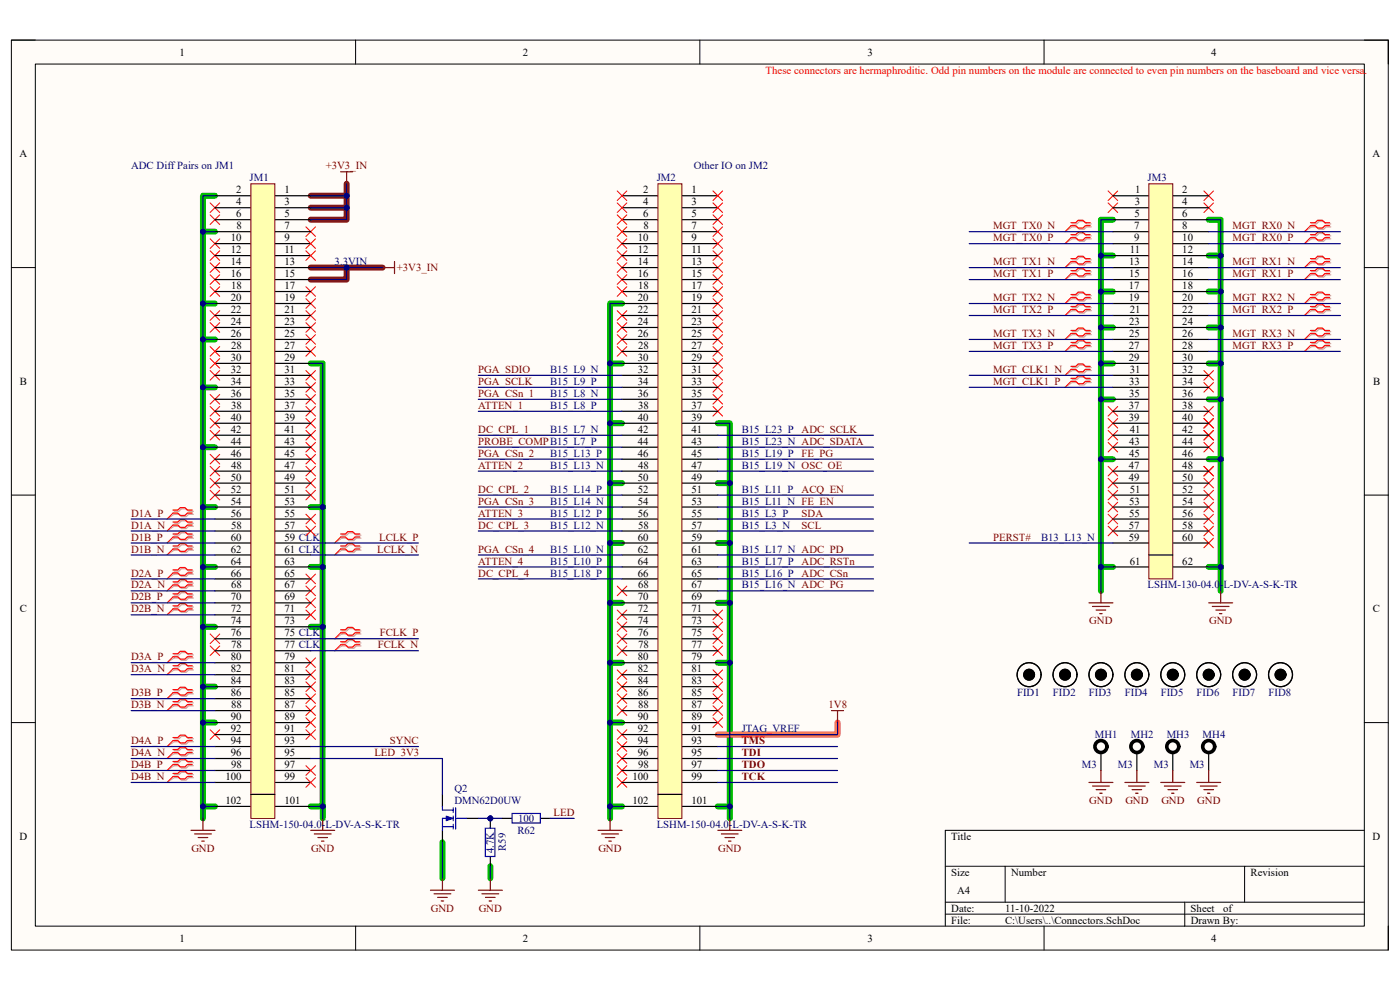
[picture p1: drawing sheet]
<svg xmlns="http://www.w3.org/2000/svg" width="297mm" height="210mm" viewBox="0 0 297 210" stroke-linecap="round" stroke-linejoin="round" font-family="sans-serif">
<defs><g id="words">
<g font-size="2.3">
<text x="38.1" y="11.8">1</text>
<text x="110.9" y="11.8">2</text>
<text x="184" y="11.8">3</text>
<text x="256.9" y="11.8">4</text>
<text x="4.1" y="33.4">A</text>
<text x="291.2" y="33.4">A</text>
<text x="50.1" y="41">2</text>
<text x="60.3" y="41">1</text>
<text x="136.5" y="41">2</text>
<text x="146.7" y="41">1</text>
<text x="240.8" y="41">1</text>
<text x="250.8" y="41">2</text>
<text x="50.1" y="43.6">4</text>
<text x="50.1" y="46.1">6</text>
<text x="60.3" y="43.6">3</text>
<text x="60.3" y="46.1">5</text>
<text x="136.5" y="43.6">4</text>
<text x="136.5" y="46.1">6</text>
<text x="146.7" y="43.6">3</text>
<text x="146.7" y="46.1">5</text>
<text x="240.7" y="46.1">5</text>
<text x="240.7" y="43.6">3</text>
<text x="250.8" y="43.6">4</text>
<text x="250.8" y="46.1">6</text>
<text x="49" y="51.2">10</text>
<text x="49" y="53.7">12</text>
<text x="50.2" y="48.6">8</text>
<text x="60.3" y="48.6">7</text>
<text x="60.3" y="51.2">9</text>
<text x="60.3" y="53.7">11</text>
<text x="135.3" y="51.2">10</text>
<text x="135.3" y="53.7">12</text>
<text x="136.5" y="48.6">8</text>
<text x="146.7" y="48.6">7</text>
<text x="146.7" y="51.2">9</text>
<text x="146.7" y="53.7">11</text>
<text x="239.7" y="53.7">11</text>
<text x="240.6" y="48.6">7</text>
<text x="240.6" y="51.2">9</text>
<text x="250.8" y="48.6">8</text>
<text x="250.8" y="51.2">10</text>
<text x="250.8" y="53.7">12</text>
<text x="49" y="56.3">14</text>
<text x="49" y="58.8">16</text>
<text x="60.3" y="56.3">13</text>
<text x="60.3" y="58.8">15</text>
<text x="135.3" y="56.3">14</text>
<text x="135.3" y="58.8">16</text>
<text x="146.7" y="56.3">13</text>
<text x="146.7" y="58.8">15</text>
<text x="239.6" y="56.3">13</text>
<text x="239.6" y="58.8">15</text>
<text x="250.8" y="56.3">14</text>
<text x="250.8" y="58.8">16</text>
<text x="49" y="63.9">20</text>
<text x="49" y="61.3">18</text>
<text x="60.3" y="61.3">17</text>
<text x="60.3" y="63.9">19</text>
<text x="135.3" y="63.9">20</text>
<text x="135.4" y="61.3">18</text>
<text x="146.7" y="61.3">17</text>
<text x="146.7" y="63.9">19</text>
<text x="239.5" y="61.3">17</text>
<text x="239.5" y="63.9">19</text>
<text x="250.8" y="61.3">18</text>
<text x="250.8" y="63.9">20</text>
<text x="49" y="66.4">22</text>
<text x="49" y="69">24</text>
<text x="49" y="71.5">26</text>
<text x="60.3" y="66.4">21</text>
<text x="60.3" y="69">23</text>
<text x="60.3" y="71.5">25</text>
<text x="135.3" y="66.4">22</text>
<text x="135.3" y="69">24</text>
<text x="135.3" y="71.5">26</text>
<text x="146.7" y="66.4">21</text>
<text x="146.7" y="69">23</text>
<text x="146.7" y="71.5">25</text>
<text x="239.6" y="69">23</text>
<text x="239.6" y="71.5">25</text>
<text x="239.7" y="66.4">21</text>
<text x="250.8" y="66.4">22</text>
<text x="250.8" y="69">24</text>
<text x="250.8" y="71.5">26</text>
<text x="49" y="76.6">30</text>
<text x="49" y="74">28</text>
<text x="60.3" y="74">27</text>
<text x="60.3" y="76.6">29</text>
<text x="135.3" y="76.6">30</text>
<text x="135.4" y="74">28</text>
<text x="146.7" y="74">27</text>
<text x="146.7" y="76.6">29</text>
<text x="239.5" y="74">27</text>
<text x="239.5" y="76.6">29</text>
<text x="250.8" y="74">28</text>
<text x="250.8" y="76.6">30</text>
<text x="4.2" y="81.7">B</text>
<text x="49" y="79.1">32</text>
<text x="49" y="81.7">34</text>
<text x="60.3" y="79.1">31</text>
<text x="60.3" y="81.7">33</text>
<text x="135.3" y="79.1">32</text>
<text x="135.3" y="81.7">34</text>
<text x="146.7" y="79.1">31</text>
<text x="146.7" y="81.7">33</text>
<text x="239.6" y="81.7">33</text>
<text x="239.7" y="79.1">31</text>
<text x="250.8" y="79.1">32</text>
<text x="250.8" y="81.7">34</text>
<text x="291.3" y="81.7">B</text>
<text x="49" y="84.2">36</text>
<text x="49" y="89.3">40</text>
<text x="49" y="86.7">38</text>
<text x="60.3" y="84.2">35</text>
<text x="60.3" y="86.7">37</text>
<text x="60.3" y="89.3">39</text>
<text x="135.3" y="84.2">36</text>
<text x="135.3" y="89.3">40</text>
<text x="135.4" y="86.7">38</text>
<text x="146.7" y="84.2">35</text>
<text x="146.7" y="86.7">37</text>
<text x="146.7" y="89.3">39</text>
<text x="239.5" y="86.7">37</text>
<text x="239.5" y="89.3">39</text>
<text x="239.6" y="84.2">35</text>
<text x="250.8" y="84.2">36</text>
<text x="250.8" y="86.7">38</text>
<text x="250.8" y="89.3">40</text>
<text x="49" y="91.8">42</text>
<text x="49" y="94.4">44</text>
<text x="60.3" y="91.8">41</text>
<text x="60.3" y="94.4">43</text>
<text x="135.3" y="91.8">42</text>
<text x="135.3" y="94.4">44</text>
<text x="146.7" y="91.8">41</text>
<text x="146.7" y="94.4">43</text>
<text x="239.6" y="94.4">43</text>
<text x="239.7" y="91.8">41</text>
<text x="250.8" y="91.8">42</text>
<text x="250.8" y="94.4">44</text>
<text x="49" y="96.9">46</text>
<text x="49" y="102">50</text>
<text x="49" y="99.4">48</text>
<text x="60.3" y="96.9">45</text>
<text x="60.3" y="99.4">47</text>
<text x="60.3" y="102">49</text>
<text x="135.3" y="96.9">46</text>
<text x="135.3" y="102">50</text>
<text x="135.4" y="99.4">48</text>
<text x="146.7" y="96.9">45</text>
<text x="146.7" y="99.4">47</text>
<text x="146.7" y="102">49</text>
<text x="239.5" y="99.4">47</text>
<text x="239.5" y="102">49</text>
<text x="239.6" y="96.9">45</text>
<text x="250.8" y="96.9">46</text>
<text x="250.8" y="99.4">48</text>
<text x="250.8" y="102">50</text>
<text x="49" y="104.5">52</text>
<text x="49" y="107.1">54</text>
<text x="60.3" y="104.5">51</text>
<text x="60.3" y="107.1">53</text>
<text x="135.3" y="104.5">52</text>
<text x="135.3" y="107.1">54</text>
<text x="146.7" y="104.5">51</text>
<text x="146.7" y="107.1">53</text>
<text x="239.6" y="107.1">53</text>
<text x="239.7" y="104.5">51</text>
<text x="250.8" y="104.5">52</text>
<text x="250.8" y="107.1">54</text>
<text x="49" y="109.6">56</text>
<text x="49" y="112.1">58</text>
<text x="60.3" y="109.6">55</text>
<text x="60.3" y="112.1">57</text>
<text x="135.3" y="109.6">56</text>
<text x="135.4" y="112.1">58</text>
<text x="146.7" y="109.6">55</text>
<text x="146.7" y="112.1">57</text>
<text x="239.5" y="112.1">57</text>
<text x="239.6" y="109.6">55</text>
<text x="250.8" y="109.6">56</text>
<text x="250.8" y="112.1">58</text>
<text x="49" y="114.7">60</text>
<text x="49" y="117.2">62</text>
<text x="49" y="119.8">64</text>
<text x="60.3" y="114.7">59 CLK</text>
<text x="60.3" y="117.2">61 CLK</text>
<text x="60.3" y="119.8">63</text>
<text x="135.3" y="114.7">60</text>
<text x="135.3" y="117.2">62</text>
<text x="135.3" y="119.8">64</text>
<text x="146.7" y="114.7">59</text>
<text x="146.7" y="117.2">61</text>
<text x="146.7" y="119.8">63</text>
<text x="239.5" y="114.7">59</text>
<text x="239.7" y="119.8">61</text>
<text x="250.8" y="114.7">60</text>
<text x="250.8" y="119.8">62</text>
<text x="49" y="122.3">66</text>
<text x="49" y="124.8">68</text>
<text x="60.3" y="122.3">65</text>
<text x="60.3" y="124.8">67</text>
<text x="135.3" y="122.3">66</text>
<text x="135.4" y="124.8">68</text>
<text x="146.7" y="122.3">65</text>
<text x="146.7" y="124.8">67</text>
<text x="4.2" y="129.9">C</text>
<text x="49" y="127.4">70</text>
<text x="49" y="129.9">72</text>
<text x="60.3" y="127.4">69</text>
<text x="60.3" y="129.9">71</text>
<text x="135.3" y="127.4">70</text>
<text x="135.3" y="129.9">72</text>
<text x="146.7" y="127.4">69</text>
<text x="146.7" y="129.9">71</text>
<text x="291.3" y="129.9">C</text>
<text x="49" y="132.5">74</text>
<text x="49" y="135">76</text>
<text x="49" y="137.5">78</text>
<text x="60.3" y="132.5">73</text>
<text x="60.3" y="135">75 CLK</text>
<text x="60.3" y="137.5">77 CLK</text>
<text x="135.3" y="132.5">74</text>
<text x="135.3" y="135">76</text>
<text x="135.4" y="137.5">78</text>
<text x="146.7" y="132.5">73</text>
<text x="146.7" y="135">75</text>
<text x="146.7" y="137.5">77</text>
<text x="49" y="140.1">80</text>
<text x="49" y="142.6">82</text>
<text x="60.3" y="140.1">79</text>
<text x="60.3" y="142.6">81</text>
<text x="135.3" y="140.1">80</text>
<text x="135.3" y="142.6">82</text>
<text x="146.7" y="140.1">79</text>
<text x="146.7" y="142.6">81</text>
<text x="49" y="145.2">84</text>
<text x="49" y="147.7">86</text>
<text x="60.3" y="145.2">83</text>
<text x="60.3" y="147.7">85</text>
<text x="135.3" y="145.2">84</text>
<text x="135.3" y="147.7">86</text>
<text x="146.7" y="145.2">83</text>
<text x="146.7" y="147.7">85</text>
<text x="49" y="152.8">90</text>
<text x="49" y="155.3">92</text>
<text x="49" y="150.2">88</text>
<text x="60.3" y="150.2">87</text>
<text x="60.3" y="152.8">89</text>
<text x="60.3" y="155.3">91</text>
<text x="135.3" y="152.8">90</text>
<text x="135.3" y="155.3">92</text>
<text x="135.4" y="150.2">88</text>
<text x="146.7" y="150.2">87</text>
<text x="146.7" y="152.8">89</text>
<text x="146.7" y="155.3">91</text>
<text x="49" y="157.9">94</text>
<text x="49" y="160.4">96</text>
<text x="60.3" y="157.9">93</text>
<text x="60.3" y="160.4">95</text>
<text x="135.3" y="157.9">94</text>
<text x="135.3" y="160.4">96</text>
<text x="146.7" y="157.9">93</text>
<text x="146.7" y="160.4">95</text>
<text x="47.8" y="165.5">100</text>
<text x="49" y="162.9">98</text>
<text x="60.3" y="162.9">97</text>
<text x="60.3" y="165.5">99</text>
<text x="134.2" y="165.5">100</text>
<text x="135.4" y="162.9">98</text>
<text x="146.7" y="162.9">97</text>
<text x="146.7" y="165.5">99</text>
<text x="47.8" y="170.6">102</text>
<text x="60.3" y="170.6">101</text>
<text x="134.2" y="170.6">102</text>
<text x="146.7" y="170.6">101</text>
<text x="4.1" y="178.2">D</text>
<text x="201.8" y="178.2">Title</text>
<text x="291.2" y="178.2">D</text>
<text x="201.8" y="185.8">Size</text>
<text x="214.5" y="185.8">Number</text>
<text x="265.3" y="185.8">Revision</text>
<text x="203.1" y="189.6">A4</text>
<text x="201.8" y="193.4">Date:</text>
<text x="201.8" y="196">File:</text>
<text x="213.2" y="196">C:\Users\..\Connectors.SchDoc</text>
<text x="213.2" y="193.4">11-10-2022</text>
<text x="252.6" y="193.4">Sheet</text>
<text x="252.6" y="196">Drawn By:</text>
<text x="259.5" y="193.4">of</text>
<text x="38.1" y="199.8">1</text>
<text x="110.9" y="199.8">2</text>
<text x="184" y="199.8">3</text>
<text x="256.9" y="199.8">4</text>
</g>
<text font-size="2.3" fill="#f00" x="162.4" y="15.6">These connectors are hermaphroditic. Odd pin numbers on the module are connected to even pin numbers on the baseboard and vice versa.</text>
<g font-size="2.3" fill="#000080">
<text x="27.8" y="35.9">ADC Diff Pairs on JM1</text>
<text x="147.2" y="35.9">Other IO on JM2</text>
<text x="53" y="38.5">JM1</text>
<text x="139.3" y="38.5">JM2</text>
<text x="243.5" y="38.5">JM3</text>
<text x="71" y="56.3">3.3VIN</text>
<text x="116.7" y="79.1">B15_L9_N</text>
<text x="116.7" y="81.7">B15_L9_P</text>
<text x="116.7" y="84.2">B15_L8_N</text>
<text x="116.7" y="86.7">B15_L8_P</text>
<text x="116.7" y="91.8">B15_L7_N</text>
<text x="157.4" y="91.8">B15_L23_P</text>
<text x="157.4" y="94.4">B15_L23_N ADC_SDATA</text>
<text x="116.7" y="96.9">B15_L13_P</text>
<text x="116.7" y="99.4">B15_L13_N</text>
<text x="157.4" y="96.9">B15_L19_P</text>
<text x="157.4" y="99.4">B15_L19_N OSC_OE</text>
<text x="116.7" y="104.5">B15_L14_P</text>
<text x="116.7" y="107.1">B15_L14_N</text>
<text x="157.4" y="104.5">B15_L11_P</text>
<text x="157.4" y="107.1">B15_L11_N FE_EN</text>
<text x="116.7" y="109.6">B15_L12_P</text>
<text x="116.7" y="112.1">B15_L12_N</text>
<text x="157.4" y="109.6">B15_L3_P</text>
<text x="157.4" y="112.1">B15_L3_N</text>
<text x="116.7" y="117.2">B15_L10_N</text>
<text x="116.7" y="119.8">B15_L10_P</text>
<text x="157.4" y="117.2">B15_L17_N ADC_PD</text>
<text x="157.4" y="119.8">B15_L17_P</text>
<text x="220.9" y="114.7">B13_L13_N</text>
<text x="116.7" y="122.3">B15_L18_P</text>
<text x="157.4" y="122.3">B15_L16_P</text>
<text x="157.4" y="124.8">B15_L16_N ADC_PG</text>
<text x="243.5" y="124.8">LSHM-130-04.0-L-DV-A-S-K-TR</text>
<text x="215.8" y="147.7">FID1</text>
<text x="223.4" y="147.7">FID2</text>
<text x="231" y="147.7">FID3</text>
<text x="238.6" y="147.7">FID4</text>
<text x="246.3" y="147.7">FID5</text>
<text x="253.9" y="147.7">FID6</text>
<text x="261.5" y="147.7">FID7</text>
<text x="269.1" y="147.7">FID8</text>
<text x="157.4" y="155.3">JTAG_VREF</text>
<text x="232.3" y="156.6">MH1</text>
<text x="239.9" y="156.6">MH2</text>
<text x="247.5" y="156.6">MH3</text>
<text x="255.1" y="156.6">MH4</text>
<text x="229.5" y="162.9">M3</text>
<text x="237.2" y="162.9">M3</text>
<text x="244.8" y="162.9">M3</text>
<text x="252.4" y="162.9">M3</text>
<text x="96.4" y="168">Q2</text>
<text x="96.4" y="170.6">DMN62D0UW</text>
<text x="53" y="175.6">LSHM-150-04.0-L-DV-A-S-K-TR</text>
<text x="109.8" y="176.9">R62</text>
<text x="109.9" y="174.4">100</text>
<text x="139.3" y="175.6">LSHM-150-04.0-L-DV-A-S-K-TR</text>
<text x="104.8" y="181" transform="rotate(-90 104.8 181)">4.7K</text>
<text x="107.3" y="180.6" transform="rotate(-90 107.3 180.6)">R59</text>
</g>
<g font-size="2.3" fill="#800000">
<text x="69.1" y="35.9">+3V3_IN</text>
<text x="210.7" y="48.6">MGT_TX0_N</text>
<text x="210.7" y="51.2">MGT_TX0_P</text>
<text x="261.5" y="48.6">MGT_RX0_N</text>
<text x="261.5" y="51.2">MGT_RX0_P</text>
<text x="84.2" y="57.5">+3V3_IN</text>
<text x="210.7" y="56.3">MGT_TX1_N</text>
<text x="210.7" y="58.8">MGT_TX1_P</text>
<text x="261.5" y="56.3">MGT_RX1_N</text>
<text x="261.5" y="58.8">MGT_RX1_P</text>
<text x="210.7" y="63.9">MGT_TX2_N</text>
<text x="261.5" y="63.9">MGT_RX2_N</text>
<text x="210.7" y="71.5">MGT_TX3_N</text>
<text x="210.7" y="66.4">MGT_TX2_P</text>
<text x="261.5" y="66.4">MGT_RX2_P</text>
<text x="261.5" y="71.5">MGT_RX3_N</text>
<text x="210.7" y="74">MGT_TX3_P</text>
<text x="261.5" y="74">MGT_RX3_P</text>
<text x="101.5" y="79.1">PGA_SDIO</text>
<text x="101.5" y="81.7">PGA_SCLK</text>
<text x="210.7" y="79.1">MGT_CLK1_N</text>
<text x="210.7" y="81.7">MGT_CLK1_P</text>
<text x="101.5" y="84.2">PGA_CSn_1</text>
<text x="101.5" y="86.7">ATTEN_1</text>
<text x="101.5" y="91.8">DC_CPL_1</text>
<text x="101.5" y="94.4">PROBE_COMPB15_L7_P</text>
<text x="170.1" y="91.8">ADC_SCLK</text>
<text x="101.5" y="96.9">PGA_CSn_2</text>
<text x="101.5" y="99.4">ATTEN_2</text>
<text x="170.1" y="96.9">FE_PG</text>
<text x="101.5" y="104.5">DC_CPL_2</text>
<text x="101.5" y="107.1">PGA_CSn_3</text>
<text x="170.1" y="104.5">ACQ_EN</text>
<text x="27.8" y="109.6">D1A_P</text>
<text x="27.8" y="112.1">D1A_N</text>
<text x="101.5" y="109.6">ATTEN_3</text>
<text x="101.5" y="112.1">DC_CPL_3</text>
<text x="170.1" y="109.6">SDA</text>
<text x="170.1" y="112.1">SCL</text>
<text x="27.8" y="114.7">D1B_P</text>
<text x="27.8" y="117.2">D1B_N</text>
<text x="80" y="117.2">LCLK_N</text>
<text x="80.4" y="114.7">LCLK_P</text>
<text x="101.5" y="117.2">PGA_CSn_4</text>
<text x="101.5" y="119.8">ATTEN_4</text>
<text x="170.1" y="119.8">ADC_RSTn</text>
<text x="210.7" y="114.7">PERST#</text>
<text x="27.8" y="122.3">D2A_P</text>
<text x="27.8" y="124.8">D2A_N</text>
<text x="101.5" y="122.3">DC_CPL_4</text>
<text x="170.1" y="122.3">ADC_CSn</text>
<text x="27.8" y="127.4">D2B_P</text>
<text x="27.8" y="129.9">D2B_N</text>
<text x="80.1" y="137.5">FCLK_N</text>
<text x="80.6" y="135">FCLK_P</text>
<text x="231.1" y="132.5">GND</text>
<text x="256.5" y="132.5">GND</text>
<text x="27.8" y="140.1">D3A_P</text>
<text x="27.8" y="142.6">D3A_N</text>
<text x="27.8" y="147.7">D3B_P</text>
<text x="27.8" y="150.2">D3B_N</text>
<text x="175.8" y="150.2">1V8</text>
<text x="27.8" y="157.9">D4A_P</text>
<text x="27.8" y="160.4">D4A_N</text>
<text x="79.4" y="160.4">LED_3V3</text>
<text x="82.7" y="157.9">SYNC</text>
<text x="157.4" y="160.4">TDI</text>
<text x="157.4" y="157.9">TMS</text>
<text x="27.8" y="162.9">D4B_P</text>
<text x="27.8" y="165.5">D4B_N</text>
<text x="157.4" y="165.5">TCK</text>
<text x="157.4" y="162.9">TDO</text>
<text x="117.4" y="173.1">LED</text>
<text x="231.1" y="170.6">GND</text>
<text x="238.8" y="170.6">GND</text>
<text x="246.4" y="170.6">GND</text>
<text x="254" y="170.6">GND</text>
<text x="40.6" y="180.7">GND</text>
<text x="66" y="180.7">GND</text>
<text x="127" y="180.7">GND</text>
<text x="152.4" y="180.7">GND</text>
<text x="91.4" y="193.4">GND</text>
<text x="101.6" y="193.4">GND</text>
</g>
</g></defs>
<path d="M2.4 8.5h292.1v193h-292.1z" fill-rule="evenodd" fill="#fffcf8"/>
<path d="M2.4 8.5h292.1v193h-292.1z" fill="none" stroke="#000" stroke-width=".21"/>
<path d="M7.5 13.6h281.9v182.9h-281.9z" fill-rule="evenodd" fill="#fffcf8"/>
<g fill="none" stroke="#000" stroke-width=".21">
<path d="M2.4 8.5h5.1M7.5 13.6h281.9v182.9h-281.9zM75.4 8.5v5.1M148.5 8.5v5.1M221.5 8.5v5.1M289.4 8.5h5.1v5.1M2.4 56.8h5.1M289.4 56.8h5.1M2.4 105h5.1M289.4 105h5.1M2.4 153.3h5.1M289.4 153.3h5.1"/>
<path d="M289.4 176.1h-88.9v20.4M75.4 196.5v5M148.5 196.5v5M200.5 183.8h88.9M200.5 191.4h88.9M200.5 193.9h88.9M213.2 183.8v7.6M221.5 196.5v5M251.3 191.4v5.1M264 183.8v7.6M294.5 196.5v5"/>
</g>
<g fill="none" stroke="#00be00" stroke-width="1.3">
<path d="M43.1 49.1h2.5M45.6 41.5h-2.5v129.6M233.6 54.2h2.5M236.1 46.6h-2.5v73.7M256.4 54.2h2.6M256.4 46.6h2.6v73.7M43.1 64.4h2.5M43.1 72h2.5M65.9 77.1h2.6v30.5h-2.6M129.4 77.1h2.6M132 64.4h-2.6v106.7M233.6 77.1h2.5"/>
<path d="M233.6 61.8h2.5M233.6 69.5h2.5M256.4 77.1h2.6M256.4 61.8h2.6M256.4 69.5h2.6M43.1 82.2h2.5M43.1 94.9h2.5M129.4 89.8h2.6M152.3 89.8h2.5v81.3M233.6 84.7h2.5M233.6 97.4h2.5M256.4 84.7h2.6"/>
<path d="M256.4 97.4h2.6M43.1 107.6h2.5M68.5 107.6v12.7h-2.6M129.4 102.5h2.6M129.4 115.2h2.6M152.3 102.5h2.5M152.3 115.2h2.5M43.1 120.3h2.5M43.1 133h2.5M68.5 120.3v12.7h-2.6M68.5 133v38.1M129.4 127.9h2.6"/>
<path d="M152.3 127.9h2.5M236.1 120.3h-2.5v5M256.4 120.3h2.6v5M43.1 145.7h2.5M43.1 153.3h2.5M129.4 153.3h2.6M129.4 140.6h2.6M152.3 140.6h2.5M45.6 171.1h-2.5v2.5M65.9 171.1h2.6v2.5M93.9 178.7v7.6M132 171.1h-2.6v2.5"/>
<path d="M152.3 171.1h2.5v2.5M104 183.8v2.5"/>
</g>
<path d="M73.5 39v7.6h-7.6M65.9 56.8h15.3M65.9 44.1h7.6M65.9 41.5h7.6M73.5 56.8v2.5h-7.6" fill="none" stroke="#781915" stroke-width="1.3"/>
<path d="M177.7 153.3v2.5h-25.4" fill="none" stroke="#fd8300" stroke-width="1.3"/>
<g fill="none" stroke="#800000" stroke-width=".25">
<path d="M72.3 36.4h2.5M73.5 36.4v2.6M231 127.9h5.1M231.8 128.7h3.5M232.5 129.4h2.1M233.3 130.2h.5M233.6 125.3v2.6M256.4 127.9h5.1M257.2 128.7h3.5M257.9 129.4h2.1M258.7 130.2h.5M259 125.3v2.6"/>
<path d="M40.5 176.1h5.1M41.3 176.9h3.5M42 177.7h2.1M42.8 178.4h.5M43.1 173.6v2.5M65.9 176.1h5.1M66.7 176.9h3.5M67.4 177.7h2.1M68.2 178.4h.5M68.5 173.6v2.5M126.9 176.1h5.1M127.6 176.9h3.6"/>
<path d="M128.4 177.7h2M129.2 178.4h.5M129.4 173.6v2.5M152.3 176.1h5.1M153 176.9h3.6M153.8 177.7h2M154.6 178.4h.5M154.8 173.6v2.5"/>
</g>
<g fill="none" stroke="#f00" stroke-width=".21">
<path d="M44.6 43l2 2.1M44.6 45.6l2 2M44.6 50.7l2 2M44.6 53.2l2 2M44.6 58.3l2 2M44.6 55.7l2 2.1M46.6 43l-2 2.1M46.6 45.6l-2 2M46.6 50.7l-2 2M46.6 53.2l-2 2M46.6 58.3l-2 2M46.6 55.7l-2 2.1"/>
<path d="M64.9 48.1l2 2.1M66.9 48.1l-2 2.1M130.9 50.7l2.1 2M130.9 55.7l2.1 2.1M130.9 58.3l2.1 2M130.9 53.2l2.1 2M133 50.7l-2.1 2M133 55.7l-2.1 2.1M133 58.3l-2.1 2M133 53.2l-2.1 2M151.3 45.6l2 2M151.3 53.2l2 2"/>
<path d="M151.3 55.7l2 2.1M151.3 58.3l2 2M153.3 53.2l-2 2M153.3 45.6l-2 2M153.3 55.7l-2 2.1M153.3 58.3l-2 2M227.2 47.9l-1.3 1.2M235.1 40.5l2 2M235.1 43.1l2 2M237.1 40.5l-2 2M237.1 43.1l-2 2M255.4 40.5l2 2"/>
<path d="M255.4 43.1l2 2M257.4 40.5l-2 2M257.4 43.1l-2 2M44.6 60.8l2 2.1M44.6 65.9l2 2M44.6 68.5l2 2M44.6 78.6l2 2M46.6 60.8l-2 2.1M46.6 65.9l-2 2M46.6 68.5l-2 2M46.6 78.6l-2 2M64.9 60.8l2 2.1"/>
<path d="M64.9 63.4l2 2M64.9 65.9l2 2M64.9 68.5l2 2M64.9 71l2 2M64.9 73.5l2 2.1M64.9 78.6l2 2M66.9 60.8l-2 2.1M66.9 63.4l-2 2M66.9 65.9l-2 2M66.9 68.5l-2 2M66.9 71l-2 2M66.9 73.5l-2 2.1"/>
<path d="M66.9 78.6l-2 2M130.9 65.9l2.1 2M130.9 68.5l2.1 2M130.9 71l2.1 2M130.9 73.5l2.1 2.1M133 73.5l-2.1 2.1M133 65.9l-2.1 2M133 68.5l-2.1 2M133 71l-2.1 2M151.3 63.4l2 2M151.3 76.1l2 2M151.3 60.8l2 2.1"/>
<path d="M151.3 65.9l2 2M151.3 68.5l2 2M151.3 71l2 2M151.3 73.5l2 2.1M151.3 78.6l2 2M153.3 63.4l-2 2M153.3 76.1l-2 2M153.3 60.8l-2 2.1M153.3 65.9l-2 2M153.3 68.5l-2 2M153.3 71l-2 2M153.3 73.5l-2 2.1"/>
<path d="M153.3 78.6l-2 2M255.4 78.6l2 2M257.4 78.6l-2 2M44.6 83.7l2 2M44.6 86.2l2 2.1M44.6 88.8l2 2M44.6 91.3l2 2M44.6 96.4l2 2M44.6 98.9l2 2.1M46.6 83.7l-2 2M46.6 86.2l-2 2.1M46.6 88.8l-2 2"/>
<path d="M46.6 91.3l-2 2M46.6 96.4l-2 2M46.6 98.9l-2 2.1M64.9 81.2l2 2M64.9 83.7l2 2M64.9 88.8l2 2M64.9 86.2l2 2.1M64.9 91.3l2 2M64.9 93.9l2 2M64.9 96.4l2 2M64.9 98.9l2 2.1M66.9 81.2l-2 2"/>
<path d="M66.9 83.7l-2 2M66.9 88.8l-2 2M66.9 86.2l-2 2.1M66.9 91.3l-2 2M66.9 93.9l-2 2M66.9 96.4l-2 2M66.9 98.9l-2 2.1M151.3 86.2l2 2.1M151.3 81.2l2 2M151.3 83.7l2 2M153.3 81.2l-2 2M153.3 83.7l-2 2"/>
<path d="M153.3 86.2l-2 2.1M235.1 86.2l2 2.1M235.1 88.8l2 2M235.1 91.3l2 2M235.1 93.9l2 2M235.1 98.9l2 2.1M237.1 86.2l-2 2.1M237.1 88.8l-2 2M237.1 91.3l-2 2M237.1 93.9l-2 2M237.1 98.9l-2 2.1M255.4 86.2l2 2.1"/>
<path d="M255.4 88.8l2 2M255.4 91.3l2 2M255.4 93.9l2 2M255.4 98.9l2 2.1M255.4 81.2l2 2M257.4 88.8l-2 2M257.4 81.2l-2 2M257.4 86.2l-2 2.1M257.4 91.3l-2 2M257.4 93.9l-2 2M257.4 98.9l-2 2.1M44.6 101.5l2 2"/>
<path d="M44.6 104l2 2M46.6 101.5l-2 2M46.6 104l-2 2M64.9 109.1l2 2M64.9 111.6l2 2.1M64.9 101.5l2 2M64.9 104l2 2M66.9 101.5l-2 2M66.9 104l-2 2M66.9 109.1l-2 2M66.9 111.6l-2 2.1M235.1 109.1l2 2"/>
<path d="M235.1 101.5l2 2M235.1 104l2 2M235.1 106.6l2 2M237.1 109.1l-2 2M237.1 101.5l-2 2M237.1 104l-2 2M237.1 106.6l-2 2M255.4 109.1l2 2M255.4 111.6l2 2.1M255.4 114.2l2 2M255.4 101.5l2 2M255.4 106.6l2 2"/>
<path d="M255.4 104l2 2M257.4 109.1l-2 2M257.4 111.6l-2 2.1M257.4 114.2l-2 2M257.4 101.5l-2 2M257.4 106.6l-2 2M257.4 104l-2 2M44.6 134.5l2 2M44.6 137l2 2.1M46.6 134.5l-2 2M46.6 137l-2 2.1M64.9 139.6l2 2"/>
<path d="M64.9 121.8l2 2M64.9 124.3l2 2.1M64.9 126.9l2 2M66.9 139.6l-2 2M66.9 121.8l-2 2M66.9 124.3l-2 2.1M66.9 126.9l-2 2M130.9 124.3l2.1 2.1M130.9 129.4l2.1 2M130.9 132l2.1 2M130.9 134.5l2.1 2M130.9 137l2.1 2.1"/>
<path d="M133 124.3l-2.1 2.1M133 129.4l-2.1 2M133 132l-2.1 2M133 134.5l-2.1 2M133 137l-2.1 2.1M151.3 129.4l2 2M151.3 132l2 2M151.3 134.5l2 2M151.3 137l2 2.1M153.3 129.4l-2 2M153.3 134.5l-2 2M153.3 137l-2 2.1"/>
<path d="M153.3 132l-2 2M44.6 154.8l2 2M46.6 154.8l-2 2M64.9 142.1l2 2M64.9 144.7l2 2M64.9 147.2l2 2M64.9 149.7l2 2.1M66.9 142.1l-2 2M66.9 144.7l-2 2M66.9 147.2l-2 2M66.9 149.7l-2 2.1M130.9 142.1l2.1 2"/>
<path d="M130.9 144.7l2.1 2M130.9 147.2l2.1 2M130.9 149.7l2.1 2.1M130.9 154.8l2.1 2M130.9 157.4l2.1 2M130.9 159.9l2.1 2M133 142.1l-2.1 2M133 144.7l-2.1 2M133 147.2l-2.1 2M133 149.7l-2.1 2.1M133 154.8l-2.1 2M133 157.4l-2.1 2"/>
<path d="M133 159.9l-2.1 2M151.3 144.7l2 2M151.3 149.7l2 2.1M151.3 142.1l2 2M151.3 147.2l2 2M153.3 142.1l-2 2M153.3 144.7l-2 2M153.3 147.2l-2 2M153.3 149.7l-2 2.1M130.9 162.4l2.1 2.1M130.9 165l2.1 2M133 162.4l-2.1 2.1"/>
<path d="M133 165l-2.1 2"/>
</g>
<path d="M227.5 47.5h1l.5-.5h1l.5 .5h1M227.5 48.1h1l.5 .5h1l.5-.5h1" fill="none" stroke="#d0a19e" stroke-width=".25"/>
<path d="M227.5 48.1l-1.6 1" fill="none" stroke="#d0a19e" stroke-width=".21"/>
<path d="M227.2 47.2h1l.5-.5h1.1l.5 .5h1M227.2 47.9h1l.5 .5h1.1l.5-.5h1" fill="none" stroke="#f00" stroke-width=".25"/>
<g fill="none" stroke="#000" stroke-width=".25">
<path d="M45.6 41.5h7.6M45.6 44.1h7.6M45.6 46.6h7.6M45.6 49.1h7.6M45.6 51.7h7.6M45.6 54.2h7.6M45.6 56.8h7.6M45.6 59.3h7.6M58.3 41.5h7.6M58.3 44.1h7.6M58.3 46.6h7.6M58.3 49.1h7.6"/>
<path d="M58.3 51.7h7.6M58.3 54.2h7.6M58.3 56.8h7.6M58.3 59.3h7.6M45.6 61.8h7.6M45.6 64.4h7.6M45.6 66.9h7.6M45.6 69.5h7.6M45.6 72h7.6M45.6 74.5h7.6M45.6 77.1h7.6M45.6 79.6h7.6"/>
<path d="M58.3 61.8h7.6M58.3 64.4h7.6M58.3 66.9h7.6M58.3 69.5h7.6M58.3 72h7.6M58.3 74.5h7.6M58.3 77.1h7.6M58.3 79.6h7.6M45.6 82.2h7.6M45.6 84.7h7.6M45.6 87.2h7.6M45.6 89.8h7.6"/>
<path d="M45.6 92.3h7.6M45.6 94.9h7.6M45.6 97.4h7.6M45.6 99.9h7.6M58.3 82.2h7.6M58.3 84.7h7.6M58.3 87.2h7.6M58.3 89.8h7.6M58.3 92.3h7.6M58.3 94.9h7.6M58.3 97.4h7.6M58.3 99.9h7.6"/>
<path d="M45.6 102.5h7.6M45.6 105h7.6M45.6 107.6h7.6M45.6 110.1h7.6M45.6 112.6h7.6M45.6 115.2h7.6M45.6 117.7h7.6M58.3 102.5h7.6M58.3 105h7.6M58.3 107.6h7.6M58.3 110.1h7.6M58.3 112.6h7.6"/>
<path d="M58.3 115.2h7.6M58.3 117.7h7.6M45.6 120.3h7.6M45.6 122.8h7.6M45.6 125.3h7.6M45.6 127.9h7.6M45.6 130.4h7.6M45.6 133h7.6M45.6 135.5h7.6M45.6 138h7.6M58.3 120.3h7.6M58.3 122.8h7.6"/>
<path d="M58.3 125.3h7.6M58.3 127.9h7.6M58.3 130.4h7.6M58.3 133h7.6M58.3 135.5h7.6M58.3 138h7.6M45.6 140.6h7.6M45.6 143.1h7.6M45.6 145.7h7.6M45.6 148.2h7.6M45.6 150.7h7.6M45.6 153.3h7.6"/>
<path d="M45.6 155.8h7.6M45.6 158.4h7.6M58.3 140.6h7.6M58.3 143.1h7.6M58.3 145.7h7.6M58.3 148.2h7.6M58.3 150.7h7.6M58.3 153.3h7.6M58.3 155.8h7.6M58.3 158.4h7.6M45.6 160.9h7.6M45.6 163.4h7.6"/>
<path d="M45.6 166h7.6M45.6 171.1h7.6M58.3 160.9h7.6M58.3 163.4h7.6M58.3 166h7.6M58.3 171.1h7.6"/>
</g>
<path d="M53.2 39h5.1v134.6h-5.1z" fill-rule="evenodd" fill="#ffffb0"/>
<path d="M53.2 39h5.1v134.6h-5.1z" fill="none" stroke="#800000" stroke-width=".21"/>
<g fill="none" stroke="#000" stroke-width=".25">
<path d="M132 41.5h7.6M132 44.1h7.6M132 46.6h7.6M132 49.1h7.6M132 51.7h7.6M132 54.2h7.6M132 56.8h7.6M132 59.3h7.6M144.7 41.5h7.6M144.7 44.1h7.6M144.7 46.6h7.6M144.7 49.1h7.6"/>
<path d="M144.7 51.7h7.6M144.7 54.2h7.6M144.7 56.8h7.6M144.7 59.3h7.6M132 61.8h7.6M132 64.4h7.6M132 66.9h7.6M132 69.5h7.6M132 72h7.6M132 74.5h7.6M132 77.1h7.6M132 79.6h7.6"/>
<path d="M144.7 61.8h7.6M144.7 64.4h7.6M144.7 66.9h7.6M144.7 69.5h7.6M144.7 72h7.6M144.7 74.5h7.6M144.7 77.1h7.6M144.7 79.6h7.6M132 82.2h7.6M132 84.7h7.6M132 87.2h7.6M132 89.8h7.6"/>
<path d="M132 92.3h7.6M132 94.9h7.6M132 97.4h7.6M132 99.9h7.6M144.7 82.2h7.6M144.7 84.7h7.6M144.7 87.2h7.6M144.7 89.8h7.6M144.7 92.3h7.6M144.7 94.9h7.6M144.7 97.4h7.6M144.7 99.9h7.6"/>
<path d="M132 102.5h7.6M132 105h7.6M132 107.6h7.6M132 110.1h7.6M132 112.6h7.6M132 115.2h7.6M132 117.7h7.6M144.7 102.5h7.6M144.7 105h7.6M144.7 107.6h7.6M144.7 110.1h7.6M144.7 112.6h7.6"/>
<path d="M144.7 115.2h7.6M144.7 117.7h7.6M132 120.3h7.6M132 122.8h7.6M132 125.3h7.6M132 127.9h7.6M132 130.4h7.6M132 133h7.6M132 135.5h7.6M132 138h7.6M144.7 120.3h7.6M144.7 122.8h7.6"/>
<path d="M144.7 125.3h7.6M144.7 127.9h7.6M144.7 130.4h7.6M144.7 133h7.6M144.7 135.5h7.6M144.7 138h7.6M132 140.6h7.6M132 143.1h7.6M132 145.7h7.6M132 148.2h7.6M132 150.7h7.6M132 153.3h7.6"/>
<path d="M132 155.8h7.6M132 158.4h7.6M144.7 140.6h7.6M144.7 143.1h7.6M144.7 145.7h7.6M144.7 148.2h7.6M144.7 150.7h7.6M144.7 153.3h7.6M144.7 155.8h7.6M144.7 158.4h7.6M53.2 168.5h5.1M132 160.9h7.6"/>
<path d="M132 163.4h7.6M132 166h7.6M132 171.1h7.6M144.7 160.9h7.6M144.7 163.4h7.6M144.7 166h7.6M144.7 171.1h7.6"/>
</g>
<path d="M139.6 39h5.1v134.6h-5.1z" fill-rule="evenodd" fill="#ffffb0"/>
<path d="M139.6 39h5.1v134.6h-5.1z" fill="none" stroke="#800000" stroke-width=".21"/>
<g fill="none" stroke="#000" stroke-width=".25">
<path d="M236.1 41.5h7.6M236.1 44.1h7.6M236.1 46.6h7.6M236.1 49.1h7.6M236.1 51.7h7.6M236.1 54.2h7.6M236.1 56.8h7.6M236.1 59.3h7.6M248.8 41.5h7.6M248.8 44.1h7.6M248.8 46.6h7.6M248.8 49.1h7.6"/>
<path d="M248.8 51.7h7.6M248.8 54.2h7.6M248.8 56.8h7.6M248.8 59.3h7.6M236.1 61.8h7.6M236.1 64.4h7.6M236.1 66.9h7.6M236.1 69.5h7.6M236.1 72h7.6M236.1 74.5h7.6M236.1 77.1h7.6M236.1 79.6h7.6"/>
<path d="M248.8 61.8h7.6M248.8 64.4h7.6M248.8 66.9h7.6M248.8 69.5h7.6M248.8 72h7.6M248.8 74.5h7.6M248.8 77.1h7.6M248.8 79.6h7.6M236.1 82.2h7.6M236.1 84.7h7.6M236.1 87.2h7.6M236.1 89.8h7.6"/>
<path d="M236.1 92.3h7.6M236.1 94.9h7.6M236.1 97.4h7.6M236.1 99.9h7.6M248.8 82.2h7.6M248.8 84.7h7.6M248.8 87.2h7.6M248.8 89.8h7.6M248.8 92.3h7.6M248.8 94.9h7.6M248.8 97.4h7.6M248.8 99.9h7.6"/>
<path d="M236.1 102.5h7.6M236.1 105h7.6M236.1 107.6h7.6M236.1 110.1h7.6M236.1 112.6h7.6M236.1 115.2h7.6M248.8 102.5h7.6M248.8 105h7.6M248.8 107.6h7.6M248.8 110.1h7.6M248.8 112.6h7.6M248.8 115.2h7.6"/>
<path d="M236.1 120.3h7.6M248.8 120.3h7.6M233.6 159.6v3.8M241.2 159.6v3.8M248.8 159.6v3.8M256.4 159.6v3.8M139.6 168.5h5.1"/>
</g>
<g fill="none" stroke="#f00" stroke-width=".21">
<path d="M64.9 50.7l2 2M64.9 53.2l2 2M66.9 50.7l-2 2M66.9 53.2l-2 2M255.4 88.8l2 2M255.4 91.3l2 2M255.4 98.9l2 2.1M257.4 91.3l-2 2M257.4 88.8l-2 2M257.4 98.9l-2 2.1M235.1 111.6l2 2.1M237.1 111.6l-2 2.1"/>
<path d="M64.9 129.4l2 2M66.9 129.4l-2 2M64.9 154.8l2 2M66.9 154.8l-2 2M151.3 152.3l2 2M153.3 152.3l-2 2"/>
</g>
<g fill="none" stroke="#000" stroke-width=".76">
<circle cx="233.6" cy="158.4" r="1.27"/>
<circle cx="241.2" cy="158.4" r="1.27"/>
<circle cx="248.8" cy="158.4" r="1.27"/>
<circle cx="256.4" cy="158.4" r="1.27"/>
</g>
<g fill="none" stroke="#800000" stroke-width=".25">
<path d="M231 166h5.1M231.8 166.8h3.5M232.5 167.5h2.1M233.3 168.3h.5M233.6 163.4v2.6M238.6 166h5.1M239.4 166.8h3.6M240.2 167.5h2M240.9 168.3h.5M241.2 163.4v2.6M246.3 166h5M247 166.8h3.6"/>
<path d="M247.8 167.5h2M248.5 168.3h.6M248.8 163.4v2.6M253.9 166h5.1M254.6 166.8h3.6M255.4 167.5h2M256.2 168.3h.5M256.4 163.4v2.6"/>
</g>
<path d="M243.7 39h5.1v83.8h-5.1z" fill-rule="evenodd" fill="#ffffb0"/>
<path d="M243.7 39h5.1v83.8h-5.1z" fill="none" stroke="#800000" stroke-width=".21"/>
<g fill="none" stroke="#000" stroke-width=".25">
<path d="M243.7 117.7h5.1M93.9 168.5v2.6M93.9 176.1v2.6M98.9 173.6h2.6"/>
<circle cx="218.3" cy="143.1" r="2.54"/>
<circle cx="225.9" cy="143.1" r="2.54"/>
<circle cx="233.6" cy="143.1" r="2.54"/>
<circle cx="241.2" cy="143.1" r="2.54"/>
<circle cx="248.8" cy="143.1" r="2.54"/>
<circle cx="256.4" cy="143.1" r="2.54"/>
<circle cx="264" cy="143.1" r="2.54"/>
<circle cx="271.7" cy="143.1" r="2.54"/>
</g>
<g fill="none" stroke="#f00" stroke-width=".21">
<path d="M130.9 48.1l2.1 2.1M130.9 45.6l2.1 2M130.9 43l2.1 2.1M130.9 40.5l2.1 2M133 43l-2.1 2.1M133 48.1l-2.1 2.1M133 45.6l-2.1 2M133 40.5l-2.1 2M151.3 48.1l2 2.1M151.3 50.7l2 2M151.3 40.5l2 2M151.3 43l2 2.1"/>
<path d="M153.3 40.5l-2 2M153.3 48.1l-2 2.1M153.3 50.7l-2 2M153.3 43l-2 2.1M227.2 50.4l-1.3 1.3M227.2 55.5l-1.3 1.3M227.2 58l-1.3 1.3M278 47.9l-1.3 1.2M278 50.4l-1.3 1.3M278 55.5l-1.3 1.3M278 58l-1.3 1.3M44.6 73.5l2 2.1"/>
<path d="M44.6 76.1l2 2M46.6 73.5l-2 2.1M46.6 76.1l-2 2M130.9 60.8l2.1 2.1M133 60.8l-2.1 2.1M227.2 63.1l-1.3 1.3M227.2 65.7l-1.3 1.2M227.2 70.7l-1.3 1.3M227.2 73.3l-1.3 1.2M227.2 78.4l-1.3 1.2M278 63.1l-1.3 1.3M278 65.7l-1.3 1.2"/>
<path d="M278 70.7l-1.3 1.3M278 73.3l-1.3 1.2M227.2 80.9l-1.3 1.3M36.7 108.8l-1.3 1.3M36.7 111.4l-1.3 1.2M36.7 113.9l-1.3 1.3M36.7 116.5l-1.3 1.2M72.3 113.9l-1.3 1.3M72.3 116.5l-1.3 1.2M36.7 121.5l-1.3 1.3M36.7 124.1l-1.3 1.2M36.7 126.6l-1.3 1.3"/>
<path d="M36.7 129.2l-1.3 1.2M36.7 139.3l-1.3 1.3M72.3 134.2l-1.3 1.3M72.3 136.8l-1.3 1.2M36.7 157.1l-1.3 1.3M36.7 141.9l-1.3 1.2M36.7 146.9l-1.3 1.3M36.7 149.5l-1.3 1.2M36.7 159.6l-1.3 1.3M64.9 152.3l2 2M66.9 152.3l-2 2M36.7 162.2l-1.3 1.2"/>
<path d="M36.7 164.7l-1.3 1.3"/>
</g>
<path d="M81.2 56.8h2.5M83.7 55.5v2.5M176.4 150.7h2.6M177.7 150.7v2.6" fill="none" stroke="#800000" stroke-width=".25"/>
<g fill="none" stroke="#d0a19e" stroke-width=".25">
<path d="M227.5 50h1l.5-.5h1l.5 .5h1M227.5 50.7h1l.5 .5h1l.5-.5h1M227.5 55.1h1l.5-.5h1l.5 .5h1M227.5 55.8h1l.5 .5h1l.5-.5h1M227.5 57.7h1l.5-.6h1l.5 .6h1M227.5 58.3h1l.5 .5h1l.5-.5h1M278.3 47.5h1l.5-.5h1l.5 .5h1M278.3 48.1h1l.5 .5h1l.5-.5h1M278.3 50h1l.5-.5h1l.5 .5h1M278.3 50.7h1l.5 .5h1l.5-.5h1M278.3 55.1h1l.5-.5h1l.5 .5h1M278.3 55.8h1l.5 .5h1l.5-.5h1"/>
<path d="M278.3 57.7h1l.5-.6h1l.5 .6h1M278.3 58.3h1l.5 .5h1l.5-.5h1M227.5 62.7h1l.5-.5h1l.5 .5h1M227.5 63.4h1l.5 .5h1l.5-.5h1M227.5 65.3h1l.5-.5h1l.5 .5h1M227.5 65.9h1l.5 .5h1l.5-.5h1M227.5 70.4h1l.5-.6h1l.5 .6h1M227.5 71h1l.5 .5h1l.5-.5h1M227.5 72.9h1l.5-.5h1l.5 .5h1M227.5 73.5h1l.5 .5h1l.5-.5h1M227.5 78h1l.5-.5h1l.5 .5h1M227.5 78.6h1l.5 .5h1l.5-.5h1"/>
<path d="M278.3 62.7h1l.5-.5h1l.5 .5h1M278.3 63.4h1l.5 .5h1l.5-.5h1M278.3 65.3h1l.5-.5h1l.5 .5h1M278.3 65.9h1l.5 .5h1l.5-.5h1M278.3 70.4h1l.5-.6h1l.5 .6h1M278.3 71h1l.5 .5h1l.5-.5h1M278.3 72.9h1l.5-.5h1l.5 .5h1M278.3 73.5h1l.5 .5h1l.5-.5h1M227.5 80.5h1l.5-.5h1l.5 .5h1M227.5 81.2h1l.5 .5h1l.5-.5h1M37 108.5h1l.5-.6h1l.5 .6h1M37 109.1h1l.5 .5h1l.5-.5h1"/>
<path d="M37 111h1l.5-.5h1l.5 .5h1M37 111.6h1l.5 .5h1l.5-.5h1M37 113.5h1l.5-.5h1l.5 .5h1M37 114.2h1l.5 .5h1l.5-.5h1M37 116.1h1l.5-.5h1l.5 .5h1M37 116.7h1l.5 .5h1l.5-.5h1M72.5 113.5h1l.5-.5h1.1l.5 .5h1M72.5 114.2h1l.5 .5h1.1l.5-.5h1M72.5 116.1h1l.5-.5h1.1l.5 .5h1M72.5 116.7h1l.5 .5h1.1l.5-.5h1M37 121.2h1l.5-.6h1l.5 .6h1M37 121.8h1l.5 .5h1l.5-.5h1"/>
<path d="M37 123.7h1l.5-.5h1l.5 .5h1M37 124.3h1l.5 .5h1l.5-.5h1M37 126.2h1l.5-.5h1l.5 .5h1M37 126.9h1l.5 .5h1l.5-.5h1M37 128.8h1l.5-.5h1l.5 .5h1M37 129.4h1l.5 .5h1l.5-.5h1M37 138.9h1l.5-.5h1l.5 .5h1M37 139.6h1l.5 .5h1l.5-.5h1M72.5 133.9h1l.5-.6h1.1l.5 .6h1M72.5 134.5h1l.5 .5h1.1l.5-.5h1M72.5 136.4h1l.5-.5h1.1l.5 .5h1M72.5 137h1l.5 .5h1.1l.5-.5h1"/>
<path d="M37 141.5h1l.5-.5h1l.5 .5h1M37 142.1h1l.5 .5h1l.5-.5h1M37 146.6h1l.5-.6h1l.5 .6h1M37 147.2h1l.5 .5h1l.5-.5h1M37 149.1h1l.5-.5h1l.5 .5h1M37 149.7h1l.5 .5h1l.5-.5h1M37 156.7h1l.5-.5h1l.5 .5h1M37 157.4h1l.5 .5h1l.5-.5h1M37 159.3h1l.5-.6h1l.5 .6h1M37 159.9h1l.5 .5h1l.5-.5h1M37 161.8h1l.5-.5h1l.5 .5h1M37 162.4h1l.5 .5h1l.5-.5h1"/>
<path d="M37 164.3h1l.5-.5h1l.5 .5h1M37 165h1l.5 .5h1l.5-.5h1"/>
</g>
<g fill="none" stroke="#d0a19e" stroke-width=".21">
<path d="M227.5 50.7l-1.6 1M227.5 55.8l-1.6 1M227.5 58.3l-1.6 1M278.3 48.1l-1.6 1M278.3 50.7l-1.6 1M278.3 55.8l-1.6 1M278.3 58.3l-1.6 1M227.5 63.4l-1.6 1M227.5 65.9l-1.6 1M227.5 71l-1.6 1M227.5 73.5l-1.6 1M227.5 78.6l-1.6 1"/>
<path d="M278.3 63.4l-1.6 1M278.3 65.9l-1.6 1M278.3 71l-1.6 1M278.3 73.5l-1.6 1M227.5 81.2l-1.6 1M37 109.1l-1.6 1M37 111.6l-1.6 1M37 114.2l-1.6 1M37 116.7l-1.6 1M72.5 114.2l-1.5 1M72.5 116.7l-1.5 1M37 121.8l-1.6 1"/>
<path d="M37 124.3l-1.6 1M37 126.9l-1.6 1M37 129.4l-1.6 1M37 139.6l-1.6 1M72.5 134.5l-1.5 1M72.5 137l-1.5 1M37 142.1l-1.6 1M37 147.2l-1.6 1M37 149.7l-1.6 1M37 157.4l-1.6 1M37 159.9l-1.6 1M37 162.4l-1.6 1"/>
<path d="M37 165l-1.6 1"/>
</g>
<g fill="none" stroke="#f00" stroke-width=".25">
<path d="M227.2 49.8h1l.5-.5h1.1l.5 .5h1M227.2 50.4h1l.5 .5h1.1l.5-.5h1M227.2 54.9h1l.5-.5h1.1l.5 .5h1M227.2 55.5h1l.5 .5h1.1l.5-.5h1M227.2 57.4h1l.5-.5h1.1l.5 .5h1M227.2 58h1l.5 .5h1.1l.5-.5h1M278 47.2h1l.5-.5h1.1l.5 .5h1M278 47.9h1l.5 .5h1.1l.5-.5h1M278 49.8h1l.5-.5h1.1l.5 .5h1M278 50.4h1l.5 .5h1.1l.5-.5h1M278 54.9h1l.5-.5h1.1l.5 .5h1M278 55.5h1l.5 .5h1.1l.5-.5h1"/>
<path d="M278 57.4h1l.5-.5h1.1l.5 .5h1M278 58h1l.5 .5h1.1l.5-.5h1M227.2 62.5h1l.5-.5h1.1l.5 .5h1M227.2 63.1h1l.5 .5h1.1l.5-.5h1M227.2 65h1l.5-.5h1.1l.5 .5h1M227.2 65.7h1l.5 .5h1.1l.5-.5h1M227.2 70.1h1l.5-.5h1.1l.5 .5h1M227.2 70.7h1l.5 .5h1.1l.5-.5h1M227.2 72.6h1l.5-.5h1.1l.5 .5h1M227.2 73.3h1l.5 .5h1.1l.5-.5h1M227.2 77.7h1l.5-.5h1.1l.5 .5h1M227.2 78.4h1l.5 .5h1.1l.5-.5h1"/>
<path d="M278 62.5h1l.5-.5h1.1l.5 .5h1M278 63.1h1l.5 .5h1.1l.5-.5h1M278 65h1l.5-.5h1.1l.5 .5h1M278 65.7h1l.5 .5h1.1l.5-.5h1M278 70.1h1l.5-.5h1.1l.5 .5h1M278 70.7h1l.5 .5h1.1l.5-.5h1M278 72.6h1l.5-.5h1.1l.5 .5h1M278 73.3h1l.5 .5h1.1l.5-.5h1M227.2 80.3h1l.5-.5h1.1l.5 .5h1M227.2 80.9h1l.5 .5h1.1l.5-.5h1M36.7 108.2h1l.5-.5h1l.6 .5h1M36.7 108.8h1l.5 .5h1l.6-.5h1"/>
<path d="M36.7 110.7h1l.5-.5h1l.6 .5h1M36.7 111.4h1l.5 .5h1l.6-.5h1M36.7 113.3h1l.5-.5h1l.6 .5h1M36.7 113.9h1l.5 .5h1l.6-.5h1M36.7 115.8h1l.5-.5h1l.6 .5h1M36.7 116.5h1l.5 .5h1l.6-.5h1M72.3 113.3h1l.5-.5h1l.5 .5h1M72.3 113.9h1l.5 .5h1l.5-.5h1M72.3 115.8h1l.5-.5h1l.5 .5h1M72.3 116.5h1l.5 .5h1l.5-.5h1M36.7 120.9h1l.5-.5h1l.6 .5h1M36.7 121.5h1l.5 .5h1l.6-.5h1"/>
<path d="M36.7 123.4h1l.5-.5h1l.6 .5h1M36.7 124.1h1l.5 .5h1l.6-.5h1M36.7 126h1l.5-.5h1l.6 .5h1M36.7 126.6h1l.5 .5h1l.6-.5h1M36.7 128.5h1l.5-.5h1l.6 .5h1M36.7 129.2h1l.5 .5h1l.6-.5h1M36.7 138.7h1l.5-.5h1l.6 .5h1M36.7 139.3h1l.5 .5h1l.6-.5h1M72.3 133.6h1l.5-.5h1l.5 .5h1M72.3 134.2h1l.5 .5h1l.5-.5h1M72.3 136.1h1l.5-.5h1l.5 .5h1M72.3 136.8h1l.5 .5h1l.5-.5h1"/>
<path d="M36.7 141.2h1l.5-.5h1l.6 .5h1M36.7 141.9h1l.5 .5h1l.6-.5h1M36.7 146.3h1l.5-.5h1l.6 .5h1M36.7 146.9h1l.5 .5h1l.6-.5h1M36.7 148.8h1l.5-.5h1l.6 .5h1M36.7 149.5h1l.5 .5h1l.6-.5h1M36.7 156.5h1l.5-.5h1l.6 .5h1M36.7 157.1h1l.5 .5h1l.6-.5h1M36.7 159h1l.5-.5h1l.6 .5h1M36.7 159.6h1l.5 .5h1l.6-.5h1M36.7 161.5h1l.5-.5h1l.6 .5h1M36.7 162.2h1l.5 .5h1l.6-.5h1"/>
<path d="M36.7 164.1h1l.5-.5h1l.6 .5h1M36.7 164.7h1l.5 .5h1l.6-.5h1"/>
</g>
<g fill="none" stroke="#000" stroke-width="1.3">
<circle cx="218.3" cy="143.1" r=".63"/>
<circle cx="225.9" cy="143.1" r=".63"/>
<circle cx="233.6" cy="143.1" r=".63"/>
<circle cx="241.2" cy="143.1" r=".63"/>
<circle cx="248.8" cy="143.1" r=".63"/>
<circle cx="256.4" cy="143.1" r=".63"/>
<circle cx="264" cy="143.1" r=".63"/>
<circle cx="271.7" cy="143.1" r=".63"/>
</g>
<path d="M93.9 171.9h2.2M93.9 175.4h2.2M96.1 173.6h-2.2v2.5M96.1 171.4v1M96.1 173.1v1M96.1 174.9v1M96.7 173.6h2.2M96.7 171.4v4.5" fill="none" stroke="#00f" stroke-width=".25"/>
<path d="M94.7 173.1l1.4 .5-1.4 .5z" fill="#00f"/>
<path d="M94.7 173.1l1.4 .5-1.4 .5z" fill="none" stroke="#00f" stroke-width=".21"/>
<path d="M93.9 171.1v.7" fill="none" stroke="#00f" stroke-width=".25"/>
<path d="M91.3 188.8h5.1M92.1 189.6h3.5M92.8 190.4h2.1M93.6 191.1h.5M93.9 186.3v2.5" fill="none" stroke="#800000" stroke-width=".25"/>
<circle cx="104" cy="173.6" r=".51" fill="#000080"/>
<circle cx="104" cy="173.6" r=".51" fill="none" stroke="#000080" stroke-width=".21"/>
<path d="M104 173.6v2M104 181.8v2" fill="none" stroke="#000" stroke-width=".25"/>
<circle cx="104" cy="173.6" r=".51" fill="#000080"/>
<circle cx="104" cy="173.6" r=".51" fill="none" stroke="#000080" stroke-width=".21"/>
<path d="M103 175.7h2v6h-2z" fill="none" stroke="#00f" stroke-width=".25"/>
<path d="M101.5 188.8h5.1M102.2 189.6h3.6M103 190.4h2M103.8 191.1h.5M104 186.3v2.5" fill="none" stroke="#800000" stroke-width=".25"/>
<path d="M45.6 171.1h-2.5v2.5" fill="none" stroke="#000080" stroke-width=".25"/>
<circle cx="43.1" cy="171.1" r=".51" fill="#000080"/>
<circle cx="43.1" cy="171.1" r=".51" fill="none" stroke="#000080" stroke-width=".21"/>
<path d="M65.9 171.1h2.6v2.5" fill="none" stroke="#000080" stroke-width=".25"/>
<circle cx="68.5" cy="171.1" r=".51" fill="#000080"/>
<circle cx="68.5" cy="171.1" r=".51" fill="none" stroke="#000080" stroke-width=".21"/>
<path d="M132 171.1h-2.6v2.5" fill="none" stroke="#000080" stroke-width=".25"/>
<circle cx="129.4" cy="171.1" r=".51" fill="#000080"/>
<circle cx="129.4" cy="171.1" r=".51" fill="none" stroke="#000080" stroke-width=".21"/>
<path d="M152.3 171.1h2.5v2.5" fill="none" stroke="#000080" stroke-width=".25"/>
<circle cx="154.8" cy="171.1" r=".51" fill="#000080"/>
<circle cx="154.8" cy="171.1" r=".51" fill="none" stroke="#000080" stroke-width=".21"/>
<path d="M256.4 120.3h2.6v5" fill="none" stroke="#000080" stroke-width=".25"/>
<circle cx="259" cy="120.3" r=".51" fill="#000080"/>
<circle cx="259" cy="120.3" r=".51" fill="none" stroke="#000080" stroke-width=".21"/>
<path d="M236.1 120.3h-2.5v5" fill="none" stroke="#000080" stroke-width=".25"/>
<circle cx="233.6" cy="120.3" r=".51" fill="#000080"/>
<circle cx="233.6" cy="120.3" r=".51" fill="none" stroke="#000080" stroke-width=".21"/>
<path d="M43.1 49.1h2.5" fill="none" stroke="#000080" stroke-width=".25"/>
<circle cx="43.1" cy="49.1" r=".51" fill="#000080"/>
<circle cx="43.1" cy="49.1" r=".51" fill="none" stroke="#000080" stroke-width=".21"/>
<path d="M43.1 64.4h2.5" fill="none" stroke="#000080" stroke-width=".25"/>
<circle cx="43.1" cy="64.4" r=".51" fill="#000080"/>
<circle cx="43.1" cy="64.4" r=".51" fill="none" stroke="#000080" stroke-width=".21"/>
<path d="M43.1 72h2.5" fill="none" stroke="#000080" stroke-width=".25"/>
<circle cx="43.1" cy="72" r=".51" fill="#000080"/>
<circle cx="43.1" cy="72" r=".51" fill="none" stroke="#000080" stroke-width=".21"/>
<path d="M43.1 82.2h2.5" fill="none" stroke="#000080" stroke-width=".25"/>
<circle cx="43.1" cy="82.2" r=".51" fill="#000080"/>
<circle cx="43.1" cy="82.2" r=".51" fill="none" stroke="#000080" stroke-width=".21"/>
<path d="M43.1 94.9h2.5" fill="none" stroke="#000080" stroke-width=".25"/>
<circle cx="43.1" cy="94.9" r=".51" fill="#000080"/>
<circle cx="43.1" cy="94.9" r=".51" fill="none" stroke="#000080" stroke-width=".21"/>
<path d="M43.1 107.6h2.5" fill="none" stroke="#000080" stroke-width=".25"/>
<circle cx="43.1" cy="107.6" r=".51" fill="#000080"/>
<circle cx="43.1" cy="107.6" r=".51" fill="none" stroke="#000080" stroke-width=".21"/>
<path d="M43.1 120.3h2.5" fill="none" stroke="#000080" stroke-width=".25"/>
<circle cx="43.1" cy="120.3" r=".51" fill="#000080"/>
<circle cx="43.1" cy="120.3" r=".51" fill="none" stroke="#000080" stroke-width=".21"/>
<path d="M43.1 133h2.5" fill="none" stroke="#000080" stroke-width=".25"/>
<circle cx="43.1" cy="133" r=".51" fill="#000080"/>
<circle cx="43.1" cy="133" r=".51" fill="none" stroke="#000080" stroke-width=".21"/>
<path d="M43.1 145.7h2.5" fill="none" stroke="#000080" stroke-width=".25"/>
<circle cx="43.1" cy="145.7" r=".51" fill="#000080"/>
<circle cx="43.1" cy="145.7" r=".51" fill="none" stroke="#000080" stroke-width=".21"/>
<path d="M43.1 153.3h2.5" fill="none" stroke="#000080" stroke-width=".25"/>
<circle cx="43.1" cy="153.3" r=".51" fill="#000080"/>
<circle cx="43.1" cy="153.3" r=".51" fill="none" stroke="#000080" stroke-width=".21"/>
<path d="M65.9 77.1h2.6v30.5h-2.6" fill="none" stroke="#000080" stroke-width=".25"/>
<circle cx="68.5" cy="107.6" r=".51" fill="#000080"/>
<circle cx="68.5" cy="107.6" r=".51" fill="none" stroke="#000080" stroke-width=".21"/>
<path d="M68.5 107.6v12.7h-2.6" fill="none" stroke="#000080" stroke-width=".25"/>
<circle cx="68.5" cy="107.6" r=".51" fill="#000080"/>
<circle cx="68.5" cy="107.6" r=".51" fill="none" stroke="#000080" stroke-width=".21"/>
<circle cx="68.5" cy="120.3" r=".51" fill="#000080"/>
<circle cx="68.5" cy="120.3" r=".51" fill="none" stroke="#000080" stroke-width=".21"/>
<path d="M68.5 120.3v12.7h-2.6" fill="none" stroke="#000080" stroke-width=".25"/>
<circle cx="68.5" cy="120.3" r=".51" fill="#000080"/>
<circle cx="68.5" cy="120.3" r=".51" fill="none" stroke="#000080" stroke-width=".21"/>
<circle cx="68.5" cy="133" r=".51" fill="#000080"/>
<circle cx="68.5" cy="133" r=".51" fill="none" stroke="#000080" stroke-width=".21"/>
<path d="M68.5 133v38.1" fill="none" stroke="#000080" stroke-width=".25"/>
<circle cx="68.5" cy="133" r=".51" fill="#000080"/>
<circle cx="68.5" cy="133" r=".51" fill="none" stroke="#000080" stroke-width=".21"/>
<circle cx="68.5" cy="171.1" r=".51" fill="#000080"/>
<circle cx="68.5" cy="171.1" r=".51" fill="none" stroke="#000080" stroke-width=".21"/>
<path d="M65.9 44.1h7.6" fill="none" stroke="#000080" stroke-width=".25"/>
<circle cx="73.5" cy="44.1" r=".51" fill="#000080"/>
<circle cx="73.5" cy="44.1" r=".51" fill="none" stroke="#000080" stroke-width=".21"/>
<path d="M65.9 41.5h7.6" fill="none" stroke="#000080" stroke-width=".25"/>
<circle cx="73.5" cy="41.5" r=".51" fill="#000080"/>
<circle cx="73.5" cy="41.5" r=".51" fill="none" stroke="#000080" stroke-width=".21"/>
<path d="M73.5 56.8v2.5h-7.6" fill="none" stroke="#000080" stroke-width=".25"/>
<circle cx="73.5" cy="56.8" r=".51" fill="#000080"/>
<circle cx="73.5" cy="56.8" r=".51" fill="none" stroke="#000080" stroke-width=".21"/>
<g fill="none" stroke="#000080" stroke-width=".25">
<path d="M129.4 77.1h2.6M27.8 117.7h17.8M27.8 115.2h17.8M27.8 112.6h17.8M27.8 110.1h17.8M65.9 117.7h22.9M65.9 115.2h22.9M27.8 125.3h17.8M27.8 122.8h17.8M27.8 130.4h17.8M27.8 127.9h17.8M65.9 138h22.9"/>
<path d="M65.9 135.5h22.9M27.8 143.1h17.8M27.8 140.6h17.8M27.8 150.7h17.8M27.8 148.2h17.8M27.8 158.4h17.8M65.9 158.4h22.9M152.3 158.4h25.4M27.8 160.9h17.8M27.8 166h17.8M27.8 163.4h17.8M152.3 160.9h25.4"/>
<path d="M152.3 166h25.4M152.3 163.4h25.4"/>
</g>
<circle cx="129.4" cy="77.1" r=".51" fill="#000080"/>
<circle cx="129.4" cy="77.1" r=".51" fill="none" stroke="#000080" stroke-width=".21"/>
<path d="M129.4 89.8h2.6" fill="none" stroke="#000080" stroke-width=".25"/>
<circle cx="129.4" cy="89.8" r=".51" fill="#000080"/>
<circle cx="129.4" cy="89.8" r=".51" fill="none" stroke="#000080" stroke-width=".21"/>
<path d="M129.4 102.5h2.6" fill="none" stroke="#000080" stroke-width=".25"/>
<circle cx="129.4" cy="102.5" r=".51" fill="#000080"/>
<circle cx="129.4" cy="102.5" r=".51" fill="none" stroke="#000080" stroke-width=".21"/>
<path d="M129.4 115.2h2.6" fill="none" stroke="#000080" stroke-width=".25"/>
<circle cx="129.4" cy="115.2" r=".51" fill="#000080"/>
<circle cx="129.4" cy="115.2" r=".51" fill="none" stroke="#000080" stroke-width=".21"/>
<path d="M129.4 127.9h2.6" fill="none" stroke="#000080" stroke-width=".25"/>
<circle cx="129.4" cy="127.9" r=".51" fill="#000080"/>
<circle cx="129.4" cy="127.9" r=".51" fill="none" stroke="#000080" stroke-width=".21"/>
<path d="M129.4 140.6h2.6" fill="none" stroke="#000080" stroke-width=".25"/>
<circle cx="129.4" cy="140.6" r=".51" fill="#000080"/>
<circle cx="129.4" cy="140.6" r=".51" fill="none" stroke="#000080" stroke-width=".21"/>
<path d="M129.4 153.3h2.6" fill="none" stroke="#000080" stroke-width=".25"/>
<circle cx="129.4" cy="153.3" r=".51" fill="#000080"/>
<circle cx="129.4" cy="153.3" r=".51" fill="none" stroke="#000080" stroke-width=".21"/>
<path d="M152.3 102.5h2.5" fill="none" stroke="#000080" stroke-width=".25"/>
<circle cx="154.8" cy="102.5" r=".51" fill="#000080"/>
<circle cx="154.8" cy="102.5" r=".51" fill="none" stroke="#000080" stroke-width=".21"/>
<path d="M152.3 115.2h2.5" fill="none" stroke="#000080" stroke-width=".25"/>
<circle cx="154.8" cy="115.2" r=".51" fill="#000080"/>
<circle cx="154.8" cy="115.2" r=".51" fill="none" stroke="#000080" stroke-width=".21"/>
<path d="M152.3 127.9h2.5" fill="none" stroke="#000080" stroke-width=".25"/>
<circle cx="154.8" cy="127.9" r=".51" fill="#000080"/>
<circle cx="154.8" cy="127.9" r=".51" fill="none" stroke="#000080" stroke-width=".21"/>
<path d="M152.3 140.6h2.5" fill="none" stroke="#000080" stroke-width=".25"/>
<circle cx="154.8" cy="140.6" r=".51" fill="#000080"/>
<circle cx="154.8" cy="140.6" r=".51" fill="none" stroke="#000080" stroke-width=".21"/>
<path d="M233.6 54.2h2.5" fill="none" stroke="#000080" stroke-width=".25"/>
<circle cx="233.6" cy="54.2" r=".51" fill="#000080"/>
<circle cx="233.6" cy="54.2" r=".51" fill="none" stroke="#000080" stroke-width=".21"/>
<path d="M233.6 61.8h2.5" fill="none" stroke="#000080" stroke-width=".25"/>
<circle cx="233.6" cy="61.9" r=".51" fill="#000080"/>
<circle cx="233.6" cy="61.9" r=".51" fill="none" stroke="#000080" stroke-width=".21"/>
<path d="M233.6 69.5h2.5" fill="none" stroke="#000080" stroke-width=".25"/>
<circle cx="233.6" cy="69.5" r=".51" fill="#000080"/>
<circle cx="233.6" cy="69.5" r=".51" fill="none" stroke="#000080" stroke-width=".21"/>
<path d="M233.6 77.1h2.5" fill="none" stroke="#000080" stroke-width=".25"/>
<circle cx="233.6" cy="77.1" r=".51" fill="#000080"/>
<circle cx="233.6" cy="77.1" r=".51" fill="none" stroke="#000080" stroke-width=".21"/>
<path d="M233.6 84.7h2.5" fill="none" stroke="#000080" stroke-width=".25"/>
<circle cx="233.6" cy="84.7" r=".51" fill="#000080"/>
<circle cx="233.6" cy="84.7" r=".51" fill="none" stroke="#000080" stroke-width=".21"/>
<path d="M233.6 97.4h2.5" fill="none" stroke="#000080" stroke-width=".25"/>
<circle cx="233.6" cy="97.4" r=".51" fill="#000080"/>
<circle cx="233.6" cy="97.4" r=".51" fill="none" stroke="#000080" stroke-width=".21"/>
<path d="M256.4 54.2h2.6" fill="none" stroke="#000080" stroke-width=".25"/>
<circle cx="259" cy="54.2" r=".51" fill="#000080"/>
<circle cx="259" cy="54.2" r=".51" fill="none" stroke="#000080" stroke-width=".21"/>
<path d="M256.4 61.8h2.6" fill="none" stroke="#000080" stroke-width=".25"/>
<circle cx="259" cy="61.9" r=".51" fill="#000080"/>
<circle cx="259" cy="61.9" r=".51" fill="none" stroke="#000080" stroke-width=".21"/>
<path d="M256.4 69.5h2.6" fill="none" stroke="#000080" stroke-width=".25"/>
<circle cx="259" cy="69.5" r=".51" fill="#000080"/>
<circle cx="259" cy="69.5" r=".51" fill="none" stroke="#000080" stroke-width=".21"/>
<path d="M256.4 77.1h2.6" fill="none" stroke="#000080" stroke-width=".25"/>
<circle cx="259" cy="77.1" r=".51" fill="#000080"/>
<circle cx="259" cy="77.1" r=".51" fill="none" stroke="#000080" stroke-width=".21"/>
<path d="M256.4 84.7h2.6" fill="none" stroke="#000080" stroke-width=".25"/>
<circle cx="259" cy="84.7" r=".51" fill="#000080"/>
<circle cx="259" cy="84.7" r=".51" fill="none" stroke="#000080" stroke-width=".21"/>
<path d="M256.4 97.4h2.6" fill="none" stroke="#000080" stroke-width=".25"/>
<circle cx="259" cy="97.4" r=".51" fill="#000080"/>
<circle cx="259" cy="97.4" r=".51" fill="none" stroke="#000080" stroke-width=".21"/>
<g fill="none" stroke="#000080" stroke-width=".25">
<path d="M45.6 41.5h-2.5v129.6M101.5 79.6h30.5M101.5 82.2h30.5M152.3 92.3h33M152.3 94.9h33M152.3 97.4h33M152.3 99.9h33M152.3 105h33M152.3 107.6h33M152.3 110.1h33M152.3 112.6h33M152.3 117.7h33"/>
<path d="M152.3 120.3h33M152.3 125.3h33M152.3 122.8h33"/>
</g>
<circle cx="43.1" cy="49.1" r=".51" fill="#000080"/>
<circle cx="43.1" cy="49.1" r=".51" fill="none" stroke="#000080" stroke-width=".21"/>
<circle cx="43.1" cy="64.4" r=".51" fill="#000080"/>
<circle cx="43.1" cy="64.4" r=".51" fill="none" stroke="#000080" stroke-width=".21"/>
<circle cx="43.1" cy="72" r=".51" fill="#000080"/>
<circle cx="43.1" cy="72" r=".51" fill="none" stroke="#000080" stroke-width=".21"/>
<circle cx="43.1" cy="82.2" r=".51" fill="#000080"/>
<circle cx="43.1" cy="82.2" r=".51" fill="none" stroke="#000080" stroke-width=".21"/>
<circle cx="43.1" cy="94.9" r=".51" fill="#000080"/>
<circle cx="43.1" cy="94.9" r=".51" fill="none" stroke="#000080" stroke-width=".21"/>
<circle cx="43.1" cy="107.6" r=".51" fill="#000080"/>
<circle cx="43.1" cy="107.6" r=".51" fill="none" stroke="#000080" stroke-width=".21"/>
<circle cx="43.1" cy="120.3" r=".51" fill="#000080"/>
<circle cx="43.1" cy="120.3" r=".51" fill="none" stroke="#000080" stroke-width=".21"/>
<circle cx="43.1" cy="133" r=".51" fill="#000080"/>
<circle cx="43.1" cy="133" r=".51" fill="none" stroke="#000080" stroke-width=".21"/>
<circle cx="43.1" cy="145.7" r=".51" fill="#000080"/>
<circle cx="43.1" cy="145.7" r=".51" fill="none" stroke="#000080" stroke-width=".21"/>
<circle cx="43.1" cy="153.3" r=".51" fill="#000080"/>
<circle cx="43.1" cy="153.3" r=".51" fill="none" stroke="#000080" stroke-width=".21"/>
<circle cx="43.1" cy="171.1" r=".51" fill="#000080"/>
<circle cx="43.1" cy="171.1" r=".51" fill="none" stroke="#000080" stroke-width=".21"/>
<path d="M65.9 56.8h15.3" fill="none" stroke="#000080" stroke-width=".25"/>
<circle cx="73.5" cy="56.8" r=".51" fill="#000080"/>
<circle cx="73.5" cy="56.8" r=".51" fill="none" stroke="#000080" stroke-width=".21"/>
<path d="M132 64.4h-2.6v106.7" fill="none" stroke="#000080" stroke-width=".25"/>
<circle cx="129.4" cy="77.1" r=".51" fill="#000080"/>
<circle cx="129.4" cy="77.1" r=".51" fill="none" stroke="#000080" stroke-width=".21"/>
<circle cx="129.4" cy="89.8" r=".51" fill="#000080"/>
<circle cx="129.4" cy="89.8" r=".51" fill="none" stroke="#000080" stroke-width=".21"/>
<circle cx="129.4" cy="102.5" r=".51" fill="#000080"/>
<circle cx="129.4" cy="102.5" r=".51" fill="none" stroke="#000080" stroke-width=".21"/>
<circle cx="129.4" cy="115.2" r=".51" fill="#000080"/>
<circle cx="129.4" cy="115.2" r=".51" fill="none" stroke="#000080" stroke-width=".21"/>
<circle cx="129.4" cy="127.9" r=".51" fill="#000080"/>
<circle cx="129.4" cy="127.9" r=".51" fill="none" stroke="#000080" stroke-width=".21"/>
<circle cx="129.4" cy="140.6" r=".51" fill="#000080"/>
<circle cx="129.4" cy="140.6" r=".51" fill="none" stroke="#000080" stroke-width=".21"/>
<circle cx="129.4" cy="153.3" r=".51" fill="#000080"/>
<circle cx="129.4" cy="153.3" r=".51" fill="none" stroke="#000080" stroke-width=".21"/>
<circle cx="129.4" cy="171.1" r=".51" fill="#000080"/>
<circle cx="129.4" cy="171.1" r=".51" fill="none" stroke="#000080" stroke-width=".21"/>
<path d="M152.3 89.8h2.5v81.3" fill="none" stroke="#000080" stroke-width=".25"/>
<circle cx="154.8" cy="102.5" r=".51" fill="#000080"/>
<circle cx="154.8" cy="102.5" r=".51" fill="none" stroke="#000080" stroke-width=".21"/>
<circle cx="154.8" cy="115.2" r=".51" fill="#000080"/>
<circle cx="154.8" cy="115.2" r=".51" fill="none" stroke="#000080" stroke-width=".21"/>
<circle cx="154.8" cy="127.9" r=".51" fill="#000080"/>
<circle cx="154.8" cy="127.9" r=".51" fill="none" stroke="#000080" stroke-width=".21"/>
<circle cx="154.8" cy="140.6" r=".51" fill="#000080"/>
<circle cx="154.8" cy="140.6" r=".51" fill="none" stroke="#000080" stroke-width=".21"/>
<circle cx="154.8" cy="171.1" r=".51" fill="#000080"/>
<circle cx="154.8" cy="171.1" r=".51" fill="none" stroke="#000080" stroke-width=".21"/>
<path d="M73.5 39v7.6h-7.6" fill="none" stroke="#000080" stroke-width=".25"/>
<circle cx="73.5" cy="44.1" r=".51" fill="#000080"/>
<circle cx="73.5" cy="44.1" r=".51" fill="none" stroke="#000080" stroke-width=".21"/>
<circle cx="73.5" cy="41.5" r=".51" fill="#000080"/>
<circle cx="73.5" cy="41.5" r=".51" fill="none" stroke="#000080" stroke-width=".21"/>
<path d="M236.1 46.6h-2.5v73.7" fill="none" stroke="#000080" stroke-width=".25"/>
<circle cx="233.6" cy="54.2" r=".51" fill="#000080"/>
<circle cx="233.6" cy="54.2" r=".51" fill="none" stroke="#000080" stroke-width=".21"/>
<circle cx="233.6" cy="61.9" r=".51" fill="#000080"/>
<circle cx="233.6" cy="61.9" r=".51" fill="none" stroke="#000080" stroke-width=".21"/>
<circle cx="233.6" cy="69.5" r=".51" fill="#000080"/>
<circle cx="233.6" cy="69.5" r=".51" fill="none" stroke="#000080" stroke-width=".21"/>
<circle cx="233.6" cy="77.1" r=".51" fill="#000080"/>
<circle cx="233.6" cy="77.1" r=".51" fill="none" stroke="#000080" stroke-width=".21"/>
<circle cx="233.6" cy="84.7" r=".51" fill="#000080"/>
<circle cx="233.6" cy="84.7" r=".51" fill="none" stroke="#000080" stroke-width=".21"/>
<circle cx="233.6" cy="97.4" r=".51" fill="#000080"/>
<circle cx="233.6" cy="97.4" r=".51" fill="none" stroke="#000080" stroke-width=".21"/>
<circle cx="233.6" cy="120.3" r=".51" fill="#000080"/>
<circle cx="233.6" cy="120.3" r=".51" fill="none" stroke="#000080" stroke-width=".21"/>
<path d="M256.4 46.6h2.6v73.7" fill="none" stroke="#000080" stroke-width=".25"/>
<circle cx="259" cy="54.2" r=".51" fill="#000080"/>
<circle cx="259" cy="54.2" r=".51" fill="none" stroke="#000080" stroke-width=".21"/>
<circle cx="259" cy="61.9" r=".51" fill="#000080"/>
<circle cx="259" cy="61.9" r=".51" fill="none" stroke="#000080" stroke-width=".21"/>
<circle cx="259" cy="69.5" r=".51" fill="#000080"/>
<circle cx="259" cy="69.5" r=".51" fill="none" stroke="#000080" stroke-width=".21"/>
<circle cx="259" cy="77.1" r=".51" fill="#000080"/>
<circle cx="259" cy="77.1" r=".51" fill="none" stroke="#000080" stroke-width=".21"/>
<circle cx="259" cy="84.7" r=".51" fill="#000080"/>
<circle cx="259" cy="84.7" r=".51" fill="none" stroke="#000080" stroke-width=".21"/>
<circle cx="259" cy="97.4" r=".51" fill="#000080"/>
<circle cx="259" cy="97.4" r=".51" fill="none" stroke="#000080" stroke-width=".21"/>
<circle cx="259" cy="120.3" r=".51" fill="#000080"/>
<circle cx="259" cy="120.3" r=".51" fill="none" stroke="#000080" stroke-width=".21"/>
<g fill="none" stroke="#000080" stroke-width=".25">
<path d="M205.6 49.1h30.5M205.6 51.7h30.5M205.6 56.8h30.5M205.6 59.3h30.5M256.4 49.1h28M256.4 51.7h28M256.4 56.8h28M256.4 59.3h28M205.6 64.4h30.5M205.6 66.9h30.5M205.6 72h30.5M205.6 74.5h30.5"/>
<path d="M205.6 79.6h30.5M256.4 64.4h28M256.4 66.9h28M256.4 72h28M256.4 74.5h28M101.5 84.7h30.5M101.5 87.2h30.5M101.5 92.3h30.5M101.5 94.9h30.5M101.5 97.4h30.5M101.5 99.9h30.5M205.6 82.2h30.5"/>
<path d="M101.5 105h30.5M101.5 107.6h30.5M101.5 110.1h30.5M101.5 112.6h30.5M101.5 117.7h30.5M205.6 115.2h30.5M101.5 120.3h30.5M101.5 122.8h30.5M177.7 153.3v2.5h-25.4M65.9 160.9h28v7.6M101.5 173.6h5.1"/>
</g>
<circle cx="104" cy="173.6" r=".51" fill="#000080"/>
<circle cx="104" cy="173.6" r=".51" fill="none" stroke="#000080" stroke-width=".21"/>
<path d="M93.9 178.7v7.6M116.7 173.6h5.1M104 183.8v2.5" fill="none" stroke="#000080" stroke-width=".25"/>
<path d="M64.9 162.4l2 2.1M64.9 165l2 2M66.9 162.4l-2 2.1M66.9 165l-2 2" fill="none" stroke="#f00" stroke-width=".21"/>
<path d="M106.6 173.6h2M114.7 173.6h2" fill="none" stroke="#000" stroke-width=".25"/>
<path d="M108.6 172.6h6v2h-6z" fill="none" stroke="#00f" stroke-width=".25"/>
<use href="#words"/>
</svg>
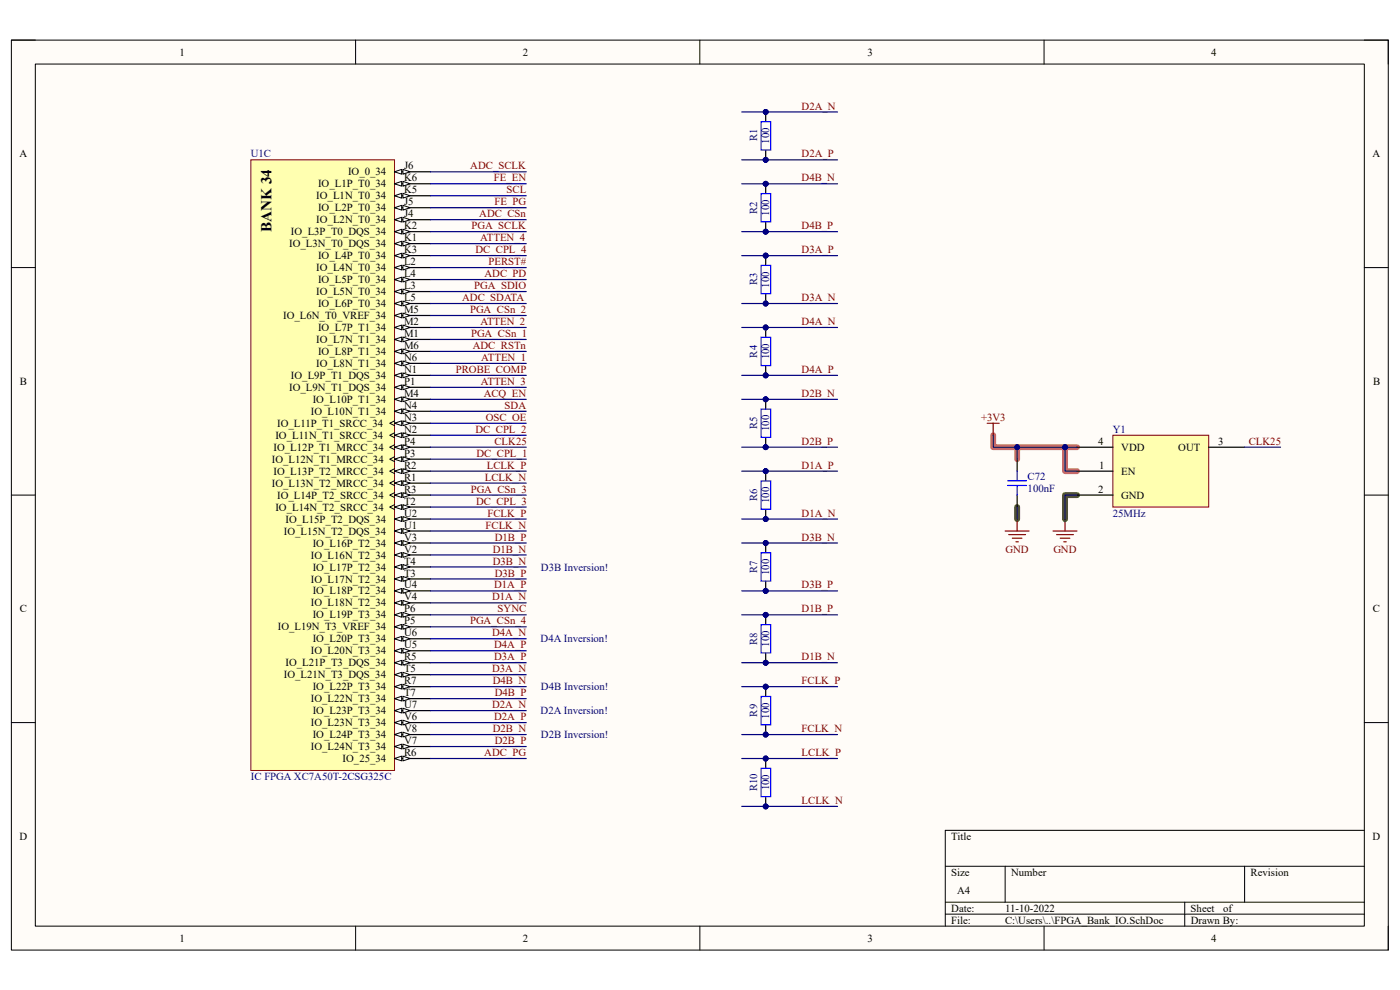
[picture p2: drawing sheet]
<svg xmlns="http://www.w3.org/2000/svg" width="297mm" height="210mm" viewBox="0 0 297 210" stroke-linecap="round" stroke-linejoin="round" font-family="sans-serif">
<defs><g id="words">
<text font-size="3.2" x="57.6" y="49.1" transform="rotate(-90 57.6 49.1)">BANK 34</text>
<g font-size="2.3">
<text x="38.1" y="11.8">1</text>
<text x="110.9" y="11.8">2</text>
<text x="184" y="11.8">3</text>
<text x="256.9" y="11.8">4</text>
<text x="4.1" y="33.4">A</text>
<text x="85.7" y="35.9">J6</text>
<text x="291.2" y="33.4">A</text>
<text x="67.5" y="39.8">IO_L1P_T0_34</text>
<text x="73.8" y="37.2">IO_0_34</text>
<text x="85.7" y="38.5">K6</text>
<text x="85.7" y="41">K5</text>
<text x="67.1" y="42.3">IO_L1N_T0_34</text>
<text x="67.1" y="47.4">IO_L2N_T0_34</text>
<text x="67.5" y="44.8">IO_L2P_T0_34</text>
<text x="85.7" y="43.6">J5</text>
<text x="85.7" y="46.1">J4</text>
<text x="61.3" y="52.5">IO_L3N_T0_DQS_34</text>
<text x="61.7" y="49.9">IO_L3P_T0_DQS_34</text>
<text x="85.7" y="48.6">K2</text>
<text x="85.7" y="51.2">K1</text>
<text x="85.7" y="53.7">K3</text>
<text x="67.1" y="57.5">IO_L4N_T0_34</text>
<text x="67.5" y="55">IO_L4P_T0_34</text>
<text x="85.7" y="56.3">L2</text>
<text x="85.7" y="58.8">L4</text>
<text x="67.1" y="62.6">IO_L5N_T0_34</text>
<text x="67.5" y="60.1">IO_L5P_T0_34</text>
<text x="67.5" y="65.2">IO_L6P_T0_34</text>
<text x="85.7" y="61.3">L3</text>
<text x="85.7" y="63.9">L5</text>
<text x="60.1" y="67.7">IO_L6N_T0_VREF_34</text>
<text x="67.5" y="70.2">IO_L7P_T1_34</text>
<text x="85.7" y="66.4">M5</text>
<text x="85.7" y="69">M2</text>
<text x="85.7" y="71.5">M1</text>
<text x="67.1" y="72.8">IO_L7N_T1_34</text>
<text x="67.1" y="77.9">IO_L8N_T1_34</text>
<text x="67.5" y="75.3">IO_L8P_T1_34</text>
<text x="85.7" y="74">M6</text>
<text x="85.7" y="76.6">N6</text>
<text x="4.2" y="81.7">B</text>
<text x="61.3" y="82.9">IO_L9N_T1_DQS_34</text>
<text x="61.7" y="80.4">IO_L9P_T1_DQS_34</text>
<text x="85.7" y="79.1">N1</text>
<text x="85.7" y="81.7">P1</text>
<text x="291.3" y="81.7">B</text>
<text x="66" y="88">IO_L10N_T1_34</text>
<text x="66.3" y="85.5">IO_L10P_T1_34</text>
<text x="85.7" y="84.2">M4</text>
<text x="85.7" y="86.7">N4</text>
<text x="85.7" y="89.3">N3</text>
<text x="58" y="95.6">IO_L12P_T1_MRCC_34</text>
<text x="58.4" y="93.1">IO_L11N_T1_SRCC_34</text>
<text x="58.8" y="90.6">IO_L11P_T1_SRCC_34</text>
<text x="85.7" y="91.8">N2</text>
<text x="85.7" y="94.4">P4</text>
<text x="233" y="94.4">4</text>
<text x="237.9" y="95.6">VDD</text>
<text x="250" y="95.6">OUT</text>
<text x="258.4" y="94.4">3</text>
<text x="57.7" y="98.2">IO_L12N_T1_MRCC_34</text>
<text x="58" y="100.7">IO_L13P_T2_MRCC_34</text>
<text x="85.7" y="96.9">P3</text>
<text x="85.7" y="99.4">R2</text>
<text x="85.7" y="102">R1</text>
<text x="233.2" y="99.4">1</text>
<text x="237.9" y="100.7">EN</text>
<text x="57.7" y="103.3">IO_L13N_T2_MRCC_34</text>
<text x="58.8" y="105.8">IO_L14P_T2_SRCC_34</text>
<text x="85.7" y="104.5">R3</text>
<text x="85.7" y="107.1">T2</text>
<text x="233" y="104.5">2</text>
<text x="237.9" y="105.8">GND</text>
<text x="58.4" y="108.3">IO_L14N_T2_SRCC_34</text>
<text x="60.2" y="113.4">IO_L15N_T2_DQS_34</text>
<text x="60.6" y="110.9">IO_L15P_T2_DQS_34</text>
<text x="85.7" y="109.6">U2</text>
<text x="85.7" y="112.1">U1</text>
<text x="66" y="118.5">IO_L16N_T2_34</text>
<text x="66.3" y="116">IO_L16P_T2_34</text>
<text x="85.7" y="114.7">V3</text>
<text x="85.7" y="117.2">V2</text>
<text x="85.7" y="119.8">T4</text>
<text x="66" y="123.6">IO_L17N_T2_34</text>
<text x="66.3" y="121">IO_L17P_T2_34</text>
<text x="85.7" y="122.3">T3</text>
<text x="85.7" y="124.8">U4</text>
<text x="4.2" y="129.9">C</text>
<text x="66" y="128.7">IO_L18N_T2_34</text>
<text x="66.3" y="126.1">IO_L18P_T2_34</text>
<text x="66.3" y="131.2">IO_L19P_T3_34</text>
<text x="85.7" y="127.4">V4</text>
<text x="85.7" y="129.9">P6</text>
<text x="291.3" y="129.9">C</text>
<text x="58.9" y="133.7">IO_L19N_T3_VREF_34</text>
<text x="66.3" y="136.3">IO_L20P_T3_34</text>
<text x="85.7" y="132.5">P5</text>
<text x="85.7" y="135">U6</text>
<text x="85.7" y="137.5">U5</text>
<text x="60.2" y="143.9">IO_L21N_T3_DQS_34</text>
<text x="60.6" y="141.4">IO_L21P_T3_DQS_34</text>
<text x="66" y="138.8">IO_L20N_T3_34</text>
<text x="85.7" y="140.1">R5</text>
<text x="85.7" y="142.6">T5</text>
<text x="66" y="149">IO_L22N_T3_34</text>
<text x="66.3" y="146.4">IO_L22P_T3_34</text>
<text x="85.7" y="145.2">R7</text>
<text x="85.7" y="147.7">T7</text>
<text x="66" y="154.1">IO_L23N_T3_34</text>
<text x="66.3" y="151.5">IO_L23P_T3_34</text>
<text x="85.7" y="150.2">U7</text>
<text x="85.7" y="152.8">V6</text>
<text x="85.7" y="155.3">V8</text>
<text x="66" y="159.1">IO_L24N_T3_34</text>
<text x="66.3" y="156.6">IO_L24P_T3_34</text>
<text x="72.7" y="161.7">IO_25_34</text>
<text x="85.7" y="157.9">V7</text>
<text x="85.7" y="160.4">R6</text>
<text x="4.1" y="178.2">D</text>
<text x="201.8" y="178.2">Title</text>
<text x="291.2" y="178.2">D</text>
<text x="201.8" y="185.8">Size</text>
<text x="214.5" y="185.8">Number</text>
<text x="265.3" y="185.8">Revision</text>
<text x="203.1" y="189.6">A4</text>
<text x="201.8" y="193.4">Date:</text>
<text x="201.8" y="196">File:</text>
<text x="213.2" y="196">C:\Users\..\FPGA_Bank_IO.SchDoc</text>
<text x="213.2" y="193.4">11-10-2022</text>
<text x="252.6" y="193.4">Sheet</text>
<text x="252.6" y="196">Drawn By:</text>
<text x="259.5" y="193.4">of</text>
<text x="38.1" y="199.8">1</text>
<text x="110.9" y="199.8">2</text>
<text x="184" y="199.8">3</text>
<text x="256.9" y="199.8">4</text>
</g>
<g font-size="2.3" fill="#800000">
<text x="170.1" y="23.2">D2A_N</text>
<text x="99.8" y="35.9">ADC_SCLK</text>
<text x="170.1" y="33.4">D2A_P</text>
<text x="104.8" y="38.5">FE_EN</text>
<text x="107.5" y="41">SCL</text>
<text x="170.1" y="38.5">D4B_N</text>
<text x="101.7" y="46.1">ADC_CSn</text>
<text x="104.9" y="43.6">FE_PG</text>
<text x="100" y="48.6">PGA_SCLK</text>
<text x="100.9" y="53.7">DC_CPL_4</text>
<text x="101.9" y="51.2">ATTEN_4</text>
<text x="170.1" y="48.6">D4B_P</text>
<text x="170.1" y="53.7">D3A_P</text>
<text x="102.8" y="58.8">ADC_PD</text>
<text x="103.6" y="56.3">PERST#</text>
<text x="98" y="63.9">ADC_SDATA</text>
<text x="100.6" y="61.3">PGA_SDIO</text>
<text x="170.1" y="63.9">D3A_N</text>
<text x="99.7" y="66.4">PGA_CSn_2</text>
<text x="99.9" y="71.5">PGA_CSn_1</text>
<text x="101.9" y="69">ATTEN_2</text>
<text x="170.1" y="69">D4A_N</text>
<text x="100.3" y="74">ADC_RSTn</text>
<text x="102.1" y="76.6">ATTEN_1</text>
<text x="96.7" y="79.1">PROBE_COMP</text>
<text x="102" y="81.7">ATTEN_3</text>
<text x="170.1" y="79.1">D4A_P</text>
<text x="102.6" y="84.2">ACQ_EN</text>
<text x="103" y="89.3">OSC_OE</text>
<text x="107.1" y="86.7">SDA</text>
<text x="170.1" y="84.2">D2B_N</text>
<text x="208.2" y="89.3">+3V3</text>
<text x="100.9" y="91.8">DC_CPL_2</text>
<text x="104.9" y="94.4">CLK25</text>
<text x="170.1" y="94.4">D2B_P</text>
<text x="264.9" y="94.4">CLK25</text>
<text x="101.1" y="96.9">DC_CPL_1</text>
<text x="102.9" y="102">LCLK_N</text>
<text x="103.3" y="99.4">LCLK_P</text>
<text x="170.1" y="99.4">D1A_P</text>
<text x="99.9" y="104.5">PGA_CSn_3</text>
<text x="101" y="107.1">DC_CPL_3</text>
<text x="103" y="112.1">FCLK_N</text>
<text x="103.4" y="109.6">FCLK_P</text>
<text x="170.1" y="109.6">D1A_N</text>
<text x="104.5" y="119.8">D3B_N</text>
<text x="104.5" y="117.2">D1B_N</text>
<text x="104.9" y="114.7">D1B_P</text>
<text x="170.1" y="114.7">D3B_N</text>
<text x="213.3" y="117.2">GND</text>
<text x="223.5" y="117.2">GND</text>
<text x="104.8" y="124.8">D1A_P</text>
<text x="104.9" y="122.3">D3B_P</text>
<text x="170.1" y="124.8">D3B_P</text>
<text x="104.4" y="127.4">D1A_N</text>
<text x="105.6" y="129.9">SYNC</text>
<text x="170.1" y="129.9">D1B_P</text>
<text x="99.7" y="132.5">PGA_CSn_4</text>
<text x="104.4" y="135">D4A_N</text>
<text x="104.8" y="137.5">D4A_P</text>
<text x="104.4" y="142.6">D3A_N</text>
<text x="104.8" y="140.1">D3A_P</text>
<text x="170.1" y="140.1">D1B_N</text>
<text x="104.5" y="145.2">D4B_N</text>
<text x="104.9" y="147.7">D4B_P</text>
<text x="170.1" y="145.2">FCLK_P</text>
<text x="104.4" y="150.2">D2A_N</text>
<text x="104.5" y="155.3">D2B_N</text>
<text x="104.8" y="152.8">D2A_P</text>
<text x="170.1" y="155.3">FCLK_N</text>
<text x="102.7" y="160.4">ADC_PG</text>
<text x="104.9" y="157.9">D2B_P</text>
<text x="170.1" y="160.4">LCLK_P</text>
<text x="170.1" y="170.6">LCLK_N</text>
</g>
<g font-size="2.3" fill="#000080">
<text x="53.2" y="33.4">U1C</text>
<text x="160.7" y="30" transform="rotate(-90 160.7 30)">R1</text>
<text x="163.2" y="30.5" transform="rotate(-90 163.2 30.5)">100</text>
<text x="160.7" y="45.3" transform="rotate(-90 160.7 45.3)">R2</text>
<text x="163.2" y="45.8" transform="rotate(-90 163.2 45.8)">100</text>
<text x="160.7" y="60.5" transform="rotate(-90 160.7 60.5)">R3</text>
<text x="163.2" y="61" transform="rotate(-90 163.2 61)">100</text>
<text x="160.7" y="75.9" transform="rotate(-90 160.7 75.9)">R4</text>
<text x="163.2" y="76.2" transform="rotate(-90 163.2 76.2)">100</text>
<text x="160.7" y="91.1" transform="rotate(-90 160.7 91.1)">R5</text>
<text x="163.2" y="91.5" transform="rotate(-90 163.2 91.5)">100</text>
<text x="236.1" y="91.8">Y1</text>
<text x="218" y="101.7">C72</text>
<text x="160.7" y="106.3" transform="rotate(-90 160.7 106.3)">R6</text>
<text x="163.2" y="106.7" transform="rotate(-90 163.2 106.7)">100</text>
<text x="218" y="104.3">100nF</text>
<text x="236.1" y="109.6">25MHz</text>
<text x="114.8" y="121">D3B Inversion!</text>
<text x="160.7" y="121.5" transform="rotate(-90 160.7 121.5)">R7</text>
<text x="163.2" y="122" transform="rotate(-90 163.2 122)">100</text>
<text x="114.7" y="136.3">D4A Inversion!</text>
<text x="160.7" y="136.8" transform="rotate(-90 160.7 136.8)">R8</text>
<text x="163.2" y="137.2" transform="rotate(-90 163.2 137.2)">100</text>
<text x="114.8" y="146.4">D4B Inversion!</text>
<text x="114.7" y="151.5">D2A Inversion!</text>
<text x="160.7" y="152" transform="rotate(-90 160.7 152)">R9</text>
<text x="163.2" y="152.4" transform="rotate(-90 163.2 152.4)">100</text>
<text x="114.8" y="156.6">D2B Inversion!</text>
<text x="53.2" y="165.5">IC FPGA XC7A50T-2CSG325C</text>
<text x="160.7" y="167.9" transform="rotate(-90 160.7 167.9)">R10</text>
<text x="163.2" y="167.7" transform="rotate(-90 163.2 167.7)">100</text>
</g>
</g></defs>
<path d="M2.4 8.5h292.1v193h-292.1z" fill-rule="evenodd" fill="#fffcf8"/>
<path d="M2.4 8.5h292.1v193h-292.1z" fill="none" stroke="#000" stroke-width=".21"/>
<path d="M7.5 13.6h281.9v182.9h-281.9z" fill-rule="evenodd" fill="#fffcf8"/>
<g fill="none" stroke="#000" stroke-width=".21">
<path d="M2.4 8.5h5.1M7.5 13.6h281.9v182.9h-281.9zM75.4 8.5v5.1M148.5 8.5v5.1M221.5 8.5v5.1M289.4 8.5h5.1v5.1M2.4 56.8h5.1M289.4 56.8h5.1M2.4 105h5.1M289.4 105h5.1M2.4 153.3h5.1M289.4 153.3h5.1"/>
<path d="M289.4 176.1h-88.9v20.4M75.4 196.5v5M148.5 196.5v5M200.5 183.8h88.9M200.5 191.4h88.9M200.5 193.9h88.9M213.2 183.8v7.6M221.5 196.5v5M251.3 191.4v5.1M264 183.8v7.6M294.5 196.5v5"/>
</g>
<path d="M210.7 92.3v2.6h5.1M225.9 94.9v5h2.6M225.9 94.9h-10.1v2.5M225.9 94.9h2.6" fill="none" stroke="#ff6e6e" stroke-width="1.3"/>
<path d="M215.8 107.6v2.5M228.5 105h-2.6v5.1" fill="none" stroke="#00be00" stroke-width="1.3"/>
<path d="M53.2 33.9h30.5v129.5h-30.5z" fill-rule="evenodd" fill="#ffffb0"/>
<path d="M53.2 33.9h30.5v129.5h-30.5z" fill="none" stroke="#800000" stroke-width=".21"/>
<path d="M83.7 36.4h7.6" fill="none" stroke="#000" stroke-width=".25"/>
<path d="M83.7 36.4l1.5-.5v1.1z" fill="#f8fcff"/>
<path d="M83.7 36.4l1.5-.5v1.1z" fill="none" stroke="#000" stroke-width=".21"/>
<path d="M85.5 35.9l1.5 .5-1.5 .6z" fill="#f8fcff"/>
<path d="M85.5 35.9l1.5 .5-1.5 .6z" fill="none" stroke="#000" stroke-width=".21"/>
<path d="M83.7 39h7.6" fill="none" stroke="#000" stroke-width=".25"/>
<path d="M83.7 39l1.5-.5v1z" fill="#f8fcff"/>
<path d="M83.7 39l1.5-.5v1z" fill="none" stroke="#000" stroke-width=".21"/>
<path d="M85.5 38.5l1.5 .5-1.5 .5z" fill="#f8fcff"/>
<path d="M85.5 38.5l1.5 .5-1.5 .5z" fill="none" stroke="#000" stroke-width=".21"/>
<path d="M83.7 41.5h7.6" fill="none" stroke="#000" stroke-width=".25"/>
<path d="M83.7 41.5l1.5-.5v1z" fill="#f8fcff"/>
<path d="M83.7 41.5l1.5-.5v1z" fill="none" stroke="#000" stroke-width=".21"/>
<path d="M85.5 41l1.5 .5-1.5 .5z" fill="#f8fcff"/>
<path d="M85.5 41l1.5 .5-1.5 .5z" fill="none" stroke="#000" stroke-width=".21"/>
<path d="M83.7 44.1h7.6" fill="none" stroke="#000" stroke-width=".25"/>
<path d="M83.7 44.1l1.5-.5v1z" fill="#f8fcff"/>
<path d="M83.7 44.1l1.5-.5v1z" fill="none" stroke="#000" stroke-width=".21"/>
<path d="M85.5 43.6l1.5 .5-1.5 .5z" fill="#f8fcff"/>
<path d="M85.5 43.6l1.5 .5-1.5 .5z" fill="none" stroke="#000" stroke-width=".21"/>
<path d="M83.7 46.6h7.6" fill="none" stroke="#000" stroke-width=".25"/>
<path d="M83.7 46.6l1.5-.5v1z" fill="#f8fcff"/>
<path d="M83.7 46.6l1.5-.5v1z" fill="none" stroke="#000" stroke-width=".21"/>
<path d="M85.5 46.1l1.5 .5-1.5 .5z" fill="#f8fcff"/>
<path d="M85.5 46.1l1.5 .5-1.5 .5z" fill="none" stroke="#000" stroke-width=".21"/>
<path d="M83.7 49.1h7.6" fill="none" stroke="#000" stroke-width=".25"/>
<path d="M83.7 49.1l1.5-.5v1.1z" fill="#f8fcff"/>
<path d="M83.7 49.1l1.5-.5v1.1z" fill="none" stroke="#000" stroke-width=".21"/>
<path d="M85.5 48.6l1.5 .5-1.5 .6z" fill="#f8fcff"/>
<path d="M85.5 48.6l1.5 .5-1.5 .6z" fill="none" stroke="#000" stroke-width=".21"/>
<path d="M83.7 51.7h7.6" fill="none" stroke="#000" stroke-width=".25"/>
<path d="M83.7 51.7l1.5-.5v1z" fill="#f8fcff"/>
<path d="M83.7 51.7l1.5-.5v1z" fill="none" stroke="#000" stroke-width=".21"/>
<path d="M85.5 51.2l1.5 .5-1.5 .5z" fill="#f8fcff"/>
<path d="M85.5 51.2l1.5 .5-1.5 .5z" fill="none" stroke="#000" stroke-width=".21"/>
<path d="M83.7 54.2h7.6" fill="none" stroke="#000" stroke-width=".25"/>
<path d="M83.7 54.2l1.5-.5v1z" fill="#f8fcff"/>
<path d="M83.7 54.2l1.5-.5v1z" fill="none" stroke="#000" stroke-width=".21"/>
<path d="M85.5 53.7l1.5 .5-1.5 .5z" fill="#f8fcff"/>
<path d="M85.5 53.7l1.5 .5-1.5 .5z" fill="none" stroke="#000" stroke-width=".21"/>
<path d="M83.7 56.8h7.6" fill="none" stroke="#000" stroke-width=".25"/>
<path d="M83.7 56.8l1.5-.5v1z" fill="#f8fcff"/>
<path d="M83.7 56.8l1.5-.5v1z" fill="none" stroke="#000" stroke-width=".21"/>
<path d="M85.5 56.3l1.5 .5-1.5 .5z" fill="#f8fcff"/>
<path d="M85.5 56.3l1.5 .5-1.5 .5z" fill="none" stroke="#000" stroke-width=".21"/>
<path d="M83.7 59.3h7.6" fill="none" stroke="#000" stroke-width=".25"/>
<path d="M83.7 59.3l1.5-.5v1z" fill="#f8fcff"/>
<path d="M83.7 59.3l1.5-.5v1z" fill="none" stroke="#000" stroke-width=".21"/>
<path d="M85.5 58.8l1.5 .5-1.5 .5z" fill="#f8fcff"/>
<path d="M85.5 58.8l1.5 .5-1.5 .5z" fill="none" stroke="#000" stroke-width=".21"/>
<path d="M83.7 61.8h7.6" fill="none" stroke="#000" stroke-width=".25"/>
<path d="M83.7 61.8l1.5-.5v1.1z" fill="#f8fcff"/>
<path d="M83.7 61.8l1.5-.5v1.1z" fill="none" stroke="#000" stroke-width=".21"/>
<path d="M85.5 61.3l1.5 .5-1.5 .6z" fill="#f8fcff"/>
<path d="M85.5 61.3l1.5 .5-1.5 .6z" fill="none" stroke="#000" stroke-width=".21"/>
<path d="M83.7 64.4h7.6" fill="none" stroke="#000" stroke-width=".25"/>
<path d="M83.7 64.4l1.5-.5v1z" fill="#f8fcff"/>
<path d="M83.7 64.4l1.5-.5v1z" fill="none" stroke="#000" stroke-width=".21"/>
<path d="M85.5 63.9l1.5 .5-1.5 .5z" fill="#f8fcff"/>
<path d="M85.5 63.9l1.5 .5-1.5 .5z" fill="none" stroke="#000" stroke-width=".21"/>
<path d="M83.7 66.9h7.6" fill="none" stroke="#000" stroke-width=".25"/>
<path d="M83.7 66.9l1.5-.5v1z" fill="#f8fcff"/>
<path d="M83.7 66.9l1.5-.5v1z" fill="none" stroke="#000" stroke-width=".21"/>
<path d="M85.5 66.4l1.5 .5-1.5 .5z" fill="#f8fcff"/>
<path d="M85.5 66.4l1.5 .5-1.5 .5z" fill="none" stroke="#000" stroke-width=".21"/>
<path d="M83.7 69.5h7.6" fill="none" stroke="#000" stroke-width=".25"/>
<path d="M83.7 69.5l1.5-.5v1z" fill="#f8fcff"/>
<path d="M83.7 69.5l1.5-.5v1z" fill="none" stroke="#000" stroke-width=".21"/>
<path d="M85.5 69l1.5 .5-1.5 .5z" fill="#f8fcff"/>
<path d="M85.5 69l1.5 .5-1.5 .5z" fill="none" stroke="#000" stroke-width=".21"/>
<path d="M83.7 72h7.6" fill="none" stroke="#000" stroke-width=".25"/>
<path d="M83.7 72l1.5-.5v1z" fill="#f8fcff"/>
<path d="M83.7 72l1.5-.5v1z" fill="none" stroke="#000" stroke-width=".21"/>
<path d="M85.5 71.5l1.5 .5-1.5 .5z" fill="#f8fcff"/>
<path d="M85.5 71.5l1.5 .5-1.5 .5z" fill="none" stroke="#000" stroke-width=".21"/>
<path d="M83.7 74.5h7.6" fill="none" stroke="#000" stroke-width=".25"/>
<path d="M83.7 74.5l1.5-.5v1.1z" fill="#f8fcff"/>
<path d="M83.7 74.5l1.5-.5v1.1z" fill="none" stroke="#000" stroke-width=".21"/>
<path d="M85.5 74l1.5 .5-1.5 .6z" fill="#f8fcff"/>
<path d="M85.5 74l1.5 .5-1.5 .6z" fill="none" stroke="#000" stroke-width=".21"/>
<path d="M83.7 77.1h7.6" fill="none" stroke="#000" stroke-width=".25"/>
<path d="M83.7 77.1l1.5-.5v1z" fill="#f8fcff"/>
<path d="M83.7 77.1l1.5-.5v1z" fill="none" stroke="#000" stroke-width=".21"/>
<path d="M85.5 76.6l1.5 .5-1.5 .5z" fill="#f8fcff"/>
<path d="M85.5 76.6l1.5 .5-1.5 .5z" fill="none" stroke="#000" stroke-width=".21"/>
<path d="M83.7 79.6h7.6" fill="none" stroke="#000" stroke-width=".25"/>
<path d="M83.7 79.6l1.5-.5v1z" fill="#f8fcff"/>
<path d="M83.7 79.6l1.5-.5v1z" fill="none" stroke="#000" stroke-width=".21"/>
<path d="M85.5 79.1l1.5 .5-1.5 .5z" fill="#f8fcff"/>
<path d="M85.5 79.1l1.5 .5-1.5 .5z" fill="none" stroke="#000" stroke-width=".21"/>
<path d="M83.7 82.2h7.6" fill="none" stroke="#000" stroke-width=".25"/>
<path d="M83.7 82.2l1.5-.5v1z" fill="#f8fcff"/>
<path d="M83.7 82.2l1.5-.5v1z" fill="none" stroke="#000" stroke-width=".21"/>
<path d="M85.5 81.7l1.5 .5-1.5 .5z" fill="#f8fcff"/>
<path d="M85.5 81.7l1.5 .5-1.5 .5z" fill="none" stroke="#000" stroke-width=".21"/>
<path d="M83.7 84.7h7.6" fill="none" stroke="#000" stroke-width=".25"/>
<path d="M83.7 84.7l1.5-.5v1z" fill="#f8fcff"/>
<path d="M83.7 84.7l1.5-.5v1z" fill="none" stroke="#000" stroke-width=".21"/>
<path d="M85.5 84.2l1.5 .5-1.5 .5z" fill="#f8fcff"/>
<path d="M85.5 84.2l1.5 .5-1.5 .5z" fill="none" stroke="#000" stroke-width=".21"/>
<path d="M83.7 87.2h7.6" fill="none" stroke="#000" stroke-width=".25"/>
<path d="M83.7 87.2l1.5-.5v1.1z" fill="#f8fcff"/>
<path d="M83.7 87.2l1.5-.5v1.1z" fill="none" stroke="#000" stroke-width=".21"/>
<path d="M85.5 86.7l1.5 .5-1.5 .6z" fill="#f8fcff"/>
<path d="M85.5 86.7l1.5 .5-1.5 .6z" fill="none" stroke="#000" stroke-width=".21"/>
<path d="M83.7 89.8h7.6" fill="none" stroke="#000" stroke-width=".25"/>
<path d="M83.7 89.8l1.5-.5v1z" fill="#f8fcff"/>
<path d="M83.7 89.8l1.5-.5v1z" fill="none" stroke="#000" stroke-width=".21"/>
<path d="M85.5 89.3l1.5 .5-1.5 .5z" fill="#f8fcff"/>
<path d="M83.7 89.3l-1 .5 1 .5M85.5 89.3l1.5 .5-1.5 .5z" fill="none" stroke="#000" stroke-width=".21"/>
<path d="M83.7 92.3h7.6" fill="none" stroke="#000" stroke-width=".25"/>
<path d="M83.7 92.3l1.5-.5v1z" fill="#f8fcff"/>
<path d="M83.7 92.3l1.5-.5v1z" fill="none" stroke="#000" stroke-width=".21"/>
<path d="M85.5 91.8l1.5 .5-1.5 .5z" fill="#f8fcff"/>
<path d="M83.7 91.8l-1 .5 1 .5M85.5 91.8l1.5 .5-1.5 .5z" fill="none" stroke="#000" stroke-width=".21"/>
<path d="M83.7 94.9h7.6" fill="none" stroke="#000" stroke-width=".25"/>
<path d="M83.7 94.9l1.5-.5v1z" fill="#f8fcff"/>
<path d="M83.7 94.9l1.5-.5v1z" fill="none" stroke="#000" stroke-width=".21"/>
<path d="M85.5 94.4l1.5 .5-1.5 .5z" fill="#f8fcff"/>
<path d="M83.7 94.4l-1 .5 1 .5M85.5 94.4l1.5 .5-1.5 .5z" fill="none" stroke="#000" stroke-width=".21"/>
<path d="M83.7 97.4h7.6" fill="none" stroke="#000" stroke-width=".25"/>
<path d="M83.7 97.4l1.5-.5v1z" fill="#f8fcff"/>
<path d="M83.7 97.4l1.5-.5v1z" fill="none" stroke="#000" stroke-width=".21"/>
<path d="M85.5 96.9l1.5 .5-1.5 .5z" fill="#f8fcff"/>
<path d="M83.7 96.9l-1 .5 1 .5M85.5 96.9l1.5 .5-1.5 .5z" fill="none" stroke="#000" stroke-width=".21"/>
<path d="M83.7 99.9h7.6" fill="none" stroke="#000" stroke-width=".25"/>
<path d="M83.7 99.9l1.5-.5v1.1z" fill="#f8fcff"/>
<path d="M83.7 99.9l1.5-.5v1.1z" fill="none" stroke="#000" stroke-width=".21"/>
<path d="M85.5 99.4l1.5 .5-1.5 .6z" fill="#f8fcff"/>
<path d="M83.7 99.4l-1 .5 1 .6M85.5 99.4l1.5 .5-1.5 .6z" fill="none" stroke="#000" stroke-width=".21"/>
<path d="M83.7 102.5h7.6" fill="none" stroke="#000" stroke-width=".25"/>
<path d="M83.7 102.5l1.5-.5v1z" fill="#f8fcff"/>
<path d="M83.7 102.5l1.5-.5v1z" fill="none" stroke="#000" stroke-width=".21"/>
<path d="M85.5 102l1.5 .5-1.5 .5z" fill="#f8fcff"/>
<path d="M83.7 102l-1 .5 1 .5M85.5 102l1.5 .5-1.5 .5z" fill="none" stroke="#000" stroke-width=".21"/>
<path d="M83.7 105h7.6" fill="none" stroke="#000" stroke-width=".25"/>
<path d="M83.7 105l1.5-.5v1z" fill="#f8fcff"/>
<path d="M83.7 105l1.5-.5v1z" fill="none" stroke="#000" stroke-width=".21"/>
<path d="M85.5 104.5l1.5 .5-1.5 .5z" fill="#f8fcff"/>
<path d="M83.7 104.5l-1 .5 1 .5M85.5 104.5l1.5 .5-1.5 .5z" fill="none" stroke="#000" stroke-width=".21"/>
<path d="M83.7 107.6h7.6" fill="none" stroke="#000" stroke-width=".25"/>
<path d="M83.7 107.6l1.5-.5v1z" fill="#f8fcff"/>
<path d="M83.7 107.6l1.5-.5v1z" fill="none" stroke="#000" stroke-width=".21"/>
<path d="M85.5 107.1l1.5 .5-1.5 .5z" fill="#f8fcff"/>
<path d="M83.7 107.1l-1 .5 1 .5M85.5 107.1l1.5 .5-1.5 .5z" fill="none" stroke="#000" stroke-width=".21"/>
<path d="M83.7 110.1h7.6" fill="none" stroke="#000" stroke-width=".25"/>
<path d="M83.7 110.1l1.5-.5v1z" fill="#f8fcff"/>
<path d="M83.7 110.1l1.5-.5v1z" fill="none" stroke="#000" stroke-width=".21"/>
<path d="M85.5 109.6l1.5 .5-1.5 .5z" fill="#f8fcff"/>
<path d="M85.5 109.6l1.5 .5-1.5 .5z" fill="none" stroke="#000" stroke-width=".21"/>
<path d="M83.7 112.6h7.6" fill="none" stroke="#000" stroke-width=".25"/>
<path d="M83.7 112.6l1.5-.5v1.1z" fill="#f8fcff"/>
<path d="M83.7 112.6l1.5-.5v1.1z" fill="none" stroke="#000" stroke-width=".21"/>
<path d="M85.5 112.1l1.5 .5-1.5 .6z" fill="#f8fcff"/>
<path d="M85.5 112.1l1.5 .5-1.5 .6z" fill="none" stroke="#000" stroke-width=".21"/>
<path d="M83.7 115.2h7.6" fill="none" stroke="#000" stroke-width=".25"/>
<path d="M83.7 115.2l1.5-.5v1z" fill="#f8fcff"/>
<path d="M83.7 115.2l1.5-.5v1z" fill="none" stroke="#000" stroke-width=".21"/>
<path d="M85.5 114.7l1.5 .5-1.5 .5z" fill="#f8fcff"/>
<path d="M85.5 114.7l1.5 .5-1.5 .5z" fill="none" stroke="#000" stroke-width=".21"/>
<path d="M83.7 117.7h7.6" fill="none" stroke="#000" stroke-width=".25"/>
<path d="M83.7 117.7l1.5-.5v1z" fill="#f8fcff"/>
<path d="M83.7 117.7l1.5-.5v1z" fill="none" stroke="#000" stroke-width=".21"/>
<path d="M85.5 117.2l1.5 .5-1.5 .5z" fill="#f8fcff"/>
<path d="M85.5 117.2l1.5 .5-1.5 .5z" fill="none" stroke="#000" stroke-width=".21"/>
<path d="M83.7 120.3h7.6" fill="none" stroke="#000" stroke-width=".25"/>
<path d="M83.7 120.3l1.5-.5v1z" fill="#f8fcff"/>
<path d="M83.7 120.3l1.5-.5v1z" fill="none" stroke="#000" stroke-width=".21"/>
<path d="M85.5 119.8l1.5 .5-1.5 .5z" fill="#f8fcff"/>
<path d="M85.5 119.8l1.5 .5-1.5 .5z" fill="none" stroke="#000" stroke-width=".21"/>
<path d="M83.7 122.8h7.6" fill="none" stroke="#000" stroke-width=".25"/>
<path d="M83.7 122.8l1.5-.5v1z" fill="#f8fcff"/>
<path d="M83.7 122.8l1.5-.5v1z" fill="none" stroke="#000" stroke-width=".21"/>
<path d="M85.5 122.3l1.5 .5-1.5 .5z" fill="#f8fcff"/>
<path d="M85.5 122.3l1.5 .5-1.5 .5z" fill="none" stroke="#000" stroke-width=".21"/>
<path d="M83.7 125.3h7.6" fill="none" stroke="#000" stroke-width=".25"/>
<path d="M83.7 125.3l1.5-.5v1.1z" fill="#f8fcff"/>
<path d="M83.7 125.3l1.5-.5v1.1z" fill="none" stroke="#000" stroke-width=".21"/>
<path d="M85.5 124.8l1.5 .5-1.5 .6z" fill="#f8fcff"/>
<path d="M85.5 124.8l1.5 .5-1.5 .6z" fill="none" stroke="#000" stroke-width=".21"/>
<path d="M83.7 127.9h7.6" fill="none" stroke="#000" stroke-width=".25"/>
<path d="M83.7 127.9l1.5-.5v1z" fill="#f8fcff"/>
<path d="M83.7 127.9l1.5-.5v1z" fill="none" stroke="#000" stroke-width=".21"/>
<path d="M85.5 127.4l1.5 .5-1.5 .5z" fill="#f8fcff"/>
<path d="M85.5 127.4l1.5 .5-1.5 .5z" fill="none" stroke="#000" stroke-width=".21"/>
<path d="M83.7 130.4h7.6" fill="none" stroke="#000" stroke-width=".25"/>
<path d="M83.7 130.4l1.5-.5v1z" fill="#f8fcff"/>
<path d="M83.7 130.4l1.5-.5v1z" fill="none" stroke="#000" stroke-width=".21"/>
<path d="M85.5 129.9l1.5 .5-1.5 .5z" fill="#f8fcff"/>
<path d="M85.5 129.9l1.5 .5-1.5 .5z" fill="none" stroke="#000" stroke-width=".21"/>
<path d="M83.7 133h7.6" fill="none" stroke="#000" stroke-width=".25"/>
<path d="M83.7 133l1.5-.5v1z" fill="#f8fcff"/>
<path d="M83.7 133l1.5-.5v1z" fill="none" stroke="#000" stroke-width=".21"/>
<path d="M85.5 132.5l1.5 .5-1.5 .5z" fill="#f8fcff"/>
<path d="M85.5 132.5l1.5 .5-1.5 .5z" fill="none" stroke="#000" stroke-width=".21"/>
<path d="M83.7 135.5h7.6" fill="none" stroke="#000" stroke-width=".25"/>
<path d="M83.7 135.5l1.5-.5v1z" fill="#f8fcff"/>
<path d="M83.7 135.5l1.5-.5v1z" fill="none" stroke="#000" stroke-width=".21"/>
<path d="M85.5 135l1.5 .5-1.5 .5z" fill="#f8fcff"/>
<path d="M85.5 135l1.5 .5-1.5 .5z" fill="none" stroke="#000" stroke-width=".21"/>
<path d="M83.7 138h7.6" fill="none" stroke="#000" stroke-width=".25"/>
<path d="M83.7 138l1.5-.5v1.1z" fill="#f8fcff"/>
<path d="M83.7 138l1.5-.5v1.1z" fill="none" stroke="#000" stroke-width=".21"/>
<path d="M85.5 137.5l1.5 .5-1.5 .6z" fill="#f8fcff"/>
<path d="M85.5 137.5l1.5 .5-1.5 .6z" fill="none" stroke="#000" stroke-width=".21"/>
<path d="M83.7 140.6h7.6" fill="none" stroke="#000" stroke-width=".25"/>
<path d="M83.7 140.6l1.5-.5v1z" fill="#f8fcff"/>
<path d="M83.7 140.6l1.5-.5v1z" fill="none" stroke="#000" stroke-width=".21"/>
<path d="M85.5 140.1l1.5 .5-1.5 .5z" fill="#f8fcff"/>
<path d="M85.5 140.1l1.5 .5-1.5 .5z" fill="none" stroke="#000" stroke-width=".21"/>
<path d="M83.7 143.1h7.6" fill="none" stroke="#000" stroke-width=".25"/>
<path d="M83.7 143.1l1.5-.5v1z" fill="#f8fcff"/>
<path d="M83.7 143.1l1.5-.5v1z" fill="none" stroke="#000" stroke-width=".21"/>
<path d="M85.5 142.6l1.5 .5-1.5 .5z" fill="#f8fcff"/>
<path d="M85.5 142.6l1.5 .5-1.5 .5z" fill="none" stroke="#000" stroke-width=".21"/>
<path d="M83.7 145.7h7.6" fill="none" stroke="#000" stroke-width=".25"/>
<path d="M83.7 145.7l1.5-.5v1z" fill="#f8fcff"/>
<path d="M83.7 145.7l1.5-.5v1z" fill="none" stroke="#000" stroke-width=".21"/>
<path d="M85.5 145.2l1.5 .5-1.5 .5z" fill="#f8fcff"/>
<path d="M85.5 145.2l1.5 .5-1.5 .5z" fill="none" stroke="#000" stroke-width=".21"/>
<path d="M83.7 148.2h7.6" fill="none" stroke="#000" stroke-width=".25"/>
<path d="M83.7 148.2l1.5-.5v1z" fill="#f8fcff"/>
<path d="M83.7 148.2l1.5-.5v1z" fill="none" stroke="#000" stroke-width=".21"/>
<path d="M85.5 147.7l1.5 .5-1.5 .5z" fill="#f8fcff"/>
<path d="M85.5 147.7l1.5 .5-1.5 .5z" fill="none" stroke="#000" stroke-width=".21"/>
<path d="M83.7 150.7h7.6" fill="none" stroke="#000" stroke-width=".25"/>
<path d="M83.7 150.7l1.5-.5v1.1z" fill="#f8fcff"/>
<path d="M83.7 150.7l1.5-.5v1.1z" fill="none" stroke="#000" stroke-width=".21"/>
<path d="M85.5 150.2l1.5 .5-1.5 .6z" fill="#f8fcff"/>
<path d="M85.5 150.2l1.5 .5-1.5 .6z" fill="none" stroke="#000" stroke-width=".21"/>
<path d="M83.7 153.3h7.6" fill="none" stroke="#000" stroke-width=".25"/>
<path d="M83.7 153.3l1.5-.5v1z" fill="#f8fcff"/>
<path d="M83.7 153.3l1.5-.5v1z" fill="none" stroke="#000" stroke-width=".21"/>
<path d="M85.5 152.8l1.5 .5-1.5 .5z" fill="#f8fcff"/>
<path d="M85.5 152.8l1.5 .5-1.5 .5z" fill="none" stroke="#000" stroke-width=".21"/>
<path d="M83.7 155.8h7.6" fill="none" stroke="#000" stroke-width=".25"/>
<path d="M83.7 155.8l1.5-.5v1z" fill="#f8fcff"/>
<path d="M83.7 155.8l1.5-.5v1z" fill="none" stroke="#000" stroke-width=".21"/>
<path d="M85.5 155.3l1.5 .5-1.5 .5z" fill="#f8fcff"/>
<path d="M85.5 155.3l1.5 .5-1.5 .5z" fill="none" stroke="#000" stroke-width=".21"/>
<path d="M83.7 158.4h7.6" fill="none" stroke="#000" stroke-width=".25"/>
<path d="M83.7 158.4l1.5-.5v1z" fill="#f8fcff"/>
<path d="M83.7 158.4l1.5-.5v1z" fill="none" stroke="#000" stroke-width=".21"/>
<path d="M85.5 157.9l1.5 .5-1.5 .5z" fill="#f8fcff"/>
<path d="M85.5 157.9l1.5 .5-1.5 .5z" fill="none" stroke="#000" stroke-width=".21"/>
<path d="M83.7 160.9h7.6" fill="none" stroke="#000" stroke-width=".25"/>
<path d="M83.7 160.9l1.5-.5v1z" fill="#f8fcff"/>
<path d="M83.7 160.9l1.5-.5v1z" fill="none" stroke="#000" stroke-width=".21"/>
<path d="M85.5 160.4l1.5 .5-1.5 .5z" fill="#f8fcff"/>
<path d="M85.5 160.4l1.5 .5-1.5 .5z" fill="none" stroke="#000" stroke-width=".21"/>
<circle cx="162.4" cy="23.7" r=".51" fill="#000080"/>
<circle cx="162.4" cy="23.7" r=".51" fill="none" stroke="#000080" stroke-width=".21"/>
<circle cx="162.4" cy="33.9" r=".51" fill="#000080"/>
<circle cx="162.4" cy="33.9" r=".51" fill="none" stroke="#000080" stroke-width=".21"/>
<path d="M162.4 23.7v2" fill="none" stroke="#000" stroke-width=".25"/>
<circle cx="162.4" cy="23.7" r=".51" fill="#000080"/>
<circle cx="162.4" cy="23.7" r=".51" fill="none" stroke="#000080" stroke-width=".21"/>
<path d="M162.4 31.9v2" fill="none" stroke="#000" stroke-width=".25"/>
<circle cx="162.4" cy="33.9" r=".51" fill="#000080"/>
<circle cx="162.4" cy="33.9" r=".51" fill="none" stroke="#000080" stroke-width=".21"/>
<path d="M161.5 25.8h2v6h-2z" fill="none" stroke="#00f" stroke-width=".25"/>
<circle cx="162.4" cy="39" r=".51" fill="#000080"/>
<circle cx="162.4" cy="39" r=".51" fill="none" stroke="#000080" stroke-width=".21"/>
<circle cx="162.4" cy="49.1" r=".51" fill="#000080"/>
<circle cx="162.4" cy="49.1" r=".51" fill="none" stroke="#000080" stroke-width=".21"/>
<path d="M162.4 39v2" fill="none" stroke="#000" stroke-width=".25"/>
<circle cx="162.4" cy="39" r=".51" fill="#000080"/>
<circle cx="162.4" cy="39" r=".51" fill="none" stroke="#000080" stroke-width=".21"/>
<path d="M162.4 47.1v2" fill="none" stroke="#000" stroke-width=".25"/>
<circle cx="162.4" cy="49.1" r=".51" fill="#000080"/>
<circle cx="162.4" cy="49.1" r=".51" fill="none" stroke="#000080" stroke-width=".21"/>
<path d="M161.5 41.1h2v6h-2z" fill="none" stroke="#00f" stroke-width=".25"/>
<circle cx="162.4" cy="54.2" r=".51" fill="#000080"/>
<circle cx="162.4" cy="54.2" r=".51" fill="none" stroke="#000080" stroke-width=".21"/>
<circle cx="162.4" cy="64.4" r=".51" fill="#000080"/>
<circle cx="162.4" cy="64.4" r=".51" fill="none" stroke="#000080" stroke-width=".21"/>
<path d="M162.4 54.2v2" fill="none" stroke="#000" stroke-width=".25"/>
<circle cx="162.4" cy="54.2" r=".51" fill="#000080"/>
<circle cx="162.4" cy="54.2" r=".51" fill="none" stroke="#000080" stroke-width=".21"/>
<path d="M162.4 62.4v2" fill="none" stroke="#000" stroke-width=".25"/>
<circle cx="162.4" cy="64.4" r=".51" fill="#000080"/>
<circle cx="162.4" cy="64.4" r=".51" fill="none" stroke="#000080" stroke-width=".21"/>
<path d="M161.5 56.3h2v6h-2z" fill="none" stroke="#00f" stroke-width=".25"/>
<circle cx="162.4" cy="69.5" r=".51" fill="#000080"/>
<circle cx="162.4" cy="69.5" r=".51" fill="none" stroke="#000080" stroke-width=".21"/>
<circle cx="162.4" cy="79.6" r=".51" fill="#000080"/>
<circle cx="162.4" cy="79.6" r=".51" fill="none" stroke="#000080" stroke-width=".21"/>
<path d="M162.4 69.5v2" fill="none" stroke="#000" stroke-width=".25"/>
<circle cx="162.4" cy="69.5" r=".51" fill="#000080"/>
<circle cx="162.4" cy="69.5" r=".51" fill="none" stroke="#000080" stroke-width=".21"/>
<path d="M162.4 77.6v2" fill="none" stroke="#000" stroke-width=".25"/>
<circle cx="162.4" cy="79.6" r=".51" fill="#000080"/>
<circle cx="162.4" cy="79.6" r=".51" fill="none" stroke="#000080" stroke-width=".21"/>
<path d="M161.5 71.5h2v6h-2z" fill="none" stroke="#00f" stroke-width=".25"/>
<circle cx="162.4" cy="84.7" r=".51" fill="#000080"/>
<circle cx="162.4" cy="84.7" r=".51" fill="none" stroke="#000080" stroke-width=".21"/>
<circle cx="162.4" cy="94.9" r=".51" fill="#000080"/>
<circle cx="162.4" cy="94.9" r=".51" fill="none" stroke="#000080" stroke-width=".21"/>
<path d="M162.4 84.7v2" fill="none" stroke="#000" stroke-width=".25"/>
<circle cx="162.4" cy="84.7" r=".51" fill="#000080"/>
<circle cx="162.4" cy="84.7" r=".51" fill="none" stroke="#000080" stroke-width=".21"/>
<path d="M162.4 92.9v2" fill="none" stroke="#000" stroke-width=".25"/>
<circle cx="162.4" cy="94.9" r=".51" fill="#000080"/>
<circle cx="162.4" cy="94.9" r=".51" fill="none" stroke="#000080" stroke-width=".21"/>
<path d="M161.5 86.8h2v6h-2z" fill="none" stroke="#00f" stroke-width=".25"/>
<circle cx="162.4" cy="100" r=".51" fill="#000080"/>
<circle cx="162.4" cy="100" r=".51" fill="none" stroke="#000080" stroke-width=".21"/>
<circle cx="162.4" cy="110.1" r=".51" fill="#000080"/>
<circle cx="162.4" cy="110.1" r=".51" fill="none" stroke="#000080" stroke-width=".21"/>
<path d="M162.4 99.9v2" fill="none" stroke="#000" stroke-width=".25"/>
<circle cx="162.4" cy="100" r=".51" fill="#000080"/>
<circle cx="162.4" cy="100" r=".51" fill="none" stroke="#000080" stroke-width=".21"/>
<path d="M162.4 108.1v2" fill="none" stroke="#000" stroke-width=".25"/>
<circle cx="162.4" cy="110.1" r=".51" fill="#000080"/>
<circle cx="162.4" cy="110.1" r=".51" fill="none" stroke="#000080" stroke-width=".21"/>
<path d="M161.5 102h2v6h-2z" fill="none" stroke="#00f" stroke-width=".25"/>
<circle cx="162.4" cy="115.2" r=".51" fill="#000080"/>
<circle cx="162.4" cy="115.2" r=".51" fill="none" stroke="#000080" stroke-width=".21"/>
<circle cx="162.4" cy="125.4" r=".51" fill="#000080"/>
<circle cx="162.4" cy="125.4" r=".51" fill="none" stroke="#000080" stroke-width=".21"/>
<path d="M162.4 115.2v2" fill="none" stroke="#000" stroke-width=".25"/>
<circle cx="162.4" cy="115.2" r=".51" fill="#000080"/>
<circle cx="162.4" cy="115.2" r=".51" fill="none" stroke="#000080" stroke-width=".21"/>
<path d="M162.4 123.3v2" fill="none" stroke="#000" stroke-width=".25"/>
<circle cx="162.4" cy="125.4" r=".51" fill="#000080"/>
<circle cx="162.4" cy="125.4" r=".51" fill="none" stroke="#000080" stroke-width=".21"/>
<path d="M161.5 117.3h2v6h-2z" fill="none" stroke="#00f" stroke-width=".25"/>
<circle cx="162.4" cy="130.4" r=".51" fill="#000080"/>
<circle cx="162.4" cy="130.4" r=".51" fill="none" stroke="#000080" stroke-width=".21"/>
<circle cx="162.4" cy="140.6" r=".51" fill="#000080"/>
<circle cx="162.4" cy="140.6" r=".51" fill="none" stroke="#000080" stroke-width=".21"/>
<path d="M162.4 130.4v2" fill="none" stroke="#000" stroke-width=".25"/>
<circle cx="162.4" cy="130.4" r=".51" fill="#000080"/>
<circle cx="162.4" cy="130.4" r=".51" fill="none" stroke="#000080" stroke-width=".21"/>
<path d="M162.4 138.6v2" fill="none" stroke="#000" stroke-width=".25"/>
<circle cx="162.4" cy="140.6" r=".51" fill="#000080"/>
<circle cx="162.4" cy="140.6" r=".51" fill="none" stroke="#000080" stroke-width=".21"/>
<path d="M161.5 132.5h2v6h-2z" fill="none" stroke="#00f" stroke-width=".25"/>
<circle cx="162.4" cy="145.7" r=".51" fill="#000080"/>
<circle cx="162.4" cy="145.7" r=".51" fill="none" stroke="#000080" stroke-width=".21"/>
<circle cx="162.4" cy="155.8" r=".51" fill="#000080"/>
<circle cx="162.4" cy="155.8" r=".51" fill="none" stroke="#000080" stroke-width=".21"/>
<path d="M162.4 145.7v2" fill="none" stroke="#000" stroke-width=".25"/>
<circle cx="162.4" cy="145.7" r=".51" fill="#000080"/>
<circle cx="162.4" cy="145.7" r=".51" fill="none" stroke="#000080" stroke-width=".21"/>
<path d="M162.4 153.8v2" fill="none" stroke="#000" stroke-width=".25"/>
<circle cx="162.4" cy="155.8" r=".51" fill="#000080"/>
<circle cx="162.4" cy="155.8" r=".51" fill="none" stroke="#000080" stroke-width=".21"/>
<path d="M161.5 147.7h2v6h-2z" fill="none" stroke="#00f" stroke-width=".25"/>
<circle cx="162.4" cy="160.9" r=".51" fill="#000080"/>
<circle cx="162.4" cy="160.9" r=".51" fill="none" stroke="#000080" stroke-width=".21"/>
<circle cx="162.4" cy="171.1" r=".51" fill="#000080"/>
<circle cx="162.4" cy="171.1" r=".51" fill="none" stroke="#000080" stroke-width=".21"/>
<path d="M162.4 160.9v2" fill="none" stroke="#000" stroke-width=".25"/>
<circle cx="162.4" cy="160.9" r=".51" fill="#000080"/>
<circle cx="162.4" cy="160.9" r=".51" fill="none" stroke="#000080" stroke-width=".21"/>
<path d="M162.4 169.1v2" fill="none" stroke="#000" stroke-width=".25"/>
<circle cx="162.4" cy="171.1" r=".51" fill="#000080"/>
<circle cx="162.4" cy="171.1" r=".51" fill="none" stroke="#000080" stroke-width=".21"/>
<path d="M161.5 163h2v6h-2z" fill="none" stroke="#00f" stroke-width=".25"/>
<path d="M236.1 92.3h20.3v15.3h-20.3z" fill-rule="evenodd" fill="#ffffb0"/>
<path d="M236.1 92.3h20.3v15.3h-20.3z" fill="none" stroke="#800000" stroke-width=".21"/>
<path d="M215.8 97.4v2.5M228.5 94.9h7.6M228.5 99.9h7.6M256.4 94.9h7.6M215.8 105v2.6M228.5 105h7.6" fill="none" stroke="#000" stroke-width=".25"/>
<path d="M215.8 99.9v2.1M213.8 102h4M213.8 103h4M215.8 103v2" fill="none" stroke="#00f" stroke-width=".25"/>
<path d="M209.4 89.8h2.6M210.7 89.8v2.5M213.2 112.6h5.1M214 113.4h3.6M214.8 114.2h2M215.5 114.9h.5M215.8 110.1v2.5M223.4 112.6h5.1M224.2 113.4h3.5M224.9 114.2h2.1M225.7 114.9h.5M225.9 110.1v2.5" fill="none" stroke="#800000" stroke-width=".25"/>
<path d="M157.4 23.7h20.3" fill="none" stroke="#000080" stroke-width=".25"/>
<circle cx="162.4" cy="23.7" r=".51" fill="#000080"/>
<circle cx="162.4" cy="23.7" r=".51" fill="none" stroke="#000080" stroke-width=".21"/>
<path d="M157.4 33.9h20.3" fill="none" stroke="#000080" stroke-width=".25"/>
<circle cx="162.4" cy="33.9" r=".51" fill="#000080"/>
<circle cx="162.4" cy="33.9" r=".51" fill="none" stroke="#000080" stroke-width=".21"/>
<path d="M157.4 39h20.3" fill="none" stroke="#000080" stroke-width=".25"/>
<circle cx="162.4" cy="39" r=".51" fill="#000080"/>
<circle cx="162.4" cy="39" r=".51" fill="none" stroke="#000080" stroke-width=".21"/>
<path d="M157.4 49.1h20.3" fill="none" stroke="#000080" stroke-width=".25"/>
<circle cx="162.4" cy="49.1" r=".51" fill="#000080"/>
<circle cx="162.4" cy="49.1" r=".51" fill="none" stroke="#000080" stroke-width=".21"/>
<path d="M157.4 54.2h20.3" fill="none" stroke="#000080" stroke-width=".25"/>
<circle cx="162.4" cy="54.2" r=".51" fill="#000080"/>
<circle cx="162.4" cy="54.2" r=".51" fill="none" stroke="#000080" stroke-width=".21"/>
<path d="M157.4 64.4h20.3" fill="none" stroke="#000080" stroke-width=".25"/>
<circle cx="162.4" cy="64.4" r=".51" fill="#000080"/>
<circle cx="162.4" cy="64.4" r=".51" fill="none" stroke="#000080" stroke-width=".21"/>
<path d="M157.4 69.5h20.3" fill="none" stroke="#000080" stroke-width=".25"/>
<circle cx="162.4" cy="69.5" r=".51" fill="#000080"/>
<circle cx="162.4" cy="69.5" r=".51" fill="none" stroke="#000080" stroke-width=".21"/>
<path d="M157.4 79.6h20.3" fill="none" stroke="#000080" stroke-width=".25"/>
<circle cx="162.4" cy="79.6" r=".51" fill="#000080"/>
<circle cx="162.4" cy="79.6" r=".51" fill="none" stroke="#000080" stroke-width=".21"/>
<path d="M157.4 84.7h20.3" fill="none" stroke="#000080" stroke-width=".25"/>
<circle cx="162.4" cy="84.7" r=".51" fill="#000080"/>
<circle cx="162.4" cy="84.7" r=".51" fill="none" stroke="#000080" stroke-width=".21"/>
<path d="M157.4 94.9h20.3" fill="none" stroke="#000080" stroke-width=".25"/>
<circle cx="162.4" cy="94.9" r=".51" fill="#000080"/>
<circle cx="162.4" cy="94.9" r=".51" fill="none" stroke="#000080" stroke-width=".21"/>
<path d="M157.4 99.9h20.3" fill="none" stroke="#000080" stroke-width=".25"/>
<circle cx="162.4" cy="100" r=".51" fill="#000080"/>
<circle cx="162.4" cy="100" r=".51" fill="none" stroke="#000080" stroke-width=".21"/>
<path d="M157.4 110.1h20.3" fill="none" stroke="#000080" stroke-width=".25"/>
<circle cx="162.4" cy="110.1" r=".51" fill="#000080"/>
<circle cx="162.4" cy="110.1" r=".51" fill="none" stroke="#000080" stroke-width=".21"/>
<path d="M157.4 115.2h20.3" fill="none" stroke="#000080" stroke-width=".25"/>
<circle cx="162.4" cy="115.2" r=".51" fill="#000080"/>
<circle cx="162.4" cy="115.2" r=".51" fill="none" stroke="#000080" stroke-width=".21"/>
<path d="M157.4 125.3h20.3" fill="none" stroke="#000080" stroke-width=".25"/>
<circle cx="162.4" cy="125.4" r=".51" fill="#000080"/>
<circle cx="162.4" cy="125.4" r=".51" fill="none" stroke="#000080" stroke-width=".21"/>
<path d="M157.4 130.4h20.3" fill="none" stroke="#000080" stroke-width=".25"/>
<circle cx="162.4" cy="130.4" r=".51" fill="#000080"/>
<circle cx="162.4" cy="130.4" r=".51" fill="none" stroke="#000080" stroke-width=".21"/>
<path d="M157.4 140.6h20.3" fill="none" stroke="#000080" stroke-width=".25"/>
<circle cx="162.4" cy="140.6" r=".51" fill="#000080"/>
<circle cx="162.4" cy="140.6" r=".51" fill="none" stroke="#000080" stroke-width=".21"/>
<path d="M157.4 145.7h20.3" fill="none" stroke="#000080" stroke-width=".25"/>
<circle cx="162.4" cy="145.7" r=".51" fill="#000080"/>
<circle cx="162.4" cy="145.7" r=".51" fill="none" stroke="#000080" stroke-width=".21"/>
<path d="M157.4 155.8h20.3" fill="none" stroke="#000080" stroke-width=".25"/>
<circle cx="162.4" cy="155.8" r=".51" fill="#000080"/>
<circle cx="162.4" cy="155.8" r=".51" fill="none" stroke="#000080" stroke-width=".21"/>
<path d="M157.4 160.9h20.3" fill="none" stroke="#000080" stroke-width=".25"/>
<circle cx="162.4" cy="160.9" r=".51" fill="#000080"/>
<circle cx="162.4" cy="160.9" r=".51" fill="none" stroke="#000080" stroke-width=".21"/>
<path d="M157.4 171.1h20.3" fill="none" stroke="#000080" stroke-width=".25"/>
<circle cx="162.4" cy="171.1" r=".51" fill="#000080"/>
<circle cx="162.4" cy="171.1" r=".51" fill="none" stroke="#000080" stroke-width=".21"/>
<g fill="none" stroke="#000080" stroke-width=".25">
<path d="M91.3 36.4h20.3M91.3 39h20.3M91.3 41.5h20.3M91.3 44.1h20.3M91.3 46.6h20.3M91.3 49.1h20.3M91.3 51.7h20.3M91.3 54.2h20.3M91.3 56.8h20.3M91.3 59.3h20.3M91.3 61.8h20.3M91.3 64.4h20.3"/>
<path d="M91.3 66.9h20.3M91.3 69.5h20.3M91.3 72h20.3M91.3 74.5h20.3M91.3 79.6h20.3M91.3 82.2h20.3M91.3 84.7h20.3M91.3 87.2h20.3M91.3 89.8h20.3M91.3 92.3h20.3M91.3 94.9h20.3M91.3 97.4h20.3"/>
<path d="M91.3 99.9h20.3M225.9 94.9v5h2.6M91.3 110.1h20.3M91.3 112.6h20.3M91.3 105h20.3M91.3 107.6h20.3M91.3 102.5h20.3M91.3 115.2h20.3M91.3 117.7h20.3M91.3 135.5h20.3M91.3 138h20.3M91.3 130.4h20.3"/>
<path d="M91.3 133h20.3M91.3 125.3h20.3M91.3 127.9h20.3M91.3 120.3h20.3M91.3 122.8h20.3M91.3 155.8h20.3M91.3 158.4h20.3M91.3 150.7h20.3M91.3 153.3h20.3M91.3 145.7h20.3M91.3 148.2h20.3M91.3 140.6h20.3"/>
<path d="M91.3 143.1h20.3M91.3 160.9h20.3"/>
</g>
<circle cx="225.9" cy="94.9" r=".51" fill="#000080"/>
<circle cx="225.9" cy="94.9" r=".51" fill="none" stroke="#000080" stroke-width=".21"/>
<path d="M225.9 94.9h2.6M215.8 107.6v2.5" fill="none" stroke="#000080" stroke-width=".25"/>
<circle cx="225.9" cy="94.9" r=".51" fill="#000080"/>
<circle cx="225.9" cy="94.9" r=".51" fill="none" stroke="#000080" stroke-width=".21"/>
<path d="M225.9 94.9h-10.1v2.5" fill="none" stroke="#000080" stroke-width=".25"/>
<circle cx="225.9" cy="94.9" r=".51" fill="#000080"/>
<circle cx="225.9" cy="94.9" r=".51" fill="none" stroke="#000080" stroke-width=".21"/>
<circle cx="215.8" cy="94.9" r=".51" fill="#000080"/>
<circle cx="215.8" cy="94.9" r=".51" fill="none" stroke="#000080" stroke-width=".21"/>
<path d="M210.7 92.3v2.6h5.1M228.5 105h-2.6v5.1" fill="none" stroke="#000080" stroke-width=".25"/>
<circle cx="215.8" cy="94.9" r=".51" fill="#000080"/>
<circle cx="215.8" cy="94.9" r=".51" fill="none" stroke="#000080" stroke-width=".21"/>
<path d="M91.3 77.1h20.3M264 94.9h7.7" fill="none" stroke="#000080" stroke-width=".25"/>
<use href="#words"/>
</svg>
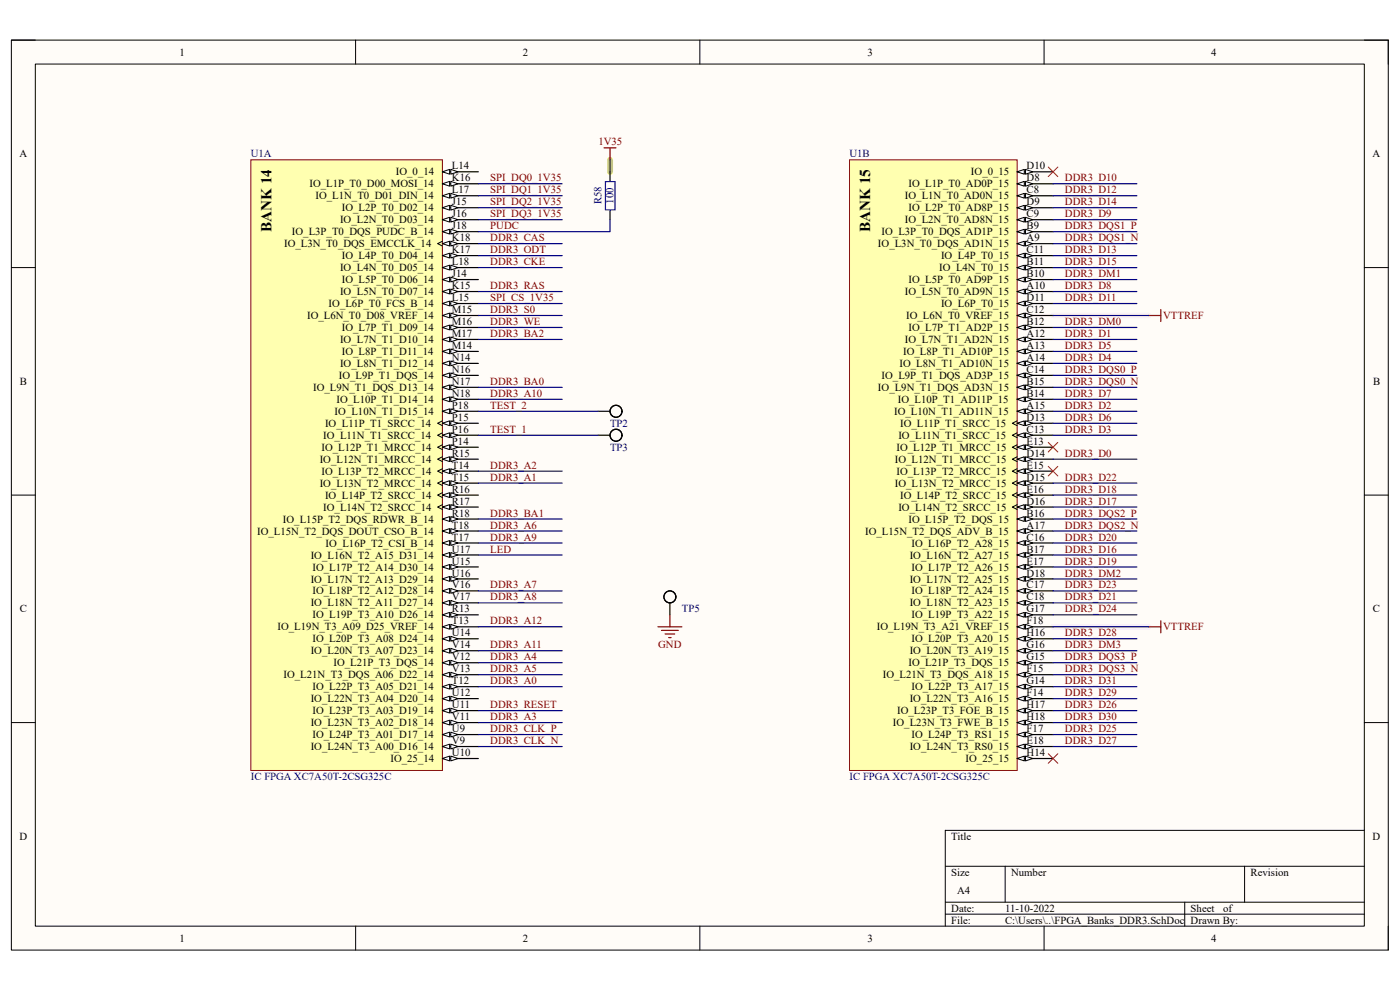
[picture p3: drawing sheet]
<svg xmlns="http://www.w3.org/2000/svg" width="297mm" height="210mm" viewBox="0 0 297 210" stroke-linecap="round" stroke-linejoin="round" font-family="sans-serif">
<defs><g id="words">
<g font-size="3.2">
<text x="57.6" y="49.1" transform="rotate(-90 57.6 49.1)">BANK 14</text>
<text x="184.6" y="49.1" transform="rotate(-90 184.6 49.1)">BANK 15</text>
</g>
<g font-size="2.3">
<text x="38.1" y="11.8">1</text>
<text x="110.9" y="11.8">2</text>
<text x="184" y="11.8">3</text>
<text x="256.9" y="11.8">4</text>
<text x="4.1" y="33.4">A</text>
<text x="95.9" y="35.9">L14</text>
<text x="217.8" y="35.9">D10</text>
<text x="291.2" y="33.4">A</text>
<text x="65.7" y="39.8">IO_L1P_T0_D00_MOSI_14</text>
<text x="84" y="37.2">IO_0_14</text>
<text x="95.9" y="38.5">K16</text>
<text x="95.9" y="41">L17</text>
<text x="192.7" y="39.8">IO_L1P_T0_AD0P_15</text>
<text x="206" y="37.2">IO_0_15</text>
<text x="217.8" y="38.5">D8</text>
<text x="217.8" y="41">C8</text>
<text x="66.9" y="42.3">IO_L1N_T0_D01_DIN_14</text>
<text x="72.1" y="47.4">IO_L2N_T0_D03_14</text>
<text x="72.5" y="44.8">IO_L2P_T0_D02_14</text>
<text x="95.9" y="43.6">J15</text>
<text x="95.9" y="46.1">J16</text>
<text x="192" y="42.3">IO_L1N_T0_AD0N_15</text>
<text x="192" y="47.4">IO_L2N_T0_AD8N_15</text>
<text x="192.7" y="44.8">IO_L2P_T0_AD8P_15</text>
<text x="217.8" y="43.6">D9</text>
<text x="217.8" y="46.1">C9</text>
<text x="60.3" y="52.5">IO_L3N_T0_DQS_EMCCLK_14</text>
<text x="61.9" y="49.9">IO_L3P_T0_DQS_PUDC_B_14</text>
<text x="95.9" y="48.6">J18</text>
<text x="95.9" y="51.2">K18</text>
<text x="95.9" y="53.7">K17</text>
<text x="186.3" y="52.5">IO_L3N_T0_DQS_AD1N_15</text>
<text x="187" y="49.9">IO_L3P_T0_DQS_AD1P_15</text>
<text x="217.8" y="48.6">B9</text>
<text x="217.8" y="51.2">A9</text>
<text x="217.8" y="53.7">C11</text>
<text x="72.1" y="57.5">IO_L4N_T0_D05_14</text>
<text x="72.5" y="55">IO_L4P_T0_D04_14</text>
<text x="95.9" y="56.3">L18</text>
<text x="95.9" y="58.8">J14</text>
<text x="199.3" y="57.5">IO_L4N_T0_15</text>
<text x="199.6" y="55">IO_L4P_T0_15</text>
<text x="217.8" y="56.3">B11</text>
<text x="217.8" y="58.8">B10</text>
<text x="69.7" y="65.2">IO_L6P_T0_FCS_B_14</text>
<text x="72.1" y="62.6">IO_L5N_T0_D07_14</text>
<text x="72.5" y="60.1">IO_L5P_T0_D06_14</text>
<text x="95.9" y="61.3">K15</text>
<text x="95.9" y="63.9">L15</text>
<text x="192" y="62.6">IO_L5N_T0_AD9N_15</text>
<text x="192.7" y="60.1">IO_L5P_T0_AD9P_15</text>
<text x="199.6" y="65.2">IO_L6P_T0_15</text>
<text x="217.8" y="61.3">A10</text>
<text x="217.8" y="63.9">D11</text>
<text x="65.2" y="67.7">IO_L6N_T0_D08_VREF_14</text>
<text x="72.5" y="70.2">IO_L7P_T1_D09_14</text>
<text x="95.9" y="66.4">M15</text>
<text x="95.9" y="69">M16</text>
<text x="95.9" y="71.5">M17</text>
<text x="192.2" y="67.7">IO_L6N_T0_VREF_15</text>
<text x="192.7" y="70.2">IO_L7P_T1_AD2P_15</text>
<text x="217.8" y="66.4">C12</text>
<text x="217.8" y="69">B12</text>
<text x="217.8" y="71.5">A12</text>
<text x="72.1" y="72.8">IO_L7N_T1_D10_14</text>
<text x="72.1" y="77.9">IO_L8N_T1_D12_14</text>
<text x="72.5" y="75.3">IO_L8P_T1_D11_14</text>
<text x="95.9" y="74">M14</text>
<text x="95.9" y="76.6">N14</text>
<text x="190.8" y="77.9">IO_L8N_T1_AD10N_15</text>
<text x="191.6" y="75.3">IO_L8P_T1_AD10P_15</text>
<text x="192" y="72.8">IO_L7N_T1_AD2N_15</text>
<text x="217.8" y="74">A13</text>
<text x="217.8" y="76.6">A14</text>
<text x="4.2" y="81.7">B</text>
<text x="66.4" y="82.9">IO_L9N_T1_DQS_D13_14</text>
<text x="71.9" y="80.4">IO_L9P_T1_DQS_14</text>
<text x="95.9" y="79.1">N16</text>
<text x="95.9" y="81.7">N17</text>
<text x="186.3" y="82.9">IO_L9N_T1_DQS_AD3N_15</text>
<text x="187" y="80.4">IO_L9P_T1_DQS_AD3P_15</text>
<text x="217.8" y="79.1">C14</text>
<text x="217.8" y="81.7">B15</text>
<text x="291.3" y="81.7">B</text>
<text x="71" y="88">IO_L10N_T1_D15_14</text>
<text x="71.4" y="85.5">IO_L10P_T1_D14_14</text>
<text x="95.9" y="84.2">N18</text>
<text x="95.9" y="86.7">P18</text>
<text x="95.9" y="89.3">P15</text>
<text x="189.7" y="88">IO_L10N_T1_AD11N_15</text>
<text x="190.5" y="85.5">IO_L10P_T1_AD11P_15</text>
<text x="217.8" y="84.2">B14</text>
<text x="217.8" y="86.7">A15</text>
<text x="217.8" y="89.3">D13</text>
<text x="68.2" y="95.6">IO_L12P_T1_MRCC_14</text>
<text x="68.6" y="93.1">IO_L11N_T1_SRCC_14</text>
<text x="69" y="90.6">IO_L11P_T1_SRCC_14</text>
<text x="95.9" y="91.8">P16</text>
<text x="95.9" y="94.4">P14</text>
<text x="190.2" y="95.6">IO_L12P_T1_MRCC_15</text>
<text x="190.6" y="93.1">IO_L11N_T1_SRCC_15</text>
<text x="191" y="90.6">IO_L11P_T1_SRCC_15</text>
<text x="217.8" y="91.8">C13</text>
<text x="217.8" y="94.4">E13</text>
<text x="67.8" y="98.2">IO_L12N_T1_MRCC_14</text>
<text x="68.2" y="100.7">IO_L13P_T2_MRCC_14</text>
<text x="95.9" y="96.9">R15</text>
<text x="95.9" y="99.4">T14</text>
<text x="95.9" y="102">T15</text>
<text x="189.8" y="98.2">IO_L12N_T1_MRCC_15</text>
<text x="190.2" y="100.7">IO_L13P_T2_MRCC_15</text>
<text x="217.8" y="96.9">D14</text>
<text x="217.8" y="99.4">E15</text>
<text x="217.8" y="102">D15</text>
<text x="67.8" y="103.3">IO_L13N_T2_MRCC_14</text>
<text x="69" y="105.8">IO_L14P_T2_SRCC_14</text>
<text x="95.9" y="104.5">R16</text>
<text x="95.9" y="107.1">R17</text>
<text x="189.8" y="103.3">IO_L13N_T2_MRCC_15</text>
<text x="191" y="105.8">IO_L14P_T2_SRCC_15</text>
<text x="217.8" y="104.5">E16</text>
<text x="217.8" y="107.1">D16</text>
<text x="54.6" y="113.4">IO_L15N_T2_DQS_DOUT_CSO_B_14</text>
<text x="60" y="110.9">IO_L15P_T2_DQS_RDWR_B_14</text>
<text x="68.6" y="108.3">IO_L14N_T2_SRCC_14</text>
<text x="95.9" y="109.6">R18</text>
<text x="95.9" y="112.1">T18</text>
<text x="183.6" y="113.4">IO_L15N_T2_DQS_ADV_B_15</text>
<text x="190.6" y="108.3">IO_L14N_T2_SRCC_15</text>
<text x="192.7" y="110.9">IO_L15P_T2_DQS_15</text>
<text x="217.8" y="109.6">B16</text>
<text x="217.8" y="112.1">A17</text>
<text x="65.9" y="118.5">IO_L16N_T2_A15_D31_14</text>
<text x="69.1" y="116">IO_L16P_T2_CSI_B_14</text>
<text x="95.9" y="114.7">T17</text>
<text x="95.9" y="117.2">U17</text>
<text x="95.9" y="119.8">U15</text>
<text x="193" y="118.5">IO_L16N_T2_A27_15</text>
<text x="193.4" y="116">IO_L16P_T2_A28_15</text>
<text x="217.8" y="114.7">C16</text>
<text x="217.8" y="117.2">B17</text>
<text x="217.8" y="119.8">E17</text>
<text x="65.9" y="123.6">IO_L17N_T2_A13_D29_14</text>
<text x="66.3" y="121">IO_L17P_T2_A14_D30_14</text>
<text x="95.9" y="122.3">U16</text>
<text x="95.9" y="124.8">V16</text>
<text x="193" y="123.6">IO_L17N_T2_A25_15</text>
<text x="193.4" y="121">IO_L17P_T2_A26_15</text>
<text x="217.8" y="122.3">D18</text>
<text x="217.8" y="124.8">C17</text>
<text x="4.2" y="129.9">C</text>
<text x="65.9" y="128.7">IO_L18N_T2_A11_D27_14</text>
<text x="66.3" y="126.1">IO_L18P_T2_A12_D28_14</text>
<text x="66.3" y="131.2">IO_L19P_T3_A10_D26_14</text>
<text x="95.9" y="127.4">V17</text>
<text x="95.9" y="129.9">R13</text>
<text x="193" y="128.7">IO_L18N_T2_A23_15</text>
<text x="193.4" y="126.1">IO_L18P_T2_A24_15</text>
<text x="193.4" y="131.2">IO_L19P_T3_A22_15</text>
<text x="217.8" y="127.4">C18</text>
<text x="217.8" y="129.9">G17</text>
<text x="291.3" y="129.9">C</text>
<text x="58.9" y="133.7">IO_L19N_T3_A09_D25_VREF_14</text>
<text x="66.3" y="136.3">IO_L20P_T3_A08_D24_14</text>
<text x="95.9" y="132.5">T13</text>
<text x="95.9" y="135">U14</text>
<text x="95.9" y="137.5">V14</text>
<text x="186" y="133.7">IO_L19N_T3_A21_VREF_15</text>
<text x="193.4" y="136.3">IO_L20P_T3_A20_15</text>
<text x="217.8" y="132.5">F18</text>
<text x="217.8" y="135">H16</text>
<text x="217.8" y="137.5">G16</text>
<text x="60.2" y="143.9">IO_L21N_T3_DQS_A06_D22_14</text>
<text x="65.9" y="138.8">IO_L20N_T3_A07_D23_14</text>
<text x="70.7" y="141.4">IO_L21P_T3_DQS_14</text>
<text x="95.9" y="140.1">V12</text>
<text x="95.9" y="142.6">V13</text>
<text x="187.3" y="143.9">IO_L21N_T3_DQS_A18_15</text>
<text x="192.7" y="141.4">IO_L21P_T3_DQS_15</text>
<text x="193" y="138.8">IO_L20N_T3_A19_15</text>
<text x="217.8" y="140.1">G15</text>
<text x="217.8" y="142.6">F15</text>
<text x="65.9" y="149">IO_L22N_T3_A04_D20_14</text>
<text x="66.3" y="146.4">IO_L22P_T3_A05_D21_14</text>
<text x="95.9" y="145.2">T12</text>
<text x="95.9" y="147.7">U12</text>
<text x="193" y="149">IO_L22N_T3_A16_15</text>
<text x="193.4" y="146.4">IO_L22P_T3_A17_15</text>
<text x="217.8" y="145.2">G14</text>
<text x="217.8" y="147.7">F14</text>
<text x="65.9" y="154.1">IO_L23N_T3_A02_D18_14</text>
<text x="66.3" y="151.5">IO_L23P_T3_A03_D19_14</text>
<text x="95.9" y="150.2">U11</text>
<text x="95.9" y="152.8">V11</text>
<text x="95.9" y="155.3">U9</text>
<text x="189.4" y="154.1">IO_L23N_T3_FWE_B_15</text>
<text x="190.3" y="151.5">IO_L23P_T3_FOE_B_15</text>
<text x="217.8" y="150.2">H17</text>
<text x="217.8" y="152.8">H18</text>
<text x="217.8" y="155.3">F17</text>
<text x="65.9" y="159.1">IO_L24N_T3_A00_D16_14</text>
<text x="66.3" y="156.6">IO_L24P_T3_A01_D17_14</text>
<text x="82.8" y="161.7">IO_25_14</text>
<text x="95.9" y="157.9">V9</text>
<text x="95.9" y="160.4">U10</text>
<text x="193" y="159.1">IO_L24N_T3_RS0_15</text>
<text x="193.4" y="156.6">IO_L24P_T3_RS1_15</text>
<text x="204.9" y="161.7">IO_25_15</text>
<text x="217.8" y="157.9">E18</text>
<text x="217.8" y="160.4">H14</text>
<text x="4.1" y="178.2">D</text>
<text x="201.8" y="178.2">Title</text>
<text x="291.2" y="178.2">D</text>
<text x="201.8" y="185.8">Size</text>
<text x="214.5" y="185.8">Number</text>
<text x="265.3" y="185.8">Revision</text>
<text x="203.1" y="189.6">A4</text>
<text x="201.8" y="193.4">Date:</text>
<text x="201.8" y="196">File:</text>
<text x="213.2" y="196">C:\Users\..\FPGA_Banks_DDR3.SchDoc Drawn By:</text>
<text x="213.2" y="193.4">11-10-2022</text>
<text x="252.6" y="193.4">Sheet</text>
<text x="259.5" y="193.4">of</text>
<text x="38.1" y="199.8">1</text>
<text x="110.9" y="199.8">2</text>
<text x="184" y="199.8">3</text>
<text x="256.9" y="199.8">4</text>
</g>
<g font-size="2.3" fill="#000080">
<text x="53.2" y="33.4">U1A</text>
<text x="180.2" y="33.4">U1B</text>
<text x="127.6" y="43.3" transform="rotate(-90 127.6 43.3)">R58</text>
<text x="130.2" y="43.2" transform="rotate(-90 130.2 43.2)">100</text>
<text x="129.4" y="90.6">TP2</text>
<text x="129.4" y="95.6">TP3</text>
<text x="144.7" y="129.9">TP5</text>
<text x="53.2" y="165.5">IC FPGA XC7A50T-2CSG325C</text>
<text x="180.2" y="165.5">IC FPGA XC7A50T-2CSG325C</text>
</g>
<g font-size="2.3" fill="#800000">
<text x="127" y="30.9">1V35</text>
<text x="104" y="38.5">SPI_DQ0_1V35</text>
<text x="104" y="41">SPI_DQ1_1V35</text>
<text x="225.9" y="38.5">DDR3_D10</text>
<text x="225.9" y="41">DDR3_D12</text>
<text x="104" y="43.6">SPI_DQ2_1V35</text>
<text x="104" y="46.1">SPI_DQ3_1V35</text>
<text x="225.9" y="43.6">DDR3_D14</text>
<text x="225.9" y="46.1">DDR3_D9</text>
<text x="104" y="53.7">DDR3_ODT</text>
<text x="104" y="51.2">DDR3_CAS</text>
<text x="104" y="48.6">PUDC</text>
<text x="225.9" y="48.6">DDR3_DQS1_P</text>
<text x="225.9" y="51.2">DDR3_DQS1_N</text>
<text x="225.9" y="53.7">DDR3_D13</text>
<text x="104" y="56.3">DDR3_CKE</text>
<text x="225.9" y="58.8">DDR3_DM1</text>
<text x="225.9" y="56.3">DDR3_D15</text>
<text x="104" y="63.9">SPI_CS_1V35</text>
<text x="104" y="61.3">DDR3_RAS</text>
<text x="225.9" y="61.3">DDR3_D8</text>
<text x="225.9" y="63.9">DDR3_D11</text>
<text x="104" y="66.4">DDR3_S0</text>
<text x="104" y="69">DDR3_WE</text>
<text x="104" y="71.5">DDR3_BA2</text>
<text x="225.9" y="71.5">DDR3_D1</text>
<text x="225.9" y="69">DDR3_DM0</text>
<text x="246.8" y="67.7">VTTREF</text>
<text x="225.9" y="76.6">DDR3_D4</text>
<text x="225.9" y="74">DDR3_D5</text>
<text x="104" y="81.7">DDR3_BA0</text>
<text x="225.9" y="79.1">DDR3_DQS0_P</text>
<text x="225.9" y="81.7">DDR3_DQS0_N</text>
<text x="104" y="84.2">DDR3_A10</text>
<text x="104" y="86.7">TEST_2</text>
<text x="225.9" y="89.3">DDR3_D6</text>
<text x="225.9" y="84.2">DDR3_D7</text>
<text x="225.9" y="86.7">DDR3_D2</text>
<text x="104" y="91.8">TEST_1</text>
<text x="225.9" y="91.8">DDR3_D3</text>
<text x="104" y="99.4">DDR3_A2</text>
<text x="104" y="102">DDR3_A1</text>
<text x="225.9" y="96.9">DDR3_D0</text>
<text x="225.9" y="102">DDR3_D22</text>
<text x="225.9" y="107.1">DDR3_D17</text>
<text x="225.9" y="104.5">DDR3_D18</text>
<text x="104" y="109.6">DDR3_BA1</text>
<text x="104" y="112.1">DDR3_A6</text>
<text x="225.9" y="109.6">DDR3_DQS2_P</text>
<text x="225.9" y="112.1">DDR3_DQS2_N</text>
<text x="104" y="114.7">DDR3_A9</text>
<text x="104" y="117.2">LED</text>
<text x="225.9" y="114.7">DDR3_D20</text>
<text x="225.9" y="119.8">DDR3_D19</text>
<text x="225.9" y="117.2">DDR3_D16</text>
<text x="104" y="124.8">DDR3_A7</text>
<text x="225.9" y="124.8">DDR3_D23</text>
<text x="225.9" y="122.3">DDR3_DM2</text>
<text x="104" y="127.4">DDR3_A8</text>
<text x="225.9" y="129.9">DDR3_D24</text>
<text x="225.9" y="127.4">DDR3_D21</text>
<text x="104" y="132.5">DDR3_A12</text>
<text x="104" y="137.5">DDR3_A11</text>
<text x="139.7" y="137.5">GND</text>
<text x="225.9" y="135">DDR3_D28</text>
<text x="225.9" y="137.5">DDR3_DM3</text>
<text x="246.8" y="133.7">VTTREF</text>
<text x="104" y="140.1">DDR3_A4</text>
<text x="104" y="142.6">DDR3_A5</text>
<text x="225.9" y="140.1">DDR3_DQS3_P</text>
<text x="225.9" y="142.6">DDR3_DQS3_N</text>
<text x="104" y="145.2">DDR3_A0</text>
<text x="225.9" y="145.2">DDR3_D31</text>
<text x="225.9" y="147.7">DDR3_D29</text>
<text x="104" y="150.2">DDR3_RESET</text>
<text x="104" y="155.3">DDR3_CLK_P</text>
<text x="104" y="152.8">DDR3_A3</text>
<text x="225.9" y="152.8">DDR3_D30</text>
<text x="225.9" y="150.2">DDR3_D26</text>
<text x="225.9" y="155.3">DDR3_D25</text>
<text x="104" y="157.9">DDR3_CLK_N</text>
<text x="225.9" y="157.9">DDR3_D27</text>
</g>
</g></defs>
<path d="M2.4 8.5h292.1v193h-292.1z" fill-rule="evenodd" fill="#fffcf8"/>
<path d="M2.4 8.5h292.1v193h-292.1z" fill="none" stroke="#000" stroke-width=".21"/>
<path d="M7.5 13.6h281.9v182.9h-281.9z" fill-rule="evenodd" fill="#fffcf8"/>
<g fill="none" stroke="#000" stroke-width=".21">
<path d="M2.4 8.5h5.1M7.5 13.6h281.9v182.9h-281.9zM75.4 8.5v5.1M148.5 8.5v5.1M221.5 8.5v5.1M289.4 8.5h5.1v5.1M2.4 56.8h5.1M289.4 56.8h5.1M2.4 105h5.1M289.4 105h5.1M2.4 153.3h5.1M289.4 153.3h5.1"/>
<path d="M289.4 176.1h-88.9v20.4M75.4 196.5v5M148.5 196.5v5M200.5 183.8h88.9M200.5 191.4h88.9M200.5 193.9h88.9M213.2 183.8v7.6M221.5 196.5v5M251.3 191.4v5.1M264 183.8v7.6M294.5 196.5v5"/>
</g>
<path d="M223.4 66.9h20.3M223.4 133h20.3" fill="none" stroke="#fff0ff" stroke-width="1.3"/>
<path d="M129.4 33.9v2.5" fill="none" stroke="#ff0" stroke-width="1.3"/>
<path d="M53.2 33.9h40.7v129.5h-40.7z" fill-rule="evenodd" fill="#ffffb0"/>
<path d="M53.2 33.9h40.7v129.5h-40.7z" fill="none" stroke="#800000" stroke-width=".21"/>
<path d="M93.9 36.4h7.6" fill="none" stroke="#000" stroke-width=".25"/>
<path d="M93.9 36.4l1.5-.5v1.1z" fill="#f8fcff"/>
<path d="M93.9 36.4l1.5-.5v1.1z" fill="none" stroke="#000" stroke-width=".21"/>
<path d="M95.6 35.9l1.6 .5-1.6 .6z" fill="#f8fcff"/>
<path d="M95.6 35.9l1.6 .5-1.6 .6z" fill="none" stroke="#000" stroke-width=".21"/>
<path d="M93.9 39h7.6" fill="none" stroke="#000" stroke-width=".25"/>
<path d="M93.9 39l1.5-.5v1z" fill="#f8fcff"/>
<path d="M93.9 39l1.5-.5v1z" fill="none" stroke="#000" stroke-width=".21"/>
<path d="M95.6 38.5l1.6 .5-1.6 .5z" fill="#f8fcff"/>
<path d="M95.6 38.5l1.6 .5-1.6 .5z" fill="none" stroke="#000" stroke-width=".21"/>
<path d="M93.9 41.5h7.6" fill="none" stroke="#000" stroke-width=".25"/>
<path d="M93.9 41.5l1.5-.5v1z" fill="#f8fcff"/>
<path d="M93.9 41.5l1.5-.5v1z" fill="none" stroke="#000" stroke-width=".21"/>
<path d="M95.6 41l1.6 .5-1.6 .5z" fill="#f8fcff"/>
<path d="M95.6 41l1.6 .5-1.6 .5z" fill="none" stroke="#000" stroke-width=".21"/>
<path d="M93.9 44.1h7.6" fill="none" stroke="#000" stroke-width=".25"/>
<path d="M93.9 44.1l1.5-.5v1z" fill="#f8fcff"/>
<path d="M93.9 44.1l1.5-.5v1z" fill="none" stroke="#000" stroke-width=".21"/>
<path d="M95.6 43.6l1.6 .5-1.6 .5z" fill="#f8fcff"/>
<path d="M95.6 43.6l1.6 .5-1.6 .5z" fill="none" stroke="#000" stroke-width=".21"/>
<path d="M93.9 46.6h7.6" fill="none" stroke="#000" stroke-width=".25"/>
<path d="M93.9 46.6l1.5-.5v1z" fill="#f8fcff"/>
<path d="M93.9 46.6l1.5-.5v1z" fill="none" stroke="#000" stroke-width=".21"/>
<path d="M95.6 46.1l1.6 .5-1.6 .5z" fill="#f8fcff"/>
<path d="M95.6 46.1l1.6 .5-1.6 .5z" fill="none" stroke="#000" stroke-width=".21"/>
<path d="M93.9 49.1h7.6" fill="none" stroke="#000" stroke-width=".25"/>
<path d="M93.9 49.1l1.5-.5v1.1z" fill="#f8fcff"/>
<path d="M93.9 49.1l1.5-.5v1.1z" fill="none" stroke="#000" stroke-width=".21"/>
<path d="M95.6 48.6l1.6 .5-1.6 .6z" fill="#f8fcff"/>
<path d="M95.6 48.6l1.6 .5-1.6 .6z" fill="none" stroke="#000" stroke-width=".21"/>
<path d="M93.9 51.7h7.6" fill="none" stroke="#000" stroke-width=".25"/>
<path d="M93.9 51.7l1.5-.5v1z" fill="#f8fcff"/>
<path d="M93.9 51.7l1.5-.5v1z" fill="none" stroke="#000" stroke-width=".21"/>
<path d="M95.6 51.2l1.6 .5-1.6 .5z" fill="#f8fcff"/>
<path d="M93.9 51.2l-1.1 .5 1.1 .5M95.6 51.2l1.6 .5-1.6 .5z" fill="none" stroke="#000" stroke-width=".21"/>
<path d="M93.9 54.2h7.6" fill="none" stroke="#000" stroke-width=".25"/>
<path d="M93.9 54.2l1.5-.5v1z" fill="#f8fcff"/>
<path d="M93.9 54.2l1.5-.5v1z" fill="none" stroke="#000" stroke-width=".21"/>
<path d="M95.6 53.7l1.6 .5-1.6 .5z" fill="#f8fcff"/>
<path d="M95.6 53.7l1.6 .5-1.6 .5z" fill="none" stroke="#000" stroke-width=".21"/>
<path d="M93.9 56.8h7.6" fill="none" stroke="#000" stroke-width=".25"/>
<path d="M93.9 56.8l1.5-.5v1z" fill="#f8fcff"/>
<path d="M93.9 56.8l1.5-.5v1z" fill="none" stroke="#000" stroke-width=".21"/>
<path d="M95.6 56.3l1.6 .5-1.6 .5z" fill="#f8fcff"/>
<path d="M95.6 56.3l1.6 .5-1.6 .5z" fill="none" stroke="#000" stroke-width=".21"/>
<path d="M93.9 59.3h7.6" fill="none" stroke="#000" stroke-width=".25"/>
<path d="M93.9 59.3l1.5-.5v1z" fill="#f8fcff"/>
<path d="M93.9 59.3l1.5-.5v1z" fill="none" stroke="#000" stroke-width=".21"/>
<path d="M95.6 58.8l1.6 .5-1.6 .5z" fill="#f8fcff"/>
<path d="M95.6 58.8l1.6 .5-1.6 .5z" fill="none" stroke="#000" stroke-width=".21"/>
<path d="M93.9 61.8h7.6" fill="none" stroke="#000" stroke-width=".25"/>
<path d="M93.9 61.8l1.5-.5v1.1z" fill="#f8fcff"/>
<path d="M93.9 61.8l1.5-.5v1.1z" fill="none" stroke="#000" stroke-width=".21"/>
<path d="M95.6 61.3l1.6 .5-1.6 .6z" fill="#f8fcff"/>
<path d="M95.6 61.3l1.6 .5-1.6 .6z" fill="none" stroke="#000" stroke-width=".21"/>
<path d="M93.9 64.4h7.6" fill="none" stroke="#000" stroke-width=".25"/>
<path d="M93.9 64.4l1.5-.5v1z" fill="#f8fcff"/>
<path d="M93.9 64.4l1.5-.5v1z" fill="none" stroke="#000" stroke-width=".21"/>
<path d="M95.6 63.9l1.6 .5-1.6 .5z" fill="#f8fcff"/>
<path d="M95.6 63.9l1.6 .5-1.6 .5z" fill="none" stroke="#000" stroke-width=".21"/>
<path d="M93.9 66.9h7.6" fill="none" stroke="#000" stroke-width=".25"/>
<path d="M93.9 66.9l1.5-.5v1z" fill="#f8fcff"/>
<path d="M93.9 66.9l1.5-.5v1z" fill="none" stroke="#000" stroke-width=".21"/>
<path d="M95.6 66.4l1.6 .5-1.6 .5z" fill="#f8fcff"/>
<path d="M95.6 66.4l1.6 .5-1.6 .5z" fill="none" stroke="#000" stroke-width=".21"/>
<path d="M93.9 69.5h7.6" fill="none" stroke="#000" stroke-width=".25"/>
<path d="M93.9 69.5l1.5-.5v1z" fill="#f8fcff"/>
<path d="M93.9 69.5l1.5-.5v1z" fill="none" stroke="#000" stroke-width=".21"/>
<path d="M95.6 69l1.6 .5-1.6 .5z" fill="#f8fcff"/>
<path d="M95.6 69l1.6 .5-1.6 .5z" fill="none" stroke="#000" stroke-width=".21"/>
<path d="M93.9 72h7.6" fill="none" stroke="#000" stroke-width=".25"/>
<path d="M93.9 72l1.5-.5v1z" fill="#f8fcff"/>
<path d="M93.9 72l1.5-.5v1z" fill="none" stroke="#000" stroke-width=".21"/>
<path d="M95.6 71.5l1.6 .5-1.6 .5z" fill="#f8fcff"/>
<path d="M95.6 71.5l1.6 .5-1.6 .5z" fill="none" stroke="#000" stroke-width=".21"/>
<path d="M93.9 74.5h7.6" fill="none" stroke="#000" stroke-width=".25"/>
<path d="M93.9 74.5l1.5-.5v1.1z" fill="#f8fcff"/>
<path d="M93.9 74.5l1.5-.5v1.1z" fill="none" stroke="#000" stroke-width=".21"/>
<path d="M95.6 74l1.6 .5-1.6 .6z" fill="#f8fcff"/>
<path d="M95.6 74l1.6 .5-1.6 .6z" fill="none" stroke="#000" stroke-width=".21"/>
<path d="M93.9 77.1h7.6" fill="none" stroke="#000" stroke-width=".25"/>
<path d="M93.9 77.1l1.5-.5v1z" fill="#f8fcff"/>
<path d="M93.9 77.1l1.5-.5v1z" fill="none" stroke="#000" stroke-width=".21"/>
<path d="M95.6 76.6l1.6 .5-1.6 .5z" fill="#f8fcff"/>
<path d="M95.6 76.6l1.6 .5-1.6 .5z" fill="none" stroke="#000" stroke-width=".21"/>
<path d="M93.9 79.6h7.6" fill="none" stroke="#000" stroke-width=".25"/>
<path d="M93.9 79.6l1.5-.5v1z" fill="#f8fcff"/>
<path d="M93.9 79.6l1.5-.5v1z" fill="none" stroke="#000" stroke-width=".21"/>
<path d="M95.6 79.1l1.6 .5-1.6 .5z" fill="#f8fcff"/>
<path d="M95.6 79.1l1.6 .5-1.6 .5z" fill="none" stroke="#000" stroke-width=".21"/>
<path d="M93.9 82.2h7.6" fill="none" stroke="#000" stroke-width=".25"/>
<path d="M93.9 82.2l1.5-.5v1z" fill="#f8fcff"/>
<path d="M93.9 82.2l1.5-.5v1z" fill="none" stroke="#000" stroke-width=".21"/>
<path d="M95.6 81.7l1.6 .5-1.6 .5z" fill="#f8fcff"/>
<path d="M95.6 81.7l1.6 .5-1.6 .5z" fill="none" stroke="#000" stroke-width=".21"/>
<path d="M93.9 84.7h7.6" fill="none" stroke="#000" stroke-width=".25"/>
<path d="M93.9 84.7l1.5-.5v1z" fill="#f8fcff"/>
<path d="M93.9 84.7l1.5-.5v1z" fill="none" stroke="#000" stroke-width=".21"/>
<path d="M95.6 84.2l1.6 .5-1.6 .5z" fill="#f8fcff"/>
<path d="M95.6 84.2l1.6 .5-1.6 .5z" fill="none" stroke="#000" stroke-width=".21"/>
<path d="M93.9 87.2h7.6" fill="none" stroke="#000" stroke-width=".25"/>
<path d="M93.9 87.2l1.5-.5v1.1z" fill="#f8fcff"/>
<path d="M93.9 87.2l1.5-.5v1.1z" fill="none" stroke="#000" stroke-width=".21"/>
<path d="M95.6 86.7l1.6 .5-1.6 .6z" fill="#f8fcff"/>
<path d="M95.6 86.7l1.6 .5-1.6 .6z" fill="none" stroke="#000" stroke-width=".21"/>
<path d="M93.9 89.8h7.6" fill="none" stroke="#000" stroke-width=".25"/>
<path d="M93.9 89.8l1.5-.5v1z" fill="#f8fcff"/>
<path d="M93.9 89.8l1.5-.5v1z" fill="none" stroke="#000" stroke-width=".21"/>
<path d="M95.6 89.3l1.6 .5-1.6 .5z" fill="#f8fcff"/>
<path d="M93.9 89.3l-1.1 .5 1.1 .5M95.6 89.3l1.6 .5-1.6 .5z" fill="none" stroke="#000" stroke-width=".21"/>
<path d="M93.9 92.3h7.6" fill="none" stroke="#000" stroke-width=".25"/>
<path d="M93.9 92.3l1.5-.5v1z" fill="#f8fcff"/>
<path d="M93.9 92.3l1.5-.5v1z" fill="none" stroke="#000" stroke-width=".21"/>
<path d="M95.6 91.8l1.6 .5-1.6 .5z" fill="#f8fcff"/>
<path d="M93.9 91.8l-1.1 .5 1.1 .5M95.6 91.8l1.6 .5-1.6 .5z" fill="none" stroke="#000" stroke-width=".21"/>
<path d="M93.9 94.9h7.6" fill="none" stroke="#000" stroke-width=".25"/>
<path d="M93.9 94.9l1.5-.5v1z" fill="#f8fcff"/>
<path d="M93.9 94.9l1.5-.5v1z" fill="none" stroke="#000" stroke-width=".21"/>
<path d="M95.6 94.4l1.6 .5-1.6 .5z" fill="#f8fcff"/>
<path d="M93.9 94.4l-1.1 .5 1.1 .5M95.6 94.4l1.6 .5-1.6 .5z" fill="none" stroke="#000" stroke-width=".21"/>
<path d="M93.9 97.4h7.6" fill="none" stroke="#000" stroke-width=".25"/>
<path d="M93.9 97.4l1.5-.5v1z" fill="#f8fcff"/>
<path d="M93.9 97.4l1.5-.5v1z" fill="none" stroke="#000" stroke-width=".21"/>
<path d="M95.6 96.9l1.6 .5-1.6 .5z" fill="#f8fcff"/>
<path d="M93.9 96.9l-1.1 .5 1.1 .5M95.6 96.9l1.6 .5-1.6 .5z" fill="none" stroke="#000" stroke-width=".21"/>
<path d="M93.9 99.9h7.6" fill="none" stroke="#000" stroke-width=".25"/>
<path d="M93.9 99.9l1.5-.5v1.1z" fill="#f8fcff"/>
<path d="M93.9 99.9l1.5-.5v1.1z" fill="none" stroke="#000" stroke-width=".21"/>
<path d="M95.6 99.4l1.6 .5-1.6 .6z" fill="#f8fcff"/>
<path d="M93.9 99.4l-1.1 .5 1.1 .6M95.6 99.4l1.6 .5-1.6 .6z" fill="none" stroke="#000" stroke-width=".21"/>
<path d="M93.9 102.5h7.6" fill="none" stroke="#000" stroke-width=".25"/>
<path d="M93.9 102.5l1.5-.5v1z" fill="#f8fcff"/>
<path d="M93.9 102.5l1.5-.5v1z" fill="none" stroke="#000" stroke-width=".21"/>
<path d="M95.6 102l1.6 .5-1.6 .5z" fill="#f8fcff"/>
<path d="M93.9 102l-1.1 .5 1.1 .5M95.6 102l1.6 .5-1.6 .5z" fill="none" stroke="#000" stroke-width=".21"/>
<path d="M93.9 105h7.6" fill="none" stroke="#000" stroke-width=".25"/>
<path d="M93.9 105l1.5-.5v1z" fill="#f8fcff"/>
<path d="M93.9 105l1.5-.5v1z" fill="none" stroke="#000" stroke-width=".21"/>
<path d="M95.6 104.5l1.6 .5-1.6 .5z" fill="#f8fcff"/>
<path d="M93.9 104.5l-1.1 .5 1.1 .5M95.6 104.5l1.6 .5-1.6 .5z" fill="none" stroke="#000" stroke-width=".21"/>
<path d="M93.9 107.6h7.6" fill="none" stroke="#000" stroke-width=".25"/>
<path d="M93.9 107.6l1.5-.5v1z" fill="#f8fcff"/>
<path d="M93.9 107.6l1.5-.5v1z" fill="none" stroke="#000" stroke-width=".21"/>
<path d="M95.6 107.1l1.6 .5-1.6 .5z" fill="#f8fcff"/>
<path d="M93.9 107.1l-1.1 .5 1.1 .5M95.6 107.1l1.6 .5-1.6 .5z" fill="none" stroke="#000" stroke-width=".21"/>
<path d="M93.9 110.1h7.6" fill="none" stroke="#000" stroke-width=".25"/>
<path d="M93.9 110.1l1.5-.5v1z" fill="#f8fcff"/>
<path d="M93.9 110.1l1.5-.5v1z" fill="none" stroke="#000" stroke-width=".21"/>
<path d="M95.6 109.6l1.6 .5-1.6 .5z" fill="#f8fcff"/>
<path d="M95.6 109.6l1.6 .5-1.6 .5z" fill="none" stroke="#000" stroke-width=".21"/>
<path d="M93.9 112.6h7.6" fill="none" stroke="#000" stroke-width=".25"/>
<path d="M93.9 112.6l1.5-.5v1.1z" fill="#f8fcff"/>
<path d="M93.9 112.6l1.5-.5v1.1z" fill="none" stroke="#000" stroke-width=".21"/>
<path d="M95.6 112.1l1.6 .5-1.6 .6z" fill="#f8fcff"/>
<path d="M95.6 112.1l1.6 .5-1.6 .6z" fill="none" stroke="#000" stroke-width=".21"/>
<path d="M93.9 115.2h7.6" fill="none" stroke="#000" stroke-width=".25"/>
<path d="M93.9 115.2l1.5-.5v1z" fill="#f8fcff"/>
<path d="M93.9 115.2l1.5-.5v1z" fill="none" stroke="#000" stroke-width=".21"/>
<path d="M95.6 114.7l1.6 .5-1.6 .5z" fill="#f8fcff"/>
<path d="M95.6 114.7l1.6 .5-1.6 .5z" fill="none" stroke="#000" stroke-width=".21"/>
<path d="M93.9 117.7h7.6" fill="none" stroke="#000" stroke-width=".25"/>
<path d="M93.9 117.7l1.5-.5v1z" fill="#f8fcff"/>
<path d="M93.9 117.7l1.5-.5v1z" fill="none" stroke="#000" stroke-width=".21"/>
<path d="M95.6 117.2l1.6 .5-1.6 .5z" fill="#f8fcff"/>
<path d="M95.6 117.2l1.6 .5-1.6 .5z" fill="none" stroke="#000" stroke-width=".21"/>
<path d="M93.9 120.3h7.6" fill="none" stroke="#000" stroke-width=".25"/>
<path d="M93.9 120.3l1.5-.5v1z" fill="#f8fcff"/>
<path d="M93.9 120.3l1.5-.5v1z" fill="none" stroke="#000" stroke-width=".21"/>
<path d="M95.6 119.8l1.6 .5-1.6 .5z" fill="#f8fcff"/>
<path d="M95.6 119.8l1.6 .5-1.6 .5z" fill="none" stroke="#000" stroke-width=".21"/>
<path d="M93.9 122.8h7.6" fill="none" stroke="#000" stroke-width=".25"/>
<path d="M93.9 122.8l1.5-.5v1z" fill="#f8fcff"/>
<path d="M93.9 122.8l1.5-.5v1z" fill="none" stroke="#000" stroke-width=".21"/>
<path d="M95.6 122.3l1.6 .5-1.6 .5z" fill="#f8fcff"/>
<path d="M95.6 122.3l1.6 .5-1.6 .5z" fill="none" stroke="#000" stroke-width=".21"/>
<path d="M93.9 125.3h7.6" fill="none" stroke="#000" stroke-width=".25"/>
<path d="M93.9 125.3l1.5-.5v1.1z" fill="#f8fcff"/>
<path d="M93.9 125.3l1.5-.5v1.1z" fill="none" stroke="#000" stroke-width=".21"/>
<path d="M95.6 124.8l1.6 .5-1.6 .6z" fill="#f8fcff"/>
<path d="M95.6 124.8l1.6 .5-1.6 .6z" fill="none" stroke="#000" stroke-width=".21"/>
<path d="M93.9 127.9h7.6" fill="none" stroke="#000" stroke-width=".25"/>
<path d="M93.9 127.9l1.5-.5v1z" fill="#f8fcff"/>
<path d="M93.9 127.9l1.5-.5v1z" fill="none" stroke="#000" stroke-width=".21"/>
<path d="M95.6 127.4l1.6 .5-1.6 .5z" fill="#f8fcff"/>
<path d="M95.6 127.4l1.6 .5-1.6 .5z" fill="none" stroke="#000" stroke-width=".21"/>
<path d="M93.9 130.4h7.6" fill="none" stroke="#000" stroke-width=".25"/>
<path d="M93.9 130.4l1.5-.5v1z" fill="#f8fcff"/>
<path d="M93.9 130.4l1.5-.5v1z" fill="none" stroke="#000" stroke-width=".21"/>
<path d="M95.6 129.9l1.6 .5-1.6 .5z" fill="#f8fcff"/>
<path d="M95.6 129.9l1.6 .5-1.6 .5z" fill="none" stroke="#000" stroke-width=".21"/>
<path d="M93.9 133h7.6" fill="none" stroke="#000" stroke-width=".25"/>
<path d="M93.9 133l1.5-.5v1z" fill="#f8fcff"/>
<path d="M93.9 133l1.5-.5v1z" fill="none" stroke="#000" stroke-width=".21"/>
<path d="M95.6 132.5l1.6 .5-1.6 .5z" fill="#f8fcff"/>
<path d="M95.6 132.5l1.6 .5-1.6 .5z" fill="none" stroke="#000" stroke-width=".21"/>
<path d="M93.9 135.5h7.6" fill="none" stroke="#000" stroke-width=".25"/>
<path d="M93.9 135.5l1.5-.5v1z" fill="#f8fcff"/>
<path d="M93.9 135.5l1.5-.5v1z" fill="none" stroke="#000" stroke-width=".21"/>
<path d="M95.6 135l1.6 .5-1.6 .5z" fill="#f8fcff"/>
<path d="M95.6 135l1.6 .5-1.6 .5z" fill="none" stroke="#000" stroke-width=".21"/>
<path d="M93.9 138h7.6" fill="none" stroke="#000" stroke-width=".25"/>
<path d="M93.9 138l1.5-.5v1.1z" fill="#f8fcff"/>
<path d="M93.9 138l1.5-.5v1.1z" fill="none" stroke="#000" stroke-width=".21"/>
<path d="M95.6 137.5l1.6 .5-1.6 .6z" fill="#f8fcff"/>
<path d="M95.6 137.5l1.6 .5-1.6 .6z" fill="none" stroke="#000" stroke-width=".21"/>
<path d="M93.9 140.6h7.6" fill="none" stroke="#000" stroke-width=".25"/>
<path d="M93.9 140.6l1.5-.5v1z" fill="#f8fcff"/>
<path d="M93.9 140.6l1.5-.5v1z" fill="none" stroke="#000" stroke-width=".21"/>
<path d="M95.6 140.1l1.6 .5-1.6 .5z" fill="#f8fcff"/>
<path d="M95.6 140.1l1.6 .5-1.6 .5z" fill="none" stroke="#000" stroke-width=".21"/>
<path d="M93.9 143.1h7.6" fill="none" stroke="#000" stroke-width=".25"/>
<path d="M93.9 143.1l1.5-.5v1z" fill="#f8fcff"/>
<path d="M93.9 143.1l1.5-.5v1z" fill="none" stroke="#000" stroke-width=".21"/>
<path d="M95.6 142.6l1.6 .5-1.6 .5z" fill="#f8fcff"/>
<path d="M95.6 142.6l1.6 .5-1.6 .5z" fill="none" stroke="#000" stroke-width=".21"/>
<path d="M93.9 145.7h7.6" fill="none" stroke="#000" stroke-width=".25"/>
<path d="M93.9 145.7l1.5-.5v1z" fill="#f8fcff"/>
<path d="M93.9 145.7l1.5-.5v1z" fill="none" stroke="#000" stroke-width=".21"/>
<path d="M95.6 145.2l1.6 .5-1.6 .5z" fill="#f8fcff"/>
<path d="M95.6 145.2l1.6 .5-1.6 .5z" fill="none" stroke="#000" stroke-width=".21"/>
<path d="M93.9 148.2h7.6" fill="none" stroke="#000" stroke-width=".25"/>
<path d="M93.9 148.2l1.5-.5v1z" fill="#f8fcff"/>
<path d="M93.9 148.2l1.5-.5v1z" fill="none" stroke="#000" stroke-width=".21"/>
<path d="M95.6 147.7l1.6 .5-1.6 .5z" fill="#f8fcff"/>
<path d="M95.6 147.7l1.6 .5-1.6 .5z" fill="none" stroke="#000" stroke-width=".21"/>
<path d="M93.9 150.7h7.6" fill="none" stroke="#000" stroke-width=".25"/>
<path d="M93.9 150.7l1.5-.5v1.1z" fill="#f8fcff"/>
<path d="M93.9 150.7l1.5-.5v1.1z" fill="none" stroke="#000" stroke-width=".21"/>
<path d="M95.6 150.2l1.6 .5-1.6 .6z" fill="#f8fcff"/>
<path d="M95.6 150.2l1.6 .5-1.6 .6z" fill="none" stroke="#000" stroke-width=".21"/>
<path d="M93.9 153.3h7.6" fill="none" stroke="#000" stroke-width=".25"/>
<path d="M93.9 153.3l1.5-.5v1z" fill="#f8fcff"/>
<path d="M93.9 153.3l1.5-.5v1z" fill="none" stroke="#000" stroke-width=".21"/>
<path d="M95.6 152.8l1.6 .5-1.6 .5z" fill="#f8fcff"/>
<path d="M95.6 152.8l1.6 .5-1.6 .5z" fill="none" stroke="#000" stroke-width=".21"/>
<path d="M93.9 155.8h7.6" fill="none" stroke="#000" stroke-width=".25"/>
<path d="M93.9 155.8l1.5-.5v1z" fill="#f8fcff"/>
<path d="M93.9 155.8l1.5-.5v1z" fill="none" stroke="#000" stroke-width=".21"/>
<path d="M95.6 155.3l1.6 .5-1.6 .5z" fill="#f8fcff"/>
<path d="M95.6 155.3l1.6 .5-1.6 .5z" fill="none" stroke="#000" stroke-width=".21"/>
<path d="M93.9 158.4h7.6" fill="none" stroke="#000" stroke-width=".25"/>
<path d="M93.9 158.4l1.5-.5v1z" fill="#f8fcff"/>
<path d="M93.9 158.4l1.5-.5v1z" fill="none" stroke="#000" stroke-width=".21"/>
<path d="M95.6 157.9l1.6 .5-1.6 .5z" fill="#f8fcff"/>
<path d="M95.6 157.9l1.6 .5-1.6 .5z" fill="none" stroke="#000" stroke-width=".21"/>
<path d="M93.9 160.9h7.6" fill="none" stroke="#000" stroke-width=".25"/>
<path d="M93.9 160.9l1.5-.5v1z" fill="#f8fcff"/>
<path d="M93.9 160.9l1.5-.5v1z" fill="none" stroke="#000" stroke-width=".21"/>
<path d="M95.6 160.4l1.6 .5-1.6 .5z" fill="#f8fcff"/>
<path d="M95.6 160.4l1.6 .5-1.6 .5z" fill="none" stroke="#000" stroke-width=".21"/>
<path d="M180.2 33.9h35.6v129.5h-35.6z" fill-rule="evenodd" fill="#ffffb0"/>
<path d="M180.2 33.9h35.6v129.5h-35.6z" fill="none" stroke="#800000" stroke-width=".21"/>
<path d="M215.8 36.4h7.6" fill="none" stroke="#000" stroke-width=".25"/>
<path d="M215.8 36.4l1.5-.5v1.1z" fill="#f8fcff"/>
<path d="M215.8 36.4l1.5-.5v1.1z" fill="none" stroke="#000" stroke-width=".21"/>
<path d="M217.6 35.9l1.5 .5-1.5 .6z" fill="#f8fcff"/>
<path d="M217.6 35.9l1.5 .5-1.5 .6z" fill="none" stroke="#000" stroke-width=".21"/>
<path d="M215.8 39h7.6" fill="none" stroke="#000" stroke-width=".25"/>
<path d="M215.8 39l1.5-.5v1z" fill="#f8fcff"/>
<path d="M215.8 39l1.5-.5v1z" fill="none" stroke="#000" stroke-width=".21"/>
<path d="M217.6 38.5l1.5 .5-1.5 .5z" fill="#f8fcff"/>
<path d="M217.6 38.5l1.5 .5-1.5 .5z" fill="none" stroke="#000" stroke-width=".21"/>
<path d="M215.8 41.5h7.6" fill="none" stroke="#000" stroke-width=".25"/>
<path d="M215.8 41.5l1.5-.5v1z" fill="#f8fcff"/>
<path d="M215.8 41.5l1.5-.5v1z" fill="none" stroke="#000" stroke-width=".21"/>
<path d="M217.6 41l1.5 .5-1.5 .5z" fill="#f8fcff"/>
<path d="M217.6 41l1.5 .5-1.5 .5z" fill="none" stroke="#000" stroke-width=".21"/>
<path d="M215.8 44.1h7.6" fill="none" stroke="#000" stroke-width=".25"/>
<path d="M215.8 44.1l1.5-.5v1z" fill="#f8fcff"/>
<path d="M215.8 44.1l1.5-.5v1z" fill="none" stroke="#000" stroke-width=".21"/>
<path d="M217.6 43.6l1.5 .5-1.5 .5z" fill="#f8fcff"/>
<path d="M217.6 43.6l1.5 .5-1.5 .5z" fill="none" stroke="#000" stroke-width=".21"/>
<path d="M215.8 46.6h7.6" fill="none" stroke="#000" stroke-width=".25"/>
<path d="M215.8 46.6l1.5-.5v1z" fill="#f8fcff"/>
<path d="M215.8 46.6l1.5-.5v1z" fill="none" stroke="#000" stroke-width=".21"/>
<path d="M217.6 46.1l1.5 .5-1.5 .5z" fill="#f8fcff"/>
<path d="M217.6 46.1l1.5 .5-1.5 .5z" fill="none" stroke="#000" stroke-width=".21"/>
<path d="M215.8 49.1h7.6" fill="none" stroke="#000" stroke-width=".25"/>
<path d="M215.8 49.1l1.5-.5v1.1z" fill="#f8fcff"/>
<path d="M215.8 49.1l1.5-.5v1.1z" fill="none" stroke="#000" stroke-width=".21"/>
<path d="M217.6 48.6l1.5 .5-1.5 .6z" fill="#f8fcff"/>
<path d="M217.6 48.6l1.5 .5-1.5 .6z" fill="none" stroke="#000" stroke-width=".21"/>
<path d="M215.8 51.7h7.6" fill="none" stroke="#000" stroke-width=".25"/>
<path d="M215.8 51.7l1.5-.5v1z" fill="#f8fcff"/>
<path d="M215.8 51.7l1.5-.5v1z" fill="none" stroke="#000" stroke-width=".21"/>
<path d="M217.6 51.2l1.5 .5-1.5 .5z" fill="#f8fcff"/>
<path d="M217.6 51.2l1.5 .5-1.5 .5z" fill="none" stroke="#000" stroke-width=".21"/>
<path d="M215.8 54.2h7.6" fill="none" stroke="#000" stroke-width=".25"/>
<path d="M215.8 54.2l1.5-.5v1z" fill="#f8fcff"/>
<path d="M215.8 54.2l1.5-.5v1z" fill="none" stroke="#000" stroke-width=".21"/>
<path d="M217.6 53.7l1.5 .5-1.5 .5z" fill="#f8fcff"/>
<path d="M217.6 53.7l1.5 .5-1.5 .5z" fill="none" stroke="#000" stroke-width=".21"/>
<path d="M215.8 56.8h7.6" fill="none" stroke="#000" stroke-width=".25"/>
<path d="M215.8 56.8l1.5-.5v1z" fill="#f8fcff"/>
<path d="M215.8 56.8l1.5-.5v1z" fill="none" stroke="#000" stroke-width=".21"/>
<path d="M217.6 56.3l1.5 .5-1.5 .5z" fill="#f8fcff"/>
<path d="M217.6 56.3l1.5 .5-1.5 .5z" fill="none" stroke="#000" stroke-width=".21"/>
<path d="M215.8 59.3h7.6" fill="none" stroke="#000" stroke-width=".25"/>
<path d="M215.8 59.3l1.5-.5v1z" fill="#f8fcff"/>
<path d="M215.8 59.3l1.5-.5v1z" fill="none" stroke="#000" stroke-width=".21"/>
<path d="M217.6 58.8l1.5 .5-1.5 .5z" fill="#f8fcff"/>
<path d="M217.6 58.8l1.5 .5-1.5 .5z" fill="none" stroke="#000" stroke-width=".21"/>
<path d="M215.8 61.8h7.6" fill="none" stroke="#000" stroke-width=".25"/>
<path d="M215.8 61.8l1.5-.5v1.1z" fill="#f8fcff"/>
<path d="M215.8 61.8l1.5-.5v1.1z" fill="none" stroke="#000" stroke-width=".21"/>
<path d="M217.6 61.3l1.5 .5-1.5 .6z" fill="#f8fcff"/>
<path d="M217.6 61.3l1.5 .5-1.5 .6z" fill="none" stroke="#000" stroke-width=".21"/>
<path d="M215.8 64.4h7.6" fill="none" stroke="#000" stroke-width=".25"/>
<path d="M215.8 64.4l1.5-.5v1z" fill="#f8fcff"/>
<path d="M215.8 64.4l1.5-.5v1z" fill="none" stroke="#000" stroke-width=".21"/>
<path d="M217.6 63.9l1.5 .5-1.5 .5z" fill="#f8fcff"/>
<path d="M217.6 63.9l1.5 .5-1.5 .5z" fill="none" stroke="#000" stroke-width=".21"/>
<path d="M215.8 66.9h7.6" fill="none" stroke="#000" stroke-width=".25"/>
<path d="M215.8 66.9l1.5-.5v1z" fill="#f8fcff"/>
<path d="M215.8 66.9l1.5-.5v1z" fill="none" stroke="#000" stroke-width=".21"/>
<path d="M217.6 66.4l1.5 .5-1.5 .5z" fill="#f8fcff"/>
<path d="M217.6 66.4l1.5 .5-1.5 .5z" fill="none" stroke="#000" stroke-width=".21"/>
<path d="M215.8 69.5h7.6" fill="none" stroke="#000" stroke-width=".25"/>
<path d="M215.8 69.5l1.5-.5v1z" fill="#f8fcff"/>
<path d="M215.8 69.5l1.5-.5v1z" fill="none" stroke="#000" stroke-width=".21"/>
<path d="M217.6 69l1.5 .5-1.5 .5z" fill="#f8fcff"/>
<path d="M217.6 69l1.5 .5-1.5 .5z" fill="none" stroke="#000" stroke-width=".21"/>
<path d="M215.8 72h7.6" fill="none" stroke="#000" stroke-width=".25"/>
<path d="M215.8 72l1.5-.5v1z" fill="#f8fcff"/>
<path d="M215.8 72l1.5-.5v1z" fill="none" stroke="#000" stroke-width=".21"/>
<path d="M217.6 71.5l1.5 .5-1.5 .5z" fill="#f8fcff"/>
<path d="M217.6 71.5l1.5 .5-1.5 .5z" fill="none" stroke="#000" stroke-width=".21"/>
<path d="M215.8 74.5h7.6" fill="none" stroke="#000" stroke-width=".25"/>
<path d="M215.8 74.5l1.5-.5v1.1z" fill="#f8fcff"/>
<path d="M215.8 74.5l1.5-.5v1.1z" fill="none" stroke="#000" stroke-width=".21"/>
<path d="M217.6 74l1.5 .5-1.5 .6z" fill="#f8fcff"/>
<path d="M217.6 74l1.5 .5-1.5 .6z" fill="none" stroke="#000" stroke-width=".21"/>
<path d="M215.8 77.1h7.6" fill="none" stroke="#000" stroke-width=".25"/>
<path d="M215.8 77.1l1.5-.5v1z" fill="#f8fcff"/>
<path d="M215.8 77.1l1.5-.5v1z" fill="none" stroke="#000" stroke-width=".21"/>
<path d="M217.6 76.6l1.5 .5-1.5 .5z" fill="#f8fcff"/>
<path d="M217.6 76.6l1.5 .5-1.5 .5z" fill="none" stroke="#000" stroke-width=".21"/>
<path d="M215.8 79.6h7.6" fill="none" stroke="#000" stroke-width=".25"/>
<path d="M215.8 79.6l1.5-.5v1z" fill="#f8fcff"/>
<path d="M215.8 79.6l1.5-.5v1z" fill="none" stroke="#000" stroke-width=".21"/>
<path d="M217.6 79.1l1.5 .5-1.5 .5z" fill="#f8fcff"/>
<path d="M217.6 79.1l1.5 .5-1.5 .5z" fill="none" stroke="#000" stroke-width=".21"/>
<path d="M215.8 82.2h7.6" fill="none" stroke="#000" stroke-width=".25"/>
<path d="M215.8 82.2l1.5-.5v1z" fill="#f8fcff"/>
<path d="M215.8 82.2l1.5-.5v1z" fill="none" stroke="#000" stroke-width=".21"/>
<path d="M217.6 81.7l1.5 .5-1.5 .5z" fill="#f8fcff"/>
<path d="M217.6 81.7l1.5 .5-1.5 .5z" fill="none" stroke="#000" stroke-width=".21"/>
<path d="M215.8 84.7h7.6" fill="none" stroke="#000" stroke-width=".25"/>
<path d="M215.8 84.7l1.5-.5v1z" fill="#f8fcff"/>
<path d="M215.8 84.7l1.5-.5v1z" fill="none" stroke="#000" stroke-width=".21"/>
<path d="M217.6 84.2l1.5 .5-1.5 .5z" fill="#f8fcff"/>
<path d="M217.6 84.2l1.5 .5-1.5 .5z" fill="none" stroke="#000" stroke-width=".21"/>
<path d="M215.8 87.2h7.6" fill="none" stroke="#000" stroke-width=".25"/>
<path d="M215.8 87.2l1.5-.5v1.1z" fill="#f8fcff"/>
<path d="M215.8 87.2l1.5-.5v1.1z" fill="none" stroke="#000" stroke-width=".21"/>
<path d="M217.6 86.7l1.5 .5-1.5 .6z" fill="#f8fcff"/>
<path d="M217.6 86.7l1.5 .5-1.5 .6z" fill="none" stroke="#000" stroke-width=".21"/>
<path d="M215.8 89.8h7.6" fill="none" stroke="#000" stroke-width=".25"/>
<path d="M215.8 89.8l1.5-.5v1z" fill="#f8fcff"/>
<path d="M215.8 89.8l1.5-.5v1z" fill="none" stroke="#000" stroke-width=".21"/>
<path d="M217.6 89.3l1.5 .5-1.5 .5z" fill="#f8fcff"/>
<path d="M215.8 89.3l-1 .5 1 .5M217.6 89.3l1.5 .5-1.5 .5z" fill="none" stroke="#000" stroke-width=".21"/>
<path d="M215.8 92.3h7.6" fill="none" stroke="#000" stroke-width=".25"/>
<path d="M215.8 92.3l1.5-.5v1z" fill="#f8fcff"/>
<path d="M215.8 92.3l1.5-.5v1z" fill="none" stroke="#000" stroke-width=".21"/>
<path d="M217.6 91.8l1.5 .5-1.5 .5z" fill="#f8fcff"/>
<path d="M215.8 91.8l-1 .5 1 .5M217.6 91.8l1.5 .5-1.5 .5z" fill="none" stroke="#000" stroke-width=".21"/>
<path d="M215.8 94.9h7.6" fill="none" stroke="#000" stroke-width=".25"/>
<path d="M215.8 94.9l1.5-.5v1z" fill="#f8fcff"/>
<path d="M215.8 94.9l1.5-.5v1z" fill="none" stroke="#000" stroke-width=".21"/>
<path d="M217.6 94.4l1.5 .5-1.5 .5z" fill="#f8fcff"/>
<path d="M215.8 94.4l-1 .5 1 .5M217.6 94.4l1.5 .5-1.5 .5z" fill="none" stroke="#000" stroke-width=".21"/>
<path d="M215.8 97.4h7.6" fill="none" stroke="#000" stroke-width=".25"/>
<path d="M215.8 97.4l1.5-.5v1z" fill="#f8fcff"/>
<path d="M215.8 97.4l1.5-.5v1z" fill="none" stroke="#000" stroke-width=".21"/>
<path d="M217.6 96.9l1.5 .5-1.5 .5z" fill="#f8fcff"/>
<path d="M215.8 96.9l-1 .5 1 .5M217.6 96.9l1.5 .5-1.5 .5z" fill="none" stroke="#000" stroke-width=".21"/>
<path d="M215.8 99.9h7.6" fill="none" stroke="#000" stroke-width=".25"/>
<path d="M215.8 99.9l1.5-.5v1.1z" fill="#f8fcff"/>
<path d="M215.8 99.9l1.5-.5v1.1z" fill="none" stroke="#000" stroke-width=".21"/>
<path d="M217.6 99.4l1.5 .5-1.5 .6z" fill="#f8fcff"/>
<path d="M215.8 99.4l-1 .5 1 .6M217.6 99.4l1.5 .5-1.5 .6z" fill="none" stroke="#000" stroke-width=".21"/>
<path d="M215.8 102.5h7.6" fill="none" stroke="#000" stroke-width=".25"/>
<path d="M215.8 102.5l1.5-.5v1z" fill="#f8fcff"/>
<path d="M215.8 102.5l1.5-.5v1z" fill="none" stroke="#000" stroke-width=".21"/>
<path d="M217.6 102l1.5 .5-1.5 .5z" fill="#f8fcff"/>
<path d="M215.8 102l-1 .5 1 .5M217.6 102l1.5 .5-1.5 .5z" fill="none" stroke="#000" stroke-width=".21"/>
<path d="M215.8 105h7.6" fill="none" stroke="#000" stroke-width=".25"/>
<path d="M215.8 105l1.5-.5v1z" fill="#f8fcff"/>
<path d="M215.8 105l1.5-.5v1z" fill="none" stroke="#000" stroke-width=".21"/>
<path d="M217.6 104.5l1.5 .5-1.5 .5z" fill="#f8fcff"/>
<path d="M215.8 104.5l-1 .5 1 .5M217.6 104.5l1.5 .5-1.5 .5z" fill="none" stroke="#000" stroke-width=".21"/>
<path d="M215.8 107.6h7.6" fill="none" stroke="#000" stroke-width=".25"/>
<path d="M215.8 107.6l1.5-.5v1z" fill="#f8fcff"/>
<path d="M215.8 107.6l1.5-.5v1z" fill="none" stroke="#000" stroke-width=".21"/>
<path d="M217.6 107.1l1.5 .5-1.5 .5z" fill="#f8fcff"/>
<path d="M215.8 107.1l-1 .5 1 .5M217.6 107.1l1.5 .5-1.5 .5z" fill="none" stroke="#000" stroke-width=".21"/>
<path d="M215.8 110.1h7.6" fill="none" stroke="#000" stroke-width=".25"/>
<path d="M215.8 110.1l1.5-.5v1z" fill="#f8fcff"/>
<path d="M215.8 110.1l1.5-.5v1z" fill="none" stroke="#000" stroke-width=".21"/>
<path d="M217.6 109.6l1.5 .5-1.5 .5z" fill="#f8fcff"/>
<path d="M217.6 109.6l1.5 .5-1.5 .5z" fill="none" stroke="#000" stroke-width=".21"/>
<path d="M215.8 112.6h7.6" fill="none" stroke="#000" stroke-width=".25"/>
<path d="M215.8 112.6l1.5-.5v1.1z" fill="#f8fcff"/>
<path d="M215.8 112.6l1.5-.5v1.1z" fill="none" stroke="#000" stroke-width=".21"/>
<path d="M217.6 112.1l1.5 .5-1.5 .6z" fill="#f8fcff"/>
<path d="M217.6 112.1l1.5 .5-1.5 .6z" fill="none" stroke="#000" stroke-width=".21"/>
<path d="M215.8 115.2h7.6" fill="none" stroke="#000" stroke-width=".25"/>
<path d="M215.8 115.2l1.5-.5v1z" fill="#f8fcff"/>
<path d="M215.8 115.2l1.5-.5v1z" fill="none" stroke="#000" stroke-width=".21"/>
<path d="M217.6 114.7l1.5 .5-1.5 .5z" fill="#f8fcff"/>
<path d="M217.6 114.7l1.5 .5-1.5 .5z" fill="none" stroke="#000" stroke-width=".21"/>
<path d="M215.8 117.7h7.6" fill="none" stroke="#000" stroke-width=".25"/>
<path d="M215.8 117.7l1.5-.5v1z" fill="#f8fcff"/>
<path d="M215.8 117.7l1.5-.5v1z" fill="none" stroke="#000" stroke-width=".21"/>
<path d="M217.6 117.2l1.5 .5-1.5 .5z" fill="#f8fcff"/>
<path d="M217.6 117.2l1.5 .5-1.5 .5z" fill="none" stroke="#000" stroke-width=".21"/>
<path d="M215.8 120.3h7.6" fill="none" stroke="#000" stroke-width=".25"/>
<path d="M215.8 120.3l1.5-.5v1z" fill="#f8fcff"/>
<path d="M215.8 120.3l1.5-.5v1z" fill="none" stroke="#000" stroke-width=".21"/>
<path d="M217.6 119.8l1.5 .5-1.5 .5z" fill="#f8fcff"/>
<path d="M217.6 119.8l1.5 .5-1.5 .5z" fill="none" stroke="#000" stroke-width=".21"/>
<path d="M215.8 122.8h7.6" fill="none" stroke="#000" stroke-width=".25"/>
<path d="M215.8 122.8l1.5-.5v1z" fill="#f8fcff"/>
<path d="M215.8 122.8l1.5-.5v1z" fill="none" stroke="#000" stroke-width=".21"/>
<path d="M217.6 122.3l1.5 .5-1.5 .5z" fill="#f8fcff"/>
<path d="M217.6 122.3l1.5 .5-1.5 .5z" fill="none" stroke="#000" stroke-width=".21"/>
<path d="M215.8 125.3h7.6" fill="none" stroke="#000" stroke-width=".25"/>
<path d="M215.8 125.3l1.5-.5v1.1z" fill="#f8fcff"/>
<path d="M215.8 125.3l1.5-.5v1.1z" fill="none" stroke="#000" stroke-width=".21"/>
<path d="M217.6 124.8l1.5 .5-1.5 .6z" fill="#f8fcff"/>
<path d="M217.6 124.8l1.5 .5-1.5 .6z" fill="none" stroke="#000" stroke-width=".21"/>
<path d="M215.8 127.9h7.6" fill="none" stroke="#000" stroke-width=".25"/>
<path d="M215.8 127.9l1.5-.5v1z" fill="#f8fcff"/>
<path d="M215.8 127.9l1.5-.5v1z" fill="none" stroke="#000" stroke-width=".21"/>
<path d="M217.6 127.4l1.5 .5-1.5 .5z" fill="#f8fcff"/>
<path d="M217.6 127.4l1.5 .5-1.5 .5z" fill="none" stroke="#000" stroke-width=".21"/>
<path d="M215.8 130.4h7.6" fill="none" stroke="#000" stroke-width=".25"/>
<path d="M215.8 130.4l1.5-.5v1z" fill="#f8fcff"/>
<path d="M215.8 130.4l1.5-.5v1z" fill="none" stroke="#000" stroke-width=".21"/>
<path d="M217.6 129.9l1.5 .5-1.5 .5z" fill="#f8fcff"/>
<path d="M217.6 129.9l1.5 .5-1.5 .5z" fill="none" stroke="#000" stroke-width=".21"/>
<path d="M215.8 133h7.6" fill="none" stroke="#000" stroke-width=".25"/>
<path d="M215.8 133l1.5-.5v1z" fill="#f8fcff"/>
<path d="M215.8 133l1.5-.5v1z" fill="none" stroke="#000" stroke-width=".21"/>
<path d="M217.6 132.5l1.5 .5-1.5 .5z" fill="#f8fcff"/>
<path d="M217.6 132.5l1.5 .5-1.5 .5z" fill="none" stroke="#000" stroke-width=".21"/>
<path d="M215.8 135.5h7.6" fill="none" stroke="#000" stroke-width=".25"/>
<path d="M215.8 135.5l1.5-.5v1z" fill="#f8fcff"/>
<path d="M215.8 135.5l1.5-.5v1z" fill="none" stroke="#000" stroke-width=".21"/>
<path d="M217.6 135l1.5 .5-1.5 .5z" fill="#f8fcff"/>
<path d="M217.6 135l1.5 .5-1.5 .5z" fill="none" stroke="#000" stroke-width=".21"/>
<path d="M215.8 138h7.6" fill="none" stroke="#000" stroke-width=".25"/>
<path d="M215.8 138l1.5-.5v1.1z" fill="#f8fcff"/>
<path d="M215.8 138l1.5-.5v1.1z" fill="none" stroke="#000" stroke-width=".21"/>
<path d="M217.6 137.5l1.5 .5-1.5 .6z" fill="#f8fcff"/>
<path d="M217.6 137.5l1.5 .5-1.5 .6z" fill="none" stroke="#000" stroke-width=".21"/>
<path d="M215.8 140.6h7.6" fill="none" stroke="#000" stroke-width=".25"/>
<path d="M215.8 140.6l1.5-.5v1z" fill="#f8fcff"/>
<path d="M215.8 140.6l1.5-.5v1z" fill="none" stroke="#000" stroke-width=".21"/>
<path d="M217.6 140.1l1.5 .5-1.5 .5z" fill="#f8fcff"/>
<path d="M217.6 140.1l1.5 .5-1.5 .5z" fill="none" stroke="#000" stroke-width=".21"/>
<path d="M215.8 143.1h7.6" fill="none" stroke="#000" stroke-width=".25"/>
<path d="M215.8 143.1l1.5-.5v1z" fill="#f8fcff"/>
<path d="M215.8 143.1l1.5-.5v1z" fill="none" stroke="#000" stroke-width=".21"/>
<path d="M217.6 142.6l1.5 .5-1.5 .5z" fill="#f8fcff"/>
<path d="M217.6 142.6l1.5 .5-1.5 .5z" fill="none" stroke="#000" stroke-width=".21"/>
<path d="M215.8 145.7h7.6" fill="none" stroke="#000" stroke-width=".25"/>
<path d="M215.8 145.7l1.5-.5v1z" fill="#f8fcff"/>
<path d="M215.8 145.7l1.5-.5v1z" fill="none" stroke="#000" stroke-width=".21"/>
<path d="M217.6 145.2l1.5 .5-1.5 .5z" fill="#f8fcff"/>
<path d="M217.6 145.2l1.5 .5-1.5 .5z" fill="none" stroke="#000" stroke-width=".21"/>
<path d="M215.8 148.2h7.6" fill="none" stroke="#000" stroke-width=".25"/>
<path d="M215.8 148.2l1.5-.5v1z" fill="#f8fcff"/>
<path d="M215.8 148.2l1.5-.5v1z" fill="none" stroke="#000" stroke-width=".21"/>
<path d="M217.6 147.7l1.5 .5-1.5 .5z" fill="#f8fcff"/>
<path d="M217.6 147.7l1.5 .5-1.5 .5z" fill="none" stroke="#000" stroke-width=".21"/>
<path d="M215.8 150.7h7.6" fill="none" stroke="#000" stroke-width=".25"/>
<path d="M215.8 150.7l1.5-.5v1.1z" fill="#f8fcff"/>
<path d="M215.8 150.7l1.5-.5v1.1z" fill="none" stroke="#000" stroke-width=".21"/>
<path d="M217.6 150.2l1.5 .5-1.5 .6z" fill="#f8fcff"/>
<path d="M217.6 150.2l1.5 .5-1.5 .6z" fill="none" stroke="#000" stroke-width=".21"/>
<path d="M215.8 153.3h7.6" fill="none" stroke="#000" stroke-width=".25"/>
<path d="M215.8 153.3l1.5-.5v1z" fill="#f8fcff"/>
<path d="M215.8 153.3l1.5-.5v1z" fill="none" stroke="#000" stroke-width=".21"/>
<path d="M217.6 152.8l1.5 .5-1.5 .5z" fill="#f8fcff"/>
<path d="M217.6 152.8l1.5 .5-1.5 .5z" fill="none" stroke="#000" stroke-width=".21"/>
<path d="M215.8 155.8h7.6" fill="none" stroke="#000" stroke-width=".25"/>
<path d="M215.8 155.8l1.5-.5v1z" fill="#f8fcff"/>
<path d="M215.8 155.8l1.5-.5v1z" fill="none" stroke="#000" stroke-width=".21"/>
<path d="M217.6 155.3l1.5 .5-1.5 .5z" fill="#f8fcff"/>
<path d="M217.6 155.3l1.5 .5-1.5 .5z" fill="none" stroke="#000" stroke-width=".21"/>
<path d="M215.8 158.4h7.6" fill="none" stroke="#000" stroke-width=".25"/>
<path d="M215.8 158.4l1.5-.5v1z" fill="#f8fcff"/>
<path d="M215.8 158.4l1.5-.5v1z" fill="none" stroke="#000" stroke-width=".21"/>
<path d="M217.6 157.9l1.5 .5-1.5 .5z" fill="#f8fcff"/>
<path d="M217.6 157.9l1.5 .5-1.5 .5z" fill="none" stroke="#000" stroke-width=".21"/>
<path d="M215.8 160.9h7.6" fill="none" stroke="#000" stroke-width=".25"/>
<path d="M215.8 160.9l1.5-.5v1z" fill="#f8fcff"/>
<path d="M215.8 160.9l1.5-.5v1z" fill="none" stroke="#000" stroke-width=".21"/>
<path d="M217.6 160.4l1.5 .5-1.5 .5z" fill="#f8fcff"/>
<path d="M217.6 160.4l1.5 .5-1.5 .5z" fill="none" stroke="#000" stroke-width=".21"/>
<path d="M222.4 35.4l2 2.1M224.4 35.4l-2 2.1M222.4 93.9l2 2M222.4 98.9l2 2.1M224.4 93.9l-2 2M224.4 98.9l-2 2.1M222.4 159.9l2 2M224.4 159.9l-2 2" fill="none" stroke="#f00" stroke-width=".21"/>
<path d="M128.1 31.4h2.6M129.4 31.4v2.5M243.7 66.9h2.6M246.3 65.7v2.5M139.6 133h5.1M140.3 133.7h3.6M141.1 134.5h2M141.9 135.3h.5M142.1 130.4v2.6M243.7 133h2.6M246.3 131.7v2.5" fill="none" stroke="#800000" stroke-width=".25"/>
<g fill="none" stroke="#000" stroke-width=".25">
<path d="M129.4 36.4v2M129.4 44.6v2M126.9 87.2h2.5M126.9 92.3h2.5M142.1 127.9v2.5M143.4 126.6a1.27 1.27 0 0 0-1.8-1.1 1.27 1.27 0 0 0-.3 2.1 1.27 1.27 0 0 0 2-.6l.1-.4"/>
<circle cx="130.7" cy="87.2" r="1.27"/>
<circle cx="130.7" cy="92.3" r="1.27"/>
<circle cx="142.1" cy="126.6" r="1.27"/>
</g>
<path d="M128.4 38.5h2.1v6h-2.1z" fill="none" stroke="#00f" stroke-width=".25"/>
<g fill="none" stroke="#000080" stroke-width=".25">
<path d="M101.5 39h17.8M129.4 33.9v2.5M223.4 39h17.8M101.5 41.5h17.8M101.5 44.1h17.8M101.5 46.6h17.8M101.5 54.2h17.8M101.5 51.7h17.8M101.5 56.8h17.8M129.4 46.6v2.5h-27.9M223.4 41.5h17.8M223.4 44.1h17.8"/>
<path d="M223.4 46.6h17.8M223.4 54.2h17.8M223.4 56.8h17.8M223.4 59.3h17.8M223.4 49.1h17.8M223.4 51.7h17.8M101.5 64.4h17.8M101.5 66.9h17.8M101.5 61.8h17.8M101.5 69.5h17.8M101.5 72h17.8M223.4 64.4h17.8"/>
<path d="M223.4 66.9h20.3M223.4 61.8h17.8M223.4 69.5h17.8M223.4 72h17.8M223.4 74.5h17.8M223.4 77.1h17.8M223.4 79.6h17.8M101.5 99.9h17.8M101.5 82.2h17.8M101.5 84.7h17.8M101.5 87.2h25.4M101.5 92.3h25.4"/>
<path d="M223.4 82.2h17.8M223.4 84.7h17.8M223.4 87.2h17.8M223.4 89.8h17.8M223.4 92.3h17.8M223.4 97.4h17.8M101.5 102.5h17.8M101.5 115.2h17.8M101.5 117.7h17.8M101.5 110.1h17.8M101.5 112.6h17.8M223.4 102.5h17.8"/>
<path d="M223.4 105h17.8M223.4 107.6h17.8M223.4 115.2h17.8M223.4 117.7h17.8M223.4 110.1h17.8M223.4 112.6h17.8M101.5 138h17.8M101.5 125.3h17.8M101.5 133h17.8M101.5 127.9h17.8M223.4 120.3h17.8M223.4 122.8h17.8"/>
<path d="M223.4 130.4h17.8M223.4 135.5h17.8M223.4 138h17.8M223.4 125.3h17.8M223.4 133h20.3M223.4 127.9h17.8M101.5 145.7h17.8M101.5 150.7h17.8M101.5 153.3h17.8M101.5 155.8h17.8M101.5 140.6h17.8M101.5 143.1h17.8"/>
<path d="M101.5 158.4h17.8M223.4 145.7h17.8M223.4 148.2h17.8M223.4 150.7h17.8M223.4 153.3h17.8M223.4 155.8h17.8M223.4 140.6h17.8M223.4 143.1h17.8M223.4 158.4h17.8"/>
</g>
<use href="#words"/>
</svg>
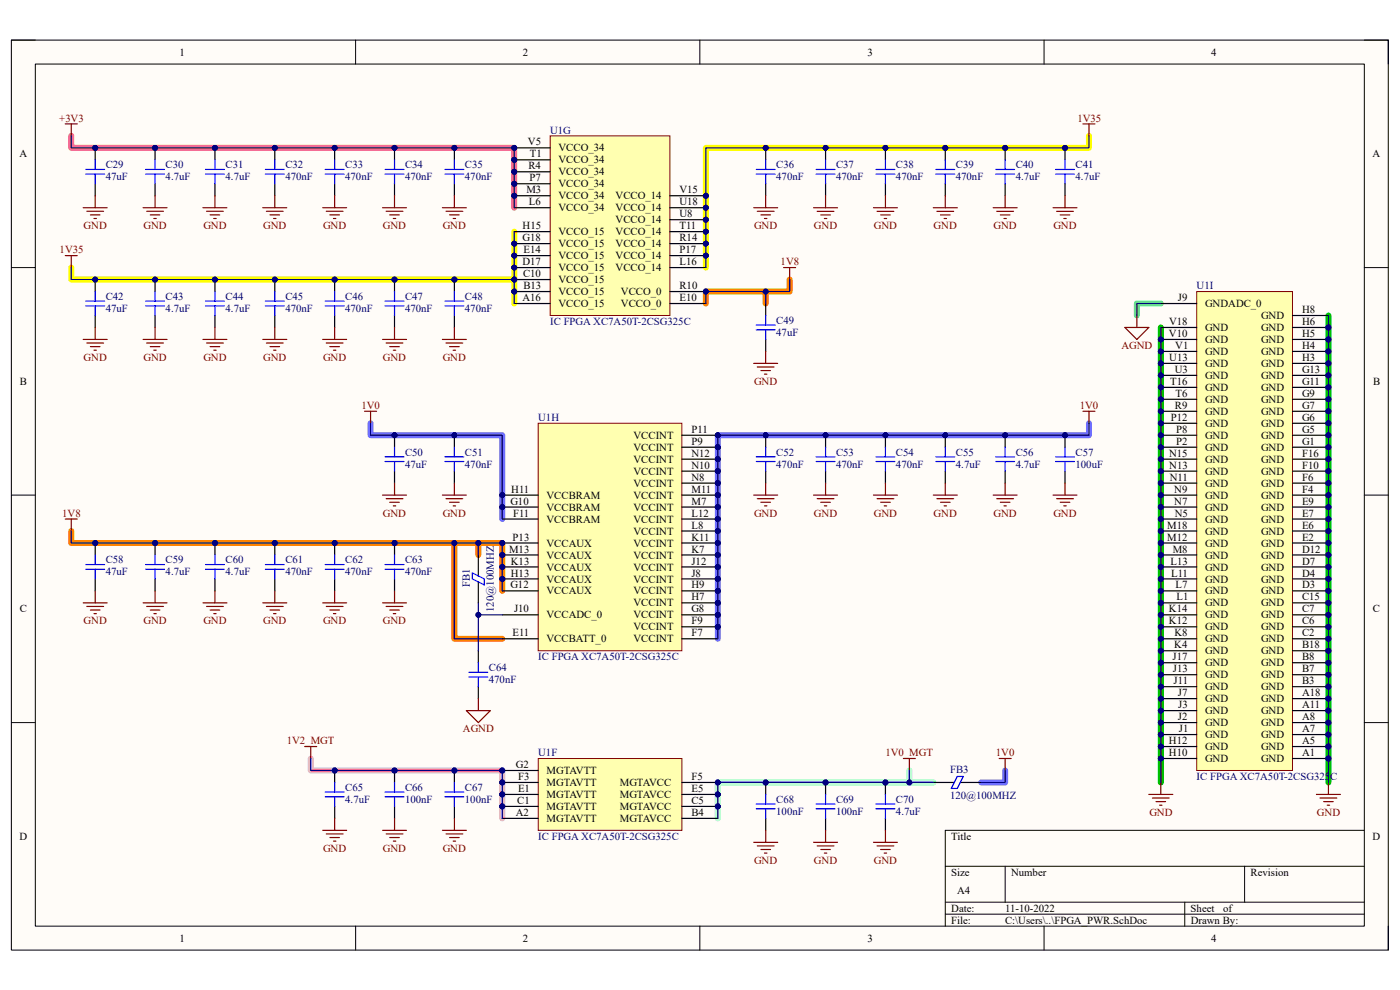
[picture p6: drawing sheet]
<svg xmlns="http://www.w3.org/2000/svg" width="297mm" height="210mm" viewBox="0 0 297 210" stroke-linecap="round" stroke-linejoin="round" font-family="sans-serif">
<defs><g id="words">
<g font-size="2.3">
<text x="38.1" y="11.8">1</text>
<text x="110.9" y="11.8">2</text>
<text x="184" y="11.8">3</text>
<text x="256.9" y="11.8">4</text>
<text x="4.1" y="33.4">A</text>
<text x="112" y="30.9">V5</text>
<text x="112.1" y="35.9">R4</text>
<text x="112.4" y="33.4">T1</text>
<text x="118.5" y="34.7">VCCO_34</text>
<text x="118.5" y="32.1">VCCO_34</text>
<text x="291.2" y="33.4">A</text>
<text x="111.7" y="41">M3</text>
<text x="112.4" y="38.5">P7</text>
<text x="118.5" y="39.8">VCCO_34</text>
<text x="118.5" y="37.2">VCCO_34</text>
<text x="144.1" y="41">V15</text>
<text x="112.2" y="43.6">L6</text>
<text x="118.5" y="44.8">VCCO_34</text>
<text x="118.5" y="42.3">VCCO_34</text>
<text x="130.6" y="47.4">VCCO_14</text>
<text x="130.6" y="44.8">VCCO_14</text>
<text x="130.6" y="42.3">VCCO_14</text>
<text x="144.1" y="46.1">U8</text>
<text x="144.1" y="43.6">U18</text>
<text x="110.9" y="51.2">G18</text>
<text x="110.9" y="48.6">H15</text>
<text x="111.1" y="53.7">E14</text>
<text x="118.5" y="52.5">VCCO_15</text>
<text x="118.5" y="49.9">VCCO_15</text>
<text x="130.6" y="52.5">VCCO_14</text>
<text x="130.6" y="49.9">VCCO_14</text>
<text x="144.1" y="53.7">P17</text>
<text x="144.1" y="51.2">R14</text>
<text x="144.1" y="48.6">T11</text>
<text x="110.8" y="56.3">D17</text>
<text x="111" y="58.8">C10</text>
<text x="118.5" y="57.5">VCCO_15</text>
<text x="118.5" y="55">VCCO_15</text>
<text x="130.6" y="57.5">VCCO_14</text>
<text x="130.6" y="55">VCCO_14</text>
<text x="144.1" y="56.3">L16</text>
<text x="110.8" y="63.9">A16</text>
<text x="111" y="61.3">B13</text>
<text x="118.5" y="65.2">VCCO_15</text>
<text x="118.5" y="62.6">VCCO_15</text>
<text x="118.5" y="60.1">VCCO_15</text>
<text x="131.7" y="65.2">VCCO_0</text>
<text x="131.7" y="62.6">VCCO_0</text>
<text x="144.1" y="63.9">E10</text>
<text x="144.1" y="61.3">R10</text>
<text x="249.9" y="63.9">J9</text>
<text x="255.7" y="65.2">GNDADC_0</text>
<text x="248" y="71.5">V10</text>
<text x="248" y="69">V18</text>
<text x="255.7" y="70.2">GND</text>
<text x="267.5" y="70.2">GND</text>
<text x="267.5" y="67.7">GND</text>
<text x="276.2" y="71.5">H5</text>
<text x="276.2" y="69">H6</text>
<text x="276.2" y="66.4">H8</text>
<text x="248.1" y="76.6">U13</text>
<text x="249.3" y="74">V1</text>
<text x="255.7" y="77.9">GND</text>
<text x="255.7" y="75.3">GND</text>
<text x="255.7" y="72.8">GND</text>
<text x="267.5" y="77.9">GND</text>
<text x="267.5" y="75.3">GND</text>
<text x="267.5" y="72.8">GND</text>
<text x="276.2" y="76.6">H3</text>
<text x="276.2" y="74">H4</text>
<text x="4.2" y="81.7">B</text>
<text x="248.2" y="81.7">T16</text>
<text x="249.2" y="79.1">U3</text>
<text x="255.7" y="82.9">GND</text>
<text x="255.7" y="80.4">GND</text>
<text x="267.5" y="82.9">GND</text>
<text x="267.5" y="80.4">GND</text>
<text x="276.2" y="81.7">G11</text>
<text x="276.2" y="79.1">G13</text>
<text x="291.3" y="81.7">B</text>
<text x="248.4" y="89.3">P12</text>
<text x="249.3" y="86.7">R9</text>
<text x="249.4" y="84.2">T6</text>
<text x="255.7" y="88">GND</text>
<text x="255.7" y="85.5">GND</text>
<text x="267.5" y="88">GND</text>
<text x="267.5" y="85.5">GND</text>
<text x="276.2" y="89.3">G6</text>
<text x="276.2" y="86.7">G7</text>
<text x="276.2" y="84.2">G9</text>
<text x="134.4" y="95.6">VCCINT</text>
<text x="134.4" y="93.1">VCCINT</text>
<text x="146.7" y="94.4">P9</text>
<text x="146.7" y="91.8">P11</text>
<text x="249.5" y="94.4">P2</text>
<text x="249.6" y="91.8">P8</text>
<text x="255.7" y="95.6">GND</text>
<text x="255.7" y="93.1">GND</text>
<text x="255.7" y="90.6">GND</text>
<text x="267.5" y="95.6">GND</text>
<text x="267.5" y="93.1">GND</text>
<text x="267.5" y="90.6">GND</text>
<text x="276.2" y="94.4">G1</text>
<text x="276.2" y="91.8">G5</text>
<text x="134.4" y="100.7">VCCINT</text>
<text x="134.4" y="98.2">VCCINT</text>
<text x="146.7" y="102">N8</text>
<text x="146.7" y="99.4">N10</text>
<text x="146.7" y="96.9">N12</text>
<text x="248" y="96.9">N15</text>
<text x="248.1" y="99.4">N13</text>
<text x="248.2" y="102">N11</text>
<text x="255.7" y="100.7">GND</text>
<text x="255.7" y="98.2">GND</text>
<text x="267.5" y="100.7">GND</text>
<text x="267.5" y="98.2">GND</text>
<text x="276.2" y="102">F6</text>
<text x="276.2" y="99.4">F10</text>
<text x="276.2" y="96.9">F16</text>
<text x="108.3" y="107.1">G10</text>
<text x="108.5" y="104.5">H11</text>
<text x="116" y="105.8">VCCBRAM</text>
<text x="134.4" y="105.8">VCCINT</text>
<text x="134.4" y="103.3">VCCINT</text>
<text x="146.7" y="107.1">M7</text>
<text x="146.7" y="104.5">M11</text>
<text x="249.1" y="107.1">N7</text>
<text x="249.1" y="104.5">N9</text>
<text x="255.7" y="105.8">GND</text>
<text x="255.7" y="103.3">GND</text>
<text x="267.5" y="105.8">GND</text>
<text x="267.5" y="103.3">GND</text>
<text x="276.2" y="107.1">E9</text>
<text x="276.2" y="104.5">F4</text>
<text x="108.8" y="109.6">F11</text>
<text x="116" y="110.9">VCCBRAM</text>
<text x="116" y="108.3">VCCBRAM</text>
<text x="134.4" y="113.4">VCCINT</text>
<text x="134.4" y="110.9">VCCINT</text>
<text x="134.4" y="108.3">VCCINT</text>
<text x="146.7" y="112.1">L8</text>
<text x="146.7" y="109.6">L12</text>
<text x="247.6" y="112.1">M18</text>
<text x="249.2" y="109.6">N5</text>
<text x="255.7" y="113.4">GND</text>
<text x="255.7" y="110.9">GND</text>
<text x="255.7" y="108.3">GND</text>
<text x="267.5" y="113.4">GND</text>
<text x="267.5" y="110.9">GND</text>
<text x="267.5" y="108.3">GND</text>
<text x="276.2" y="112.1">E6</text>
<text x="276.2" y="109.6">E7</text>
<text x="108" y="117.2">M13</text>
<text x="108.4" y="119.8">K13</text>
<text x="108.8" y="114.7">P13</text>
<text x="116" y="118.5">VCCAUX</text>
<text x="116" y="116">VCCAUX</text>
<text x="134.4" y="118.5">VCCINT</text>
<text x="134.4" y="116">VCCINT</text>
<text x="146.7" y="119.8">J12</text>
<text x="146.7" y="117.2">K7</text>
<text x="146.7" y="114.7">K11</text>
<text x="247.6" y="114.7">M12</text>
<text x="248.3" y="119.8">L13</text>
<text x="248.8" y="117.2">M8</text>
<text x="255.7" y="118.5">GND</text>
<text x="255.7" y="116">GND</text>
<text x="267.5" y="118.5">GND</text>
<text x="267.5" y="116">GND</text>
<text x="276.2" y="119.8">D7</text>
<text x="276.2" y="117.2">D12</text>
<text x="276.2" y="114.7">E2</text>
<text x="108.3" y="124.8">G12</text>
<text x="108.4" y="122.3">H13</text>
<text x="116" y="123.6">VCCAUX</text>
<text x="116" y="121">VCCAUX</text>
<text x="134.4" y="123.6">VCCINT</text>
<text x="134.4" y="121">VCCINT</text>
<text x="146.7" y="124.8">H9</text>
<text x="146.7" y="122.3">J8</text>
<text x="248.5" y="122.3">L11</text>
<text x="249.4" y="124.8">L7</text>
<text x="255.7" y="123.6">GND</text>
<text x="255.7" y="121">GND</text>
<text x="267.5" y="123.6">GND</text>
<text x="267.5" y="121">GND</text>
<text x="276.2" y="124.8">D3</text>
<text x="276.2" y="122.3">D4</text>
<text x="4.2" y="129.9">C</text>
<text x="109.1" y="129.9">J10</text>
<text x="116" y="126.1">VCCAUX</text>
<text x="116" y="131.2">VCCADC_0</text>
<text x="134.4" y="131.2">VCCINT</text>
<text x="134.4" y="128.7">VCCINT</text>
<text x="134.4" y="126.1">VCCINT</text>
<text x="146.7" y="129.9">G8</text>
<text x="146.7" y="127.4">H7</text>
<text x="248" y="129.9">K14</text>
<text x="249.6" y="127.4">L1</text>
<text x="255.7" y="131.2">GND</text>
<text x="255.7" y="128.7">GND</text>
<text x="255.7" y="126.1">GND</text>
<text x="267.5" y="131.2">GND</text>
<text x="267.5" y="128.7">GND</text>
<text x="267.5" y="126.1">GND</text>
<text x="276.2" y="129.9">C7</text>
<text x="276.2" y="127.4">C15</text>
<text x="291.3" y="129.9">C</text>
<text x="108.7" y="135">E11</text>
<text x="116" y="136.3">VCCBATT_0</text>
<text x="134.4" y="136.3">VCCINT</text>
<text x="134.4" y="133.7">VCCINT</text>
<text x="146.7" y="135">F7</text>
<text x="146.7" y="132.5">F9</text>
<text x="248" y="132.5">K12</text>
<text x="249.1" y="137.5">K4</text>
<text x="249.2" y="135">K8</text>
<text x="255.7" y="136.3">GND</text>
<text x="255.7" y="133.7">GND</text>
<text x="267.5" y="136.3">GND</text>
<text x="267.5" y="133.7">GND</text>
<text x="276.2" y="137.5">B18</text>
<text x="276.2" y="135">C2</text>
<text x="276.2" y="132.5">C6</text>
<text x="248.8" y="140.1">J17</text>
<text x="248.8" y="142.6">J13</text>
<text x="255.7" y="143.9">GND</text>
<text x="255.7" y="141.4">GND</text>
<text x="255.7" y="138.8">GND</text>
<text x="267.5" y="143.9">GND</text>
<text x="267.5" y="141.4">GND</text>
<text x="267.5" y="138.8">GND</text>
<text x="276.2" y="142.6">B7</text>
<text x="276.2" y="140.1">B8</text>
<text x="249" y="145.2">J11</text>
<text x="249.9" y="147.7">J7</text>
<text x="255.7" y="149">GND</text>
<text x="255.7" y="146.4">GND</text>
<text x="267.5" y="149">GND</text>
<text x="267.5" y="146.4">GND</text>
<text x="276.2" y="147.7">A18</text>
<text x="276.2" y="145.2">B3</text>
<text x="249.9" y="152.8">J2</text>
<text x="250" y="150.2">J3</text>
<text x="250.1" y="155.3">J1</text>
<text x="255.7" y="154.1">GND</text>
<text x="255.7" y="151.5">GND</text>
<text x="267.5" y="154.1">GND</text>
<text x="267.5" y="151.5">GND</text>
<text x="276.2" y="155.3">A7</text>
<text x="276.2" y="152.8">A8</text>
<text x="276.2" y="150.2">A11</text>
<text x="248" y="160.4">H10</text>
<text x="248" y="157.9">H12</text>
<text x="255.7" y="161.7">GND</text>
<text x="255.7" y="159.1">GND</text>
<text x="255.7" y="156.6">GND</text>
<text x="267.5" y="161.7">GND</text>
<text x="267.5" y="159.1">GND</text>
<text x="267.5" y="156.6">GND</text>
<text x="276.2" y="160.4">A1</text>
<text x="276.2" y="157.9">A5</text>
<text x="109.4" y="162.9">G2</text>
<text x="109.9" y="165.5">F3</text>
<text x="116" y="166.8">MGTAVTT</text>
<text x="116" y="164.2">MGTAVTT</text>
<text x="131.5" y="166.8">MGTAVCC</text>
<text x="146.7" y="165.5">F5</text>
<text x="109.4" y="173.1">A2</text>
<text x="109.7" y="170.6">C1</text>
<text x="109.9" y="168">E1</text>
<text x="116" y="171.8">MGTAVTT</text>
<text x="116" y="169.3">MGTAVTT</text>
<text x="131.5" y="171.8">MGTAVCC</text>
<text x="131.5" y="169.3">MGTAVCC</text>
<text x="146.7" y="173.1">B4</text>
<text x="146.7" y="170.6">C5</text>
<text x="146.7" y="168">E5</text>
<text x="4.1" y="178.2">D</text>
<text x="116" y="174.4">MGTAVTT</text>
<text x="131.5" y="174.4">MGTAVCC</text>
<text x="201.8" y="178.2">Title</text>
<text x="291.2" y="178.2">D</text>
<text x="201.8" y="185.8">Size</text>
<text x="214.5" y="185.8">Number</text>
<text x="265.3" y="185.8">Revision</text>
<text x="203.1" y="189.6">A4</text>
<text x="201.8" y="193.4">Date:</text>
<text x="201.8" y="196">File:</text>
<text x="213.2" y="196">C:\Users\..\FPGA_PWR.SchDoc</text>
<text x="213.2" y="193.4">11-10-2022</text>
<text x="252.6" y="193.4">Sheet</text>
<text x="252.6" y="196">Drawn By:</text>
<text x="259.5" y="193.4">of</text>
<text x="38.1" y="199.8">1</text>
<text x="110.9" y="199.8">2</text>
<text x="184" y="199.8">3</text>
<text x="256.9" y="199.8">4</text>
</g>
<g font-size="2.3" fill="#800000">
<text x="12.6" y="25.8">+3V3</text>
<text x="228.6" y="25.8">1V35</text>
<text x="12.7" y="53.7">1V35</text>
<text x="17.7" y="48.6">GND</text>
<text x="30.4" y="48.6">GND</text>
<text x="43.1" y="48.6">GND</text>
<text x="55.8" y="48.6">GND</text>
<text x="68.5" y="48.6">GND</text>
<text x="81.2" y="48.6">GND</text>
<text x="93.9" y="48.6">GND</text>
<text x="160" y="48.6">GND</text>
<text x="172.7" y="48.6">GND</text>
<text x="185.4" y="48.6">GND</text>
<text x="198.1" y="48.6">GND</text>
<text x="210.8" y="48.6">GND</text>
<text x="223.5" y="48.6">GND</text>
<text x="165.6" y="56.3">1V8</text>
<text x="17.7" y="76.6">GND</text>
<text x="30.4" y="76.6">GND</text>
<text x="43.1" y="76.6">GND</text>
<text x="55.8" y="76.6">GND</text>
<text x="68.5" y="76.6">GND</text>
<text x="81.2" y="76.6">GND</text>
<text x="93.9" y="76.6">GND</text>
<text x="237.9" y="74">AGND</text>
<text x="160" y="81.7">GND</text>
<text x="76.7" y="86.7">1V0</text>
<text x="229.1" y="86.7">1V0</text>
<text x="13.2" y="109.6">1V8</text>
<text x="81.2" y="109.6">GND</text>
<text x="93.9" y="109.6">GND</text>
<text x="160" y="109.6">GND</text>
<text x="172.7" y="109.6">GND</text>
<text x="185.4" y="109.6">GND</text>
<text x="198.1" y="109.6">GND</text>
<text x="210.8" y="109.6">GND</text>
<text x="223.5" y="109.6">GND</text>
<text x="17.7" y="132.5">GND</text>
<text x="30.4" y="132.5">GND</text>
<text x="43.1" y="132.5">GND</text>
<text x="55.8" y="132.5">GND</text>
<text x="68.5" y="132.5">GND</text>
<text x="81.2" y="132.5">GND</text>
<text x="98.2" y="155.3">AGND</text>
<text x="60.8" y="157.9">1V2_MGT</text>
<text x="187.8" y="160.4">1V0_MGT</text>
<text x="211.3" y="160.4">1V0</text>
<text x="243.8" y="173.1">GND</text>
<text x="279.4" y="173.1">GND</text>
<text x="68.5" y="180.7">GND</text>
<text x="81.2" y="180.7">GND</text>
<text x="93.9" y="180.7">GND</text>
<text x="160" y="183.3">GND</text>
<text x="172.7" y="183.3">GND</text>
<text x="185.4" y="183.3">GND</text>
</g>
<g font-size="2.3" fill="#000080">
<text x="116.7" y="28.3">U1G</text>
<text x="22.4" y="35.7">C29</text>
<text x="35.1" y="35.7">C30</text>
<text x="47.8" y="35.7">C31</text>
<text x="60.5" y="35.7">C32</text>
<text x="73.2" y="35.7">C33</text>
<text x="85.9" y="35.7">C34</text>
<text x="98.6" y="35.7">C35</text>
<text x="164.7" y="35.7">C36</text>
<text x="177.4" y="35.7">C37</text>
<text x="190.1" y="35.7">C38</text>
<text x="202.8" y="35.7">C39</text>
<text x="215.5" y="35.7">C40</text>
<text x="228.2" y="35.7">C41</text>
<text x="22.4" y="38.2">47uF</text>
<text x="35.1" y="38.2">4.7uF</text>
<text x="47.8" y="38.2">4.7uF</text>
<text x="60.5" y="38.2">470nF</text>
<text x="73.2" y="38.2">470nF</text>
<text x="85.9" y="38.2">470nF</text>
<text x="98.6" y="38.2">470nF</text>
<text x="164.7" y="38.2">470nF</text>
<text x="177.4" y="38.2">470nF</text>
<text x="190.1" y="38.2">470nF</text>
<text x="202.8" y="38.2">470nF</text>
<text x="215.5" y="38.2">4.7uF</text>
<text x="228.2" y="38.2">4.7uF</text>
<text x="22.4" y="63.6">C42</text>
<text x="35.1" y="63.6">C43</text>
<text x="47.8" y="63.6">C44</text>
<text x="60.5" y="63.6">C45</text>
<text x="73.2" y="63.6">C46</text>
<text x="85.9" y="63.6">C47</text>
<text x="98.6" y="63.6">C48</text>
<text x="253.9" y="61.3">U1I</text>
<text x="22.4" y="66.2">47uF</text>
<text x="35.1" y="66.2">4.7uF</text>
<text x="47.8" y="66.2">4.7uF</text>
<text x="60.5" y="66.2">470nF</text>
<text x="73.2" y="66.2">470nF</text>
<text x="85.9" y="66.2">470nF</text>
<text x="98.6" y="66.2">470nF</text>
<text x="116.7" y="69">IC FPGA XC7A50T-2CSG325C</text>
<text x="164.7" y="68.7">C49</text>
<text x="164.7" y="71.2">47uF</text>
<text x="114.2" y="89.3">U1H</text>
<text x="85.9" y="96.6">C50</text>
<text x="85.9" y="99.2">47uF</text>
<text x="98.6" y="96.6">C51</text>
<text x="98.6" y="99.2">470nF</text>
<text x="164.7" y="96.6">C52</text>
<text x="164.7" y="99.2">470nF</text>
<text x="177.4" y="96.6">C53</text>
<text x="177.4" y="99.2">470nF</text>
<text x="190.1" y="96.6">C54</text>
<text x="190.1" y="99.2">470nF</text>
<text x="202.8" y="96.6">C55</text>
<text x="202.8" y="99.2">4.7uF</text>
<text x="215.5" y="96.6">C56</text>
<text x="215.5" y="99.2">4.7uF</text>
<text x="228.2" y="96.6">C57</text>
<text x="228.2" y="99.2">100uF</text>
<text x="22.4" y="119.5">C58</text>
<text x="35.1" y="119.5">C59</text>
<text x="47.8" y="119.5">C60</text>
<text x="60.5" y="119.5">C61</text>
<text x="73.2" y="119.5">C62</text>
<text x="85.9" y="119.5">C63</text>
<text x="22.4" y="122">47uF</text>
<text x="35.1" y="122">4.7uF</text>
<text x="47.8" y="122">4.7uF</text>
<text x="60.5" y="122">470nF</text>
<text x="73.2" y="122">470nF</text>
<text x="85.9" y="122">470nF</text>
<text x="99.7" y="124.6" transform="rotate(-90 99.7 124.6)">FB1</text>
<text x="104.8" y="129.8" transform="rotate(-90 104.8 129.8)">120@100MHZ</text>
<text x="103.7" y="142.4">C64</text>
<text x="114.2" y="140.1">IC FPGA XC7A50T-2CSG325C</text>
<text x="103.7" y="144.9">470nF</text>
<text x="114.2" y="160.4">U1F</text>
<text x="73.2" y="167.8">C65</text>
<text x="85.9" y="167.8">C66</text>
<text x="98.6" y="167.8">C67</text>
<text x="201.5" y="164">FB3</text>
<text x="253.9" y="165.5">IC FPGA XC7A50T-2CSG325C</text>
<text x="73.2" y="170.3">4.7uF</text>
<text x="85.9" y="170.3">100nF</text>
<text x="98.6" y="170.3">100nF</text>
<text x="164.7" y="170.3">C68</text>
<text x="164.7" y="172.8">100nF</text>
<text x="177.4" y="170.3">C69</text>
<text x="177.4" y="172.8">100nF</text>
<text x="190.1" y="170.3">C70</text>
<text x="190.1" y="172.8">4.7uF</text>
<text x="201.5" y="169.5">120@100MHZ</text>
<text x="114.2" y="178.2">IC FPGA XC7A50T-2CSG325C</text>
</g>
</g></defs>
<path d="M2.4 8.5h292.1v193h-292.1z" fill-rule="evenodd" fill="#fffcf8"/>
<path d="M2.4 8.5h292.1v193h-292.1z" fill="none" stroke="#000" stroke-width=".21"/>
<path d="M7.5 13.6h281.9v182.9h-281.9z" fill-rule="evenodd" fill="#fffcf8"/>
<g fill="none" stroke="#000" stroke-width=".21">
<path d="M2.4 8.5h5.1M7.5 13.6h281.9v182.9h-281.9zM75.4 8.5v5.1M148.5 8.5v5.1M221.5 8.5v5.1M289.4 8.5h5.1v5.1M2.4 56.8h5.1M289.4 56.8h5.1M2.4 105h5.1M289.4 105h5.1M2.4 153.3h5.1M289.4 153.3h5.1"/>
<path d="M289.4 176.1h-88.9v20.4M75.4 196.5v5M148.5 196.5v5M200.5 183.8h88.9M200.5 191.4h88.9M200.5 193.9h88.9M213.2 183.8v7.6M221.5 196.5v5M251.3 191.4v5.1M264 183.8v7.6M294.5 196.5v5"/>
</g>
<path d="M15.1 28.8v2.6h94v12.7" fill="none" stroke="#ff6e6e" stroke-width="1.3"/>
<path d="M231 28.8v2.6h-81.3v25.4M15.1 56.8v2.5h94v5.1M109.1 49.1v10.2" fill="none" stroke="#ff0" stroke-width="1.3"/>
<path d="M78.6 89.8v2.5h28v17.8M231 89.8v2.5h-78.7v43.2M213.2 163.4v2.6h-5" fill="none" stroke="#6e6eff" stroke-width="1.3"/>
<path d="M65.9 160.9v2.5h40.7v10.2" fill="none" stroke="#ff6eff" stroke-width="1.3"/>
<path d="M192.9 166h5.1M192.9 163.4v2.6h-40.6v7.6" fill="none" stroke="#6effff" stroke-width="1.3"/>
<path d="M246.3 69.5v96.5M281.8 66.9v99.1" fill="none" stroke="#00be00" stroke-width="1.3"/>
<path d="M246.3 64.4h-5.1v2.5" fill="none" stroke="#6eff6e" stroke-width="1.3"/>
<path d="M167.5 59.3v2.5h-17.8v2.6M162.4 61.8v2.6M15.1 112.6v2.6h91.5v10.1M96.4 115.2v20.3h10.2M101.5 115.2v2.5" fill="none" stroke="#fd8300" stroke-width="1.3"/>
<circle cx="152.3" cy="171.1" r=".51" fill="#000080"/>
<circle cx="152.3" cy="171.1" r=".51" fill="none" stroke="#000080" stroke-width=".21"/>
<circle cx="152.3" cy="168.5" r=".51" fill="#000080"/>
<circle cx="152.3" cy="168.5" r=".51" fill="none" stroke="#000080" stroke-width=".21"/>
<circle cx="152.3" cy="166" r=".51" fill="#000080"/>
<circle cx="152.3" cy="166" r=".51" fill="none" stroke="#000080" stroke-width=".21"/>
<circle cx="106.6" cy="171.1" r=".51" fill="#000080"/>
<circle cx="106.6" cy="171.1" r=".51" fill="none" stroke="#000080" stroke-width=".21"/>
<circle cx="106.6" cy="168.5" r=".51" fill="#000080"/>
<circle cx="106.6" cy="168.5" r=".51" fill="none" stroke="#000080" stroke-width=".21"/>
<circle cx="106.6" cy="166" r=".51" fill="#000080"/>
<circle cx="106.6" cy="166" r=".51" fill="none" stroke="#000080" stroke-width=".21"/>
<circle cx="106.6" cy="163.5" r=".51" fill="#000080"/>
<circle cx="106.6" cy="163.5" r=".51" fill="none" stroke="#000080" stroke-width=".21"/>
<path d="M114.2 160.9h30.5v15.2h-30.5z" fill-rule="evenodd" fill="#ffffb0"/>
<path d="M114.2 160.9h30.5v15.2h-30.5z" fill="none" stroke="#800000" stroke-width=".21"/>
<path d="M144.7 171.1h7.6M144.7 173.6h7.6" fill="none" stroke="#000" stroke-width=".25"/>
<circle cx="152.3" cy="171.1" r=".51" fill="#000080"/>
<circle cx="152.3" cy="171.1" r=".51" fill="none" stroke="#000080" stroke-width=".21"/>
<path d="M144.7 168.5h7.6" fill="none" stroke="#000" stroke-width=".25"/>
<circle cx="152.3" cy="168.5" r=".51" fill="#000080"/>
<circle cx="152.3" cy="168.5" r=".51" fill="none" stroke="#000080" stroke-width=".21"/>
<path d="M144.7 166h7.6" fill="none" stroke="#000" stroke-width=".25"/>
<circle cx="152.3" cy="166" r=".51" fill="#000080"/>
<circle cx="152.3" cy="166" r=".51" fill="none" stroke="#000080" stroke-width=".21"/>
<path d="M106.6 171.1h7.6M106.6 173.6h7.6" fill="none" stroke="#000" stroke-width=".25"/>
<circle cx="106.6" cy="171.1" r=".51" fill="#000080"/>
<circle cx="106.6" cy="171.1" r=".51" fill="none" stroke="#000080" stroke-width=".21"/>
<path d="M106.6 168.5h7.6" fill="none" stroke="#000" stroke-width=".25"/>
<circle cx="106.6" cy="168.5" r=".51" fill="#000080"/>
<circle cx="106.6" cy="168.5" r=".51" fill="none" stroke="#000080" stroke-width=".21"/>
<path d="M106.6 166h7.6" fill="none" stroke="#000" stroke-width=".25"/>
<circle cx="106.6" cy="166" r=".51" fill="#000080"/>
<circle cx="106.6" cy="166" r=".51" fill="none" stroke="#000080" stroke-width=".21"/>
<path d="M106.6 163.4h7.6" fill="none" stroke="#000" stroke-width=".25"/>
<circle cx="106.6" cy="163.5" r=".51" fill="#000080"/>
<circle cx="106.6" cy="163.5" r=".51" fill="none" stroke="#000080" stroke-width=".21"/>
<circle cx="149.7" cy="61.9" r=".51" fill="#000080"/>
<circle cx="149.7" cy="61.9" r=".51" fill="none" stroke="#000080" stroke-width=".21"/>
<circle cx="149.7" cy="54.2" r=".51" fill="#000080"/>
<circle cx="149.7" cy="54.2" r=".51" fill="none" stroke="#000080" stroke-width=".21"/>
<circle cx="149.7" cy="51.7" r=".51" fill="#000080"/>
<circle cx="149.7" cy="51.7" r=".51" fill="none" stroke="#000080" stroke-width=".21"/>
<circle cx="149.7" cy="49.1" r=".51" fill="#000080"/>
<circle cx="149.7" cy="49.1" r=".51" fill="none" stroke="#000080" stroke-width=".21"/>
<circle cx="149.7" cy="46.6" r=".51" fill="#000080"/>
<circle cx="149.7" cy="46.6" r=".51" fill="none" stroke="#000080" stroke-width=".21"/>
<circle cx="149.7" cy="44.1" r=".51" fill="#000080"/>
<circle cx="149.7" cy="44.1" r=".51" fill="none" stroke="#000080" stroke-width=".21"/>
<circle cx="149.7" cy="41.5" r=".51" fill="#000080"/>
<circle cx="149.7" cy="41.5" r=".51" fill="none" stroke="#000080" stroke-width=".21"/>
<circle cx="109.1" cy="61.9" r=".51" fill="#000080"/>
<circle cx="109.1" cy="61.9" r=".51" fill="none" stroke="#000080" stroke-width=".21"/>
<circle cx="109.1" cy="59.3" r=".51" fill="#000080"/>
<circle cx="109.1" cy="59.3" r=".51" fill="none" stroke="#000080" stroke-width=".21"/>
<circle cx="109.1" cy="56.8" r=".51" fill="#000080"/>
<circle cx="109.1" cy="56.8" r=".51" fill="none" stroke="#000080" stroke-width=".21"/>
<circle cx="109.1" cy="54.2" r=".51" fill="#000080"/>
<circle cx="109.1" cy="54.2" r=".51" fill="none" stroke="#000080" stroke-width=".21"/>
<circle cx="109.1" cy="51.7" r=".51" fill="#000080"/>
<circle cx="109.1" cy="51.7" r=".51" fill="none" stroke="#000080" stroke-width=".21"/>
<circle cx="109.1" cy="41.5" r=".51" fill="#000080"/>
<circle cx="109.1" cy="41.5" r=".51" fill="none" stroke="#000080" stroke-width=".21"/>
<circle cx="109.1" cy="39" r=".51" fill="#000080"/>
<circle cx="109.1" cy="39" r=".51" fill="none" stroke="#000080" stroke-width=".21"/>
<circle cx="109.1" cy="36.4" r=".51" fill="#000080"/>
<circle cx="109.1" cy="36.4" r=".51" fill="none" stroke="#000080" stroke-width=".21"/>
<circle cx="109.1" cy="33.9" r=".51" fill="#000080"/>
<circle cx="109.1" cy="33.9" r=".51" fill="none" stroke="#000080" stroke-width=".21"/>
<circle cx="109.1" cy="31.4" r=".51" fill="#000080"/>
<circle cx="109.1" cy="31.4" r=".51" fill="none" stroke="#000080" stroke-width=".21"/>
<path d="M116.7 28.8h25.4v38.1h-25.4z" fill-rule="evenodd" fill="#ffffb0"/>
<path d="M116.7 28.8h25.4v38.1h-25.4z" fill="none" stroke="#800000" stroke-width=".21"/>
<path d="M142.1 64.4h7.6M142.1 61.8h7.6" fill="none" stroke="#000" stroke-width=".25"/>
<circle cx="149.7" cy="61.9" r=".51" fill="#000080"/>
<circle cx="149.7" cy="61.9" r=".51" fill="none" stroke="#000080" stroke-width=".21"/>
<path d="M142.1 56.8h7.6M142.1 54.2h7.6" fill="none" stroke="#000" stroke-width=".25"/>
<circle cx="149.7" cy="54.2" r=".51" fill="#000080"/>
<circle cx="149.7" cy="54.2" r=".51" fill="none" stroke="#000080" stroke-width=".21"/>
<path d="M142.1 51.7h7.6" fill="none" stroke="#000" stroke-width=".25"/>
<circle cx="149.7" cy="51.7" r=".51" fill="#000080"/>
<circle cx="149.7" cy="51.7" r=".51" fill="none" stroke="#000080" stroke-width=".21"/>
<path d="M142.1 49.1h7.6" fill="none" stroke="#000" stroke-width=".25"/>
<circle cx="149.7" cy="49.1" r=".51" fill="#000080"/>
<circle cx="149.7" cy="49.1" r=".51" fill="none" stroke="#000080" stroke-width=".21"/>
<path d="M142.1 46.6h7.6" fill="none" stroke="#000" stroke-width=".25"/>
<circle cx="149.7" cy="46.6" r=".51" fill="#000080"/>
<circle cx="149.7" cy="46.6" r=".51" fill="none" stroke="#000080" stroke-width=".21"/>
<path d="M142.1 44.1h7.6" fill="none" stroke="#000" stroke-width=".25"/>
<circle cx="149.7" cy="44.1" r=".51" fill="#000080"/>
<circle cx="149.7" cy="44.1" r=".51" fill="none" stroke="#000080" stroke-width=".21"/>
<path d="M142.1 41.5h7.6" fill="none" stroke="#000" stroke-width=".25"/>
<circle cx="149.7" cy="41.5" r=".51" fill="#000080"/>
<circle cx="149.7" cy="41.5" r=".51" fill="none" stroke="#000080" stroke-width=".21"/>
<path d="M109.1 64.4h7.6M109.1 61.8h7.6" fill="none" stroke="#000" stroke-width=".25"/>
<circle cx="109.1" cy="61.9" r=".51" fill="#000080"/>
<circle cx="109.1" cy="61.9" r=".51" fill="none" stroke="#000080" stroke-width=".21"/>
<path d="M109.1 59.3h7.6" fill="none" stroke="#000" stroke-width=".25"/>
<circle cx="109.1" cy="59.3" r=".51" fill="#000080"/>
<circle cx="109.1" cy="59.3" r=".51" fill="none" stroke="#000080" stroke-width=".21"/>
<path d="M109.1 56.8h7.6" fill="none" stroke="#000" stroke-width=".25"/>
<circle cx="109.1" cy="56.8" r=".51" fill="#000080"/>
<circle cx="109.1" cy="56.8" r=".51" fill="none" stroke="#000080" stroke-width=".21"/>
<path d="M109.1 54.2h7.6" fill="none" stroke="#000" stroke-width=".25"/>
<circle cx="109.1" cy="54.2" r=".51" fill="#000080"/>
<circle cx="109.1" cy="54.2" r=".51" fill="none" stroke="#000080" stroke-width=".21"/>
<path d="M109.1 51.7h7.6" fill="none" stroke="#000" stroke-width=".25"/>
<circle cx="109.1" cy="51.7" r=".51" fill="#000080"/>
<circle cx="109.1" cy="51.7" r=".51" fill="none" stroke="#000080" stroke-width=".21"/>
<path d="M109.1 49.1h7.6M109.1 44.1h7.6M109.1 41.5h7.6" fill="none" stroke="#000" stroke-width=".25"/>
<circle cx="109.1" cy="41.5" r=".51" fill="#000080"/>
<circle cx="109.1" cy="41.5" r=".51" fill="none" stroke="#000080" stroke-width=".21"/>
<path d="M109.1 39h7.6" fill="none" stroke="#000" stroke-width=".25"/>
<circle cx="109.1" cy="39" r=".51" fill="#000080"/>
<circle cx="109.1" cy="39" r=".51" fill="none" stroke="#000080" stroke-width=".21"/>
<path d="M109.1 36.4h7.6" fill="none" stroke="#000" stroke-width=".25"/>
<circle cx="109.1" cy="36.4" r=".51" fill="#000080"/>
<circle cx="109.1" cy="36.4" r=".51" fill="none" stroke="#000080" stroke-width=".21"/>
<path d="M109.1 33.9h7.6" fill="none" stroke="#000" stroke-width=".25"/>
<circle cx="109.1" cy="33.9" r=".51" fill="#000080"/>
<circle cx="109.1" cy="33.9" r=".51" fill="none" stroke="#000080" stroke-width=".21"/>
<path d="M109.1 31.4h7.6" fill="none" stroke="#000" stroke-width=".25"/>
<circle cx="109.1" cy="31.4" r=".51" fill="#000080"/>
<circle cx="109.1" cy="31.4" r=".51" fill="none" stroke="#000080" stroke-width=".21"/>
<circle cx="106.6" cy="122.8" r=".51" fill="#000080"/>
<circle cx="106.6" cy="122.8" r=".51" fill="none" stroke="#000080" stroke-width=".21"/>
<circle cx="106.6" cy="120.3" r=".51" fill="#000080"/>
<circle cx="106.6" cy="120.3" r=".51" fill="none" stroke="#000080" stroke-width=".21"/>
<circle cx="106.6" cy="117.7" r=".51" fill="#000080"/>
<circle cx="106.6" cy="117.7" r=".51" fill="none" stroke="#000080" stroke-width=".21"/>
<circle cx="106.6" cy="115.2" r=".51" fill="#000080"/>
<circle cx="106.6" cy="115.2" r=".51" fill="none" stroke="#000080" stroke-width=".21"/>
<circle cx="152.3" cy="133" r=".51" fill="#000080"/>
<circle cx="152.3" cy="133" r=".51" fill="none" stroke="#000080" stroke-width=".21"/>
<circle cx="152.3" cy="130.4" r=".51" fill="#000080"/>
<circle cx="152.3" cy="130.4" r=".51" fill="none" stroke="#000080" stroke-width=".21"/>
<circle cx="152.3" cy="127.9" r=".51" fill="#000080"/>
<circle cx="152.3" cy="127.9" r=".51" fill="none" stroke="#000080" stroke-width=".21"/>
<circle cx="152.3" cy="125.4" r=".51" fill="#000080"/>
<circle cx="152.3" cy="125.4" r=".51" fill="none" stroke="#000080" stroke-width=".21"/>
<circle cx="152.3" cy="122.8" r=".51" fill="#000080"/>
<circle cx="152.3" cy="122.8" r=".51" fill="none" stroke="#000080" stroke-width=".21"/>
<circle cx="152.3" cy="120.3" r=".51" fill="#000080"/>
<circle cx="152.3" cy="120.3" r=".51" fill="none" stroke="#000080" stroke-width=".21"/>
<circle cx="152.3" cy="117.7" r=".51" fill="#000080"/>
<circle cx="152.3" cy="117.7" r=".51" fill="none" stroke="#000080" stroke-width=".21"/>
<circle cx="152.3" cy="115.2" r=".51" fill="#000080"/>
<circle cx="152.3" cy="115.2" r=".51" fill="none" stroke="#000080" stroke-width=".21"/>
<circle cx="152.3" cy="112.7" r=".51" fill="#000080"/>
<circle cx="152.3" cy="112.7" r=".51" fill="none" stroke="#000080" stroke-width=".21"/>
<circle cx="152.3" cy="110.1" r=".51" fill="#000080"/>
<circle cx="152.3" cy="110.1" r=".51" fill="none" stroke="#000080" stroke-width=".21"/>
<circle cx="152.3" cy="107.6" r=".51" fill="#000080"/>
<circle cx="152.3" cy="107.6" r=".51" fill="none" stroke="#000080" stroke-width=".21"/>
<circle cx="152.3" cy="105" r=".51" fill="#000080"/>
<circle cx="152.3" cy="105" r=".51" fill="none" stroke="#000080" stroke-width=".21"/>
<circle cx="152.3" cy="102.5" r=".51" fill="#000080"/>
<circle cx="152.3" cy="102.5" r=".51" fill="none" stroke="#000080" stroke-width=".21"/>
<circle cx="152.3" cy="100" r=".51" fill="#000080"/>
<circle cx="152.3" cy="100" r=".51" fill="none" stroke="#000080" stroke-width=".21"/>
<circle cx="152.3" cy="97.4" r=".51" fill="#000080"/>
<circle cx="152.3" cy="97.4" r=".51" fill="none" stroke="#000080" stroke-width=".21"/>
<circle cx="152.3" cy="94.9" r=".51" fill="#000080"/>
<circle cx="152.3" cy="94.9" r=".51" fill="none" stroke="#000080" stroke-width=".21"/>
<circle cx="152.3" cy="92.3" r=".51" fill="#000080"/>
<circle cx="152.3" cy="92.3" r=".51" fill="none" stroke="#000080" stroke-width=".21"/>
<circle cx="106.6" cy="107.6" r=".51" fill="#000080"/>
<circle cx="106.6" cy="107.6" r=".51" fill="none" stroke="#000080" stroke-width=".21"/>
<circle cx="106.6" cy="105" r=".51" fill="#000080"/>
<circle cx="106.6" cy="105" r=".51" fill="none" stroke="#000080" stroke-width=".21"/>
<path d="M114.2 89.8h30.5v48.2h-30.5z" fill-rule="evenodd" fill="#ffffb0"/>
<path d="M114.2 89.8h30.5v48.2h-30.5z" fill="none" stroke="#800000" stroke-width=".21"/>
<path d="M106.6 125.3h7.6M106.6 122.8h7.6" fill="none" stroke="#000" stroke-width=".25"/>
<circle cx="106.6" cy="122.8" r=".51" fill="#000080"/>
<circle cx="106.6" cy="122.8" r=".51" fill="none" stroke="#000080" stroke-width=".21"/>
<path d="M106.6 120.3h7.6" fill="none" stroke="#000" stroke-width=".25"/>
<circle cx="106.6" cy="120.3" r=".51" fill="#000080"/>
<circle cx="106.6" cy="120.3" r=".51" fill="none" stroke="#000080" stroke-width=".21"/>
<path d="M106.6 117.7h7.6" fill="none" stroke="#000" stroke-width=".25"/>
<circle cx="106.6" cy="117.7" r=".51" fill="#000080"/>
<circle cx="106.6" cy="117.7" r=".51" fill="none" stroke="#000080" stroke-width=".21"/>
<path d="M106.6 115.2h7.6" fill="none" stroke="#000" stroke-width=".25"/>
<circle cx="106.6" cy="115.2" r=".51" fill="#000080"/>
<circle cx="106.6" cy="115.2" r=".51" fill="none" stroke="#000080" stroke-width=".21"/>
<path d="M144.7 135.5h7.6M144.7 133h7.6" fill="none" stroke="#000" stroke-width=".25"/>
<circle cx="152.3" cy="133" r=".51" fill="#000080"/>
<circle cx="152.3" cy="133" r=".51" fill="none" stroke="#000080" stroke-width=".21"/>
<path d="M144.7 130.4h7.6" fill="none" stroke="#000" stroke-width=".25"/>
<circle cx="152.3" cy="130.4" r=".51" fill="#000080"/>
<circle cx="152.3" cy="130.4" r=".51" fill="none" stroke="#000080" stroke-width=".21"/>
<path d="M144.7 127.9h7.6" fill="none" stroke="#000" stroke-width=".25"/>
<circle cx="152.3" cy="127.9" r=".51" fill="#000080"/>
<circle cx="152.3" cy="127.9" r=".51" fill="none" stroke="#000080" stroke-width=".21"/>
<path d="M144.7 125.3h7.6" fill="none" stroke="#000" stroke-width=".25"/>
<circle cx="152.3" cy="125.4" r=".51" fill="#000080"/>
<circle cx="152.3" cy="125.4" r=".51" fill="none" stroke="#000080" stroke-width=".21"/>
<path d="M144.7 122.8h7.6" fill="none" stroke="#000" stroke-width=".25"/>
<circle cx="152.3" cy="122.8" r=".51" fill="#000080"/>
<circle cx="152.3" cy="122.8" r=".51" fill="none" stroke="#000080" stroke-width=".21"/>
<path d="M144.7 120.3h7.6" fill="none" stroke="#000" stroke-width=".25"/>
<circle cx="152.3" cy="120.3" r=".51" fill="#000080"/>
<circle cx="152.3" cy="120.3" r=".51" fill="none" stroke="#000080" stroke-width=".21"/>
<path d="M144.7 117.7h7.6" fill="none" stroke="#000" stroke-width=".25"/>
<circle cx="152.3" cy="117.7" r=".51" fill="#000080"/>
<circle cx="152.3" cy="117.7" r=".51" fill="none" stroke="#000080" stroke-width=".21"/>
<path d="M144.7 115.2h7.6" fill="none" stroke="#000" stroke-width=".25"/>
<circle cx="152.3" cy="115.2" r=".51" fill="#000080"/>
<circle cx="152.3" cy="115.2" r=".51" fill="none" stroke="#000080" stroke-width=".21"/>
<path d="M144.7 112.6h7.6" fill="none" stroke="#000" stroke-width=".25"/>
<circle cx="152.3" cy="112.7" r=".51" fill="#000080"/>
<circle cx="152.3" cy="112.7" r=".51" fill="none" stroke="#000080" stroke-width=".21"/>
<path d="M144.7 110.1h7.6" fill="none" stroke="#000" stroke-width=".25"/>
<circle cx="152.3" cy="110.1" r=".51" fill="#000080"/>
<circle cx="152.3" cy="110.1" r=".51" fill="none" stroke="#000080" stroke-width=".21"/>
<path d="M144.7 107.6h7.6" fill="none" stroke="#000" stroke-width=".25"/>
<circle cx="152.3" cy="107.6" r=".51" fill="#000080"/>
<circle cx="152.3" cy="107.6" r=".51" fill="none" stroke="#000080" stroke-width=".21"/>
<path d="M144.7 105h7.6" fill="none" stroke="#000" stroke-width=".25"/>
<circle cx="152.3" cy="105" r=".51" fill="#000080"/>
<circle cx="152.3" cy="105" r=".51" fill="none" stroke="#000080" stroke-width=".21"/>
<path d="M144.7 102.5h7.6" fill="none" stroke="#000" stroke-width=".25"/>
<circle cx="152.3" cy="102.5" r=".51" fill="#000080"/>
<circle cx="152.3" cy="102.5" r=".51" fill="none" stroke="#000080" stroke-width=".21"/>
<path d="M144.7 99.9h7.6" fill="none" stroke="#000" stroke-width=".25"/>
<circle cx="152.3" cy="100" r=".51" fill="#000080"/>
<circle cx="152.3" cy="100" r=".51" fill="none" stroke="#000080" stroke-width=".21"/>
<path d="M144.7 97.4h7.6" fill="none" stroke="#000" stroke-width=".25"/>
<circle cx="152.3" cy="97.4" r=".51" fill="#000080"/>
<circle cx="152.3" cy="97.4" r=".51" fill="none" stroke="#000080" stroke-width=".21"/>
<path d="M144.7 94.9h7.6" fill="none" stroke="#000" stroke-width=".25"/>
<circle cx="152.3" cy="94.9" r=".51" fill="#000080"/>
<circle cx="152.3" cy="94.9" r=".51" fill="none" stroke="#000080" stroke-width=".21"/>
<path d="M144.7 92.3h7.6" fill="none" stroke="#000" stroke-width=".25"/>
<circle cx="152.3" cy="92.3" r=".51" fill="#000080"/>
<circle cx="152.3" cy="92.3" r=".51" fill="none" stroke="#000080" stroke-width=".21"/>
<path d="M106.6 110.1h7.6M106.6 107.6h7.6" fill="none" stroke="#000" stroke-width=".25"/>
<circle cx="106.6" cy="107.6" r=".51" fill="#000080"/>
<circle cx="106.6" cy="107.6" r=".51" fill="none" stroke="#000080" stroke-width=".21"/>
<path d="M106.6 105h7.6" fill="none" stroke="#000" stroke-width=".25"/>
<circle cx="106.6" cy="105" r=".51" fill="#000080"/>
<circle cx="106.6" cy="105" r=".51" fill="none" stroke="#000080" stroke-width=".21"/>
<path d="M101.5 117.7v4.5M101.5 123.4v4.5M106.6 130.4h7.6M106.6 135.5h7.6" fill="none" stroke="#000" stroke-width=".25"/>
<g fill="none" stroke="#800000" stroke-width=".25">
<path d="M13.8 26.3h2.6M15.1 26.3v2.5M229.8 26.3h2.5M231 26.3v2.5M13.8 54.2h2.6M15.1 54.2v2.6M166.2 56.8h2.6M167.5 56.8v2.5M77.3 87.2h2.6M78.6 87.2v2.6M229.8 87.2h2.5M231 87.2v2.6"/>
<path d="M13.8 110.1h2.6M15.1 110.1v2.5M64.6 158.4h2.6M65.9 158.4v2.5M191.7 160.9h2.5M192.9 160.9v2.5"/>
</g>
<path d="M100.2 121.5l2.5 1.3v1.3l-2.5-1.3z" fill="none" stroke="#00f" stroke-width=".25"/>
<circle cx="281.8" cy="160.9" r=".51" fill="#000080"/>
<circle cx="281.8" cy="160.9" r=".51" fill="none" stroke="#000080" stroke-width=".21"/>
<circle cx="281.8" cy="158.4" r=".51" fill="#000080"/>
<circle cx="281.8" cy="158.4" r=".51" fill="none" stroke="#000080" stroke-width=".21"/>
<circle cx="281.8" cy="155.8" r=".51" fill="#000080"/>
<circle cx="281.8" cy="155.8" r=".51" fill="none" stroke="#000080" stroke-width=".21"/>
<circle cx="281.8" cy="153.3" r=".51" fill="#000080"/>
<circle cx="281.8" cy="153.3" r=".51" fill="none" stroke="#000080" stroke-width=".21"/>
<circle cx="281.8" cy="150.8" r=".51" fill="#000080"/>
<circle cx="281.8" cy="150.8" r=".51" fill="none" stroke="#000080" stroke-width=".21"/>
<circle cx="281.8" cy="148.2" r=".51" fill="#000080"/>
<circle cx="281.8" cy="148.2" r=".51" fill="none" stroke="#000080" stroke-width=".21"/>
<circle cx="281.8" cy="145.7" r=".51" fill="#000080"/>
<circle cx="281.8" cy="145.7" r=".51" fill="none" stroke="#000080" stroke-width=".21"/>
<circle cx="281.8" cy="143.1" r=".51" fill="#000080"/>
<circle cx="281.8" cy="143.1" r=".51" fill="none" stroke="#000080" stroke-width=".21"/>
<circle cx="281.8" cy="140.6" r=".51" fill="#000080"/>
<circle cx="281.8" cy="140.6" r=".51" fill="none" stroke="#000080" stroke-width=".21"/>
<circle cx="281.8" cy="138.1" r=".51" fill="#000080"/>
<circle cx="281.8" cy="138.1" r=".51" fill="none" stroke="#000080" stroke-width=".21"/>
<circle cx="281.8" cy="135.5" r=".51" fill="#000080"/>
<circle cx="281.8" cy="135.5" r=".51" fill="none" stroke="#000080" stroke-width=".21"/>
<circle cx="281.8" cy="133" r=".51" fill="#000080"/>
<circle cx="281.8" cy="133" r=".51" fill="none" stroke="#000080" stroke-width=".21"/>
<circle cx="281.8" cy="130.4" r=".51" fill="#000080"/>
<circle cx="281.8" cy="130.4" r=".51" fill="none" stroke="#000080" stroke-width=".21"/>
<circle cx="281.8" cy="127.9" r=".51" fill="#000080"/>
<circle cx="281.8" cy="127.9" r=".51" fill="none" stroke="#000080" stroke-width=".21"/>
<circle cx="281.8" cy="125.4" r=".51" fill="#000080"/>
<circle cx="281.8" cy="125.4" r=".51" fill="none" stroke="#000080" stroke-width=".21"/>
<circle cx="281.8" cy="122.8" r=".51" fill="#000080"/>
<circle cx="281.8" cy="122.8" r=".51" fill="none" stroke="#000080" stroke-width=".21"/>
<circle cx="281.8" cy="120.3" r=".51" fill="#000080"/>
<circle cx="281.8" cy="120.3" r=".51" fill="none" stroke="#000080" stroke-width=".21"/>
<circle cx="281.8" cy="117.7" r=".51" fill="#000080"/>
<circle cx="281.8" cy="117.7" r=".51" fill="none" stroke="#000080" stroke-width=".21"/>
<circle cx="281.8" cy="115.2" r=".51" fill="#000080"/>
<circle cx="281.8" cy="115.2" r=".51" fill="none" stroke="#000080" stroke-width=".21"/>
<circle cx="281.8" cy="112.7" r=".51" fill="#000080"/>
<circle cx="281.8" cy="112.7" r=".51" fill="none" stroke="#000080" stroke-width=".21"/>
<circle cx="281.8" cy="110.1" r=".51" fill="#000080"/>
<circle cx="281.8" cy="110.1" r=".51" fill="none" stroke="#000080" stroke-width=".21"/>
<circle cx="281.8" cy="107.6" r=".51" fill="#000080"/>
<circle cx="281.8" cy="107.6" r=".51" fill="none" stroke="#000080" stroke-width=".21"/>
<circle cx="281.8" cy="105" r=".51" fill="#000080"/>
<circle cx="281.8" cy="105" r=".51" fill="none" stroke="#000080" stroke-width=".21"/>
<circle cx="281.8" cy="102.5" r=".51" fill="#000080"/>
<circle cx="281.8" cy="102.5" r=".51" fill="none" stroke="#000080" stroke-width=".21"/>
<circle cx="281.8" cy="100" r=".51" fill="#000080"/>
<circle cx="281.8" cy="100" r=".51" fill="none" stroke="#000080" stroke-width=".21"/>
<circle cx="281.8" cy="97.4" r=".51" fill="#000080"/>
<circle cx="281.8" cy="97.4" r=".51" fill="none" stroke="#000080" stroke-width=".21"/>
<circle cx="281.8" cy="94.9" r=".51" fill="#000080"/>
<circle cx="281.8" cy="94.9" r=".51" fill="none" stroke="#000080" stroke-width=".21"/>
<circle cx="281.8" cy="92.3" r=".51" fill="#000080"/>
<circle cx="281.8" cy="92.3" r=".51" fill="none" stroke="#000080" stroke-width=".21"/>
<circle cx="281.8" cy="89.8" r=".51" fill="#000080"/>
<circle cx="281.8" cy="89.8" r=".51" fill="none" stroke="#000080" stroke-width=".21"/>
<circle cx="281.8" cy="87.3" r=".51" fill="#000080"/>
<circle cx="281.8" cy="87.3" r=".51" fill="none" stroke="#000080" stroke-width=".21"/>
<circle cx="281.8" cy="84.7" r=".51" fill="#000080"/>
<circle cx="281.8" cy="84.7" r=".51" fill="none" stroke="#000080" stroke-width=".21"/>
<circle cx="281.8" cy="82.2" r=".51" fill="#000080"/>
<circle cx="281.8" cy="82.2" r=".51" fill="none" stroke="#000080" stroke-width=".21"/>
<circle cx="281.8" cy="79.6" r=".51" fill="#000080"/>
<circle cx="281.8" cy="79.6" r=".51" fill="none" stroke="#000080" stroke-width=".21"/>
<circle cx="281.8" cy="77.1" r=".51" fill="#000080"/>
<circle cx="281.8" cy="77.1" r=".51" fill="none" stroke="#000080" stroke-width=".21"/>
<circle cx="281.8" cy="74.6" r=".51" fill="#000080"/>
<circle cx="281.8" cy="74.6" r=".51" fill="none" stroke="#000080" stroke-width=".21"/>
<circle cx="281.8" cy="72" r=".51" fill="#000080"/>
<circle cx="281.8" cy="72" r=".51" fill="none" stroke="#000080" stroke-width=".21"/>
<circle cx="281.8" cy="69.5" r=".51" fill="#000080"/>
<circle cx="281.8" cy="69.5" r=".51" fill="none" stroke="#000080" stroke-width=".21"/>
<circle cx="246.3" cy="160.9" r=".51" fill="#000080"/>
<circle cx="246.3" cy="160.9" r=".51" fill="none" stroke="#000080" stroke-width=".21"/>
<circle cx="246.3" cy="158.4" r=".51" fill="#000080"/>
<circle cx="246.3" cy="158.4" r=".51" fill="none" stroke="#000080" stroke-width=".21"/>
<circle cx="246.3" cy="155.8" r=".51" fill="#000080"/>
<circle cx="246.3" cy="155.8" r=".51" fill="none" stroke="#000080" stroke-width=".21"/>
<circle cx="246.3" cy="153.3" r=".51" fill="#000080"/>
<circle cx="246.3" cy="153.3" r=".51" fill="none" stroke="#000080" stroke-width=".21"/>
<circle cx="246.3" cy="150.8" r=".51" fill="#000080"/>
<circle cx="246.3" cy="150.8" r=".51" fill="none" stroke="#000080" stroke-width=".21"/>
<circle cx="246.3" cy="148.2" r=".51" fill="#000080"/>
<circle cx="246.3" cy="148.2" r=".51" fill="none" stroke="#000080" stroke-width=".21"/>
<circle cx="246.3" cy="145.7" r=".51" fill="#000080"/>
<circle cx="246.3" cy="145.7" r=".51" fill="none" stroke="#000080" stroke-width=".21"/>
<circle cx="246.3" cy="143.1" r=".51" fill="#000080"/>
<circle cx="246.3" cy="143.1" r=".51" fill="none" stroke="#000080" stroke-width=".21"/>
<circle cx="246.3" cy="140.6" r=".51" fill="#000080"/>
<circle cx="246.3" cy="140.6" r=".51" fill="none" stroke="#000080" stroke-width=".21"/>
<circle cx="246.3" cy="138.1" r=".51" fill="#000080"/>
<circle cx="246.3" cy="138.1" r=".51" fill="none" stroke="#000080" stroke-width=".21"/>
<circle cx="246.3" cy="135.5" r=".51" fill="#000080"/>
<circle cx="246.3" cy="135.5" r=".51" fill="none" stroke="#000080" stroke-width=".21"/>
<circle cx="246.3" cy="133" r=".51" fill="#000080"/>
<circle cx="246.3" cy="133" r=".51" fill="none" stroke="#000080" stroke-width=".21"/>
<circle cx="246.3" cy="130.4" r=".51" fill="#000080"/>
<circle cx="246.3" cy="130.4" r=".51" fill="none" stroke="#000080" stroke-width=".21"/>
<circle cx="246.3" cy="127.9" r=".51" fill="#000080"/>
<circle cx="246.3" cy="127.9" r=".51" fill="none" stroke="#000080" stroke-width=".21"/>
<circle cx="246.3" cy="125.4" r=".51" fill="#000080"/>
<circle cx="246.3" cy="125.4" r=".51" fill="none" stroke="#000080" stroke-width=".21"/>
<circle cx="246.3" cy="122.8" r=".51" fill="#000080"/>
<circle cx="246.3" cy="122.8" r=".51" fill="none" stroke="#000080" stroke-width=".21"/>
<circle cx="246.3" cy="120.3" r=".51" fill="#000080"/>
<circle cx="246.3" cy="120.3" r=".51" fill="none" stroke="#000080" stroke-width=".21"/>
<circle cx="246.3" cy="117.7" r=".51" fill="#000080"/>
<circle cx="246.3" cy="117.7" r=".51" fill="none" stroke="#000080" stroke-width=".21"/>
<circle cx="246.3" cy="115.2" r=".51" fill="#000080"/>
<circle cx="246.3" cy="115.2" r=".51" fill="none" stroke="#000080" stroke-width=".21"/>
<circle cx="246.3" cy="112.7" r=".51" fill="#000080"/>
<circle cx="246.3" cy="112.7" r=".51" fill="none" stroke="#000080" stroke-width=".21"/>
<circle cx="246.3" cy="110.1" r=".51" fill="#000080"/>
<circle cx="246.3" cy="110.1" r=".51" fill="none" stroke="#000080" stroke-width=".21"/>
<circle cx="246.3" cy="107.6" r=".51" fill="#000080"/>
<circle cx="246.3" cy="107.6" r=".51" fill="none" stroke="#000080" stroke-width=".21"/>
<circle cx="246.3" cy="105" r=".51" fill="#000080"/>
<circle cx="246.3" cy="105" r=".51" fill="none" stroke="#000080" stroke-width=".21"/>
<circle cx="246.3" cy="102.5" r=".51" fill="#000080"/>
<circle cx="246.3" cy="102.5" r=".51" fill="none" stroke="#000080" stroke-width=".21"/>
<circle cx="246.3" cy="100" r=".51" fill="#000080"/>
<circle cx="246.3" cy="100" r=".51" fill="none" stroke="#000080" stroke-width=".21"/>
<circle cx="246.3" cy="97.4" r=".51" fill="#000080"/>
<circle cx="246.3" cy="97.4" r=".51" fill="none" stroke="#000080" stroke-width=".21"/>
<circle cx="246.3" cy="94.9" r=".51" fill="#000080"/>
<circle cx="246.3" cy="94.9" r=".51" fill="none" stroke="#000080" stroke-width=".21"/>
<circle cx="246.3" cy="92.3" r=".51" fill="#000080"/>
<circle cx="246.3" cy="92.3" r=".51" fill="none" stroke="#000080" stroke-width=".21"/>
<circle cx="246.3" cy="89.8" r=".51" fill="#000080"/>
<circle cx="246.3" cy="89.8" r=".51" fill="none" stroke="#000080" stroke-width=".21"/>
<circle cx="246.3" cy="87.3" r=".51" fill="#000080"/>
<circle cx="246.3" cy="87.3" r=".51" fill="none" stroke="#000080" stroke-width=".21"/>
<circle cx="246.3" cy="84.7" r=".51" fill="#000080"/>
<circle cx="246.3" cy="84.7" r=".51" fill="none" stroke="#000080" stroke-width=".21"/>
<circle cx="246.3" cy="82.2" r=".51" fill="#000080"/>
<circle cx="246.3" cy="82.2" r=".51" fill="none" stroke="#000080" stroke-width=".21"/>
<circle cx="246.3" cy="79.6" r=".51" fill="#000080"/>
<circle cx="246.3" cy="79.6" r=".51" fill="none" stroke="#000080" stroke-width=".21"/>
<circle cx="246.3" cy="77.1" r=".51" fill="#000080"/>
<circle cx="246.3" cy="77.1" r=".51" fill="none" stroke="#000080" stroke-width=".21"/>
<circle cx="246.3" cy="74.6" r=".51" fill="#000080"/>
<circle cx="246.3" cy="74.6" r=".51" fill="none" stroke="#000080" stroke-width=".21"/>
<circle cx="246.3" cy="72" r=".51" fill="#000080"/>
<circle cx="246.3" cy="72" r=".51" fill="none" stroke="#000080" stroke-width=".21"/>
<path d="M253.9 61.8h20.3v101.6h-20.3z" fill-rule="evenodd" fill="#ffffb0"/>
<path d="M253.9 61.8h20.3v101.6h-20.3z" fill="none" stroke="#800000" stroke-width=".21"/>
<path d="M274.2 160.9h7.6" fill="none" stroke="#000" stroke-width=".25"/>
<circle cx="281.8" cy="160.9" r=".51" fill="#000080"/>
<circle cx="281.8" cy="160.9" r=".51" fill="none" stroke="#000080" stroke-width=".21"/>
<path d="M274.2 158.4h7.6" fill="none" stroke="#000" stroke-width=".25"/>
<circle cx="281.8" cy="158.4" r=".51" fill="#000080"/>
<circle cx="281.8" cy="158.4" r=".51" fill="none" stroke="#000080" stroke-width=".21"/>
<path d="M274.2 155.8h7.6" fill="none" stroke="#000" stroke-width=".25"/>
<circle cx="281.8" cy="155.8" r=".51" fill="#000080"/>
<circle cx="281.8" cy="155.8" r=".51" fill="none" stroke="#000080" stroke-width=".21"/>
<path d="M274.2 153.3h7.6" fill="none" stroke="#000" stroke-width=".25"/>
<circle cx="281.8" cy="153.3" r=".51" fill="#000080"/>
<circle cx="281.8" cy="153.3" r=".51" fill="none" stroke="#000080" stroke-width=".21"/>
<path d="M274.2 150.7h7.6" fill="none" stroke="#000" stroke-width=".25"/>
<circle cx="281.8" cy="150.8" r=".51" fill="#000080"/>
<circle cx="281.8" cy="150.8" r=".51" fill="none" stroke="#000080" stroke-width=".21"/>
<path d="M274.2 148.2h7.6" fill="none" stroke="#000" stroke-width=".25"/>
<circle cx="281.8" cy="148.2" r=".51" fill="#000080"/>
<circle cx="281.8" cy="148.2" r=".51" fill="none" stroke="#000080" stroke-width=".21"/>
<path d="M274.2 145.7h7.6" fill="none" stroke="#000" stroke-width=".25"/>
<circle cx="281.8" cy="145.7" r=".51" fill="#000080"/>
<circle cx="281.8" cy="145.7" r=".51" fill="none" stroke="#000080" stroke-width=".21"/>
<path d="M274.2 143.1h7.6" fill="none" stroke="#000" stroke-width=".25"/>
<circle cx="281.8" cy="143.1" r=".51" fill="#000080"/>
<circle cx="281.8" cy="143.1" r=".51" fill="none" stroke="#000080" stroke-width=".21"/>
<path d="M274.2 140.6h7.6" fill="none" stroke="#000" stroke-width=".25"/>
<circle cx="281.8" cy="140.6" r=".51" fill="#000080"/>
<circle cx="281.8" cy="140.6" r=".51" fill="none" stroke="#000080" stroke-width=".21"/>
<path d="M274.2 138h7.6" fill="none" stroke="#000" stroke-width=".25"/>
<circle cx="281.8" cy="138.1" r=".51" fill="#000080"/>
<circle cx="281.8" cy="138.1" r=".51" fill="none" stroke="#000080" stroke-width=".21"/>
<path d="M274.2 135.5h7.6" fill="none" stroke="#000" stroke-width=".25"/>
<circle cx="281.8" cy="135.5" r=".51" fill="#000080"/>
<circle cx="281.8" cy="135.5" r=".51" fill="none" stroke="#000080" stroke-width=".21"/>
<path d="M274.2 133h7.6" fill="none" stroke="#000" stroke-width=".25"/>
<circle cx="281.8" cy="133" r=".51" fill="#000080"/>
<circle cx="281.8" cy="133" r=".51" fill="none" stroke="#000080" stroke-width=".21"/>
<path d="M274.2 130.4h7.6" fill="none" stroke="#000" stroke-width=".25"/>
<circle cx="281.8" cy="130.4" r=".51" fill="#000080"/>
<circle cx="281.8" cy="130.4" r=".51" fill="none" stroke="#000080" stroke-width=".21"/>
<path d="M274.2 127.9h7.6" fill="none" stroke="#000" stroke-width=".25"/>
<circle cx="281.8" cy="127.9" r=".51" fill="#000080"/>
<circle cx="281.8" cy="127.9" r=".51" fill="none" stroke="#000080" stroke-width=".21"/>
<path d="M274.2 125.3h7.6" fill="none" stroke="#000" stroke-width=".25"/>
<circle cx="281.8" cy="125.4" r=".51" fill="#000080"/>
<circle cx="281.8" cy="125.4" r=".51" fill="none" stroke="#000080" stroke-width=".21"/>
<path d="M274.2 122.8h7.6" fill="none" stroke="#000" stroke-width=".25"/>
<circle cx="281.8" cy="122.8" r=".51" fill="#000080"/>
<circle cx="281.8" cy="122.8" r=".51" fill="none" stroke="#000080" stroke-width=".21"/>
<path d="M274.2 120.3h7.6" fill="none" stroke="#000" stroke-width=".25"/>
<circle cx="281.8" cy="120.3" r=".51" fill="#000080"/>
<circle cx="281.8" cy="120.3" r=".51" fill="none" stroke="#000080" stroke-width=".21"/>
<path d="M274.2 117.7h7.6" fill="none" stroke="#000" stroke-width=".25"/>
<circle cx="281.8" cy="117.7" r=".51" fill="#000080"/>
<circle cx="281.8" cy="117.7" r=".51" fill="none" stroke="#000080" stroke-width=".21"/>
<path d="M274.2 115.2h7.6" fill="none" stroke="#000" stroke-width=".25"/>
<circle cx="281.8" cy="115.2" r=".51" fill="#000080"/>
<circle cx="281.8" cy="115.2" r=".51" fill="none" stroke="#000080" stroke-width=".21"/>
<path d="M274.2 112.6h7.6" fill="none" stroke="#000" stroke-width=".25"/>
<circle cx="281.8" cy="112.7" r=".51" fill="#000080"/>
<circle cx="281.8" cy="112.7" r=".51" fill="none" stroke="#000080" stroke-width=".21"/>
<path d="M274.2 110.1h7.6" fill="none" stroke="#000" stroke-width=".25"/>
<circle cx="281.8" cy="110.1" r=".51" fill="#000080"/>
<circle cx="281.8" cy="110.1" r=".51" fill="none" stroke="#000080" stroke-width=".21"/>
<path d="M274.2 107.6h7.6" fill="none" stroke="#000" stroke-width=".25"/>
<circle cx="281.8" cy="107.6" r=".51" fill="#000080"/>
<circle cx="281.8" cy="107.6" r=".51" fill="none" stroke="#000080" stroke-width=".21"/>
<path d="M274.2 105h7.6" fill="none" stroke="#000" stroke-width=".25"/>
<circle cx="281.8" cy="105" r=".51" fill="#000080"/>
<circle cx="281.8" cy="105" r=".51" fill="none" stroke="#000080" stroke-width=".21"/>
<path d="M274.2 102.5h7.6" fill="none" stroke="#000" stroke-width=".25"/>
<circle cx="281.8" cy="102.5" r=".51" fill="#000080"/>
<circle cx="281.8" cy="102.5" r=".51" fill="none" stroke="#000080" stroke-width=".21"/>
<path d="M274.2 99.9h7.6" fill="none" stroke="#000" stroke-width=".25"/>
<circle cx="281.8" cy="100" r=".51" fill="#000080"/>
<circle cx="281.8" cy="100" r=".51" fill="none" stroke="#000080" stroke-width=".21"/>
<path d="M274.2 97.4h7.6" fill="none" stroke="#000" stroke-width=".25"/>
<circle cx="281.8" cy="97.4" r=".51" fill="#000080"/>
<circle cx="281.8" cy="97.4" r=".51" fill="none" stroke="#000080" stroke-width=".21"/>
<path d="M274.2 94.9h7.6" fill="none" stroke="#000" stroke-width=".25"/>
<circle cx="281.8" cy="94.9" r=".51" fill="#000080"/>
<circle cx="281.8" cy="94.9" r=".51" fill="none" stroke="#000080" stroke-width=".21"/>
<path d="M274.2 92.3h7.6" fill="none" stroke="#000" stroke-width=".25"/>
<circle cx="281.8" cy="92.3" r=".51" fill="#000080"/>
<circle cx="281.8" cy="92.3" r=".51" fill="none" stroke="#000080" stroke-width=".21"/>
<path d="M274.2 89.8h7.6" fill="none" stroke="#000" stroke-width=".25"/>
<circle cx="281.8" cy="89.8" r=".51" fill="#000080"/>
<circle cx="281.8" cy="89.8" r=".51" fill="none" stroke="#000080" stroke-width=".21"/>
<path d="M274.2 87.2h7.6" fill="none" stroke="#000" stroke-width=".25"/>
<circle cx="281.8" cy="87.3" r=".51" fill="#000080"/>
<circle cx="281.8" cy="87.3" r=".51" fill="none" stroke="#000080" stroke-width=".21"/>
<path d="M274.2 84.7h7.6" fill="none" stroke="#000" stroke-width=".25"/>
<circle cx="281.8" cy="84.7" r=".51" fill="#000080"/>
<circle cx="281.8" cy="84.7" r=".51" fill="none" stroke="#000080" stroke-width=".21"/>
<path d="M274.2 82.2h7.6" fill="none" stroke="#000" stroke-width=".25"/>
<circle cx="281.8" cy="82.2" r=".51" fill="#000080"/>
<circle cx="281.8" cy="82.2" r=".51" fill="none" stroke="#000080" stroke-width=".21"/>
<path d="M274.2 79.6h7.6" fill="none" stroke="#000" stroke-width=".25"/>
<circle cx="281.8" cy="79.6" r=".51" fill="#000080"/>
<circle cx="281.8" cy="79.6" r=".51" fill="none" stroke="#000080" stroke-width=".21"/>
<path d="M274.2 77.1h7.6" fill="none" stroke="#000" stroke-width=".25"/>
<circle cx="281.8" cy="77.1" r=".51" fill="#000080"/>
<circle cx="281.8" cy="77.1" r=".51" fill="none" stroke="#000080" stroke-width=".21"/>
<path d="M274.2 74.5h7.6" fill="none" stroke="#000" stroke-width=".25"/>
<circle cx="281.8" cy="74.6" r=".51" fill="#000080"/>
<circle cx="281.8" cy="74.6" r=".51" fill="none" stroke="#000080" stroke-width=".21"/>
<path d="M274.2 72h7.6" fill="none" stroke="#000" stroke-width=".25"/>
<circle cx="281.8" cy="72" r=".51" fill="#000080"/>
<circle cx="281.8" cy="72" r=".51" fill="none" stroke="#000080" stroke-width=".21"/>
<path d="M274.2 69.5h7.6" fill="none" stroke="#000" stroke-width=".25"/>
<circle cx="281.8" cy="69.5" r=".51" fill="#000080"/>
<circle cx="281.8" cy="69.5" r=".51" fill="none" stroke="#000080" stroke-width=".21"/>
<path d="M274.2 66.9h7.6M246.3 160.9h7.6" fill="none" stroke="#000" stroke-width=".25"/>
<circle cx="246.3" cy="160.9" r=".51" fill="#000080"/>
<circle cx="246.3" cy="160.9" r=".51" fill="none" stroke="#000080" stroke-width=".21"/>
<path d="M246.3 158.4h7.6" fill="none" stroke="#000" stroke-width=".25"/>
<circle cx="246.3" cy="158.4" r=".51" fill="#000080"/>
<circle cx="246.3" cy="158.4" r=".51" fill="none" stroke="#000080" stroke-width=".21"/>
<path d="M246.3 155.8h7.6" fill="none" stroke="#000" stroke-width=".25"/>
<circle cx="246.3" cy="155.8" r=".51" fill="#000080"/>
<circle cx="246.3" cy="155.8" r=".51" fill="none" stroke="#000080" stroke-width=".21"/>
<path d="M246.3 153.3h7.6" fill="none" stroke="#000" stroke-width=".25"/>
<circle cx="246.3" cy="153.3" r=".51" fill="#000080"/>
<circle cx="246.3" cy="153.3" r=".51" fill="none" stroke="#000080" stroke-width=".21"/>
<path d="M246.3 150.7h7.6" fill="none" stroke="#000" stroke-width=".25"/>
<circle cx="246.3" cy="150.8" r=".51" fill="#000080"/>
<circle cx="246.3" cy="150.8" r=".51" fill="none" stroke="#000080" stroke-width=".21"/>
<path d="M246.3 148.2h7.6" fill="none" stroke="#000" stroke-width=".25"/>
<circle cx="246.3" cy="148.2" r=".51" fill="#000080"/>
<circle cx="246.3" cy="148.2" r=".51" fill="none" stroke="#000080" stroke-width=".21"/>
<path d="M246.3 145.7h7.6" fill="none" stroke="#000" stroke-width=".25"/>
<circle cx="246.3" cy="145.7" r=".51" fill="#000080"/>
<circle cx="246.3" cy="145.7" r=".51" fill="none" stroke="#000080" stroke-width=".21"/>
<path d="M246.3 143.1h7.6" fill="none" stroke="#000" stroke-width=".25"/>
<circle cx="246.3" cy="143.1" r=".51" fill="#000080"/>
<circle cx="246.3" cy="143.1" r=".51" fill="none" stroke="#000080" stroke-width=".21"/>
<path d="M246.3 140.6h7.6" fill="none" stroke="#000" stroke-width=".25"/>
<circle cx="246.3" cy="140.6" r=".51" fill="#000080"/>
<circle cx="246.3" cy="140.6" r=".51" fill="none" stroke="#000080" stroke-width=".21"/>
<path d="M246.3 138h7.6" fill="none" stroke="#000" stroke-width=".25"/>
<circle cx="246.3" cy="138.1" r=".51" fill="#000080"/>
<circle cx="246.3" cy="138.1" r=".51" fill="none" stroke="#000080" stroke-width=".21"/>
<path d="M246.3 135.5h7.6" fill="none" stroke="#000" stroke-width=".25"/>
<circle cx="246.3" cy="135.5" r=".51" fill="#000080"/>
<circle cx="246.3" cy="135.5" r=".51" fill="none" stroke="#000080" stroke-width=".21"/>
<path d="M246.3 133h7.6" fill="none" stroke="#000" stroke-width=".25"/>
<circle cx="246.3" cy="133" r=".51" fill="#000080"/>
<circle cx="246.3" cy="133" r=".51" fill="none" stroke="#000080" stroke-width=".21"/>
<path d="M246.3 130.4h7.6" fill="none" stroke="#000" stroke-width=".25"/>
<circle cx="246.3" cy="130.4" r=".51" fill="#000080"/>
<circle cx="246.3" cy="130.4" r=".51" fill="none" stroke="#000080" stroke-width=".21"/>
<path d="M246.3 127.9h7.6" fill="none" stroke="#000" stroke-width=".25"/>
<circle cx="246.3" cy="127.9" r=".51" fill="#000080"/>
<circle cx="246.3" cy="127.9" r=".51" fill="none" stroke="#000080" stroke-width=".21"/>
<path d="M246.3 125.3h7.6" fill="none" stroke="#000" stroke-width=".25"/>
<circle cx="246.3" cy="125.4" r=".51" fill="#000080"/>
<circle cx="246.3" cy="125.4" r=".51" fill="none" stroke="#000080" stroke-width=".21"/>
<path d="M246.3 122.8h7.6" fill="none" stroke="#000" stroke-width=".25"/>
<circle cx="246.3" cy="122.8" r=".51" fill="#000080"/>
<circle cx="246.3" cy="122.8" r=".51" fill="none" stroke="#000080" stroke-width=".21"/>
<path d="M246.3 120.3h7.6" fill="none" stroke="#000" stroke-width=".25"/>
<circle cx="246.3" cy="120.3" r=".51" fill="#000080"/>
<circle cx="246.3" cy="120.3" r=".51" fill="none" stroke="#000080" stroke-width=".21"/>
<path d="M246.3 117.7h7.6" fill="none" stroke="#000" stroke-width=".25"/>
<circle cx="246.3" cy="117.7" r=".51" fill="#000080"/>
<circle cx="246.3" cy="117.7" r=".51" fill="none" stroke="#000080" stroke-width=".21"/>
<path d="M246.3 115.2h7.6" fill="none" stroke="#000" stroke-width=".25"/>
<circle cx="246.3" cy="115.2" r=".51" fill="#000080"/>
<circle cx="246.3" cy="115.2" r=".51" fill="none" stroke="#000080" stroke-width=".21"/>
<path d="M246.3 112.6h7.6" fill="none" stroke="#000" stroke-width=".25"/>
<circle cx="246.3" cy="112.7" r=".51" fill="#000080"/>
<circle cx="246.3" cy="112.7" r=".51" fill="none" stroke="#000080" stroke-width=".21"/>
<path d="M246.3 110.1h7.6" fill="none" stroke="#000" stroke-width=".25"/>
<circle cx="246.3" cy="110.1" r=".51" fill="#000080"/>
<circle cx="246.3" cy="110.1" r=".51" fill="none" stroke="#000080" stroke-width=".21"/>
<path d="M246.3 107.6h7.6" fill="none" stroke="#000" stroke-width=".25"/>
<circle cx="246.3" cy="107.6" r=".51" fill="#000080"/>
<circle cx="246.3" cy="107.6" r=".51" fill="none" stroke="#000080" stroke-width=".21"/>
<path d="M246.3 105h7.6" fill="none" stroke="#000" stroke-width=".25"/>
<circle cx="246.3" cy="105" r=".51" fill="#000080"/>
<circle cx="246.3" cy="105" r=".51" fill="none" stroke="#000080" stroke-width=".21"/>
<path d="M246.3 102.5h7.6" fill="none" stroke="#000" stroke-width=".25"/>
<circle cx="246.3" cy="102.5" r=".51" fill="#000080"/>
<circle cx="246.3" cy="102.5" r=".51" fill="none" stroke="#000080" stroke-width=".21"/>
<path d="M246.3 99.9h7.6" fill="none" stroke="#000" stroke-width=".25"/>
<circle cx="246.3" cy="100" r=".51" fill="#000080"/>
<circle cx="246.3" cy="100" r=".51" fill="none" stroke="#000080" stroke-width=".21"/>
<path d="M246.3 97.4h7.6" fill="none" stroke="#000" stroke-width=".25"/>
<circle cx="246.3" cy="97.4" r=".51" fill="#000080"/>
<circle cx="246.3" cy="97.4" r=".51" fill="none" stroke="#000080" stroke-width=".21"/>
<path d="M246.3 94.9h7.6" fill="none" stroke="#000" stroke-width=".25"/>
<circle cx="246.3" cy="94.9" r=".51" fill="#000080"/>
<circle cx="246.3" cy="94.9" r=".51" fill="none" stroke="#000080" stroke-width=".21"/>
<path d="M246.3 92.3h7.6" fill="none" stroke="#000" stroke-width=".25"/>
<circle cx="246.3" cy="92.3" r=".51" fill="#000080"/>
<circle cx="246.3" cy="92.3" r=".51" fill="none" stroke="#000080" stroke-width=".21"/>
<path d="M246.3 89.8h7.6" fill="none" stroke="#000" stroke-width=".25"/>
<circle cx="246.3" cy="89.8" r=".51" fill="#000080"/>
<circle cx="246.3" cy="89.8" r=".51" fill="none" stroke="#000080" stroke-width=".21"/>
<path d="M246.3 87.2h7.6" fill="none" stroke="#000" stroke-width=".25"/>
<circle cx="246.3" cy="87.3" r=".51" fill="#000080"/>
<circle cx="246.3" cy="87.3" r=".51" fill="none" stroke="#000080" stroke-width=".21"/>
<path d="M246.3 84.7h7.6" fill="none" stroke="#000" stroke-width=".25"/>
<circle cx="246.3" cy="84.7" r=".51" fill="#000080"/>
<circle cx="246.3" cy="84.7" r=".51" fill="none" stroke="#000080" stroke-width=".21"/>
<path d="M246.3 82.2h7.6" fill="none" stroke="#000" stroke-width=".25"/>
<circle cx="246.3" cy="82.2" r=".51" fill="#000080"/>
<circle cx="246.3" cy="82.2" r=".51" fill="none" stroke="#000080" stroke-width=".21"/>
<path d="M246.3 79.6h7.6" fill="none" stroke="#000" stroke-width=".25"/>
<circle cx="246.3" cy="79.6" r=".51" fill="#000080"/>
<circle cx="246.3" cy="79.6" r=".51" fill="none" stroke="#000080" stroke-width=".21"/>
<path d="M246.3 77.1h7.6" fill="none" stroke="#000" stroke-width=".25"/>
<circle cx="246.3" cy="77.1" r=".51" fill="#000080"/>
<circle cx="246.3" cy="77.1" r=".51" fill="none" stroke="#000080" stroke-width=".21"/>
<path d="M246.3 74.5h7.6" fill="none" stroke="#000" stroke-width=".25"/>
<circle cx="246.3" cy="74.6" r=".51" fill="#000080"/>
<circle cx="246.3" cy="74.6" r=".51" fill="none" stroke="#000080" stroke-width=".21"/>
<path d="M246.3 72h7.6" fill="none" stroke="#000" stroke-width=".25"/>
<circle cx="246.3" cy="72" r=".51" fill="#000080"/>
<circle cx="246.3" cy="72" r=".51" fill="none" stroke="#000080" stroke-width=".21"/>
<path d="M246.3 69.5h7.6M246.3 64.4h7.6M101.5 138v2.6M101.5 145.7v2.5M198 166h4.4M203.7 166h4.5" fill="none" stroke="#000" stroke-width=".25"/>
<g fill="none" stroke="#800000" stroke-width=".25">
<path d="M238.6 69.5h5.1l-2.5 2.5zM241.2 66.9v2.6M98.9 150.7h5.1l-2.5 2.6zM101.5 148.2v2.5M212 160.9h2.5M213.2 160.9v2.5M243.7 168.5h5.1M244.5 169.3h3.5M245.2 170.1h2.1M246 170.8h.5M246.3 166v2.5M279.3 168.5h5.1"/>
<path d="M280 169.3h3.6M280.8 170.1h2M281.6 170.8h.5M281.8 166v2.5"/>
</g>
<path d="M99.5 143.6h4M99.5 142.6h4M101.5 140.6v2M101.5 143.6v2.1M203.1 164.7h1.3l-1.3 2.6h-1.3z" fill="none" stroke="#00f" stroke-width=".25"/>
<circle cx="162.4" cy="166" r=".51" fill="#000080"/>
<circle cx="162.4" cy="166" r=".51" fill="none" stroke="#000080" stroke-width=".21"/>
<path d="M162.4 166v2.5M162.4 173.6v2.5" fill="none" stroke="#000" stroke-width=".25"/>
<circle cx="162.4" cy="166" r=".51" fill="#000080"/>
<circle cx="162.4" cy="166" r=".51" fill="none" stroke="#000080" stroke-width=".21"/>
<path d="M160.4 171.6h4M160.4 170.6h4M162.4 168.5v2.1M162.4 171.6v2" fill="none" stroke="#00f" stroke-width=".25"/>
<path d="M159.9 178.7h5.1M160.7 179.5h3.5M162.4 176.1v2.6M161.4 180.2h2.1M162.2 181h.5" fill="none" stroke="#800000" stroke-width=".25"/>
<circle cx="175.1" cy="166" r=".51" fill="#000080"/>
<circle cx="175.1" cy="166" r=".51" fill="none" stroke="#000080" stroke-width=".21"/>
<path d="M175.1 166v2.5M175.1 173.6v2.5" fill="none" stroke="#000" stroke-width=".25"/>
<circle cx="175.1" cy="166" r=".51" fill="#000080"/>
<circle cx="175.1" cy="166" r=".51" fill="none" stroke="#000080" stroke-width=".21"/>
<path d="M173.1 171.6h4M173.1 170.6h4M175.1 168.5v2.1M175.1 171.6v2" fill="none" stroke="#00f" stroke-width=".25"/>
<path d="M172.6 178.7h5.1M173.4 179.5h3.5M175.1 176.1v2.6M174.1 180.2h2.1M174.9 181h.5" fill="none" stroke="#800000" stroke-width=".25"/>
<circle cx="96.4" cy="163.5" r=".51" fill="#000080"/>
<circle cx="96.4" cy="163.5" r=".51" fill="none" stroke="#000080" stroke-width=".21"/>
<path d="M96.4 163.4v2.6M96.4 171.1v2.5" fill="none" stroke="#000" stroke-width=".25"/>
<circle cx="96.4" cy="163.5" r=".51" fill="#000080"/>
<circle cx="96.4" cy="163.5" r=".51" fill="none" stroke="#000080" stroke-width=".21"/>
<path d="M94.4 169h4M94.4 168h4M96.4 166v2M96.4 169v2.1" fill="none" stroke="#00f" stroke-width=".25"/>
<path d="M93.9 176.1h5M94.6 176.9h3.6M95.4 177.7h2M96.1 178.4h.6M96.4 173.6v2.5" fill="none" stroke="#800000" stroke-width=".25"/>
<circle cx="83.7" cy="163.5" r=".51" fill="#000080"/>
<circle cx="83.7" cy="163.5" r=".51" fill="none" stroke="#000080" stroke-width=".21"/>
<path d="M83.7 163.4v2.6M83.7 171.1v2.5" fill="none" stroke="#000" stroke-width=".25"/>
<circle cx="83.7" cy="163.5" r=".51" fill="#000080"/>
<circle cx="83.7" cy="163.5" r=".51" fill="none" stroke="#000080" stroke-width=".21"/>
<path d="M81.7 169h4M81.7 168h4M83.7 166v2M83.7 169v2.1" fill="none" stroke="#00f" stroke-width=".25"/>
<path d="M81.2 176.1h5M81.9 176.9h3.6M82.7 177.7h2M83.4 178.4h.6M83.7 173.6v2.5" fill="none" stroke="#800000" stroke-width=".25"/>
<circle cx="187.8" cy="166" r=".51" fill="#000080"/>
<circle cx="187.8" cy="166" r=".51" fill="none" stroke="#000080" stroke-width=".21"/>
<path d="M187.8 166v2.5M187.8 173.6v2.5" fill="none" stroke="#000" stroke-width=".25"/>
<circle cx="187.8" cy="166" r=".51" fill="#000080"/>
<circle cx="187.8" cy="166" r=".51" fill="none" stroke="#000080" stroke-width=".21"/>
<path d="M185.8 171.6h4M185.8 170.6h4M187.8 168.5v2.1M187.8 171.6v2" fill="none" stroke="#00f" stroke-width=".25"/>
<path d="M185.3 178.7h5.1M186.1 179.5h3.5M187.8 176.1v2.6M186.8 180.2h2.1M187.6 181h.5" fill="none" stroke="#800000" stroke-width=".25"/>
<circle cx="71" cy="163.5" r=".51" fill="#000080"/>
<circle cx="71" cy="163.5" r=".51" fill="none" stroke="#000080" stroke-width=".21"/>
<path d="M71 163.4v2.6M71 171.1v2.5" fill="none" stroke="#000" stroke-width=".25"/>
<circle cx="71" cy="163.5" r=".51" fill="#000080"/>
<circle cx="71" cy="163.5" r=".51" fill="none" stroke="#000080" stroke-width=".21"/>
<path d="M69 169h4M69 168h4M71 166v2M71 169v2.1" fill="none" stroke="#00f" stroke-width=".25"/>
<path d="M68.5 176.1h5M69.2 176.9h3.6M70 177.7h2M70.7 178.4h.6M71 173.6v2.5" fill="none" stroke="#800000" stroke-width=".25"/>
<circle cx="83.7" cy="92.3" r=".51" fill="#000080"/>
<circle cx="83.7" cy="92.3" r=".51" fill="none" stroke="#000080" stroke-width=".21"/>
<path d="M83.7 92.3v2.6M83.7 99.9v2.6" fill="none" stroke="#000" stroke-width=".25"/>
<circle cx="83.7" cy="92.3" r=".51" fill="#000080"/>
<circle cx="83.7" cy="92.3" r=".51" fill="none" stroke="#000080" stroke-width=".21"/>
<path d="M81.7 97.9h4M81.7 96.9h4M83.7 94.9v2M83.7 97.9v2" fill="none" stroke="#00f" stroke-width=".25"/>
<circle cx="225.9" cy="92.3" r=".51" fill="#000080"/>
<circle cx="225.9" cy="92.3" r=".51" fill="none" stroke="#000080" stroke-width=".21"/>
<path d="M225.9 92.3v2.6M225.9 99.9v2.6" fill="none" stroke="#000" stroke-width=".25"/>
<circle cx="225.9" cy="92.3" r=".51" fill="#000080"/>
<circle cx="225.9" cy="92.3" r=".51" fill="none" stroke="#000080" stroke-width=".21"/>
<path d="M223.9 97.9h4M223.9 96.9h4M225.9 94.9v2M225.9 97.9v2" fill="none" stroke="#00f" stroke-width=".25"/>
<path d="M81.2 105h5M81.9 105.8h3.6M82.7 106.6h2M83.4 107.3h.6M83.7 102.5v2.5M223.4 105h5.1M224.2 105.8h3.5M224.9 106.6h2.1M225.7 107.3h.5M225.9 102.5v2.5" fill="none" stroke="#800000" stroke-width=".25"/>
<circle cx="162.4" cy="92.3" r=".51" fill="#000080"/>
<circle cx="162.4" cy="92.3" r=".51" fill="none" stroke="#000080" stroke-width=".21"/>
<path d="M162.4 92.3v2.6M162.4 99.9v2.6" fill="none" stroke="#000" stroke-width=".25"/>
<circle cx="162.4" cy="92.3" r=".51" fill="#000080"/>
<circle cx="162.4" cy="92.3" r=".51" fill="none" stroke="#000080" stroke-width=".21"/>
<path d="M160.4 97.9h4M160.4 96.9h4M162.4 94.9v2M162.4 97.9v2" fill="none" stroke="#00f" stroke-width=".25"/>
<path d="M159.9 105h5.1M160.7 105.8h3.5M161.4 106.6h2.1M162.2 107.3h.5M162.4 102.5v2.5" fill="none" stroke="#800000" stroke-width=".25"/>
<circle cx="175.1" cy="92.3" r=".51" fill="#000080"/>
<circle cx="175.1" cy="92.3" r=".51" fill="none" stroke="#000080" stroke-width=".21"/>
<path d="M175.1 92.3v2.6M175.1 99.9v2.6" fill="none" stroke="#000" stroke-width=".25"/>
<circle cx="175.1" cy="92.3" r=".51" fill="#000080"/>
<circle cx="175.1" cy="92.3" r=".51" fill="none" stroke="#000080" stroke-width=".21"/>
<path d="M173.1 97.9h4M173.1 96.9h4M175.1 94.9v2M175.1 97.9v2" fill="none" stroke="#00f" stroke-width=".25"/>
<path d="M172.6 105h5.1M173.4 105.8h3.5M174.1 106.6h2.1M174.9 107.3h.5M175.1 102.5v2.5" fill="none" stroke="#800000" stroke-width=".25"/>
<circle cx="187.8" cy="92.3" r=".51" fill="#000080"/>
<circle cx="187.8" cy="92.3" r=".51" fill="none" stroke="#000080" stroke-width=".21"/>
<path d="M187.8 92.3v2.6M187.8 99.9v2.6" fill="none" stroke="#000" stroke-width=".25"/>
<circle cx="187.8" cy="92.3" r=".51" fill="#000080"/>
<circle cx="187.8" cy="92.3" r=".51" fill="none" stroke="#000080" stroke-width=".21"/>
<path d="M185.8 97.9h4M185.8 96.9h4M187.8 94.9v2M187.8 97.9v2" fill="none" stroke="#00f" stroke-width=".25"/>
<path d="M185.3 105h5.1M186.1 105.8h3.5M186.8 106.6h2.1M187.6 107.3h.5M187.8 102.5v2.5" fill="none" stroke="#800000" stroke-width=".25"/>
<circle cx="200.5" cy="92.3" r=".51" fill="#000080"/>
<circle cx="200.5" cy="92.3" r=".51" fill="none" stroke="#000080" stroke-width=".21"/>
<path d="M200.5 92.3v2.6M200.5 99.9v2.6" fill="none" stroke="#000" stroke-width=".25"/>
<circle cx="200.5" cy="92.3" r=".51" fill="#000080"/>
<circle cx="200.5" cy="92.3" r=".51" fill="none" stroke="#000080" stroke-width=".21"/>
<path d="M198.5 97.9h4M198.5 96.9h4M200.5 94.9v2M200.5 97.9v2" fill="none" stroke="#00f" stroke-width=".25"/>
<path d="M198 105h5.1M198.8 105.8h3.5M199.5 106.6h2.1M200.3 107.3h.5M200.5 102.5v2.5" fill="none" stroke="#800000" stroke-width=".25"/>
<circle cx="213.2" cy="92.3" r=".51" fill="#000080"/>
<circle cx="213.2" cy="92.3" r=".51" fill="none" stroke="#000080" stroke-width=".21"/>
<path d="M213.2 92.3v2.6M213.2 99.9v2.6" fill="none" stroke="#000" stroke-width=".25"/>
<circle cx="213.2" cy="92.3" r=".51" fill="#000080"/>
<circle cx="213.2" cy="92.3" r=".51" fill="none" stroke="#000080" stroke-width=".21"/>
<path d="M211.2 97.9h4M211.2 96.9h4M213.2 94.9v2M213.2 97.9v2" fill="none" stroke="#00f" stroke-width=".25"/>
<path d="M210.7 105h5.1M211.5 105.8h3.5M212.2 106.6h2.1M213 107.3h.5M213.2 102.5v2.5" fill="none" stroke="#800000" stroke-width=".25"/>
<circle cx="96.4" cy="92.3" r=".51" fill="#000080"/>
<circle cx="96.4" cy="92.3" r=".51" fill="none" stroke="#000080" stroke-width=".21"/>
<path d="M96.4 92.3v2.6M96.4 99.9v2.6" fill="none" stroke="#000" stroke-width=".25"/>
<circle cx="96.4" cy="92.3" r=".51" fill="#000080"/>
<circle cx="96.4" cy="92.3" r=".51" fill="none" stroke="#000080" stroke-width=".21"/>
<path d="M94.4 97.9h4M94.4 96.9h4M96.4 94.9v2M96.4 97.9v2" fill="none" stroke="#00f" stroke-width=".25"/>
<path d="M93.9 105h5M94.6 105.8h3.6M95.4 106.6h2M96.1 107.3h.6M96.4 102.5v2.5" fill="none" stroke="#800000" stroke-width=".25"/>
<circle cx="20.2" cy="115.2" r=".51" fill="#000080"/>
<circle cx="20.2" cy="115.2" r=".51" fill="none" stroke="#000080" stroke-width=".21"/>
<path d="M20.2 115.2v2.5M20.2 122.8v2.5" fill="none" stroke="#000" stroke-width=".25"/>
<circle cx="20.2" cy="115.2" r=".51" fill="#000080"/>
<circle cx="20.2" cy="115.2" r=".51" fill="none" stroke="#000080" stroke-width=".21"/>
<path d="M18.2 119.8h4M20.2 117.7v2.1M18.2 120.8h4M20.2 120.8v2" fill="none" stroke="#00f" stroke-width=".25"/>
<path d="M17.7 127.9h5M18.4 128.7h3.6M19.2 129.4h2M19.9 130.2h.6M20.2 125.3v2.6" fill="none" stroke="#800000" stroke-width=".25"/>
<circle cx="58.3" cy="115.2" r=".51" fill="#000080"/>
<circle cx="58.3" cy="115.2" r=".51" fill="none" stroke="#000080" stroke-width=".21"/>
<path d="M58.3 115.2v2.5M58.3 122.8v2.5" fill="none" stroke="#000" stroke-width=".25"/>
<circle cx="58.3" cy="115.2" r=".51" fill="#000080"/>
<circle cx="58.3" cy="115.2" r=".51" fill="none" stroke="#000080" stroke-width=".21"/>
<path d="M56.3 119.8h4M58.3 117.7v2.1M56.3 120.8h4M58.3 120.8v2" fill="none" stroke="#00f" stroke-width=".25"/>
<path d="M55.8 127.9h5M56.5 128.7h3.6M57.3 129.4h2M58 130.2h.6M58.3 125.3v2.6" fill="none" stroke="#800000" stroke-width=".25"/>
<circle cx="71" cy="115.2" r=".51" fill="#000080"/>
<circle cx="71" cy="115.2" r=".51" fill="none" stroke="#000080" stroke-width=".21"/>
<path d="M71 115.2v2.5M71 122.8v2.5" fill="none" stroke="#000" stroke-width=".25"/>
<circle cx="71" cy="115.2" r=".51" fill="#000080"/>
<circle cx="71" cy="115.2" r=".51" fill="none" stroke="#000080" stroke-width=".21"/>
<path d="M69 119.8h4M71 117.7v2.1M69 120.8h4M71 120.8v2" fill="none" stroke="#00f" stroke-width=".25"/>
<path d="M68.5 127.9h5M69.2 128.7h3.6M70 129.4h2M70.7 130.2h.6M71 125.3v2.6" fill="none" stroke="#800000" stroke-width=".25"/>
<circle cx="83.7" cy="115.2" r=".51" fill="#000080"/>
<circle cx="83.7" cy="115.2" r=".51" fill="none" stroke="#000080" stroke-width=".21"/>
<path d="M83.7 115.2v2.5M83.7 122.8v2.5" fill="none" stroke="#000" stroke-width=".25"/>
<circle cx="83.7" cy="115.2" r=".51" fill="#000080"/>
<circle cx="83.7" cy="115.2" r=".51" fill="none" stroke="#000080" stroke-width=".21"/>
<path d="M81.7 119.8h4M83.7 117.7v2.1M81.7 120.8h4M83.7 120.8v2" fill="none" stroke="#00f" stroke-width=".25"/>
<path d="M81.2 127.9h5M81.9 128.7h3.6M82.7 129.4h2M83.4 130.2h.6M83.7 125.3v2.6" fill="none" stroke="#800000" stroke-width=".25"/>
<circle cx="32.9" cy="115.2" r=".51" fill="#000080"/>
<circle cx="32.9" cy="115.2" r=".51" fill="none" stroke="#000080" stroke-width=".21"/>
<path d="M32.9 115.2v2.5M32.9 122.8v2.5" fill="none" stroke="#000" stroke-width=".25"/>
<circle cx="32.9" cy="115.2" r=".51" fill="#000080"/>
<circle cx="32.9" cy="115.2" r=".51" fill="none" stroke="#000080" stroke-width=".21"/>
<path d="M30.9 119.8h4M32.9 117.7v2.1M30.9 120.8h4M32.9 120.8v2" fill="none" stroke="#00f" stroke-width=".25"/>
<path d="M30.4 127.9h5M31.1 128.7h3.6M31.9 129.4h2M32.6 130.2h.6M32.9 125.3v2.6" fill="none" stroke="#800000" stroke-width=".25"/>
<circle cx="45.6" cy="115.2" r=".51" fill="#000080"/>
<circle cx="45.6" cy="115.2" r=".51" fill="none" stroke="#000080" stroke-width=".21"/>
<path d="M45.6 115.2v2.5M45.6 122.8v2.5" fill="none" stroke="#000" stroke-width=".25"/>
<circle cx="45.6" cy="115.2" r=".51" fill="#000080"/>
<circle cx="45.6" cy="115.2" r=".51" fill="none" stroke="#000080" stroke-width=".21"/>
<path d="M160.4 70h4M160.4 69h4M162.4 66.9v2.1M162.4 70v2M43.6 119.8h4M45.6 117.7v2.1M43.6 120.8h4M45.6 120.8v2" fill="none" stroke="#00f" stroke-width=".25"/>
<path d="M159.9 77.1h5.1M160.7 77.9h3.5M161.4 78.6h2.1M162.2 79.4h.5M162.4 74.5v2.6M43.1 127.9h5M43.8 128.7h3.6M44.6 129.4h2M45.3 130.2h.6M45.6 125.3v2.6" fill="none" stroke="#800000" stroke-width=".25"/>
<path d="M162.4 64.4v2.5M162.4 72v2.5" fill="none" stroke="#000" stroke-width=".25"/>
<circle cx="20.2" cy="31.4" r=".51" fill="#000080"/>
<circle cx="20.2" cy="31.4" r=".51" fill="none" stroke="#000080" stroke-width=".21"/>
<path d="M20.2 31.4v2.5M20.2 39v2.5" fill="none" stroke="#000" stroke-width=".25"/>
<circle cx="20.2" cy="31.4" r=".51" fill="#000080"/>
<circle cx="20.2" cy="31.4" r=".51" fill="none" stroke="#000080" stroke-width=".21"/>
<path d="M18.2 36.9h4M18.2 35.9h4M20.2 33.9v2M20.2 36.9v2.1" fill="none" stroke="#00f" stroke-width=".25"/>
<path d="M17.7 44.1h5M18.4 44.8h3.6M19.2 45.6h2M19.9 46.3h.5M20.2 41.5v2.6" fill="none" stroke="#800000" stroke-width=".25"/>
<circle cx="71" cy="31.4" r=".51" fill="#000080"/>
<circle cx="71" cy="31.4" r=".51" fill="none" stroke="#000080" stroke-width=".21"/>
<path d="M71 31.4v2.5M71 39v2.5" fill="none" stroke="#000" stroke-width=".25"/>
<circle cx="71" cy="31.4" r=".51" fill="#000080"/>
<circle cx="71" cy="31.4" r=".51" fill="none" stroke="#000080" stroke-width=".21"/>
<path d="M69 36.9h4M69 35.9h4M71 33.9v2M71 36.9v2.1" fill="none" stroke="#00f" stroke-width=".25"/>
<path d="M68.5 44.1h5M69.2 44.8h3.6M70 45.6h2M70.7 46.3h.5M71 41.5v2.6" fill="none" stroke="#800000" stroke-width=".25"/>
<circle cx="83.7" cy="31.4" r=".51" fill="#000080"/>
<circle cx="83.7" cy="31.4" r=".51" fill="none" stroke="#000080" stroke-width=".21"/>
<path d="M83.7 31.4v2.5M83.7 39v2.5" fill="none" stroke="#000" stroke-width=".25"/>
<circle cx="83.7" cy="31.4" r=".51" fill="#000080"/>
<circle cx="83.7" cy="31.4" r=".51" fill="none" stroke="#000080" stroke-width=".21"/>
<path d="M81.7 36.9h4M81.7 35.9h4M83.7 33.9v2M83.7 36.9v2.1" fill="none" stroke="#00f" stroke-width=".25"/>
<path d="M81.2 44.1h5M81.9 44.8h3.6M82.7 45.6h2M83.4 46.3h.5M83.7 41.5v2.6" fill="none" stroke="#800000" stroke-width=".25"/>
<circle cx="96.4" cy="31.4" r=".51" fill="#000080"/>
<circle cx="96.4" cy="31.4" r=".51" fill="none" stroke="#000080" stroke-width=".21"/>
<path d="M96.4 31.4v2.5M96.4 39v2.5" fill="none" stroke="#000" stroke-width=".25"/>
<circle cx="96.4" cy="31.4" r=".51" fill="#000080"/>
<circle cx="96.4" cy="31.4" r=".51" fill="none" stroke="#000080" stroke-width=".21"/>
<path d="M94.4 36.9h4M94.4 35.9h4M96.4 33.9v2M96.4 36.9v2.1" fill="none" stroke="#00f" stroke-width=".25"/>
<path d="M93.9 44.1h5M94.6 44.8h3.6M95.4 45.6h2M96.1 46.3h.6M96.4 41.5v2.6" fill="none" stroke="#800000" stroke-width=".25"/>
<circle cx="58.3" cy="31.4" r=".51" fill="#000080"/>
<circle cx="58.3" cy="31.4" r=".51" fill="none" stroke="#000080" stroke-width=".21"/>
<path d="M58.3 31.4v2.5M58.3 39v2.5" fill="none" stroke="#000" stroke-width=".25"/>
<circle cx="58.3" cy="31.4" r=".51" fill="#000080"/>
<circle cx="58.3" cy="31.4" r=".51" fill="none" stroke="#000080" stroke-width=".21"/>
<path d="M56.3 36.9h4M56.3 35.9h4M58.3 33.9v2M58.3 36.9v2.1" fill="none" stroke="#00f" stroke-width=".25"/>
<path d="M55.8 44.1h5M56.5 44.8h3.6M57.3 45.6h2M58 46.3h.5M58.3 41.5v2.6" fill="none" stroke="#800000" stroke-width=".25"/>
<circle cx="45.6" cy="31.4" r=".51" fill="#000080"/>
<circle cx="45.6" cy="31.4" r=".51" fill="none" stroke="#000080" stroke-width=".21"/>
<path d="M45.6 31.4v2.5M45.6 39v2.5" fill="none" stroke="#000" stroke-width=".25"/>
<circle cx="45.6" cy="31.4" r=".51" fill="#000080"/>
<circle cx="45.6" cy="31.4" r=".51" fill="none" stroke="#000080" stroke-width=".21"/>
<path d="M43.6 36.9h4M43.6 35.9h4M45.6 33.9v2M45.6 36.9v2.1" fill="none" stroke="#00f" stroke-width=".25"/>
<path d="M43.1 44.1h5M43.8 44.8h3.6M44.6 45.6h2M45.3 46.3h.5M45.6 41.5v2.6" fill="none" stroke="#800000" stroke-width=".25"/>
<circle cx="32.9" cy="31.4" r=".51" fill="#000080"/>
<circle cx="32.9" cy="31.4" r=".51" fill="none" stroke="#000080" stroke-width=".21"/>
<path d="M32.9 31.4v2.5M32.9 39v2.5" fill="none" stroke="#000" stroke-width=".25"/>
<circle cx="32.9" cy="31.4" r=".51" fill="#000080"/>
<circle cx="32.9" cy="31.4" r=".51" fill="none" stroke="#000080" stroke-width=".21"/>
<path d="M30.9 36.9h4M30.9 35.9h4M32.9 33.9v2M32.9 36.9v2.1" fill="none" stroke="#00f" stroke-width=".25"/>
<path d="M30.4 44.1h5M31.1 44.8h3.6M31.9 45.6h2M32.6 46.3h.5M32.9 41.5v2.6" fill="none" stroke="#800000" stroke-width=".25"/>
<circle cx="20.2" cy="59.3" r=".51" fill="#000080"/>
<circle cx="20.2" cy="59.3" r=".51" fill="none" stroke="#000080" stroke-width=".21"/>
<path d="M20.2 59.3v2.5M20.2 66.9v2.6" fill="none" stroke="#000" stroke-width=".25"/>
<circle cx="20.2" cy="59.3" r=".51" fill="#000080"/>
<circle cx="20.2" cy="59.3" r=".51" fill="none" stroke="#000080" stroke-width=".21"/>
<path d="M18.2 64.9h4M18.2 63.9h4M20.2 61.8v2.1M20.2 64.9v2" fill="none" stroke="#00f" stroke-width=".25"/>
<path d="M17.7 72h5M18.4 72.8h3.6M19.2 73.5h2M19.9 74.3h.5M20.2 69.5v2.5" fill="none" stroke="#800000" stroke-width=".25"/>
<circle cx="71" cy="59.3" r=".51" fill="#000080"/>
<circle cx="71" cy="59.3" r=".51" fill="none" stroke="#000080" stroke-width=".21"/>
<path d="M71 59.3v2.5M71 66.9v2.6" fill="none" stroke="#000" stroke-width=".25"/>
<circle cx="71" cy="59.3" r=".51" fill="#000080"/>
<circle cx="71" cy="59.3" r=".51" fill="none" stroke="#000080" stroke-width=".21"/>
<path d="M69 64.9h4M69 63.9h4M71 61.8v2.1M71 64.9v2" fill="none" stroke="#00f" stroke-width=".25"/>
<path d="M68.5 72h5M69.2 72.8h3.6M70 73.5h2M70.7 74.3h.5M71 69.5v2.5" fill="none" stroke="#800000" stroke-width=".25"/>
<circle cx="83.7" cy="59.3" r=".51" fill="#000080"/>
<circle cx="83.7" cy="59.3" r=".51" fill="none" stroke="#000080" stroke-width=".21"/>
<path d="M83.7 59.3v2.5M83.7 66.9v2.6" fill="none" stroke="#000" stroke-width=".25"/>
<circle cx="83.7" cy="59.3" r=".51" fill="#000080"/>
<circle cx="83.7" cy="59.3" r=".51" fill="none" stroke="#000080" stroke-width=".21"/>
<path d="M81.7 64.9h4M81.7 63.9h4M83.7 61.8v2.1M83.7 64.9v2" fill="none" stroke="#00f" stroke-width=".25"/>
<path d="M81.2 72h5M81.9 72.8h3.6M82.7 73.5h2M83.4 74.3h.5M83.7 69.5v2.5" fill="none" stroke="#800000" stroke-width=".25"/>
<circle cx="96.4" cy="59.3" r=".51" fill="#000080"/>
<circle cx="96.4" cy="59.3" r=".51" fill="none" stroke="#000080" stroke-width=".21"/>
<path d="M96.4 59.3v2.5M96.4 66.9v2.6" fill="none" stroke="#000" stroke-width=".25"/>
<circle cx="96.4" cy="59.3" r=".51" fill="#000080"/>
<circle cx="96.4" cy="59.3" r=".51" fill="none" stroke="#000080" stroke-width=".21"/>
<path d="M94.4 64.9h4M94.4 63.9h4M96.4 61.8v2.1M96.4 64.9v2" fill="none" stroke="#00f" stroke-width=".25"/>
<path d="M93.9 72h5M94.6 72.8h3.6M95.4 73.5h2M96.1 74.3h.6M96.4 69.5v2.5" fill="none" stroke="#800000" stroke-width=".25"/>
<circle cx="58.3" cy="59.3" r=".51" fill="#000080"/>
<circle cx="58.3" cy="59.3" r=".51" fill="none" stroke="#000080" stroke-width=".21"/>
<path d="M58.3 59.3v2.5M58.3 66.9v2.6" fill="none" stroke="#000" stroke-width=".25"/>
<circle cx="58.3" cy="59.3" r=".51" fill="#000080"/>
<circle cx="58.3" cy="59.3" r=".51" fill="none" stroke="#000080" stroke-width=".21"/>
<path d="M56.3 64.9h4M56.3 63.9h4M58.3 61.8v2.1M58.3 64.9v2" fill="none" stroke="#00f" stroke-width=".25"/>
<path d="M55.8 72h5M56.5 72.8h3.6M57.3 73.5h2M58 74.3h.5M58.3 69.5v2.5" fill="none" stroke="#800000" stroke-width=".25"/>
<circle cx="45.6" cy="59.3" r=".51" fill="#000080"/>
<circle cx="45.6" cy="59.3" r=".51" fill="none" stroke="#000080" stroke-width=".21"/>
<path d="M45.6 59.3v2.5M45.6 66.9v2.6" fill="none" stroke="#000" stroke-width=".25"/>
<circle cx="45.6" cy="59.3" r=".51" fill="#000080"/>
<circle cx="45.6" cy="59.3" r=".51" fill="none" stroke="#000080" stroke-width=".21"/>
<path d="M43.6 64.9h4M43.6 63.9h4M45.6 61.8v2.1M45.6 64.9v2" fill="none" stroke="#00f" stroke-width=".25"/>
<path d="M43.1 72h5M43.8 72.8h3.6M44.6 73.5h2M45.3 74.3h.5M45.6 69.5v2.5" fill="none" stroke="#800000" stroke-width=".25"/>
<circle cx="32.9" cy="59.3" r=".51" fill="#000080"/>
<circle cx="32.9" cy="59.3" r=".51" fill="none" stroke="#000080" stroke-width=".21"/>
<path d="M32.9 59.3v2.5M32.9 66.9v2.6" fill="none" stroke="#000" stroke-width=".25"/>
<circle cx="32.9" cy="59.3" r=".51" fill="#000080"/>
<circle cx="32.9" cy="59.3" r=".51" fill="none" stroke="#000080" stroke-width=".21"/>
<path d="M30.9 64.9h4M30.9 63.9h4M32.9 61.8v2.1M32.9 64.9v2" fill="none" stroke="#00f" stroke-width=".25"/>
<path d="M30.4 72h5M31.1 72.8h3.6M31.9 73.5h2M32.6 74.3h.5M32.9 69.5v2.5" fill="none" stroke="#800000" stroke-width=".25"/>
<circle cx="187.8" cy="31.4" r=".51" fill="#000080"/>
<circle cx="187.8" cy="31.4" r=".51" fill="none" stroke="#000080" stroke-width=".21"/>
<path d="M187.8 31.4v2.5M187.8 39v2.5" fill="none" stroke="#000" stroke-width=".25"/>
<circle cx="187.8" cy="31.4" r=".51" fill="#000080"/>
<circle cx="187.8" cy="31.4" r=".51" fill="none" stroke="#000080" stroke-width=".21"/>
<path d="M185.8 36.9h4M185.8 36h4M187.8 33.9v2.1M187.8 36.9v2.1" fill="none" stroke="#00f" stroke-width=".25"/>
<path d="M185.3 44.1h5.1M186.1 44.8h3.5M186.8 45.6h2.1M187.6 46.4h.5M187.8 41.5v2.6" fill="none" stroke="#800000" stroke-width=".25"/>
<circle cx="175.1" cy="31.4" r=".51" fill="#000080"/>
<circle cx="175.1" cy="31.4" r=".51" fill="none" stroke="#000080" stroke-width=".21"/>
<path d="M175.1 31.4v2.5M175.1 39v2.5" fill="none" stroke="#000" stroke-width=".25"/>
<circle cx="175.1" cy="31.4" r=".51" fill="#000080"/>
<circle cx="175.1" cy="31.4" r=".51" fill="none" stroke="#000080" stroke-width=".21"/>
<path d="M173.1 36.9h4M173.1 36h4M175.1 33.9v2.1M175.1 36.9v2.1" fill="none" stroke="#00f" stroke-width=".25"/>
<path d="M172.6 44.1h5.1M173.4 44.8h3.5M174.1 45.6h2.1M174.9 46.4h.5M175.1 41.5v2.6" fill="none" stroke="#800000" stroke-width=".25"/>
<circle cx="162.4" cy="31.4" r=".51" fill="#000080"/>
<circle cx="162.4" cy="31.4" r=".51" fill="none" stroke="#000080" stroke-width=".21"/>
<path d="M162.4 31.4v2.5M162.4 39v2.5" fill="none" stroke="#000" stroke-width=".25"/>
<circle cx="162.4" cy="31.4" r=".51" fill="#000080"/>
<circle cx="162.4" cy="31.4" r=".51" fill="none" stroke="#000080" stroke-width=".21"/>
<path d="M160.4 36.9h4M160.4 35.9h4M162.4 33.9v2M162.4 36.9v2.1" fill="none" stroke="#00f" stroke-width=".25"/>
<path d="M159.9 44.1h5.1M160.7 44.8h3.5M161.4 45.6h2.1M162.2 46.3h.5M162.4 41.5v2.6" fill="none" stroke="#800000" stroke-width=".25"/>
<circle cx="200.5" cy="31.4" r=".51" fill="#000080"/>
<circle cx="200.5" cy="31.4" r=".51" fill="none" stroke="#000080" stroke-width=".21"/>
<path d="M200.5 31.4v2.5M200.5 39v2.5" fill="none" stroke="#000" stroke-width=".25"/>
<circle cx="200.5" cy="31.4" r=".51" fill="#000080"/>
<circle cx="200.5" cy="31.4" r=".51" fill="none" stroke="#000080" stroke-width=".21"/>
<path d="M198.5 36.9h4M198.5 36h4M200.5 33.9v2.1M200.5 36.9v2.1" fill="none" stroke="#00f" stroke-width=".25"/>
<path d="M198 44.1h5.1M198.8 44.8h3.5M199.5 45.6h2.1M200.3 46.4h.5M200.5 41.5v2.6" fill="none" stroke="#800000" stroke-width=".25"/>
<circle cx="213.2" cy="31.4" r=".51" fill="#000080"/>
<circle cx="213.2" cy="31.4" r=".51" fill="none" stroke="#000080" stroke-width=".21"/>
<path d="M213.2 31.4v2.5M213.2 39v2.5" fill="none" stroke="#000" stroke-width=".25"/>
<circle cx="213.2" cy="31.4" r=".51" fill="#000080"/>
<circle cx="213.2" cy="31.4" r=".51" fill="none" stroke="#000080" stroke-width=".21"/>
<path d="M211.2 36.9h4M211.2 36h4M213.2 33.9v2.1M213.2 36.9v2.1" fill="none" stroke="#00f" stroke-width=".25"/>
<path d="M210.7 44.1h5.1M211.5 44.8h3.5M212.2 45.6h2.1M213 46.4h.5M213.2 41.5v2.6" fill="none" stroke="#800000" stroke-width=".25"/>
<circle cx="225.9" cy="31.4" r=".51" fill="#000080"/>
<circle cx="225.9" cy="31.4" r=".51" fill="none" stroke="#000080" stroke-width=".21"/>
<path d="M225.9 31.4v2.5M225.9 39v2.5" fill="none" stroke="#000" stroke-width=".25"/>
<circle cx="225.9" cy="31.4" r=".51" fill="#000080"/>
<circle cx="225.9" cy="31.4" r=".51" fill="none" stroke="#000080" stroke-width=".21"/>
<path d="M223.9 36.9h4M223.9 36h4M225.9 33.9v2.1M225.9 36.9v2.1" fill="none" stroke="#00f" stroke-width=".25"/>
<path d="M223.4 44.1h5.1M224.2 44.8h3.5M224.9 45.6h2.1M225.7 46.4h.5M225.9 41.5v2.6" fill="none" stroke="#800000" stroke-width=".25"/>
<path d="M15.1 28.8v2.6h94v12.7" fill="none" stroke="#000080" stroke-width=".25"/>
<circle cx="109.1" cy="41.5" r=".51" fill="#000080"/>
<circle cx="109.1" cy="41.5" r=".51" fill="none" stroke="#000080" stroke-width=".21"/>
<circle cx="109.1" cy="39" r=".51" fill="#000080"/>
<circle cx="109.1" cy="39" r=".51" fill="none" stroke="#000080" stroke-width=".21"/>
<circle cx="109.1" cy="36.4" r=".51" fill="#000080"/>
<circle cx="109.1" cy="36.4" r=".51" fill="none" stroke="#000080" stroke-width=".21"/>
<circle cx="109.1" cy="33.9" r=".51" fill="#000080"/>
<circle cx="109.1" cy="33.9" r=".51" fill="none" stroke="#000080" stroke-width=".21"/>
<circle cx="109.1" cy="31.4" r=".51" fill="#000080"/>
<circle cx="109.1" cy="31.4" r=".51" fill="none" stroke="#000080" stroke-width=".21"/>
<circle cx="96.4" cy="31.4" r=".51" fill="#000080"/>
<circle cx="96.4" cy="31.4" r=".51" fill="none" stroke="#000080" stroke-width=".21"/>
<circle cx="83.7" cy="31.4" r=".51" fill="#000080"/>
<circle cx="83.7" cy="31.4" r=".51" fill="none" stroke="#000080" stroke-width=".21"/>
<circle cx="71" cy="31.4" r=".51" fill="#000080"/>
<circle cx="71" cy="31.4" r=".51" fill="none" stroke="#000080" stroke-width=".21"/>
<circle cx="58.3" cy="31.4" r=".51" fill="#000080"/>
<circle cx="58.3" cy="31.4" r=".51" fill="none" stroke="#000080" stroke-width=".21"/>
<circle cx="45.6" cy="31.4" r=".51" fill="#000080"/>
<circle cx="45.6" cy="31.4" r=".51" fill="none" stroke="#000080" stroke-width=".21"/>
<circle cx="32.9" cy="31.4" r=".51" fill="#000080"/>
<circle cx="32.9" cy="31.4" r=".51" fill="none" stroke="#000080" stroke-width=".21"/>
<circle cx="20.2" cy="31.4" r=".51" fill="#000080"/>
<circle cx="20.2" cy="31.4" r=".51" fill="none" stroke="#000080" stroke-width=".21"/>
<path d="M15.1 56.8v2.5h94v5.1" fill="none" stroke="#000080" stroke-width=".25"/>
<circle cx="109.1" cy="61.9" r=".51" fill="#000080"/>
<circle cx="109.1" cy="61.9" r=".51" fill="none" stroke="#000080" stroke-width=".21"/>
<circle cx="109.1" cy="59.3" r=".51" fill="#000080"/>
<circle cx="109.1" cy="59.3" r=".51" fill="none" stroke="#000080" stroke-width=".21"/>
<circle cx="96.4" cy="59.3" r=".51" fill="#000080"/>
<circle cx="96.4" cy="59.3" r=".51" fill="none" stroke="#000080" stroke-width=".21"/>
<circle cx="83.7" cy="59.3" r=".51" fill="#000080"/>
<circle cx="83.7" cy="59.3" r=".51" fill="none" stroke="#000080" stroke-width=".21"/>
<circle cx="71" cy="59.3" r=".51" fill="#000080"/>
<circle cx="71" cy="59.3" r=".51" fill="none" stroke="#000080" stroke-width=".21"/>
<circle cx="58.3" cy="59.3" r=".51" fill="#000080"/>
<circle cx="58.3" cy="59.3" r=".51" fill="none" stroke="#000080" stroke-width=".21"/>
<circle cx="45.6" cy="59.3" r=".51" fill="#000080"/>
<circle cx="45.6" cy="59.3" r=".51" fill="none" stroke="#000080" stroke-width=".21"/>
<circle cx="32.9" cy="59.3" r=".51" fill="#000080"/>
<circle cx="32.9" cy="59.3" r=".51" fill="none" stroke="#000080" stroke-width=".21"/>
<circle cx="20.2" cy="59.3" r=".51" fill="#000080"/>
<circle cx="20.2" cy="59.3" r=".51" fill="none" stroke="#000080" stroke-width=".21"/>
<path d="M231 89.8v2.5h-78.7v43.2" fill="none" stroke="#000080" stroke-width=".25"/>
<circle cx="152.3" cy="133" r=".51" fill="#000080"/>
<circle cx="152.3" cy="133" r=".51" fill="none" stroke="#000080" stroke-width=".21"/>
<circle cx="152.3" cy="130.4" r=".51" fill="#000080"/>
<circle cx="152.3" cy="130.4" r=".51" fill="none" stroke="#000080" stroke-width=".21"/>
<circle cx="152.3" cy="127.9" r=".51" fill="#000080"/>
<circle cx="152.3" cy="127.9" r=".51" fill="none" stroke="#000080" stroke-width=".21"/>
<circle cx="152.3" cy="125.4" r=".51" fill="#000080"/>
<circle cx="152.3" cy="125.4" r=".51" fill="none" stroke="#000080" stroke-width=".21"/>
<circle cx="152.3" cy="122.8" r=".51" fill="#000080"/>
<circle cx="152.3" cy="122.8" r=".51" fill="none" stroke="#000080" stroke-width=".21"/>
<circle cx="152.3" cy="120.3" r=".51" fill="#000080"/>
<circle cx="152.3" cy="120.3" r=".51" fill="none" stroke="#000080" stroke-width=".21"/>
<circle cx="152.3" cy="117.7" r=".51" fill="#000080"/>
<circle cx="152.3" cy="117.7" r=".51" fill="none" stroke="#000080" stroke-width=".21"/>
<circle cx="152.3" cy="115.2" r=".51" fill="#000080"/>
<circle cx="152.3" cy="115.2" r=".51" fill="none" stroke="#000080" stroke-width=".21"/>
<circle cx="152.3" cy="112.7" r=".51" fill="#000080"/>
<circle cx="152.3" cy="112.7" r=".51" fill="none" stroke="#000080" stroke-width=".21"/>
<circle cx="152.3" cy="110.1" r=".51" fill="#000080"/>
<circle cx="152.3" cy="110.1" r=".51" fill="none" stroke="#000080" stroke-width=".21"/>
<circle cx="152.3" cy="107.6" r=".51" fill="#000080"/>
<circle cx="152.3" cy="107.6" r=".51" fill="none" stroke="#000080" stroke-width=".21"/>
<circle cx="152.3" cy="105" r=".51" fill="#000080"/>
<circle cx="152.3" cy="105" r=".51" fill="none" stroke="#000080" stroke-width=".21"/>
<circle cx="152.3" cy="102.5" r=".51" fill="#000080"/>
<circle cx="152.3" cy="102.5" r=".51" fill="none" stroke="#000080" stroke-width=".21"/>
<circle cx="152.3" cy="100" r=".51" fill="#000080"/>
<circle cx="152.3" cy="100" r=".51" fill="none" stroke="#000080" stroke-width=".21"/>
<circle cx="152.3" cy="97.4" r=".51" fill="#000080"/>
<circle cx="152.3" cy="97.4" r=".51" fill="none" stroke="#000080" stroke-width=".21"/>
<circle cx="152.3" cy="94.9" r=".51" fill="#000080"/>
<circle cx="152.3" cy="94.9" r=".51" fill="none" stroke="#000080" stroke-width=".21"/>
<circle cx="152.3" cy="92.3" r=".51" fill="#000080"/>
<circle cx="152.3" cy="92.3" r=".51" fill="none" stroke="#000080" stroke-width=".21"/>
<circle cx="162.4" cy="92.3" r=".51" fill="#000080"/>
<circle cx="162.4" cy="92.3" r=".51" fill="none" stroke="#000080" stroke-width=".21"/>
<circle cx="175.1" cy="92.3" r=".51" fill="#000080"/>
<circle cx="175.1" cy="92.3" r=".51" fill="none" stroke="#000080" stroke-width=".21"/>
<circle cx="187.8" cy="92.3" r=".51" fill="#000080"/>
<circle cx="187.8" cy="92.3" r=".51" fill="none" stroke="#000080" stroke-width=".21"/>
<circle cx="200.5" cy="92.3" r=".51" fill="#000080"/>
<circle cx="200.5" cy="92.3" r=".51" fill="none" stroke="#000080" stroke-width=".21"/>
<circle cx="213.2" cy="92.3" r=".51" fill="#000080"/>
<circle cx="213.2" cy="92.3" r=".51" fill="none" stroke="#000080" stroke-width=".21"/>
<circle cx="225.9" cy="92.3" r=".51" fill="#000080"/>
<circle cx="225.9" cy="92.3" r=".51" fill="none" stroke="#000080" stroke-width=".21"/>
<path d="M65.9 160.9v2.5h40.7v10.2" fill="none" stroke="#000080" stroke-width=".25"/>
<circle cx="71" cy="163.5" r=".51" fill="#000080"/>
<circle cx="71" cy="163.5" r=".51" fill="none" stroke="#000080" stroke-width=".21"/>
<circle cx="83.7" cy="163.5" r=".51" fill="#000080"/>
<circle cx="83.7" cy="163.5" r=".51" fill="none" stroke="#000080" stroke-width=".21"/>
<circle cx="96.4" cy="163.5" r=".51" fill="#000080"/>
<circle cx="96.4" cy="163.5" r=".51" fill="none" stroke="#000080" stroke-width=".21"/>
<circle cx="106.6" cy="163.5" r=".51" fill="#000080"/>
<circle cx="106.6" cy="163.5" r=".51" fill="none" stroke="#000080" stroke-width=".21"/>
<circle cx="106.6" cy="166" r=".51" fill="#000080"/>
<circle cx="106.6" cy="166" r=".51" fill="none" stroke="#000080" stroke-width=".21"/>
<circle cx="106.6" cy="168.5" r=".51" fill="#000080"/>
<circle cx="106.6" cy="168.5" r=".51" fill="none" stroke="#000080" stroke-width=".21"/>
<circle cx="106.6" cy="171.1" r=".51" fill="#000080"/>
<circle cx="106.6" cy="171.1" r=".51" fill="none" stroke="#000080" stroke-width=".21"/>
<path d="M192.9 163.4v2.6h-40.6v7.6" fill="none" stroke="#000080" stroke-width=".25"/>
<circle cx="152.3" cy="171.1" r=".51" fill="#000080"/>
<circle cx="152.3" cy="171.1" r=".51" fill="none" stroke="#000080" stroke-width=".21"/>
<circle cx="152.3" cy="168.5" r=".51" fill="#000080"/>
<circle cx="152.3" cy="168.5" r=".51" fill="none" stroke="#000080" stroke-width=".21"/>
<circle cx="152.3" cy="166" r=".51" fill="#000080"/>
<circle cx="152.3" cy="166" r=".51" fill="none" stroke="#000080" stroke-width=".21"/>
<circle cx="162.4" cy="166" r=".51" fill="#000080"/>
<circle cx="162.4" cy="166" r=".51" fill="none" stroke="#000080" stroke-width=".21"/>
<circle cx="175.1" cy="166" r=".51" fill="#000080"/>
<circle cx="175.1" cy="166" r=".51" fill="none" stroke="#000080" stroke-width=".21"/>
<circle cx="187.8" cy="166" r=".51" fill="#000080"/>
<circle cx="187.8" cy="166" r=".51" fill="none" stroke="#000080" stroke-width=".21"/>
<circle cx="192.9" cy="166" r=".51" fill="#000080"/>
<circle cx="192.9" cy="166" r=".51" fill="none" stroke="#000080" stroke-width=".21"/>
<path d="M246.3 69.5v96.5" fill="none" stroke="#000080" stroke-width=".25"/>
<circle cx="246.3" cy="72" r=".51" fill="#000080"/>
<circle cx="246.3" cy="72" r=".51" fill="none" stroke="#000080" stroke-width=".21"/>
<circle cx="246.3" cy="74.6" r=".51" fill="#000080"/>
<circle cx="246.3" cy="74.6" r=".51" fill="none" stroke="#000080" stroke-width=".21"/>
<circle cx="246.3" cy="77.1" r=".51" fill="#000080"/>
<circle cx="246.3" cy="77.1" r=".51" fill="none" stroke="#000080" stroke-width=".21"/>
<circle cx="246.3" cy="79.6" r=".51" fill="#000080"/>
<circle cx="246.3" cy="79.6" r=".51" fill="none" stroke="#000080" stroke-width=".21"/>
<circle cx="246.3" cy="82.2" r=".51" fill="#000080"/>
<circle cx="246.3" cy="82.2" r=".51" fill="none" stroke="#000080" stroke-width=".21"/>
<circle cx="246.3" cy="84.7" r=".51" fill="#000080"/>
<circle cx="246.3" cy="84.7" r=".51" fill="none" stroke="#000080" stroke-width=".21"/>
<circle cx="246.3" cy="87.3" r=".51" fill="#000080"/>
<circle cx="246.3" cy="87.3" r=".51" fill="none" stroke="#000080" stroke-width=".21"/>
<circle cx="246.3" cy="89.8" r=".51" fill="#000080"/>
<circle cx="246.3" cy="89.8" r=".51" fill="none" stroke="#000080" stroke-width=".21"/>
<circle cx="246.3" cy="92.3" r=".51" fill="#000080"/>
<circle cx="246.3" cy="92.3" r=".51" fill="none" stroke="#000080" stroke-width=".21"/>
<circle cx="246.3" cy="94.9" r=".51" fill="#000080"/>
<circle cx="246.3" cy="94.9" r=".51" fill="none" stroke="#000080" stroke-width=".21"/>
<circle cx="246.3" cy="97.4" r=".51" fill="#000080"/>
<circle cx="246.3" cy="97.4" r=".51" fill="none" stroke="#000080" stroke-width=".21"/>
<circle cx="246.3" cy="100" r=".51" fill="#000080"/>
<circle cx="246.3" cy="100" r=".51" fill="none" stroke="#000080" stroke-width=".21"/>
<circle cx="246.3" cy="102.5" r=".51" fill="#000080"/>
<circle cx="246.3" cy="102.5" r=".51" fill="none" stroke="#000080" stroke-width=".21"/>
<circle cx="246.3" cy="105" r=".51" fill="#000080"/>
<circle cx="246.3" cy="105" r=".51" fill="none" stroke="#000080" stroke-width=".21"/>
<circle cx="246.3" cy="107.6" r=".51" fill="#000080"/>
<circle cx="246.3" cy="107.6" r=".51" fill="none" stroke="#000080" stroke-width=".21"/>
<circle cx="246.3" cy="110.1" r=".51" fill="#000080"/>
<circle cx="246.3" cy="110.1" r=".51" fill="none" stroke="#000080" stroke-width=".21"/>
<circle cx="246.3" cy="112.7" r=".51" fill="#000080"/>
<circle cx="246.3" cy="112.7" r=".51" fill="none" stroke="#000080" stroke-width=".21"/>
<circle cx="246.3" cy="115.2" r=".51" fill="#000080"/>
<circle cx="246.3" cy="115.2" r=".51" fill="none" stroke="#000080" stroke-width=".21"/>
<circle cx="246.3" cy="117.7" r=".51" fill="#000080"/>
<circle cx="246.3" cy="117.7" r=".51" fill="none" stroke="#000080" stroke-width=".21"/>
<circle cx="246.3" cy="120.3" r=".51" fill="#000080"/>
<circle cx="246.3" cy="120.3" r=".51" fill="none" stroke="#000080" stroke-width=".21"/>
<circle cx="246.3" cy="122.8" r=".51" fill="#000080"/>
<circle cx="246.3" cy="122.8" r=".51" fill="none" stroke="#000080" stroke-width=".21"/>
<circle cx="246.3" cy="125.4" r=".51" fill="#000080"/>
<circle cx="246.3" cy="125.4" r=".51" fill="none" stroke="#000080" stroke-width=".21"/>
<circle cx="246.3" cy="127.9" r=".51" fill="#000080"/>
<circle cx="246.3" cy="127.9" r=".51" fill="none" stroke="#000080" stroke-width=".21"/>
<circle cx="246.3" cy="130.4" r=".51" fill="#000080"/>
<circle cx="246.3" cy="130.4" r=".51" fill="none" stroke="#000080" stroke-width=".21"/>
<circle cx="246.3" cy="133" r=".51" fill="#000080"/>
<circle cx="246.3" cy="133" r=".51" fill="none" stroke="#000080" stroke-width=".21"/>
<circle cx="246.3" cy="135.5" r=".51" fill="#000080"/>
<circle cx="246.3" cy="135.5" r=".51" fill="none" stroke="#000080" stroke-width=".21"/>
<circle cx="246.3" cy="138.1" r=".51" fill="#000080"/>
<circle cx="246.3" cy="138.1" r=".51" fill="none" stroke="#000080" stroke-width=".21"/>
<circle cx="246.3" cy="140.6" r=".51" fill="#000080"/>
<circle cx="246.3" cy="140.6" r=".51" fill="none" stroke="#000080" stroke-width=".21"/>
<circle cx="246.3" cy="143.1" r=".51" fill="#000080"/>
<circle cx="246.3" cy="143.1" r=".51" fill="none" stroke="#000080" stroke-width=".21"/>
<circle cx="246.3" cy="145.7" r=".51" fill="#000080"/>
<circle cx="246.3" cy="145.7" r=".51" fill="none" stroke="#000080" stroke-width=".21"/>
<circle cx="246.3" cy="148.2" r=".51" fill="#000080"/>
<circle cx="246.3" cy="148.2" r=".51" fill="none" stroke="#000080" stroke-width=".21"/>
<circle cx="246.3" cy="150.8" r=".51" fill="#000080"/>
<circle cx="246.3" cy="150.8" r=".51" fill="none" stroke="#000080" stroke-width=".21"/>
<circle cx="246.3" cy="153.3" r=".51" fill="#000080"/>
<circle cx="246.3" cy="153.3" r=".51" fill="none" stroke="#000080" stroke-width=".21"/>
<circle cx="246.3" cy="155.8" r=".51" fill="#000080"/>
<circle cx="246.3" cy="155.8" r=".51" fill="none" stroke="#000080" stroke-width=".21"/>
<circle cx="246.3" cy="158.4" r=".51" fill="#000080"/>
<circle cx="246.3" cy="158.4" r=".51" fill="none" stroke="#000080" stroke-width=".21"/>
<circle cx="246.3" cy="160.9" r=".51" fill="#000080"/>
<circle cx="246.3" cy="160.9" r=".51" fill="none" stroke="#000080" stroke-width=".21"/>
<path d="M281.8 66.9v99.1" fill="none" stroke="#000080" stroke-width=".25"/>
<circle cx="281.8" cy="69.5" r=".51" fill="#000080"/>
<circle cx="281.8" cy="69.5" r=".51" fill="none" stroke="#000080" stroke-width=".21"/>
<circle cx="281.8" cy="72" r=".51" fill="#000080"/>
<circle cx="281.8" cy="72" r=".51" fill="none" stroke="#000080" stroke-width=".21"/>
<circle cx="281.8" cy="74.6" r=".51" fill="#000080"/>
<circle cx="281.8" cy="74.6" r=".51" fill="none" stroke="#000080" stroke-width=".21"/>
<circle cx="281.8" cy="77.1" r=".51" fill="#000080"/>
<circle cx="281.8" cy="77.1" r=".51" fill="none" stroke="#000080" stroke-width=".21"/>
<circle cx="281.8" cy="79.6" r=".51" fill="#000080"/>
<circle cx="281.8" cy="79.6" r=".51" fill="none" stroke="#000080" stroke-width=".21"/>
<circle cx="281.8" cy="82.2" r=".51" fill="#000080"/>
<circle cx="281.8" cy="82.2" r=".51" fill="none" stroke="#000080" stroke-width=".21"/>
<circle cx="281.8" cy="84.7" r=".51" fill="#000080"/>
<circle cx="281.8" cy="84.7" r=".51" fill="none" stroke="#000080" stroke-width=".21"/>
<circle cx="281.8" cy="87.3" r=".51" fill="#000080"/>
<circle cx="281.8" cy="87.3" r=".51" fill="none" stroke="#000080" stroke-width=".21"/>
<circle cx="281.8" cy="89.8" r=".51" fill="#000080"/>
<circle cx="281.8" cy="89.8" r=".51" fill="none" stroke="#000080" stroke-width=".21"/>
<circle cx="281.8" cy="92.3" r=".51" fill="#000080"/>
<circle cx="281.8" cy="92.3" r=".51" fill="none" stroke="#000080" stroke-width=".21"/>
<circle cx="281.8" cy="94.9" r=".51" fill="#000080"/>
<circle cx="281.8" cy="94.9" r=".51" fill="none" stroke="#000080" stroke-width=".21"/>
<circle cx="281.8" cy="97.4" r=".51" fill="#000080"/>
<circle cx="281.8" cy="97.4" r=".51" fill="none" stroke="#000080" stroke-width=".21"/>
<circle cx="281.8" cy="100" r=".51" fill="#000080"/>
<circle cx="281.8" cy="100" r=".51" fill="none" stroke="#000080" stroke-width=".21"/>
<circle cx="281.8" cy="102.5" r=".51" fill="#000080"/>
<circle cx="281.8" cy="102.5" r=".51" fill="none" stroke="#000080" stroke-width=".21"/>
<circle cx="281.8" cy="105" r=".51" fill="#000080"/>
<circle cx="281.8" cy="105" r=".51" fill="none" stroke="#000080" stroke-width=".21"/>
<circle cx="281.8" cy="107.6" r=".51" fill="#000080"/>
<circle cx="281.8" cy="107.6" r=".51" fill="none" stroke="#000080" stroke-width=".21"/>
<circle cx="281.8" cy="110.1" r=".51" fill="#000080"/>
<circle cx="281.8" cy="110.1" r=".51" fill="none" stroke="#000080" stroke-width=".21"/>
<circle cx="281.8" cy="112.7" r=".51" fill="#000080"/>
<circle cx="281.8" cy="112.7" r=".51" fill="none" stroke="#000080" stroke-width=".21"/>
<circle cx="281.8" cy="115.2" r=".51" fill="#000080"/>
<circle cx="281.8" cy="115.2" r=".51" fill="none" stroke="#000080" stroke-width=".21"/>
<circle cx="281.8" cy="117.7" r=".51" fill="#000080"/>
<circle cx="281.8" cy="117.7" r=".51" fill="none" stroke="#000080" stroke-width=".21"/>
<circle cx="281.8" cy="120.3" r=".51" fill="#000080"/>
<circle cx="281.8" cy="120.3" r=".51" fill="none" stroke="#000080" stroke-width=".21"/>
<circle cx="281.8" cy="122.8" r=".51" fill="#000080"/>
<circle cx="281.8" cy="122.8" r=".51" fill="none" stroke="#000080" stroke-width=".21"/>
<circle cx="281.8" cy="125.4" r=".51" fill="#000080"/>
<circle cx="281.8" cy="125.4" r=".51" fill="none" stroke="#000080" stroke-width=".21"/>
<circle cx="281.8" cy="127.9" r=".51" fill="#000080"/>
<circle cx="281.8" cy="127.9" r=".51" fill="none" stroke="#000080" stroke-width=".21"/>
<circle cx="281.8" cy="130.4" r=".51" fill="#000080"/>
<circle cx="281.8" cy="130.4" r=".51" fill="none" stroke="#000080" stroke-width=".21"/>
<circle cx="281.8" cy="133" r=".51" fill="#000080"/>
<circle cx="281.8" cy="133" r=".51" fill="none" stroke="#000080" stroke-width=".21"/>
<circle cx="281.8" cy="135.5" r=".51" fill="#000080"/>
<circle cx="281.8" cy="135.5" r=".51" fill="none" stroke="#000080" stroke-width=".21"/>
<circle cx="281.8" cy="138.1" r=".51" fill="#000080"/>
<circle cx="281.8" cy="138.1" r=".51" fill="none" stroke="#000080" stroke-width=".21"/>
<circle cx="281.8" cy="140.6" r=".51" fill="#000080"/>
<circle cx="281.8" cy="140.6" r=".51" fill="none" stroke="#000080" stroke-width=".21"/>
<circle cx="281.8" cy="143.1" r=".51" fill="#000080"/>
<circle cx="281.8" cy="143.1" r=".51" fill="none" stroke="#000080" stroke-width=".21"/>
<circle cx="281.8" cy="145.7" r=".51" fill="#000080"/>
<circle cx="281.8" cy="145.7" r=".51" fill="none" stroke="#000080" stroke-width=".21"/>
<circle cx="281.8" cy="148.2" r=".51" fill="#000080"/>
<circle cx="281.8" cy="148.2" r=".51" fill="none" stroke="#000080" stroke-width=".21"/>
<circle cx="281.8" cy="150.8" r=".51" fill="#000080"/>
<circle cx="281.8" cy="150.8" r=".51" fill="none" stroke="#000080" stroke-width=".21"/>
<circle cx="281.8" cy="153.3" r=".51" fill="#000080"/>
<circle cx="281.8" cy="153.3" r=".51" fill="none" stroke="#000080" stroke-width=".21"/>
<circle cx="281.8" cy="155.8" r=".51" fill="#000080"/>
<circle cx="281.8" cy="155.8" r=".51" fill="none" stroke="#000080" stroke-width=".21"/>
<circle cx="281.8" cy="158.4" r=".51" fill="#000080"/>
<circle cx="281.8" cy="158.4" r=".51" fill="none" stroke="#000080" stroke-width=".21"/>
<circle cx="281.8" cy="160.9" r=".51" fill="#000080"/>
<circle cx="281.8" cy="160.9" r=".51" fill="none" stroke="#000080" stroke-width=".21"/>
<path d="M246.3 64.4h-5.1v2.5M78.6 89.8v2.5h28v17.8" fill="none" stroke="#000080" stroke-width=".25"/>
<circle cx="106.6" cy="107.6" r=".51" fill="#000080"/>
<circle cx="106.6" cy="107.6" r=".51" fill="none" stroke="#000080" stroke-width=".21"/>
<circle cx="106.6" cy="105" r=".51" fill="#000080"/>
<circle cx="106.6" cy="105" r=".51" fill="none" stroke="#000080" stroke-width=".21"/>
<circle cx="96.4" cy="92.3" r=".51" fill="#000080"/>
<circle cx="96.4" cy="92.3" r=".51" fill="none" stroke="#000080" stroke-width=".21"/>
<circle cx="83.7" cy="92.3" r=".51" fill="#000080"/>
<circle cx="83.7" cy="92.3" r=".51" fill="none" stroke="#000080" stroke-width=".21"/>
<path d="M192.9 166h5.1M213.2 163.4v2.6h-5" fill="none" stroke="#000080" stroke-width=".25"/>
<circle cx="192.9" cy="166" r=".51" fill="#000080"/>
<circle cx="192.9" cy="166" r=".51" fill="none" stroke="#000080" stroke-width=".21"/>
<path d="M101.5 130.4v7.6" fill="none" stroke="#000080" stroke-width=".25"/>
<circle cx="101.5" cy="130.4" r=".51" fill="#000080"/>
<circle cx="101.5" cy="130.4" r=".51" fill="none" stroke="#000080" stroke-width=".21"/>
<path d="M101.5 115.2v2.5" fill="none" stroke="#000080" stroke-width=".25"/>
<circle cx="101.5" cy="115.2" r=".51" fill="#000080"/>
<circle cx="101.5" cy="115.2" r=".51" fill="none" stroke="#000080" stroke-width=".21"/>
<path d="M96.4 115.2v20.3h10.2" fill="none" stroke="#000080" stroke-width=".25"/>
<circle cx="96.4" cy="115.2" r=".51" fill="#000080"/>
<circle cx="96.4" cy="115.2" r=".51" fill="none" stroke="#000080" stroke-width=".21"/>
<path d="M101.5 127.9v2.5h5.1" fill="none" stroke="#000080" stroke-width=".25"/>
<circle cx="101.5" cy="130.4" r=".51" fill="#000080"/>
<circle cx="101.5" cy="130.4" r=".51" fill="none" stroke="#000080" stroke-width=".21"/>
<path d="M162.4 61.8v2.6" fill="none" stroke="#000080" stroke-width=".25"/>
<circle cx="162.4" cy="61.9" r=".51" fill="#000080"/>
<circle cx="162.4" cy="61.9" r=".51" fill="none" stroke="#000080" stroke-width=".21"/>
<path d="M109.1 49.1v10.2" fill="none" stroke="#000080" stroke-width=".25"/>
<circle cx="109.1" cy="59.3" r=".51" fill="#000080"/>
<circle cx="109.1" cy="59.3" r=".51" fill="none" stroke="#000080" stroke-width=".21"/>
<circle cx="109.1" cy="56.8" r=".51" fill="#000080"/>
<circle cx="109.1" cy="56.8" r=".51" fill="none" stroke="#000080" stroke-width=".21"/>
<circle cx="109.1" cy="54.2" r=".51" fill="#000080"/>
<circle cx="109.1" cy="54.2" r=".51" fill="none" stroke="#000080" stroke-width=".21"/>
<circle cx="109.1" cy="51.7" r=".51" fill="#000080"/>
<circle cx="109.1" cy="51.7" r=".51" fill="none" stroke="#000080" stroke-width=".21"/>
<path d="M231 28.8v2.6h-81.3v25.4" fill="none" stroke="#000080" stroke-width=".25"/>
<circle cx="149.7" cy="54.2" r=".51" fill="#000080"/>
<circle cx="149.7" cy="54.2" r=".51" fill="none" stroke="#000080" stroke-width=".21"/>
<circle cx="149.7" cy="51.7" r=".51" fill="#000080"/>
<circle cx="149.7" cy="51.7" r=".51" fill="none" stroke="#000080" stroke-width=".21"/>
<circle cx="149.7" cy="49.1" r=".51" fill="#000080"/>
<circle cx="149.7" cy="49.1" r=".51" fill="none" stroke="#000080" stroke-width=".21"/>
<circle cx="149.7" cy="46.6" r=".51" fill="#000080"/>
<circle cx="149.7" cy="46.6" r=".51" fill="none" stroke="#000080" stroke-width=".21"/>
<circle cx="149.7" cy="44.1" r=".51" fill="#000080"/>
<circle cx="149.7" cy="44.1" r=".51" fill="none" stroke="#000080" stroke-width=".21"/>
<circle cx="149.7" cy="41.5" r=".51" fill="#000080"/>
<circle cx="149.7" cy="41.5" r=".51" fill="none" stroke="#000080" stroke-width=".21"/>
<circle cx="162.4" cy="31.4" r=".51" fill="#000080"/>
<circle cx="162.4" cy="31.4" r=".51" fill="none" stroke="#000080" stroke-width=".21"/>
<circle cx="175.1" cy="31.4" r=".51" fill="#000080"/>
<circle cx="175.1" cy="31.4" r=".51" fill="none" stroke="#000080" stroke-width=".21"/>
<circle cx="187.8" cy="31.4" r=".51" fill="#000080"/>
<circle cx="187.8" cy="31.4" r=".51" fill="none" stroke="#000080" stroke-width=".21"/>
<circle cx="200.5" cy="31.4" r=".51" fill="#000080"/>
<circle cx="200.5" cy="31.4" r=".51" fill="none" stroke="#000080" stroke-width=".21"/>
<circle cx="213.2" cy="31.4" r=".51" fill="#000080"/>
<circle cx="213.2" cy="31.4" r=".51" fill="none" stroke="#000080" stroke-width=".21"/>
<circle cx="225.9" cy="31.4" r=".51" fill="#000080"/>
<circle cx="225.9" cy="31.4" r=".51" fill="none" stroke="#000080" stroke-width=".21"/>
<path d="M15.1 112.6v2.6h91.5v10.1" fill="none" stroke="#000080" stroke-width=".25"/>
<circle cx="106.6" cy="122.8" r=".51" fill="#000080"/>
<circle cx="106.6" cy="122.8" r=".51" fill="none" stroke="#000080" stroke-width=".21"/>
<circle cx="106.6" cy="120.3" r=".51" fill="#000080"/>
<circle cx="106.6" cy="120.3" r=".51" fill="none" stroke="#000080" stroke-width=".21"/>
<circle cx="106.6" cy="117.7" r=".51" fill="#000080"/>
<circle cx="106.6" cy="117.7" r=".51" fill="none" stroke="#000080" stroke-width=".21"/>
<circle cx="106.6" cy="115.2" r=".51" fill="#000080"/>
<circle cx="106.6" cy="115.2" r=".51" fill="none" stroke="#000080" stroke-width=".21"/>
<circle cx="101.5" cy="115.2" r=".51" fill="#000080"/>
<circle cx="101.5" cy="115.2" r=".51" fill="none" stroke="#000080" stroke-width=".21"/>
<circle cx="96.4" cy="115.2" r=".51" fill="#000080"/>
<circle cx="96.4" cy="115.2" r=".51" fill="none" stroke="#000080" stroke-width=".21"/>
<circle cx="83.7" cy="115.2" r=".51" fill="#000080"/>
<circle cx="83.7" cy="115.2" r=".51" fill="none" stroke="#000080" stroke-width=".21"/>
<circle cx="71" cy="115.2" r=".51" fill="#000080"/>
<circle cx="71" cy="115.2" r=".51" fill="none" stroke="#000080" stroke-width=".21"/>
<circle cx="58.3" cy="115.2" r=".51" fill="#000080"/>
<circle cx="58.3" cy="115.2" r=".51" fill="none" stroke="#000080" stroke-width=".21"/>
<circle cx="45.6" cy="115.2" r=".51" fill="#000080"/>
<circle cx="45.6" cy="115.2" r=".51" fill="none" stroke="#000080" stroke-width=".21"/>
<circle cx="32.9" cy="115.2" r=".51" fill="#000080"/>
<circle cx="32.9" cy="115.2" r=".51" fill="none" stroke="#000080" stroke-width=".21"/>
<circle cx="20.2" cy="115.2" r=".51" fill="#000080"/>
<circle cx="20.2" cy="115.2" r=".51" fill="none" stroke="#000080" stroke-width=".21"/>
<path d="M167.5 59.3v2.5h-17.8v2.6" fill="none" stroke="#000080" stroke-width=".25"/>
<circle cx="149.7" cy="61.9" r=".51" fill="#000080"/>
<circle cx="149.7" cy="61.9" r=".51" fill="none" stroke="#000080" stroke-width=".21"/>
<circle cx="162.4" cy="61.9" r=".51" fill="#000080"/>
<circle cx="162.4" cy="61.9" r=".51" fill="none" stroke="#000080" stroke-width=".21"/>
<use href="#words"/>
</svg>
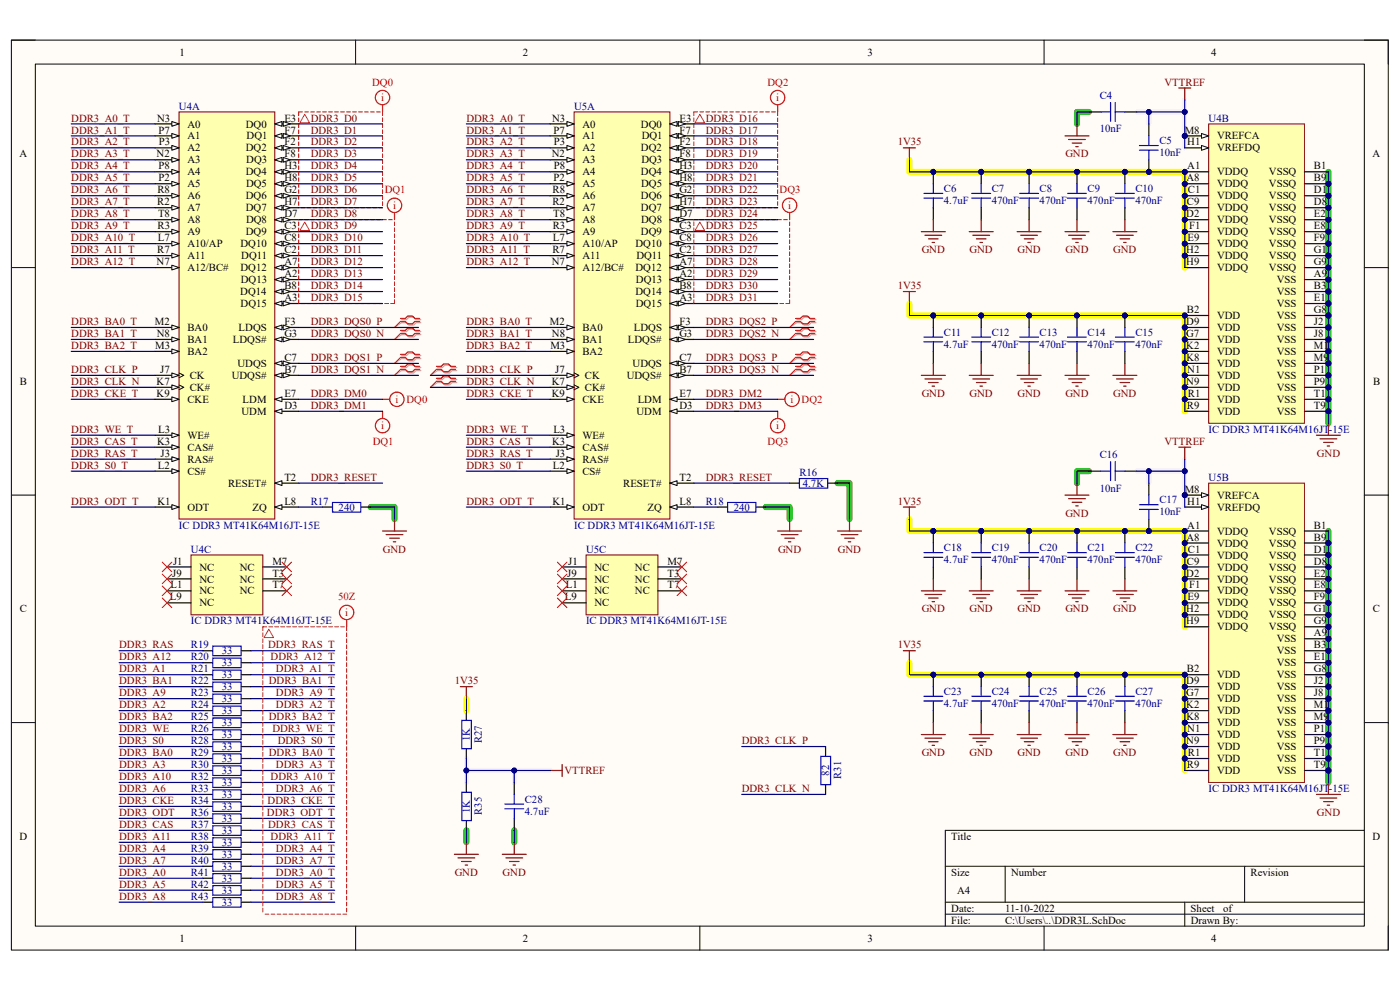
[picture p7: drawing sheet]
<svg xmlns="http://www.w3.org/2000/svg" width="297mm" height="210mm" viewBox="0 0 297 210" stroke-linecap="round" stroke-linejoin="round" font-family="sans-serif">
<defs><g id="words">
<g font-size="2.3">
<text x="38.1" y="11.8">1</text>
<text x="110.9" y="11.8">2</text>
<text x="184" y="11.8">3</text>
<text x="256.9" y="11.8">4</text>
<text x="33.3" y="25.8">N3</text>
<text x="33.6" y="28.3">P7</text>
<text x="39.8" y="27.1">A0</text>
<text x="39.8" y="29.6">A1</text>
<text x="52.2" y="27.1">DQ0</text>
<text x="52.3" y="29.6">DQ1</text>
<text x="60.3" y="25.8">E3</text>
<text x="60.3" y="28.3">F7</text>
<text x="117.1" y="25.8">N3</text>
<text x="117.4" y="28.3">P7</text>
<text x="123.6" y="27.1">A0</text>
<text x="123.6" y="29.6">A1</text>
<text x="136" y="27.1">DQ0</text>
<text x="136.1" y="29.6">DQ1</text>
<text x="144.1" y="25.8">E3</text>
<text x="144.1" y="28.3">F7</text>
<text x="251.3" y="28.3">M8</text>
<text x="258.2" y="29.6">VREFCA</text>
<text x="4.1" y="33.4">A</text>
<text x="33.2" y="33.4">N2</text>
<text x="33.7" y="35.9">P8</text>
<text x="33.7" y="30.9">P3</text>
<text x="39.8" y="34.7">A3</text>
<text x="39.8" y="32.1">A2</text>
<text x="52.2" y="32.1">DQ2</text>
<text x="52.2" y="34.7">DQ3</text>
<text x="60.3" y="30.9">F2</text>
<text x="60.3" y="33.4">F8</text>
<text x="60.3" y="35.9">H3</text>
<text x="117.1" y="33.4">N2</text>
<text x="117.5" y="35.9">P8</text>
<text x="117.5" y="30.9">P3</text>
<text x="123.6" y="34.7">A3</text>
<text x="123.6" y="32.1">A2</text>
<text x="136" y="32.1">DQ2</text>
<text x="136.1" y="34.7">DQ3</text>
<text x="144.1" y="30.9">F2</text>
<text x="144.1" y="33.4">F8</text>
<text x="144.1" y="35.9">H3</text>
<text x="251.9" y="35.9">A1</text>
<text x="251.9" y="30.9">H1</text>
<text x="258.2" y="32.1">VREFDQ</text>
<text x="278.8" y="35.9">B1</text>
<text x="291.2" y="33.4">A</text>
<text x="33.4" y="41">R8</text>
<text x="33.6" y="38.5">P2</text>
<text x="39.8" y="39.8">A5</text>
<text x="39.8" y="37.2">A4</text>
<text x="52.2" y="37.2">DQ4</text>
<text x="52.2" y="39.8">DQ5</text>
<text x="60.3" y="41">G2</text>
<text x="60.3" y="38.5">H8</text>
<text x="117.2" y="41">R8</text>
<text x="117.4" y="38.5">P2</text>
<text x="123.6" y="39.8">A5</text>
<text x="123.6" y="37.2">A4</text>
<text x="136" y="37.2">DQ4</text>
<text x="136" y="39.8">DQ5</text>
<text x="144.1" y="41">G2</text>
<text x="144.1" y="38.5">H8</text>
<text x="251.7" y="38.5">A8</text>
<text x="252" y="41">C1</text>
<text x="258.2" y="37.2">VDDQ</text>
<text x="258.2" y="39.8">VDDQ</text>
<text x="269.2" y="37.2">VSSQ</text>
<text x="269.2" y="39.8">VSSQ</text>
<text x="278.8" y="38.5">B9</text>
<text x="278.8" y="41">D1</text>
<text x="33.4" y="43.6">R2</text>
<text x="33.5" y="46.1">T8</text>
<text x="39.8" y="44.8">A7</text>
<text x="39.8" y="42.3">A6</text>
<text x="39.8" y="47.4">A8</text>
<text x="52.2" y="42.3">DQ6</text>
<text x="52.2" y="44.8">DQ7</text>
<text x="52.2" y="47.4">DQ8</text>
<text x="60.3" y="46.1">D7</text>
<text x="60.3" y="43.6">H7</text>
<text x="117.2" y="43.6">R2</text>
<text x="117.3" y="46.1">T8</text>
<text x="123.6" y="44.8">A7</text>
<text x="123.6" y="42.3">A6</text>
<text x="123.6" y="47.4">A8</text>
<text x="136" y="42.3">DQ6</text>
<text x="136" y="44.8">DQ7</text>
<text x="136" y="47.4">DQ8</text>
<text x="144.1" y="46.1">D7</text>
<text x="144.1" y="43.6">H7</text>
<text x="251.7" y="46.1">D2</text>
<text x="251.8" y="43.6">C9</text>
<text x="258.2" y="42.3">VDDQ</text>
<text x="258.2" y="44.8">VDDQ</text>
<text x="258.2" y="47.4">VDDQ</text>
<text x="269.2" y="42.3">VSSQ</text>
<text x="269.2" y="44.8">VSSQ</text>
<text x="269.2" y="47.4">VSSQ</text>
<text x="278.8" y="43.6">D8</text>
<text x="278.8" y="46.1">E2</text>
<text x="33.4" y="53.7">R7</text>
<text x="33.4" y="48.6">R3</text>
<text x="33.5" y="51.2">L7</text>
<text x="39.8" y="52.5">A10/AP</text>
<text x="39.8" y="49.9">A9</text>
<text x="51" y="52.5">DQ10</text>
<text x="52.2" y="49.9">DQ9</text>
<text x="60.3" y="53.7">C2</text>
<text x="60.3" y="48.6">C3</text>
<text x="60.3" y="51.2">C8</text>
<text x="117.2" y="53.7">R7</text>
<text x="117.3" y="48.6">R3</text>
<text x="117.3" y="51.2">L7</text>
<text x="123.6" y="52.5">A10/AP</text>
<text x="123.6" y="49.9">A9</text>
<text x="134.8" y="52.5">DQ10</text>
<text x="136" y="49.9">DQ9</text>
<text x="144.1" y="53.7">C2</text>
<text x="144.1" y="48.6">C3</text>
<text x="144.1" y="51.2">C8</text>
<text x="251.7" y="53.7">H2</text>
<text x="251.9" y="51.2">E9</text>
<text x="252.3" y="48.6">F1</text>
<text x="258.2" y="52.5">VDDQ</text>
<text x="258.2" y="49.9">VDDQ</text>
<text x="269.2" y="49.9">VSSQ</text>
<text x="269.2" y="52.5">VSSQ</text>
<text x="278.8" y="48.6">E8</text>
<text x="278.8" y="51.2">F9</text>
<text x="278.8" y="53.7">G1</text>
<text x="33.2" y="56.3">N7</text>
<text x="39.8" y="57.5">A12/BC#</text>
<text x="39.8" y="55">A11</text>
<text x="51" y="57.5">DQ12</text>
<text x="51.2" y="55">DQ11</text>
<text x="60.3" y="58.8">A2</text>
<text x="60.3" y="56.3">A7</text>
<text x="117.1" y="56.3">N7</text>
<text x="123.6" y="57.5">A12/BC#</text>
<text x="123.6" y="55">A11</text>
<text x="134.8" y="57.5">DQ12</text>
<text x="135" y="55">DQ11</text>
<text x="144.1" y="58.8">A2</text>
<text x="144.1" y="56.3">A7</text>
<text x="251.7" y="56.3">H9</text>
<text x="258.2" y="55">VDDQ</text>
<text x="258.2" y="57.5">VDDQ</text>
<text x="269.2" y="55">VSSQ</text>
<text x="269.2" y="57.5">VSSQ</text>
<text x="278.8" y="58.8">A9</text>
<text x="278.8" y="56.3">G9</text>
<text x="51" y="62.6">DQ14</text>
<text x="51.1" y="65.2">DQ15</text>
<text x="51.1" y="60.1">DQ13</text>
<text x="60.3" y="63.9">A3</text>
<text x="60.3" y="61.3">B8</text>
<text x="134.8" y="62.6">DQ14</text>
<text x="134.9" y="65.2">DQ15</text>
<text x="134.9" y="60.1">DQ13</text>
<text x="144.1" y="63.9">A3</text>
<text x="144.1" y="61.3">B8</text>
<text x="270.9" y="60.1">VSS</text>
<text x="270.9" y="62.6">VSS</text>
<text x="270.9" y="65.2">VSS</text>
<text x="278.8" y="61.3">B3</text>
<text x="278.8" y="63.9">E1</text>
<text x="32.9" y="69">M2</text>
<text x="33.3" y="71.5">N8</text>
<text x="39.8" y="70.2">BA0</text>
<text x="50.6" y="70.2">LDQS</text>
<text x="60.3" y="69">F3</text>
<text x="60.3" y="71.5">G3</text>
<text x="116.7" y="69">M2</text>
<text x="117.1" y="71.5">N8</text>
<text x="123.6" y="70.2">BA0</text>
<text x="134.5" y="70.2">LDQS</text>
<text x="144.1" y="69">F3</text>
<text x="144.1" y="71.5">G3</text>
<text x="251.7" y="69">D9</text>
<text x="251.7" y="71.5">G7</text>
<text x="251.8" y="66.4">B2</text>
<text x="258.2" y="67.7">VDD</text>
<text x="258.2" y="70.2">VDD</text>
<text x="270.9" y="67.7">VSS</text>
<text x="270.9" y="70.2">VSS</text>
<text x="278.8" y="66.4">G8</text>
<text x="278.8" y="69">J2</text>
<text x="278.8" y="71.5">J8</text>
<text x="32.9" y="74">M3</text>
<text x="39.8" y="75.3">BA2</text>
<text x="39.8" y="72.8">BA1</text>
<text x="49.4" y="72.8">LDQS#</text>
<text x="50.4" y="77.9">UDQS</text>
<text x="60.3" y="76.6">C7</text>
<text x="116.8" y="74">M3</text>
<text x="123.6" y="75.3">BA2</text>
<text x="123.6" y="72.8">BA1</text>
<text x="133.2" y="72.8">LDQS#</text>
<text x="134.2" y="77.9">UDQS</text>
<text x="144.1" y="76.6">C7</text>
<text x="251.7" y="74">K2</text>
<text x="251.7" y="76.6">K8</text>
<text x="258.2" y="72.8">VDD</text>
<text x="258.2" y="75.3">VDD</text>
<text x="258.2" y="77.9">VDD</text>
<text x="270.9" y="72.8">VSS</text>
<text x="270.9" y="75.3">VSS</text>
<text x="270.9" y="77.9">VSS</text>
<text x="278.8" y="74">M1</text>
<text x="278.8" y="76.6">M9</text>
<text x="4.2" y="81.7">B</text>
<text x="33.2" y="81.7">K7</text>
<text x="34" y="79.1">J7</text>
<text x="40.3" y="80.4">CK</text>
<text x="40.3" y="82.9">CK#</text>
<text x="49.1" y="80.4">UDQS#</text>
<text x="60.3" y="79.1">B7</text>
<text x="117.1" y="81.7">K7</text>
<text x="117.8" y="79.1">J7</text>
<text x="124.1" y="80.4">CK</text>
<text x="124.1" y="82.9">CK#</text>
<text x="133" y="80.4">UDQS#</text>
<text x="144.1" y="79.1">B7</text>
<text x="251.7" y="81.7">N9</text>
<text x="251.9" y="79.1">N1</text>
<text x="258.2" y="80.4">VDD</text>
<text x="258.2" y="82.9">VDD</text>
<text x="270.9" y="80.4">VSS</text>
<text x="270.9" y="82.9">VSS</text>
<text x="278.8" y="79.1">P1</text>
<text x="278.8" y="81.7">P9</text>
<text x="291.3" y="81.7">B</text>
<text x="33.2" y="84.2">K9</text>
<text x="39.8" y="85.5">CKE</text>
<text x="51.2" y="88">UDM</text>
<text x="51.5" y="85.5">LDM</text>
<text x="60.3" y="86.7">D3</text>
<text x="60.3" y="84.2">E7</text>
<text x="117.1" y="84.2">K9</text>
<text x="123.6" y="85.5">CKE</text>
<text x="135" y="88">UDM</text>
<text x="135.3" y="85.5">LDM</text>
<text x="144.1" y="86.7">D3</text>
<text x="144.1" y="84.2">E7</text>
<text x="251.8" y="86.7">R9</text>
<text x="252" y="84.2">R1</text>
<text x="258.2" y="85.5">VDD</text>
<text x="258.2" y="88">VDD</text>
<text x="270.9" y="85.5">VSS</text>
<text x="270.9" y="88">VSS</text>
<text x="278.8" y="84.2">T1</text>
<text x="278.8" y="86.7">T9</text>
<text x="33.3" y="94.4">K3</text>
<text x="33.6" y="91.8">L3</text>
<text x="39.8" y="95.6">CAS#</text>
<text x="39.8" y="93.1">WE#</text>
<text x="117.1" y="94.4">K3</text>
<text x="117.4" y="91.8">L3</text>
<text x="123.6" y="95.6">CAS#</text>
<text x="123.6" y="93.1">WE#</text>
<text x="33.5" y="99.4">L2</text>
<text x="34.1" y="96.9">J3</text>
<text x="39.8" y="98.2">RAS#</text>
<text x="39.8" y="100.7">CS#</text>
<text x="60.3" y="102">T2</text>
<text x="117.3" y="99.4">L2</text>
<text x="117.9" y="96.9">J3</text>
<text x="123.6" y="98.2">RAS#</text>
<text x="123.6" y="100.7">CS#</text>
<text x="144.1" y="102">T2</text>
<text x="33.4" y="107.1">K1</text>
<text x="48.4" y="103.3">RESET#</text>
<text x="60.3" y="107.1">L8</text>
<text x="117.2" y="107.1">K1</text>
<text x="132.2" y="103.3">RESET#</text>
<text x="144.1" y="107.1">L8</text>
<text x="251.3" y="104.5">M8</text>
<text x="251.9" y="107.1">H1</text>
<text x="258.2" y="105.8">VREFCA</text>
<text x="39.8" y="108.3">ODT</text>
<text x="53.6" y="108.3">ZQ</text>
<text x="123.6" y="108.3">ODT</text>
<text x="137.4" y="108.3">ZQ</text>
<text x="251.9" y="112.1">A1</text>
<text x="258.2" y="113.4">VDDQ</text>
<text x="258.2" y="108.3">VREFDQ</text>
<text x="269.2" y="113.4">VSSQ</text>
<text x="278.8" y="112.1">B1</text>
<text x="36.7" y="119.8">J1</text>
<text x="57.8" y="119.8">M7</text>
<text x="120.6" y="119.8">J1</text>
<text x="141.6" y="119.8">M7</text>
<text x="251.7" y="114.7">A8</text>
<text x="251.8" y="119.8">C9</text>
<text x="252" y="117.2">C1</text>
<text x="258.2" y="116">VDDQ</text>
<text x="258.2" y="118.5">VDDQ</text>
<text x="269.2" y="116">VSSQ</text>
<text x="269.2" y="118.5">VSSQ</text>
<text x="278.8" y="114.7">B9</text>
<text x="278.8" y="117.2">D1</text>
<text x="278.8" y="119.8">D8</text>
<text x="36.2" y="124.8">L1</text>
<text x="36.5" y="122.3">J9</text>
<text x="42.3" y="121">NC</text>
<text x="42.3" y="123.6">NC</text>
<text x="50.9" y="121">NC</text>
<text x="50.9" y="123.6">NC</text>
<text x="57.8" y="122.3">T3</text>
<text x="57.8" y="124.8">T7</text>
<text x="120.1" y="124.8">L1</text>
<text x="120.4" y="122.3">J9</text>
<text x="126.1" y="121">NC</text>
<text x="126.1" y="123.6">NC</text>
<text x="134.7" y="121">NC</text>
<text x="134.7" y="123.6">NC</text>
<text x="141.6" y="122.3">T3</text>
<text x="141.6" y="124.8">T7</text>
<text x="251.7" y="122.3">D2</text>
<text x="252.3" y="124.8">F1</text>
<text x="258.2" y="121">VDDQ</text>
<text x="258.2" y="123.6">VDDQ</text>
<text x="269.2" y="121">VSSQ</text>
<text x="269.2" y="123.6">VSSQ</text>
<text x="278.8" y="122.3">E2</text>
<text x="278.8" y="124.8">E8</text>
<text x="4.2" y="129.9">C</text>
<text x="36" y="127.4">L9</text>
<text x="42.3" y="126.1">NC</text>
<text x="42.3" y="128.7">NC</text>
<text x="50.9" y="126.1">NC</text>
<text x="119.8" y="127.4">L9</text>
<text x="126.1" y="126.1">NC</text>
<text x="126.1" y="128.7">NC</text>
<text x="134.7" y="126.1">NC</text>
<text x="251.7" y="129.9">H2</text>
<text x="251.9" y="127.4">E9</text>
<text x="258.2" y="128.7">VDDQ</text>
<text x="258.2" y="126.1">VDDQ</text>
<text x="258.2" y="131.2">VDDQ</text>
<text x="269.2" y="126.1">VSSQ</text>
<text x="269.2" y="128.7">VSSQ</text>
<text x="269.2" y="131.2">VSSQ</text>
<text x="278.8" y="127.4">F9</text>
<text x="278.8" y="129.9">G1</text>
<text x="291.3" y="129.9">C</text>
<text x="251.7" y="132.5">H9</text>
<text x="258.2" y="133.7">VDDQ</text>
<text x="269.2" y="133.7">VSSQ</text>
<text x="270.9" y="136.3">VSS</text>
<text x="278.8" y="135">A9</text>
<text x="278.8" y="137.5">B3</text>
<text x="278.8" y="132.5">G9</text>
<text x="251.8" y="142.6">B2</text>
<text x="258.2" y="143.9">VDD</text>
<text x="270.9" y="138.8">VSS</text>
<text x="270.9" y="141.4">VSS</text>
<text x="270.9" y="143.9">VSS</text>
<text x="278.8" y="140.1">E1</text>
<text x="278.8" y="142.6">G8</text>
<text x="251.7" y="145.2">D9</text>
<text x="251.7" y="147.7">G7</text>
<text x="258.2" y="146.4">VDD</text>
<text x="258.2" y="149">VDD</text>
<text x="270.9" y="146.4">VSS</text>
<text x="270.9" y="149">VSS</text>
<text x="278.8" y="145.2">J2</text>
<text x="278.8" y="147.7">J8</text>
<text x="251.7" y="150.2">K2</text>
<text x="251.7" y="152.8">K8</text>
<text x="251.9" y="155.3">N1</text>
<text x="258.2" y="151.5">VDD</text>
<text x="258.2" y="154.1">VDD</text>
<text x="270.9" y="151.5">VSS</text>
<text x="270.9" y="154.1">VSS</text>
<text x="278.8" y="150.2">M1</text>
<text x="278.8" y="152.8">M9</text>
<text x="278.8" y="155.3">P1</text>
<text x="251.7" y="157.9">N9</text>
<text x="252" y="160.4">R1</text>
<text x="258.2" y="156.6">VDD</text>
<text x="258.2" y="159.1">VDD</text>
<text x="258.2" y="161.7">VDD</text>
<text x="270.9" y="156.6">VSS</text>
<text x="270.9" y="159.1">VSS</text>
<text x="270.9" y="161.7">VSS</text>
<text x="278.8" y="157.9">P9</text>
<text x="278.8" y="160.4">T1</text>
<text x="251.8" y="162.9">R9</text>
<text x="258.2" y="164.2">VDD</text>
<text x="270.9" y="164.2">VSS</text>
<text x="278.8" y="162.9">T9</text>
<text x="4.1" y="178.2">D</text>
<text x="201.8" y="178.2">Title</text>
<text x="291.2" y="178.2">D</text>
<text x="201.8" y="185.8">Size</text>
<text x="214.5" y="185.8">Number</text>
<text x="265.3" y="185.8">Revision</text>
<text x="203.1" y="189.6">A4</text>
<text x="201.8" y="193.4">Date:</text>
<text x="201.8" y="196">File:</text>
<text x="213.2" y="196">C:\Users\..\DDR3L.SchDoc</text>
<text x="213.2" y="193.4">11-10-2022</text>
<text x="252.6" y="193.4">Sheet</text>
<text x="252.6" y="196">Drawn By:</text>
<text x="259.5" y="193.4">of</text>
<text x="38.1" y="199.8">1</text>
<text x="110.9" y="199.8">2</text>
<text x="184" y="199.8">3</text>
<text x="256.9" y="199.8">4</text>
</g>
<g font-size="2.3" fill="#000080">
<text x="38" y="23.2">U4A</text>
<text x="121.8" y="23.2">U5A</text>
<text x="233.3" y="21">C4</text>
<text x="233.3" y="28.1">10nF</text>
<text x="256.4" y="25.8">U4B</text>
<text x="246" y="30.6">C5</text>
<text x="246" y="33.1">10nF</text>
<text x="200.2" y="40.8">C6</text>
<text x="210.4" y="40.8">C7</text>
<text x="220.6" y="40.8">C8</text>
<text x="230.7" y="40.8">C9</text>
<text x="240.9" y="40.8">C10</text>
<text x="200.2" y="43.3">4.7uF</text>
<text x="210.4" y="43.3">470nF</text>
<text x="220.6" y="43.3">470nF</text>
<text x="230.7" y="43.3">470nF</text>
<text x="240.9" y="43.3">470nF</text>
<text x="200.2" y="71.2">C11</text>
<text x="210.4" y="71.2">C12</text>
<text x="220.6" y="71.2">C13</text>
<text x="230.7" y="71.2">C14</text>
<text x="240.9" y="71.2">C15</text>
<text x="200.2" y="73.8">4.7uF</text>
<text x="210.4" y="73.8">470nF</text>
<text x="220.6" y="73.8">470nF</text>
<text x="230.7" y="73.8">470nF</text>
<text x="240.9" y="73.8">470nF</text>
<text x="256.4" y="91.8">IC DDR3 MT41K64M16JT-15E</text>
<text x="169.6" y="101">R16</text>
<text x="233.3" y="97.2">C16</text>
<text x="256.4" y="102">U5B</text>
<text x="65.9" y="107.1">R17</text>
<text x="149.7" y="107.1">R18</text>
<text x="170.3" y="103.3">4.7K</text>
<text x="233.3" y="104.3">10nF</text>
<text x="246" y="106.8">C17</text>
<text x="38" y="112.1">IC DDR3 MT41K64M16JT-15E</text>
<text x="71.8" y="108.3">240</text>
<text x="121.8" y="112.1">IC DDR3 MT41K64M16JT-15E</text>
<text x="155.7" y="108.3">240</text>
<text x="246" y="109.3">10nF</text>
<text x="40.5" y="117.2">U4C</text>
<text x="124.3" y="117.2">U5C</text>
<text x="200.2" y="117">C18</text>
<text x="200.2" y="119.5">4.7uF</text>
<text x="210.4" y="117">C19</text>
<text x="210.4" y="119.5">470nF</text>
<text x="220.6" y="117">C20</text>
<text x="220.6" y="119.5">470nF</text>
<text x="230.7" y="117">C21</text>
<text x="230.7" y="119.5">470nF</text>
<text x="240.9" y="117">C22</text>
<text x="240.9" y="119.5">470nF</text>
<text x="40.5" y="132.5">IC DDR3 MT41K64M16JT-15E</text>
<text x="40.5" y="137.5">R19</text>
<text x="124.3" y="132.5">IC DDR3 MT41K64M16JT-15E</text>
<text x="40.5" y="140.1">R20</text>
<text x="40.5" y="142.6">R21</text>
<text x="47.1" y="138.8">33</text>
<text x="47.1" y="141.4">33</text>
<text x="47.1" y="143.9">33</text>
<text x="40.5" y="145.2">R22</text>
<text x="40.5" y="147.7">R23</text>
<text x="47.1" y="146.4">33</text>
<text x="47.1" y="149">33</text>
<text x="200.2" y="147.4">C23</text>
<text x="200.2" y="150">4.7uF</text>
<text x="210.4" y="147.4">C24</text>
<text x="210.4" y="150">470nF</text>
<text x="220.6" y="147.4">C25</text>
<text x="220.6" y="150">470nF</text>
<text x="230.7" y="147.4">C26</text>
<text x="230.7" y="150">470nF</text>
<text x="240.9" y="147.4">C27</text>
<text x="240.9" y="150">470nF</text>
<text x="40.5" y="150.2">R24</text>
<text x="40.5" y="152.8">R25</text>
<text x="40.5" y="155.3">R26</text>
<text x="47.1" y="151.5">33</text>
<text x="47.1" y="154.1">33</text>
<text x="40.5" y="157.9">R28</text>
<text x="40.5" y="160.4">R29</text>
<text x="47.1" y="156.6">33</text>
<text x="47.1" y="159.1">33</text>
<text x="47.1" y="161.7">33</text>
<text x="99.7" y="157.2" transform="rotate(-90 99.7 157.2)">1K</text>
<text x="102.2" y="157.7" transform="rotate(-90 102.2 157.7)">R27</text>
<text x="40.5" y="162.9">R30</text>
<text x="40.5" y="165.5">R32</text>
<text x="47.1" y="164.2">33</text>
<text x="47.1" y="166.8">33</text>
<text x="175.9" y="164.5" transform="rotate(-90 175.9 164.5)">82</text>
<text x="178.4" y="165.2" transform="rotate(-90 178.4 165.2)">R31</text>
<text x="40.5" y="168">R33</text>
<text x="40.5" y="170.6">R34</text>
<text x="40.5" y="173.1">R36</text>
<text x="47.1" y="169.3">33</text>
<text x="47.1" y="171.8">33</text>
<text x="99.7" y="172.5" transform="rotate(-90 99.7 172.5)">1K</text>
<text x="102.2" y="172.9" transform="rotate(-90 102.2 172.9)">R35</text>
<text x="111.3" y="170.3">C28</text>
<text x="111.3" y="172.8">4.7uF</text>
<text x="256.4" y="168">IC DDR3 MT41K64M16JT-15E</text>
<text x="40.5" y="175.6">R37</text>
<text x="40.5" y="178.2">R38</text>
<text x="47.1" y="174.4">33</text>
<text x="47.1" y="176.9">33</text>
<text x="47.1" y="179.5">33</text>
<text x="40.5" y="180.7">R39</text>
<text x="40.5" y="183.3">R40</text>
<text x="40.5" y="185.8">R41</text>
<text x="47.1" y="182">33</text>
<text x="47.1" y="184.5">33</text>
<text x="40.5" y="188.3">R42</text>
<text x="40.5" y="190.9">R43</text>
<text x="47.1" y="187.1">33</text>
<text x="47.1" y="189.6">33</text>
<text x="47.1" y="192.2">33</text>
</g>
<g font-size="2.3" fill="#f00">
<text x="79" y="18.2">DQ0</text>
<text x="80.9" y="21.5">i</text>
<text x="162.8" y="18.2">DQ2</text>
<text x="164.7" y="21.5">i</text>
<text x="81.6" y="41">DQ1</text>
<text x="165.4" y="41">DQ3</text>
<text x="83.4" y="44.3">i</text>
<text x="167.2" y="44.3">i</text>
<text x="83.9" y="85.5">i</text>
<text x="86.2" y="85.5">DQ0</text>
<text x="167.7" y="85.5">i</text>
<text x="170.1" y="85.5">DQ2</text>
<text x="79.1" y="94.4">DQ1</text>
<text x="80.9" y="91.1">i</text>
<text x="162.9" y="94.4">DQ3</text>
<text x="164.7" y="91.1">i</text>
<text x="71.7" y="127.4">50Z</text>
<text x="73.2" y="130.7">i</text>
</g>
<g font-size="2.3" fill="#800000">
<text x="247.1" y="18.2">VTTREF</text>
<text x="15.1" y="25.8">DDR3_A0_T</text>
<text x="15.1" y="28.3">DDR3_A1_T</text>
<text x="65.9" y="25.8">DDR3_D0</text>
<text x="65.9" y="28.3">DDR3_D1</text>
<text x="98.9" y="25.8">DDR3_A0_T</text>
<text x="98.9" y="28.3">DDR3_A1_T</text>
<text x="149.7" y="25.8">DDR3_D16</text>
<text x="149.7" y="28.3">DDR3_D17</text>
<text x="15.1" y="30.9">DDR3_A2_T</text>
<text x="15.1" y="33.4">DDR3_A3_T</text>
<text x="15.1" y="35.9">DDR3_A4_T</text>
<text x="65.9" y="30.9">DDR3_D2</text>
<text x="65.9" y="33.4">DDR3_D3</text>
<text x="65.9" y="35.9">DDR3_D4</text>
<text x="98.9" y="30.9">DDR3_A2_T</text>
<text x="98.9" y="33.4">DDR3_A3_T</text>
<text x="98.9" y="35.9">DDR3_A4_T</text>
<text x="149.7" y="30.9">DDR3_D18</text>
<text x="149.7" y="33.4">DDR3_D19</text>
<text x="149.7" y="35.9">DDR3_D20</text>
<text x="190.5" y="30.9">1V35</text>
<text x="226" y="33.4">GND</text>
<text x="15.1" y="38.5">DDR3_A5_T</text>
<text x="15.1" y="41">DDR3_A6_T</text>
<text x="65.9" y="38.5">DDR3_D5</text>
<text x="65.9" y="41">DDR3_D6</text>
<text x="98.9" y="38.5">DDR3_A5_T</text>
<text x="98.9" y="41">DDR3_A6_T</text>
<text x="149.7" y="38.5">DDR3_D21</text>
<text x="149.7" y="41">DDR3_D22</text>
<text x="15.1" y="43.6">DDR3_A7_T</text>
<text x="15.1" y="46.1">DDR3_A8_T</text>
<text x="65.9" y="43.6">DDR3_D7</text>
<text x="65.9" y="46.1">DDR3_D8</text>
<text x="98.9" y="43.6">DDR3_A7_T</text>
<text x="98.9" y="46.1">DDR3_A8_T</text>
<text x="149.7" y="43.6">DDR3_D23</text>
<text x="149.7" y="46.1">DDR3_D24</text>
<text x="15.1" y="48.6">DDR3_A9_T</text>
<text x="15.1" y="51.2">DDR3_A10_T</text>
<text x="15.1" y="53.7">DDR3_A11_T</text>
<text x="65.9" y="48.6">DDR3_D9</text>
<text x="65.9" y="51.2">DDR3_D10</text>
<text x="65.9" y="53.7">DDR3_D11</text>
<text x="98.9" y="48.6">DDR3_A9_T</text>
<text x="98.9" y="51.2">DDR3_A10_T</text>
<text x="98.9" y="53.7">DDR3_A11_T</text>
<text x="149.7" y="48.6">DDR3_D25</text>
<text x="149.7" y="51.2">DDR3_D26</text>
<text x="149.7" y="53.7">DDR3_D27</text>
<text x="195.5" y="53.7">GND</text>
<text x="205.7" y="53.7">GND</text>
<text x="215.9" y="53.7">GND</text>
<text x="226" y="53.7">GND</text>
<text x="236.2" y="53.7">GND</text>
<text x="15.1" y="56.3">DDR3_A12_T</text>
<text x="65.9" y="56.3">DDR3_D12</text>
<text x="65.9" y="58.8">DDR3_D13</text>
<text x="98.9" y="56.3">DDR3_A12_T</text>
<text x="149.7" y="56.3">DDR3_D28</text>
<text x="149.7" y="58.8">DDR3_D29</text>
<text x="65.9" y="61.3">DDR3_D14</text>
<text x="65.9" y="63.9">DDR3_D15</text>
<text x="149.7" y="61.3">DDR3_D30</text>
<text x="149.7" y="63.9">DDR3_D31</text>
<text x="190.5" y="61.3">1V35</text>
<text x="15.1" y="69">DDR3_BA0_T</text>
<text x="15.1" y="71.5">DDR3_BA1_T</text>
<text x="65.9" y="69">DDR3_DQS0_P</text>
<text x="65.9" y="71.5">DDR3_DQS0_N</text>
<text x="98.9" y="69">DDR3_BA0_T</text>
<text x="98.9" y="71.5">DDR3_BA1_T</text>
<text x="149.7" y="69">DDR3_DQS2_P</text>
<text x="149.7" y="71.5">DDR3_DQS2_N</text>
<text x="15.1" y="74">DDR3_BA2_T</text>
<text x="65.9" y="76.6">DDR3_DQS1_P</text>
<text x="98.9" y="74">DDR3_BA2_T</text>
<text x="149.7" y="76.6">DDR3_DQS3_P</text>
<text x="15.1" y="79.1">DDR3_CLK_P</text>
<text x="15.1" y="81.7">DDR3_CLK_N</text>
<text x="65.9" y="79.1">DDR3_DQS1_N</text>
<text x="98.9" y="79.1">DDR3_CLK_P</text>
<text x="98.9" y="81.7">DDR3_CLK_N</text>
<text x="149.7" y="79.1">DDR3_DQS3_N</text>
<text x="15.1" y="84.2">DDR3_CKE_T</text>
<text x="65.9" y="84.2">DDR3_DM0</text>
<text x="65.9" y="86.7">DDR3_DM1</text>
<text x="98.9" y="84.2">DDR3_CKE_T</text>
<text x="149.7" y="84.2">DDR3_DM2</text>
<text x="149.7" y="86.7">DDR3_DM3</text>
<text x="195.5" y="84.2">GND</text>
<text x="205.7" y="84.2">GND</text>
<text x="215.9" y="84.2">GND</text>
<text x="226" y="84.2">GND</text>
<text x="236.2" y="84.2">GND</text>
<text x="15.1" y="91.8">DDR3_WE_T</text>
<text x="15.1" y="94.4">DDR3_CAS_T</text>
<text x="98.9" y="91.8">DDR3_WE_T</text>
<text x="98.9" y="94.4">DDR3_CAS_T</text>
<text x="247.1" y="94.4">VTTREF</text>
<text x="15.1" y="96.9">DDR3_RAS_T</text>
<text x="15.1" y="99.4">DDR3_S0_T</text>
<text x="65.9" y="102">DDR3_RESET</text>
<text x="98.9" y="96.9">DDR3_RAS_T</text>
<text x="98.9" y="99.4">DDR3_S0_T</text>
<text x="149.7" y="102">DDR3_RESET</text>
<text x="279.4" y="96.9">GND</text>
<text x="15.1" y="107.1">DDR3_ODT_T</text>
<text x="98.9" y="107.1">DDR3_ODT_T</text>
<text x="190.5" y="107.1">1V35</text>
<text x="226" y="109.6">GND</text>
<text x="81.2" y="117.2">GND</text>
<text x="165.1" y="117.2">GND</text>
<text x="177.8" y="117.2">GND</text>
<text x="195.5" y="129.9">GND</text>
<text x="205.7" y="129.9">GND</text>
<text x="215.9" y="129.9">GND</text>
<text x="226" y="129.9">GND</text>
<text x="236.2" y="129.9">GND</text>
<text x="25.3" y="137.5">DDR3_RAS</text>
<text x="56.9" y="137.5">DDR3_RAS_T</text>
<text x="190.5" y="137.5">1V35</text>
<text x="25.3" y="140.1">DDR3_A12</text>
<text x="25.3" y="142.6">DDR3_A1</text>
<text x="57.4" y="140.1">DDR3_A12_T</text>
<text x="58.5" y="142.6">DDR3_A1_T</text>
<text x="25.3" y="147.7">DDR3_A9</text>
<text x="25.3" y="145.2">DDR3_BA1</text>
<text x="57" y="145.2">DDR3_BA1_T</text>
<text x="58.5" y="147.7">DDR3_A9_T</text>
<text x="96.5" y="145.2">1V35</text>
<text x="25.3" y="155.3">DDR3_WE</text>
<text x="25.3" y="150.2">DDR3_A2</text>
<text x="25.3" y="152.8">DDR3_BA2</text>
<text x="57" y="152.8">DDR3_BA2_T</text>
<text x="57.8" y="155.3">DDR3_WE_T</text>
<text x="58.5" y="150.2">DDR3_A2_T</text>
<text x="25.3" y="157.9">DDR3_S0</text>
<text x="25.3" y="160.4">DDR3_BA0</text>
<text x="57" y="160.4">DDR3_BA0_T</text>
<text x="58.9" y="157.9">DDR3_S0_T</text>
<text x="157.4" y="157.9">DDR3_CLK_P</text>
<text x="195.5" y="160.4">GND</text>
<text x="205.7" y="160.4">GND</text>
<text x="215.9" y="160.4">GND</text>
<text x="226" y="160.4">GND</text>
<text x="236.2" y="160.4">GND</text>
<text x="25.3" y="162.9">DDR3_A3</text>
<text x="25.3" y="165.5">DDR3_A10</text>
<text x="57.4" y="165.5">DDR3_A10_T</text>
<text x="58.5" y="162.9">DDR3_A3_T</text>
<text x="119.8" y="164.2">VTTREF</text>
<text x="25.3" y="173.1">DDR3_ODT</text>
<text x="25.3" y="170.6">DDR3_CKE</text>
<text x="25.3" y="168">DDR3_A6</text>
<text x="56.6" y="173.1">DDR3_ODT_T</text>
<text x="56.8" y="170.6">DDR3_CKE_T</text>
<text x="58.5" y="168">DDR3_A6_T</text>
<text x="157.4" y="168">DDR3_CLK_N</text>
<text x="279.4" y="173.1">GND</text>
<text x="25.3" y="175.6">DDR3_CAS</text>
<text x="25.3" y="178.2">DDR3_A11</text>
<text x="56.9" y="175.6">DDR3_CAS_T</text>
<text x="57.4" y="178.2">DDR3_A11_T</text>
<text x="25.3" y="185.8">DDR3_A0</text>
<text x="25.3" y="180.7">DDR3_A4</text>
<text x="25.3" y="183.3">DDR3_A7</text>
<text x="58.5" y="185.8">DDR3_A0_T</text>
<text x="58.5" y="180.7">DDR3_A4_T</text>
<text x="58.5" y="183.3">DDR3_A7_T</text>
<text x="96.5" y="185.8">GND</text>
<text x="106.6" y="185.8">GND</text>
<text x="25.3" y="188.3">DDR3_A5</text>
<text x="25.3" y="190.9">DDR3_A8</text>
<text x="58.5" y="188.3">DDR3_A5_T</text>
<text x="58.5" y="190.9">DDR3_A8_T</text>
</g>
</g></defs>
<path d="M2.4 8.5h292.1v193h-292.1z" fill-rule="evenodd" fill="#fffcf8"/>
<path d="M2.4 8.5h292.1v193h-292.1z" fill="none" stroke="#000" stroke-width=".21"/>
<path d="M7.5 13.6h281.9v182.9h-281.9z" fill-rule="evenodd" fill="#fffcf8"/>
<g fill="none" stroke="#000" stroke-width=".21">
<path d="M2.4 8.5h5.1M7.5 13.6h281.9v182.9h-281.9zM75.4 8.5v5.1M148.5 8.5v5.1M221.5 8.5v5.1M289.4 8.5h5.1v5.1M2.4 56.8h5.1M289.4 56.8h5.1M2.4 105h5.1M289.4 105h5.1M2.4 153.3h5.1M289.4 153.3h5.1"/>
<path d="M289.4 176.1h-88.9v20.4M75.4 196.5v5M148.5 196.5v5M200.5 183.8h88.9M200.5 191.4h88.9M200.5 193.9h88.9M213.2 183.8v7.6M221.5 196.5v5M251.3 191.4v5.1M264 183.8v7.6M294.5 196.5v5"/>
</g>
<g fill="#fff">
<path d="M63.4 23.7h17.8v20.4h-17.8z" fill-rule="evenodd"/>
<path d="M63.4 46.6h20.3v17.8h-20.3z" fill-rule="evenodd"/>
<path d="M147.2 23.7h17.8v20.4h-17.8z" fill-rule="evenodd"/>
<path d="M147.2 46.6h20.3v17.8h-20.3z" fill-rule="evenodd"/>
</g>
<path d="M231 23.7h-2.5v2.6M281.8 36.4v53.4M231 99.9h-2.5v2.6M78.6 107.6h5.1v2.5M162.4 107.6h5.1v2.5M177.7 102.5h2.5v7.6M281.8 112.6v53.4M98.9 176.1v2.6M109.1 176.1v2.6" fill="none" stroke="#00be00" stroke-width="1.3"/>
<path d="M192.9 33.9v2.5h58.4v20.4M192.9 64.4v2.5h58.4v20.3M192.9 110.1v2.5h58.4v20.4M98.9 148.2v2.5M192.9 140.6v2.5h58.4v20.3" fill="none" stroke="#ff0" stroke-width="1.3"/>
<path d="M241.2 23.7h10.1M243.7 23.7v2.6M251.3 21.2v10.2M241.2 99.9h10.1M243.7 99.9v2.6M251.3 97.4v10.2M98.9 160.9v5.1M98.9 163.4h17.8M109.1 163.4v2.6" fill="none" stroke="#fff0ff" stroke-width="1.3"/>
<path d="M55.8 133h17.7v60.9h-17.7z" fill-rule="evenodd" fill="#fff"/>
<path d="M38 23.7h20.3v86.4h-20.3z" fill-rule="evenodd" fill="#ffffb0"/>
<path d="M38 23.7h20.3v86.4h-20.3z" fill="none" stroke="#800000" stroke-width=".21"/>
<path d="M58.3 59.3h5.1" fill="none" stroke="#000" stroke-width=".25"/>
<path d="M58.3 59.3l1.5-.5v1z" fill="#f8fcff"/>
<path d="M58.3 59.3l1.5-.5v1z" fill="none" stroke="#000" stroke-width=".21"/>
<path d="M60.1 58.8l1.5 .5-1.5 .5z" fill="#f8fcff"/>
<path d="M60.1 58.8l1.5 .5-1.5 .5z" fill="none" stroke="#000" stroke-width=".21"/>
<path d="M58.3 64.4h5.1" fill="none" stroke="#000" stroke-width=".25"/>
<path d="M58.3 64.4l1.5-.5v1z" fill="#f8fcff"/>
<path d="M58.3 64.4l1.5-.5v1z" fill="none" stroke="#000" stroke-width=".21"/>
<path d="M60.1 63.9l1.5 .5-1.5 .5z" fill="#f8fcff"/>
<path d="M60.1 63.9l1.5 .5-1.5 .5z" fill="none" stroke="#000" stroke-width=".21"/>
<path d="M58.3 56.8h5.1" fill="none" stroke="#000" stroke-width=".25"/>
<path d="M58.3 56.8l1.5-.5v1z" fill="#f8fcff"/>
<path d="M58.3 56.8l1.5-.5v1z" fill="none" stroke="#000" stroke-width=".21"/>
<path d="M60.1 56.3l1.5 .5-1.5 .5z" fill="#f8fcff"/>
<path d="M60.1 56.3l1.5 .5-1.5 .5z" fill="none" stroke="#000" stroke-width=".21"/>
<path d="M58.3 79.6h5.1" fill="none" stroke="#000" stroke-width=".25"/>
<path d="M58.3 79.6l1.5-.5v1z" fill="#f8fcff"/>
<path d="M58.3 79.6l1.5-.5v1z" fill="none" stroke="#000" stroke-width=".21"/>
<path d="M60.1 79.1l1.5 .5-1.5 .5z" fill="#f8fcff"/>
<path d="M60.1 79.1l1.5 .5-1.5 .5z" fill="none" stroke="#000" stroke-width=".21"/>
<path d="M58.3 61.8h5.1" fill="none" stroke="#000" stroke-width=".25"/>
<path d="M58.3 61.8l1.5-.5v1.1z" fill="#f8fcff"/>
<path d="M58.3 61.8l1.5-.5v1.1z" fill="none" stroke="#000" stroke-width=".21"/>
<path d="M60.1 61.3l1.5 .5-1.5 .6z" fill="#f8fcff"/>
<path d="M60.1 61.3l1.5 .5-1.5 .6z" fill="none" stroke="#000" stroke-width=".21"/>
<path d="M58.3 54.2h5.1" fill="none" stroke="#000" stroke-width=".25"/>
<path d="M58.3 54.2l1.5-.5v1z" fill="#f8fcff"/>
<path d="M58.3 54.2l1.5-.5v1z" fill="none" stroke="#000" stroke-width=".21"/>
<path d="M60.1 53.7l1.5 .5-1.5 .5z" fill="#f8fcff"/>
<path d="M60.1 53.7l1.5 .5-1.5 .5z" fill="none" stroke="#000" stroke-width=".21"/>
<path d="M58.3 49.1h5.1" fill="none" stroke="#000" stroke-width=".25"/>
<path d="M58.3 49.1l1.5-.5v1.1z" fill="#f8fcff"/>
<path d="M58.3 49.1l1.5-.5v1.1z" fill="none" stroke="#000" stroke-width=".21"/>
<path d="M60.1 48.6l1.5 .5-1.5 .6z" fill="#f8fcff"/>
<path d="M60.1 48.6l1.5 .5-1.5 .6z" fill="none" stroke="#000" stroke-width=".21"/>
<path d="M58.3 77.1h5.1" fill="none" stroke="#000" stroke-width=".25"/>
<path d="M58.3 77.1l1.5-.5v1z" fill="#f8fcff"/>
<path d="M58.3 77.1l1.5-.5v1z" fill="none" stroke="#000" stroke-width=".21"/>
<path d="M60.1 76.6l1.5 .5-1.5 .5z" fill="#f8fcff"/>
<path d="M60.1 76.6l1.5 .5-1.5 .5z" fill="none" stroke="#000" stroke-width=".21"/>
<path d="M58.3 51.7h5.1" fill="none" stroke="#000" stroke-width=".25"/>
<path d="M58.3 51.7l1.5-.5v1z" fill="#f8fcff"/>
<path d="M58.3 51.7l1.5-.5v1z" fill="none" stroke="#000" stroke-width=".21"/>
<path d="M60.1 51.2l1.5 .5-1.5 .5z" fill="#f8fcff"/>
<path d="M60.1 51.2l1.5 .5-1.5 .5z" fill="none" stroke="#000" stroke-width=".21"/>
<path d="M58.3 87.2h5.1" fill="none" stroke="#000" stroke-width=".25"/>
<path d="M58.3 87.2l1.5-.5v1.1z" fill="#f8fcff"/>
<path d="M58.3 87.2l1.5-.5v1.1z" fill="none" stroke="#000" stroke-width=".21"/>
<path d="M58.3 46.6h5.1" fill="none" stroke="#000" stroke-width=".25"/>
<path d="M58.3 46.6l1.5-.5v1z" fill="#f8fcff"/>
<path d="M58.3 46.6l1.5-.5v1z" fill="none" stroke="#000" stroke-width=".21"/>
<path d="M60.1 46.1l1.5 .5-1.5 .5z" fill="#f8fcff"/>
<path d="M60.1 46.1l1.5 .5-1.5 .5z" fill="none" stroke="#000" stroke-width=".21"/>
<path d="M58.3 26.3h5.1" fill="none" stroke="#000" stroke-width=".25"/>
<path d="M58.3 26.3l1.5-.5v1z" fill="#f8fcff"/>
<path d="M58.3 26.3l1.5-.5v1z" fill="none" stroke="#000" stroke-width=".21"/>
<path d="M60.1 25.8l1.5 .5-1.5 .5z" fill="#f8fcff"/>
<path d="M60.1 25.8l1.5 .5-1.5 .5z" fill="none" stroke="#000" stroke-width=".21"/>
<path d="M58.3 84.7h5.1" fill="none" stroke="#000" stroke-width=".25"/>
<path d="M58.3 84.7l1.5-.5v1z" fill="#f8fcff"/>
<path d="M58.3 84.7l1.5-.5v1z" fill="none" stroke="#000" stroke-width=".21"/>
<path d="M58.3 31.4h5.1" fill="none" stroke="#000" stroke-width=".25"/>
<path d="M58.3 31.4l1.5-.5v1z" fill="#f8fcff"/>
<path d="M58.3 31.4l1.5-.5v1z" fill="none" stroke="#000" stroke-width=".21"/>
<path d="M60.1 30.9l1.5 .5-1.5 .5z" fill="#f8fcff"/>
<path d="M60.1 30.9l1.5 .5-1.5 .5z" fill="none" stroke="#000" stroke-width=".21"/>
<path d="M58.3 69.5h5.1" fill="none" stroke="#000" stroke-width=".25"/>
<path d="M58.3 69.5l1.5-.5v1z" fill="#f8fcff"/>
<path d="M58.3 69.5l1.5-.5v1z" fill="none" stroke="#000" stroke-width=".21"/>
<path d="M60.1 69l1.5 .5-1.5 .5z" fill="#f8fcff"/>
<path d="M60.1 69l1.5 .5-1.5 .5z" fill="none" stroke="#000" stroke-width=".21"/>
<path d="M58.3 28.8h5.1" fill="none" stroke="#000" stroke-width=".25"/>
<path d="M58.3 28.8l1.5-.5v1z" fill="#f8fcff"/>
<path d="M58.3 28.8l1.5-.5v1z" fill="none" stroke="#000" stroke-width=".21"/>
<path d="M60.1 28.3l1.5 .5-1.5 .5z" fill="#f8fcff"/>
<path d="M60.1 28.3l1.5 .5-1.5 .5z" fill="none" stroke="#000" stroke-width=".21"/>
<path d="M58.3 33.9h5.1" fill="none" stroke="#000" stroke-width=".25"/>
<path d="M58.3 33.9l1.5-.5v1z" fill="#f8fcff"/>
<path d="M58.3 33.9l1.5-.5v1z" fill="none" stroke="#000" stroke-width=".21"/>
<path d="M60.1 33.4l1.5 .5-1.5 .5z" fill="#f8fcff"/>
<path d="M60.1 33.4l1.5 .5-1.5 .5z" fill="none" stroke="#000" stroke-width=".21"/>
<path d="M58.3 41.5h5.1" fill="none" stroke="#000" stroke-width=".25"/>
<path d="M58.3 41.5l1.5-.5v1z" fill="#f8fcff"/>
<path d="M58.3 41.5l1.5-.5v1z" fill="none" stroke="#000" stroke-width=".21"/>
<path d="M60.1 41l1.5 .5-1.5 .5z" fill="#f8fcff"/>
<path d="M60.1 41l1.5 .5-1.5 .5z" fill="none" stroke="#000" stroke-width=".21"/>
<path d="M58.3 72h5.1" fill="none" stroke="#000" stroke-width=".25"/>
<path d="M58.3 72l1.5-.5v1z" fill="#f8fcff"/>
<path d="M58.3 72l1.5-.5v1z" fill="none" stroke="#000" stroke-width=".21"/>
<path d="M60.1 71.5l1.5 .5-1.5 .5z" fill="#f8fcff"/>
<path d="M60.1 71.5l1.5 .5-1.5 .5z" fill="none" stroke="#000" stroke-width=".21"/>
<path d="M58.3 36.4h5.1" fill="none" stroke="#000" stroke-width=".25"/>
<path d="M58.3 36.4l1.5-.5v1.1z" fill="#f8fcff"/>
<path d="M58.3 36.4l1.5-.5v1.1z" fill="none" stroke="#000" stroke-width=".21"/>
<path d="M60.1 35.9l1.5 .5-1.5 .6z" fill="#f8fcff"/>
<path d="M60.1 35.9l1.5 .5-1.5 .6z" fill="none" stroke="#000" stroke-width=".21"/>
<path d="M58.3 44.1h5.1" fill="none" stroke="#000" stroke-width=".25"/>
<path d="M58.3 44.1l1.5-.5v1z" fill="#f8fcff"/>
<path d="M58.3 44.1l1.5-.5v1z" fill="none" stroke="#000" stroke-width=".21"/>
<path d="M60.1 43.6l1.5 .5-1.5 .5z" fill="#f8fcff"/>
<path d="M60.1 43.6l1.5 .5-1.5 .5z" fill="none" stroke="#000" stroke-width=".21"/>
<path d="M58.3 39h5.1" fill="none" stroke="#000" stroke-width=".25"/>
<path d="M58.3 39l1.5-.5v1z" fill="#f8fcff"/>
<path d="M58.3 39l1.5-.5v1z" fill="none" stroke="#000" stroke-width=".21"/>
<path d="M60.1 38.5l1.5 .5-1.5 .5z" fill="#f8fcff"/>
<path d="M60.1 38.5l1.5 .5-1.5 .5z" fill="none" stroke="#000" stroke-width=".21"/>
<path d="M32.9 97.4h5.1" fill="none" stroke="#000" stroke-width=".25"/>
<path d="M36.5 96.9l1.5 .5-1.5 .5z" fill="#f8fcff"/>
<path d="M36.5 96.9l1.5 .5-1.5 .5z" fill="none" stroke="#000" stroke-width=".21"/>
<path d="M32.9 79.6h5.1" fill="none" stroke="#000" stroke-width=".25"/>
<path d="M36.5 79.1l1.5 .5-1.5 .5z" fill="#f8fcff"/>
<path d="M36.5 79.1l1.5 .5-1.5 .5zM38 79.1l1 .5-1 .5" fill="none" stroke="#000" stroke-width=".21"/>
<path d="M32.9 107.6h5.1" fill="none" stroke="#000" stroke-width=".25"/>
<path d="M36.5 107.1l1.5 .5-1.5 .5z" fill="#f8fcff"/>
<path d="M36.5 107.1l1.5 .5-1.5 .5z" fill="none" stroke="#000" stroke-width=".21"/>
<path d="M32.9 94.9h5.1" fill="none" stroke="#000" stroke-width=".25"/>
<path d="M36.5 94.4l1.5 .5-1.5 .5z" fill="#f8fcff"/>
<path d="M36.5 94.4l1.5 .5-1.5 .5z" fill="none" stroke="#000" stroke-width=".21"/>
<path d="M32.9 82.2h5.1" fill="none" stroke="#000" stroke-width=".25"/>
<path d="M36.5 81.7l1.5 .5-1.5 .5z" fill="#f8fcff"/>
<path d="M36.5 81.7l1.5 .5-1.5 .5zM38 81.7l1 .5-1 .5" fill="none" stroke="#000" stroke-width=".21"/>
<path d="M32.9 84.7h5.1" fill="none" stroke="#000" stroke-width=".25"/>
<path d="M36.5 84.2l1.5 .5-1.5 .5z" fill="#f8fcff"/>
<path d="M36.5 84.2l1.5 .5-1.5 .5z" fill="none" stroke="#000" stroke-width=".21"/>
<path d="M32.9 99.9h5.1" fill="none" stroke="#000" stroke-width=".25"/>
<path d="M36.5 99.4l1.5 .5-1.5 .6z" fill="#f8fcff"/>
<path d="M36.5 99.4l1.5 .5-1.5 .6z" fill="none" stroke="#000" stroke-width=".21"/>
<path d="M32.9 92.3h5.1" fill="none" stroke="#000" stroke-width=".25"/>
<path d="M36.5 91.8l1.5 .5-1.5 .5z" fill="#f8fcff"/>
<path d="M36.5 91.8l1.5 .5-1.5 .5z" fill="none" stroke="#000" stroke-width=".21"/>
<path d="M32.9 51.7h5.1" fill="none" stroke="#000" stroke-width=".25"/>
<path d="M36.5 51.2l1.5 .5-1.5 .5z" fill="#f8fcff"/>
<path d="M36.5 51.2l1.5 .5-1.5 .5z" fill="none" stroke="#000" stroke-width=".21"/>
<path d="M58.3 107.6h5.1" fill="none" stroke="#000" stroke-width=".25"/>
<path d="M58.3 107.6l1.5-.5v1z" fill="#f8fcff"/>
<path d="M58.3 107.6l1.5-.5v1z" fill="none" stroke="#000" stroke-width=".21"/>
<path d="M32.9 69.5h5.1" fill="none" stroke="#000" stroke-width=".25"/>
<path d="M36.5 69l1.5 .5-1.5 .5z" fill="#f8fcff"/>
<path d="M36.5 69l1.5 .5-1.5 .5z" fill="none" stroke="#000" stroke-width=".21"/>
<path d="M32.9 74.5h5.1" fill="none" stroke="#000" stroke-width=".25"/>
<path d="M36.5 74l1.5 .5-1.5 .6z" fill="#f8fcff"/>
<path d="M36.5 74l1.5 .5-1.5 .6z" fill="none" stroke="#000" stroke-width=".21"/>
<path d="M32.9 33.9h5.1" fill="none" stroke="#000" stroke-width=".25"/>
<path d="M36.5 33.4l1.5 .5-1.5 .5z" fill="#f8fcff"/>
<path d="M36.5 33.4l1.5 .5-1.5 .5z" fill="none" stroke="#000" stroke-width=".21"/>
<path d="M32.9 26.3h5.1" fill="none" stroke="#000" stroke-width=".25"/>
<path d="M36.5 25.8l1.5 .5-1.5 .5z" fill="#f8fcff"/>
<path d="M36.5 25.8l1.5 .5-1.5 .5z" fill="none" stroke="#000" stroke-width=".21"/>
<path d="M32.9 56.8h5.1" fill="none" stroke="#000" stroke-width=".25"/>
<path d="M36.5 56.3l1.5 .5-1.5 .5z" fill="#f8fcff"/>
<path d="M36.5 56.3l1.5 .5-1.5 .5z" fill="none" stroke="#000" stroke-width=".21"/>
<path d="M32.9 72h5.1" fill="none" stroke="#000" stroke-width=".25"/>
<path d="M36.5 71.5l1.5 .5-1.5 .5z" fill="#f8fcff"/>
<path d="M36.5 71.5l1.5 .5-1.5 .5z" fill="none" stroke="#000" stroke-width=".21"/>
<path d="M32.9 39h5.1" fill="none" stroke="#000" stroke-width=".25"/>
<path d="M36.5 38.5l1.5 .5-1.5 .5z" fill="#f8fcff"/>
<path d="M36.5 38.5l1.5 .5-1.5 .5z" fill="none" stroke="#000" stroke-width=".21"/>
<path d="M32.9 31.4h5.1" fill="none" stroke="#000" stroke-width=".25"/>
<path d="M36.5 30.9l1.5 .5-1.5 .5z" fill="#f8fcff"/>
<path d="M36.5 30.9l1.5 .5-1.5 .5z" fill="none" stroke="#000" stroke-width=".21"/>
<path d="M32.9 28.8h5.1" fill="none" stroke="#000" stroke-width=".25"/>
<path d="M36.5 28.3l1.5 .5-1.5 .5z" fill="#f8fcff"/>
<path d="M36.5 28.3l1.5 .5-1.5 .5z" fill="none" stroke="#000" stroke-width=".21"/>
<path d="M32.9 36.4h5.1" fill="none" stroke="#000" stroke-width=".25"/>
<path d="M36.5 35.9l1.5 .5-1.5 .6z" fill="#f8fcff"/>
<path d="M36.5 35.9l1.5 .5-1.5 .6z" fill="none" stroke="#000" stroke-width=".21"/>
<path d="M32.9 44.1h5.1" fill="none" stroke="#000" stroke-width=".25"/>
<path d="M36.5 43.6l1.5 .5-1.5 .5z" fill="#f8fcff"/>
<path d="M36.5 43.6l1.5 .5-1.5 .5z" fill="none" stroke="#000" stroke-width=".21"/>
<path d="M32.9 49.1h5.1" fill="none" stroke="#000" stroke-width=".25"/>
<path d="M36.5 48.6l1.5 .5-1.5 .6z" fill="#f8fcff"/>
<path d="M36.5 48.6l1.5 .5-1.5 .6z" fill="none" stroke="#000" stroke-width=".21"/>
<path d="M32.9 54.2h5.1" fill="none" stroke="#000" stroke-width=".25"/>
<path d="M36.5 53.7l1.5 .5-1.5 .5z" fill="#f8fcff"/>
<path d="M36.5 53.7l1.5 .5-1.5 .5z" fill="none" stroke="#000" stroke-width=".21"/>
<path d="M32.9 41.5h5.1" fill="none" stroke="#000" stroke-width=".25"/>
<path d="M36.5 41l1.5 .5-1.5 .5z" fill="#f8fcff"/>
<path d="M36.5 41l1.5 .5-1.5 .5z" fill="none" stroke="#000" stroke-width=".21"/>
<path d="M58.3 102.5h5.1" fill="none" stroke="#000" stroke-width=".25"/>
<path d="M58.3 102.5l1.5-.5v1z" fill="#f8fcff"/>
<path d="M58.3 102.5l1.5-.5v1z" fill="none" stroke="#000" stroke-width=".21"/>
<path d="M32.9 46.6h5.1" fill="none" stroke="#000" stroke-width=".25"/>
<path d="M36.5 46.1l1.5 .5-1.5 .5z" fill="#f8fcff"/>
<path d="M36.5 46.1l1.5 .5-1.5 .5z" fill="none" stroke="#000" stroke-width=".21"/>
<circle cx="251.3" cy="36.5" r=".51" fill="#000080"/>
<circle cx="251.3" cy="36.5" r=".51" fill="none" stroke="#000080" stroke-width=".21"/>
<circle cx="251.3" cy="39" r=".51" fill="#000080"/>
<circle cx="251.3" cy="39" r=".51" fill="none" stroke="#000080" stroke-width=".21"/>
<circle cx="281.8" cy="59.3" r=".51" fill="#000080"/>
<circle cx="281.8" cy="59.3" r=".51" fill="none" stroke="#000080" stroke-width=".21"/>
<circle cx="251.3" cy="66.9" r=".51" fill="#000080"/>
<circle cx="251.3" cy="66.9" r=".51" fill="none" stroke="#000080" stroke-width=".21"/>
<circle cx="281.8" cy="61.9" r=".51" fill="#000080"/>
<circle cx="281.8" cy="61.9" r=".51" fill="none" stroke="#000080" stroke-width=".21"/>
<circle cx="281.8" cy="39" r=".51" fill="#000080"/>
<circle cx="281.8" cy="39" r=".51" fill="none" stroke="#000080" stroke-width=".21"/>
<circle cx="251.3" cy="41.5" r=".51" fill="#000080"/>
<circle cx="251.3" cy="41.5" r=".51" fill="none" stroke="#000080" stroke-width=".21"/>
<circle cx="251.3" cy="44.1" r=".51" fill="#000080"/>
<circle cx="251.3" cy="44.1" r=".51" fill="none" stroke="#000080" stroke-width=".21"/>
<circle cx="281.8" cy="41.5" r=".51" fill="#000080"/>
<circle cx="281.8" cy="41.5" r=".51" fill="none" stroke="#000080" stroke-width=".21"/>
<circle cx="251.3" cy="46.6" r=".51" fill="#000080"/>
<circle cx="251.3" cy="46.6" r=".51" fill="none" stroke="#000080" stroke-width=".21"/>
<circle cx="281.8" cy="44.1" r=".51" fill="#000080"/>
<circle cx="281.8" cy="44.1" r=".51" fill="none" stroke="#000080" stroke-width=".21"/>
<circle cx="251.3" cy="69.5" r=".51" fill="#000080"/>
<circle cx="251.3" cy="69.5" r=".51" fill="none" stroke="#000080" stroke-width=".21"/>
<circle cx="281.8" cy="64.4" r=".51" fill="#000080"/>
<circle cx="281.8" cy="64.4" r=".51" fill="none" stroke="#000080" stroke-width=".21"/>
<circle cx="281.8" cy="46.6" r=".51" fill="#000080"/>
<circle cx="281.8" cy="46.6" r=".51" fill="none" stroke="#000080" stroke-width=".21"/>
<circle cx="281.8" cy="49.2" r=".51" fill="#000080"/>
<circle cx="281.8" cy="49.2" r=".51" fill="none" stroke="#000080" stroke-width=".21"/>
<circle cx="251.3" cy="51.7" r=".51" fill="#000080"/>
<circle cx="251.3" cy="51.7" r=".51" fill="none" stroke="#000080" stroke-width=".21"/>
<circle cx="251.3" cy="49.2" r=".51" fill="#000080"/>
<circle cx="251.3" cy="49.2" r=".51" fill="none" stroke="#000080" stroke-width=".21"/>
<circle cx="281.8" cy="51.7" r=".51" fill="#000080"/>
<circle cx="281.8" cy="51.7" r=".51" fill="none" stroke="#000080" stroke-width=".21"/>
<circle cx="281.8" cy="54.2" r=".51" fill="#000080"/>
<circle cx="281.8" cy="54.2" r=".51" fill="none" stroke="#000080" stroke-width=".21"/>
<circle cx="251.3" cy="72" r=".51" fill="#000080"/>
<circle cx="251.3" cy="72" r=".51" fill="none" stroke="#000080" stroke-width=".21"/>
<circle cx="281.8" cy="66.9" r=".51" fill="#000080"/>
<circle cx="281.8" cy="66.9" r=".51" fill="none" stroke="#000080" stroke-width=".21"/>
<circle cx="281.8" cy="56.8" r=".51" fill="#000080"/>
<circle cx="281.8" cy="56.8" r=".51" fill="none" stroke="#000080" stroke-width=".21"/>
<circle cx="251.3" cy="54.2" r=".51" fill="#000080"/>
<circle cx="251.3" cy="54.2" r=".51" fill="none" stroke="#000080" stroke-width=".21"/>
<circle cx="281.8" cy="69.5" r=".51" fill="#000080"/>
<circle cx="281.8" cy="69.5" r=".51" fill="none" stroke="#000080" stroke-width=".21"/>
<circle cx="281.8" cy="72" r=".51" fill="#000080"/>
<circle cx="281.8" cy="72" r=".51" fill="none" stroke="#000080" stroke-width=".21"/>
<circle cx="251.3" cy="74.6" r=".51" fill="#000080"/>
<circle cx="251.3" cy="74.6" r=".51" fill="none" stroke="#000080" stroke-width=".21"/>
<circle cx="251.3" cy="77.1" r=".51" fill="#000080"/>
<circle cx="251.3" cy="77.1" r=".51" fill="none" stroke="#000080" stroke-width=".21"/>
<circle cx="281.8" cy="74.6" r=".51" fill="#000080"/>
<circle cx="281.8" cy="74.6" r=".51" fill="none" stroke="#000080" stroke-width=".21"/>
<circle cx="281.8" cy="77.1" r=".51" fill="#000080"/>
<circle cx="281.8" cy="77.1" r=".51" fill="none" stroke="#000080" stroke-width=".21"/>
<circle cx="251.3" cy="79.6" r=".51" fill="#000080"/>
<circle cx="251.3" cy="79.6" r=".51" fill="none" stroke="#000080" stroke-width=".21"/>
<circle cx="251.3" cy="82.2" r=".51" fill="#000080"/>
<circle cx="251.3" cy="82.2" r=".51" fill="none" stroke="#000080" stroke-width=".21"/>
<circle cx="281.8" cy="79.6" r=".51" fill="#000080"/>
<circle cx="281.8" cy="79.6" r=".51" fill="none" stroke="#000080" stroke-width=".21"/>
<circle cx="281.8" cy="82.2" r=".51" fill="#000080"/>
<circle cx="281.8" cy="82.2" r=".51" fill="none" stroke="#000080" stroke-width=".21"/>
<circle cx="251.3" cy="84.7" r=".51" fill="#000080"/>
<circle cx="251.3" cy="84.7" r=".51" fill="none" stroke="#000080" stroke-width=".21"/>
<circle cx="281.8" cy="84.7" r=".51" fill="#000080"/>
<circle cx="281.8" cy="84.7" r=".51" fill="none" stroke="#000080" stroke-width=".21"/>
<circle cx="281.8" cy="87.3" r=".51" fill="#000080"/>
<circle cx="281.8" cy="87.3" r=".51" fill="none" stroke="#000080" stroke-width=".21"/>
<circle cx="251.3" cy="28.8" r=".51" fill="#000080"/>
<circle cx="251.3" cy="28.8" r=".51" fill="none" stroke="#000080" stroke-width=".21"/>
<path d="M256.4 26.3h20.3v63.5h-20.3z" fill-rule="evenodd" fill="#ffffb0"/>
<path d="M256.4 26.3h20.3v63.5h-20.3z" fill="none" stroke="#800000" stroke-width=".21"/>
<path d="M251.3 36.4h5.1" fill="none" stroke="#000" stroke-width=".25"/>
<circle cx="251.3" cy="36.5" r=".51" fill="#000080"/>
<circle cx="251.3" cy="36.5" r=".51" fill="none" stroke="#000080" stroke-width=".21"/>
<path d="M251.3 39h5.1" fill="none" stroke="#000" stroke-width=".25"/>
<circle cx="251.3" cy="39" r=".51" fill="#000080"/>
<circle cx="251.3" cy="39" r=".51" fill="none" stroke="#000080" stroke-width=".21"/>
<path d="M276.7 59.3h5.1" fill="none" stroke="#000" stroke-width=".25"/>
<circle cx="281.8" cy="59.3" r=".51" fill="#000080"/>
<circle cx="281.8" cy="59.3" r=".51" fill="none" stroke="#000080" stroke-width=".21"/>
<path d="M276.7 36.4h5.1M251.3 66.9h5.1" fill="none" stroke="#000" stroke-width=".25"/>
<circle cx="251.3" cy="66.9" r=".51" fill="#000080"/>
<circle cx="251.3" cy="66.9" r=".51" fill="none" stroke="#000080" stroke-width=".21"/>
<path d="M276.7 61.8h5.1" fill="none" stroke="#000" stroke-width=".25"/>
<circle cx="281.8" cy="61.9" r=".51" fill="#000080"/>
<circle cx="281.8" cy="61.9" r=".51" fill="none" stroke="#000080" stroke-width=".21"/>
<path d="M276.7 39h5.1" fill="none" stroke="#000" stroke-width=".25"/>
<circle cx="281.8" cy="39" r=".51" fill="#000080"/>
<circle cx="281.8" cy="39" r=".51" fill="none" stroke="#000080" stroke-width=".21"/>
<path d="M251.3 41.5h5.1" fill="none" stroke="#000" stroke-width=".25"/>
<circle cx="251.3" cy="41.5" r=".51" fill="#000080"/>
<circle cx="251.3" cy="41.5" r=".51" fill="none" stroke="#000080" stroke-width=".21"/>
<path d="M251.3 44.1h5.1" fill="none" stroke="#000" stroke-width=".25"/>
<circle cx="251.3" cy="44.1" r=".51" fill="#000080"/>
<circle cx="251.3" cy="44.1" r=".51" fill="none" stroke="#000080" stroke-width=".21"/>
<path d="M276.7 41.5h5.1" fill="none" stroke="#000" stroke-width=".25"/>
<circle cx="281.8" cy="41.5" r=".51" fill="#000080"/>
<circle cx="281.8" cy="41.5" r=".51" fill="none" stroke="#000080" stroke-width=".21"/>
<path d="M251.3 46.6h5.1" fill="none" stroke="#000" stroke-width=".25"/>
<circle cx="251.3" cy="46.6" r=".51" fill="#000080"/>
<circle cx="251.3" cy="46.6" r=".51" fill="none" stroke="#000080" stroke-width=".21"/>
<path d="M276.7 44.1h5.1" fill="none" stroke="#000" stroke-width=".25"/>
<circle cx="281.8" cy="44.1" r=".51" fill="#000080"/>
<circle cx="281.8" cy="44.1" r=".51" fill="none" stroke="#000080" stroke-width=".21"/>
<path d="M251.3 69.5h5.1" fill="none" stroke="#000" stroke-width=".25"/>
<circle cx="251.3" cy="69.5" r=".51" fill="#000080"/>
<circle cx="251.3" cy="69.5" r=".51" fill="none" stroke="#000080" stroke-width=".21"/>
<path d="M276.7 64.4h5.1" fill="none" stroke="#000" stroke-width=".25"/>
<circle cx="281.8" cy="64.4" r=".51" fill="#000080"/>
<circle cx="281.8" cy="64.4" r=".51" fill="none" stroke="#000080" stroke-width=".21"/>
<path d="M276.7 46.6h5.1" fill="none" stroke="#000" stroke-width=".25"/>
<circle cx="281.8" cy="46.6" r=".51" fill="#000080"/>
<circle cx="281.8" cy="46.6" r=".51" fill="none" stroke="#000080" stroke-width=".21"/>
<path d="M276.7 49.1h5.1" fill="none" stroke="#000" stroke-width=".25"/>
<circle cx="281.8" cy="49.2" r=".51" fill="#000080"/>
<circle cx="281.8" cy="49.2" r=".51" fill="none" stroke="#000080" stroke-width=".21"/>
<path d="M251.3 51.7h5.1" fill="none" stroke="#000" stroke-width=".25"/>
<circle cx="251.3" cy="51.7" r=".51" fill="#000080"/>
<circle cx="251.3" cy="51.7" r=".51" fill="none" stroke="#000080" stroke-width=".21"/>
<path d="M251.3 49.1h5.1" fill="none" stroke="#000" stroke-width=".25"/>
<circle cx="251.3" cy="49.2" r=".51" fill="#000080"/>
<circle cx="251.3" cy="49.2" r=".51" fill="none" stroke="#000080" stroke-width=".21"/>
<path d="M276.7 51.7h5.1" fill="none" stroke="#000" stroke-width=".25"/>
<circle cx="281.8" cy="51.7" r=".51" fill="#000080"/>
<circle cx="281.8" cy="51.7" r=".51" fill="none" stroke="#000080" stroke-width=".21"/>
<path d="M276.7 54.2h5.1" fill="none" stroke="#000" stroke-width=".25"/>
<circle cx="281.8" cy="54.2" r=".51" fill="#000080"/>
<circle cx="281.8" cy="54.2" r=".51" fill="none" stroke="#000080" stroke-width=".21"/>
<path d="M251.3 72h5.1" fill="none" stroke="#000" stroke-width=".25"/>
<circle cx="251.3" cy="72" r=".51" fill="#000080"/>
<circle cx="251.3" cy="72" r=".51" fill="none" stroke="#000080" stroke-width=".21"/>
<path d="M276.7 66.9h5.1" fill="none" stroke="#000" stroke-width=".25"/>
<circle cx="281.8" cy="66.9" r=".51" fill="#000080"/>
<circle cx="281.8" cy="66.9" r=".51" fill="none" stroke="#000080" stroke-width=".21"/>
<path d="M276.7 56.8h5.1" fill="none" stroke="#000" stroke-width=".25"/>
<circle cx="281.8" cy="56.8" r=".51" fill="#000080"/>
<circle cx="281.8" cy="56.8" r=".51" fill="none" stroke="#000080" stroke-width=".21"/>
<path d="M251.3 54.2h5.1" fill="none" stroke="#000" stroke-width=".25"/>
<circle cx="251.3" cy="54.2" r=".51" fill="#000080"/>
<circle cx="251.3" cy="54.2" r=".51" fill="none" stroke="#000080" stroke-width=".21"/>
<path d="M251.3 56.8h5.1M276.7 69.5h5.1" fill="none" stroke="#000" stroke-width=".25"/>
<circle cx="281.8" cy="69.5" r=".51" fill="#000080"/>
<circle cx="281.8" cy="69.5" r=".51" fill="none" stroke="#000080" stroke-width=".21"/>
<path d="M276.7 72h5.1" fill="none" stroke="#000" stroke-width=".25"/>
<circle cx="281.8" cy="72" r=".51" fill="#000080"/>
<circle cx="281.8" cy="72" r=".51" fill="none" stroke="#000080" stroke-width=".21"/>
<path d="M251.3 74.5h5.1" fill="none" stroke="#000" stroke-width=".25"/>
<circle cx="251.3" cy="74.6" r=".51" fill="#000080"/>
<circle cx="251.3" cy="74.6" r=".51" fill="none" stroke="#000080" stroke-width=".21"/>
<path d="M251.3 77.1h5.1" fill="none" stroke="#000" stroke-width=".25"/>
<circle cx="251.3" cy="77.1" r=".51" fill="#000080"/>
<circle cx="251.3" cy="77.1" r=".51" fill="none" stroke="#000080" stroke-width=".21"/>
<path d="M276.7 74.5h5.1" fill="none" stroke="#000" stroke-width=".25"/>
<circle cx="281.8" cy="74.6" r=".51" fill="#000080"/>
<circle cx="281.8" cy="74.6" r=".51" fill="none" stroke="#000080" stroke-width=".21"/>
<path d="M276.7 77.1h5.1" fill="none" stroke="#000" stroke-width=".25"/>
<circle cx="281.8" cy="77.1" r=".51" fill="#000080"/>
<circle cx="281.8" cy="77.1" r=".51" fill="none" stroke="#000080" stroke-width=".21"/>
<path d="M251.3 79.6h5.1" fill="none" stroke="#000" stroke-width=".25"/>
<circle cx="251.3" cy="79.6" r=".51" fill="#000080"/>
<circle cx="251.3" cy="79.6" r=".51" fill="none" stroke="#000080" stroke-width=".21"/>
<path d="M251.3 82.2h5.1" fill="none" stroke="#000" stroke-width=".25"/>
<circle cx="251.3" cy="82.2" r=".51" fill="#000080"/>
<circle cx="251.3" cy="82.2" r=".51" fill="none" stroke="#000080" stroke-width=".21"/>
<path d="M276.7 79.6h5.1" fill="none" stroke="#000" stroke-width=".25"/>
<circle cx="281.8" cy="79.6" r=".51" fill="#000080"/>
<circle cx="281.8" cy="79.6" r=".51" fill="none" stroke="#000080" stroke-width=".21"/>
<path d="M276.7 82.2h5.1" fill="none" stroke="#000" stroke-width=".25"/>
<circle cx="281.8" cy="82.2" r=".51" fill="#000080"/>
<circle cx="281.8" cy="82.2" r=".51" fill="none" stroke="#000080" stroke-width=".21"/>
<path d="M251.3 84.7h5.1" fill="none" stroke="#000" stroke-width=".25"/>
<circle cx="251.3" cy="84.7" r=".51" fill="#000080"/>
<circle cx="251.3" cy="84.7" r=".51" fill="none" stroke="#000080" stroke-width=".21"/>
<path d="M251.3 87.2h5.1M276.7 84.7h5.1" fill="none" stroke="#000" stroke-width=".25"/>
<circle cx="281.8" cy="84.7" r=".51" fill="#000080"/>
<circle cx="281.8" cy="84.7" r=".51" fill="none" stroke="#000080" stroke-width=".21"/>
<path d="M276.7 87.2h5.1" fill="none" stroke="#000" stroke-width=".25"/>
<circle cx="281.8" cy="87.3" r=".51" fill="#000080"/>
<circle cx="281.8" cy="87.3" r=".51" fill="none" stroke="#000080" stroke-width=".21"/>
<path d="M251.3 31.4h5.1" fill="none" stroke="#000" stroke-width=".25"/>
<path d="M254.9 30.9l1.5 .5-1.5 .5z" fill="#f8fcff"/>
<path d="M254.9 30.9l1.5 .5-1.5 .5z" fill="none" stroke="#000" stroke-width=".21"/>
<path d="M251.3 28.8h5.1" fill="none" stroke="#000" stroke-width=".25"/>
<path d="M254.9 28.3l1.5 .5-1.5 .5z" fill="#f8fcff"/>
<path d="M254.9 28.3l1.5 .5-1.5 .5z" fill="none" stroke="#000" stroke-width=".21"/>
<circle cx="251.3" cy="28.8" r=".51" fill="#000080"/>
<circle cx="251.3" cy="28.8" r=".51" fill="none" stroke="#000080" stroke-width=".21"/>
<path d="M40.5 117.7h15.3v12.7h-15.3z" fill-rule="evenodd" fill="#ffffb0"/>
<path d="M40.5 117.7h15.3v12.7h-15.3z" fill="none" stroke="#800000" stroke-width=".21"/>
<path d="M35.4 120.3h5.1M35.4 122.8h5.1M35.4 125.3h5.1M35.4 127.9h5.1M55.8 120.3h5M55.8 122.8h5M55.8 125.3h5" fill="none" stroke="#000" stroke-width=".25"/>
<path d="M121.8 23.7h20.3v86.4h-20.3z" fill-rule="evenodd" fill="#ffffb0"/>
<path d="M121.8 23.7h20.3v86.4h-20.3z" fill="none" stroke="#800000" stroke-width=".21"/>
<path d="M142.1 59.3h5.1" fill="none" stroke="#000" stroke-width=".25"/>
<path d="M142.1 59.3l1.5-.5v1z" fill="#f8fcff"/>
<path d="M142.1 59.3l1.5-.5v1z" fill="none" stroke="#000" stroke-width=".21"/>
<path d="M143.9 58.8l1.5 .5-1.5 .5z" fill="#f8fcff"/>
<path d="M143.9 58.8l1.5 .5-1.5 .5z" fill="none" stroke="#000" stroke-width=".21"/>
<path d="M142.1 64.4h5.1" fill="none" stroke="#000" stroke-width=".25"/>
<path d="M142.1 64.4l1.5-.5v1z" fill="#f8fcff"/>
<path d="M142.1 64.4l1.5-.5v1z" fill="none" stroke="#000" stroke-width=".21"/>
<path d="M143.9 63.9l1.5 .5-1.5 .5z" fill="#f8fcff"/>
<path d="M143.9 63.9l1.5 .5-1.5 .5z" fill="none" stroke="#000" stroke-width=".21"/>
<path d="M142.1 56.8h5.1" fill="none" stroke="#000" stroke-width=".25"/>
<path d="M142.1 56.8l1.5-.5v1z" fill="#f8fcff"/>
<path d="M142.1 56.8l1.5-.5v1z" fill="none" stroke="#000" stroke-width=".21"/>
<path d="M143.9 56.3l1.5 .5-1.5 .5z" fill="#f8fcff"/>
<path d="M143.9 56.3l1.5 .5-1.5 .5z" fill="none" stroke="#000" stroke-width=".21"/>
<path d="M142.1 79.6h5.1" fill="none" stroke="#000" stroke-width=".25"/>
<path d="M142.1 79.6l1.5-.5v1z" fill="#f8fcff"/>
<path d="M142.1 79.6l1.5-.5v1z" fill="none" stroke="#000" stroke-width=".21"/>
<path d="M143.9 79.1l1.5 .5-1.5 .5z" fill="#f8fcff"/>
<path d="M143.9 79.1l1.5 .5-1.5 .5z" fill="none" stroke="#000" stroke-width=".21"/>
<path d="M142.1 61.8h5.1" fill="none" stroke="#000" stroke-width=".25"/>
<path d="M142.1 61.8l1.5-.5v1.1z" fill="#f8fcff"/>
<path d="M142.1 61.8l1.5-.5v1.1z" fill="none" stroke="#000" stroke-width=".21"/>
<path d="M143.9 61.3l1.5 .5-1.5 .6z" fill="#f8fcff"/>
<path d="M143.9 61.3l1.5 .5-1.5 .6z" fill="none" stroke="#000" stroke-width=".21"/>
<path d="M142.1 54.2h5.1" fill="none" stroke="#000" stroke-width=".25"/>
<path d="M142.1 54.2l1.5-.5v1z" fill="#f8fcff"/>
<path d="M142.1 54.2l1.5-.5v1z" fill="none" stroke="#000" stroke-width=".21"/>
<path d="M143.9 53.7l1.5 .5-1.5 .5z" fill="#f8fcff"/>
<path d="M143.9 53.7l1.5 .5-1.5 .5z" fill="none" stroke="#000" stroke-width=".21"/>
<path d="M142.1 49.1h5.1" fill="none" stroke="#000" stroke-width=".25"/>
<path d="M142.1 49.1l1.5-.5v1.1z" fill="#f8fcff"/>
<path d="M142.1 49.1l1.5-.5v1.1z" fill="none" stroke="#000" stroke-width=".21"/>
<path d="M143.9 48.6l1.5 .5-1.5 .6z" fill="#f8fcff"/>
<path d="M143.9 48.6l1.5 .5-1.5 .6z" fill="none" stroke="#000" stroke-width=".21"/>
<path d="M142.1 77.1h5.1" fill="none" stroke="#000" stroke-width=".25"/>
<path d="M142.1 77.1l1.5-.5v1z" fill="#f8fcff"/>
<path d="M142.1 77.1l1.5-.5v1z" fill="none" stroke="#000" stroke-width=".21"/>
<path d="M143.9 76.6l1.5 .5-1.5 .5z" fill="#f8fcff"/>
<path d="M143.9 76.6l1.5 .5-1.5 .5z" fill="none" stroke="#000" stroke-width=".21"/>
<path d="M142.1 51.7h5.1" fill="none" stroke="#000" stroke-width=".25"/>
<path d="M142.1 51.7l1.5-.5v1z" fill="#f8fcff"/>
<path d="M142.1 51.7l1.5-.5v1z" fill="none" stroke="#000" stroke-width=".21"/>
<path d="M143.9 51.2l1.5 .5-1.5 .5z" fill="#f8fcff"/>
<path d="M143.9 51.2l1.5 .5-1.5 .5z" fill="none" stroke="#000" stroke-width=".21"/>
<path d="M142.1 87.2h5.1" fill="none" stroke="#000" stroke-width=".25"/>
<path d="M142.1 87.2l1.5-.5v1.1z" fill="#f8fcff"/>
<path d="M142.1 87.2l1.5-.5v1.1z" fill="none" stroke="#000" stroke-width=".21"/>
<path d="M142.1 46.6h5.1" fill="none" stroke="#000" stroke-width=".25"/>
<path d="M142.1 46.6l1.5-.5v1z" fill="#f8fcff"/>
<path d="M142.1 46.6l1.5-.5v1z" fill="none" stroke="#000" stroke-width=".21"/>
<path d="M143.9 46.1l1.5 .5-1.5 .5z" fill="#f8fcff"/>
<path d="M143.9 46.1l1.5 .5-1.5 .5z" fill="none" stroke="#000" stroke-width=".21"/>
<path d="M142.1 26.3h5.1" fill="none" stroke="#000" stroke-width=".25"/>
<path d="M142.1 26.3l1.5-.5v1z" fill="#f8fcff"/>
<path d="M142.1 26.3l1.5-.5v1z" fill="none" stroke="#000" stroke-width=".21"/>
<path d="M143.9 25.8l1.5 .5-1.5 .5z" fill="#f8fcff"/>
<path d="M143.9 25.8l1.5 .5-1.5 .5z" fill="none" stroke="#000" stroke-width=".21"/>
<path d="M142.1 84.7h5.1" fill="none" stroke="#000" stroke-width=".25"/>
<path d="M142.1 84.7l1.5-.5v1z" fill="#f8fcff"/>
<path d="M142.1 84.7l1.5-.5v1z" fill="none" stroke="#000" stroke-width=".21"/>
<path d="M142.1 31.4h5.1" fill="none" stroke="#000" stroke-width=".25"/>
<path d="M142.1 31.4l1.5-.5v1z" fill="#f8fcff"/>
<path d="M142.1 31.4l1.5-.5v1z" fill="none" stroke="#000" stroke-width=".21"/>
<path d="M143.9 30.9l1.5 .5-1.5 .5z" fill="#f8fcff"/>
<path d="M143.9 30.9l1.5 .5-1.5 .5z" fill="none" stroke="#000" stroke-width=".21"/>
<path d="M142.1 69.5h5.1" fill="none" stroke="#000" stroke-width=".25"/>
<path d="M142.1 69.5l1.5-.5v1z" fill="#f8fcff"/>
<path d="M142.1 69.5l1.5-.5v1z" fill="none" stroke="#000" stroke-width=".21"/>
<path d="M143.9 69l1.5 .5-1.5 .5z" fill="#f8fcff"/>
<path d="M143.9 69l1.5 .5-1.5 .5z" fill="none" stroke="#000" stroke-width=".21"/>
<path d="M142.1 28.8h5.1" fill="none" stroke="#000" stroke-width=".25"/>
<path d="M142.1 28.8l1.5-.5v1z" fill="#f8fcff"/>
<path d="M142.1 28.8l1.5-.5v1z" fill="none" stroke="#000" stroke-width=".21"/>
<path d="M143.9 28.3l1.5 .5-1.5 .5z" fill="#f8fcff"/>
<path d="M143.9 28.3l1.5 .5-1.5 .5z" fill="none" stroke="#000" stroke-width=".21"/>
<path d="M142.1 33.9h5.1" fill="none" stroke="#000" stroke-width=".25"/>
<path d="M142.1 33.9l1.5-.5v1z" fill="#f8fcff"/>
<path d="M142.1 33.9l1.5-.5v1z" fill="none" stroke="#000" stroke-width=".21"/>
<path d="M143.9 33.4l1.5 .5-1.5 .5z" fill="#f8fcff"/>
<path d="M143.9 33.4l1.5 .5-1.5 .5z" fill="none" stroke="#000" stroke-width=".21"/>
<path d="M142.1 41.5h5.1" fill="none" stroke="#000" stroke-width=".25"/>
<path d="M142.1 41.5l1.5-.5v1z" fill="#f8fcff"/>
<path d="M142.1 41.5l1.5-.5v1z" fill="none" stroke="#000" stroke-width=".21"/>
<path d="M143.9 41l1.5 .5-1.5 .5z" fill="#f8fcff"/>
<path d="M143.9 41l1.5 .5-1.5 .5z" fill="none" stroke="#000" stroke-width=".21"/>
<path d="M142.1 72h5.1" fill="none" stroke="#000" stroke-width=".25"/>
<path d="M142.1 72l1.5-.5v1z" fill="#f8fcff"/>
<path d="M142.1 72l1.5-.5v1z" fill="none" stroke="#000" stroke-width=".21"/>
<path d="M143.9 71.5l1.5 .5-1.5 .5z" fill="#f8fcff"/>
<path d="M143.9 71.5l1.5 .5-1.5 .5z" fill="none" stroke="#000" stroke-width=".21"/>
<path d="M142.1 36.4h5.1" fill="none" stroke="#000" stroke-width=".25"/>
<path d="M142.1 36.4l1.5-.5v1.1z" fill="#f8fcff"/>
<path d="M142.1 36.4l1.5-.5v1.1z" fill="none" stroke="#000" stroke-width=".21"/>
<path d="M143.9 35.9l1.5 .5-1.5 .6z" fill="#f8fcff"/>
<path d="M143.9 35.9l1.5 .5-1.5 .6z" fill="none" stroke="#000" stroke-width=".21"/>
<path d="M142.1 44.1h5.1" fill="none" stroke="#000" stroke-width=".25"/>
<path d="M142.1 44.1l1.5-.5v1z" fill="#f8fcff"/>
<path d="M142.1 44.1l1.5-.5v1z" fill="none" stroke="#000" stroke-width=".21"/>
<path d="M143.9 43.6l1.5 .5-1.5 .5z" fill="#f8fcff"/>
<path d="M143.9 43.6l1.5 .5-1.5 .5z" fill="none" stroke="#000" stroke-width=".21"/>
<path d="M142.1 39h5.1" fill="none" stroke="#000" stroke-width=".25"/>
<path d="M142.1 39l1.5-.5v1z" fill="#f8fcff"/>
<path d="M142.1 39l1.5-.5v1z" fill="none" stroke="#000" stroke-width=".21"/>
<path d="M143.9 38.5l1.5 .5-1.5 .5z" fill="#f8fcff"/>
<path d="M143.9 38.5l1.5 .5-1.5 .5z" fill="none" stroke="#000" stroke-width=".21"/>
<path d="M116.7 97.4h5.1" fill="none" stroke="#000" stroke-width=".25"/>
<path d="M120.3 96.9l1.5 .5-1.5 .5z" fill="#f8fcff"/>
<path d="M120.3 96.9l1.5 .5-1.5 .5z" fill="none" stroke="#000" stroke-width=".21"/>
<path d="M116.7 79.6h5.1" fill="none" stroke="#000" stroke-width=".25"/>
<path d="M120.3 79.1l1.5 .5-1.5 .5z" fill="#f8fcff"/>
<path d="M120.3 79.1l1.5 .5-1.5 .5zM121.8 79.1l1 .5-1 .5" fill="none" stroke="#000" stroke-width=".21"/>
<path d="M116.7 107.6h5.1" fill="none" stroke="#000" stroke-width=".25"/>
<path d="M120.3 107.1l1.5 .5-1.5 .5z" fill="#f8fcff"/>
<path d="M120.3 107.1l1.5 .5-1.5 .5z" fill="none" stroke="#000" stroke-width=".21"/>
<path d="M116.7 94.9h5.1" fill="none" stroke="#000" stroke-width=".25"/>
<path d="M120.3 94.4l1.5 .5-1.5 .5z" fill="#f8fcff"/>
<path d="M120.3 94.4l1.5 .5-1.5 .5z" fill="none" stroke="#000" stroke-width=".21"/>
<path d="M116.7 82.2h5.1" fill="none" stroke="#000" stroke-width=".25"/>
<path d="M120.3 81.7l1.5 .5-1.5 .5z" fill="#f8fcff"/>
<path d="M120.3 81.7l1.5 .5-1.5 .5zM121.8 81.7l1 .5-1 .5" fill="none" stroke="#000" stroke-width=".21"/>
<path d="M116.7 84.7h5.1" fill="none" stroke="#000" stroke-width=".25"/>
<path d="M120.3 84.2l1.5 .5-1.5 .5z" fill="#f8fcff"/>
<path d="M120.3 84.2l1.5 .5-1.5 .5z" fill="none" stroke="#000" stroke-width=".21"/>
<path d="M116.7 99.9h5.1" fill="none" stroke="#000" stroke-width=".25"/>
<path d="M120.3 99.4l1.5 .5-1.5 .6z" fill="#f8fcff"/>
<path d="M120.3 99.4l1.5 .5-1.5 .6z" fill="none" stroke="#000" stroke-width=".21"/>
<path d="M116.7 92.3h5.1" fill="none" stroke="#000" stroke-width=".25"/>
<path d="M120.3 91.8l1.5 .5-1.5 .5z" fill="#f8fcff"/>
<path d="M120.3 91.8l1.5 .5-1.5 .5z" fill="none" stroke="#000" stroke-width=".21"/>
<path d="M116.7 51.7h5.1" fill="none" stroke="#000" stroke-width=".25"/>
<path d="M120.3 51.2l1.5 .5-1.5 .5z" fill="#f8fcff"/>
<path d="M120.3 51.2l1.5 .5-1.5 .5z" fill="none" stroke="#000" stroke-width=".21"/>
<path d="M142.1 107.6h5.1" fill="none" stroke="#000" stroke-width=".25"/>
<path d="M142.1 107.6l1.5-.5v1z" fill="#f8fcff"/>
<path d="M142.1 107.6l1.5-.5v1z" fill="none" stroke="#000" stroke-width=".21"/>
<path d="M116.7 69.5h5.1" fill="none" stroke="#000" stroke-width=".25"/>
<path d="M120.3 69l1.5 .5-1.5 .5z" fill="#f8fcff"/>
<path d="M120.3 69l1.5 .5-1.5 .5z" fill="none" stroke="#000" stroke-width=".21"/>
<path d="M116.7 74.5h5.1" fill="none" stroke="#000" stroke-width=".25"/>
<path d="M120.3 74l1.5 .5-1.5 .6z" fill="#f8fcff"/>
<path d="M120.3 74l1.5 .5-1.5 .6z" fill="none" stroke="#000" stroke-width=".21"/>
<path d="M116.7 33.9h5.1" fill="none" stroke="#000" stroke-width=".25"/>
<path d="M120.3 33.4l1.5 .5-1.5 .5z" fill="#f8fcff"/>
<path d="M120.3 33.4l1.5 .5-1.5 .5z" fill="none" stroke="#000" stroke-width=".21"/>
<path d="M116.7 26.3h5.1" fill="none" stroke="#000" stroke-width=".25"/>
<path d="M120.3 25.8l1.5 .5-1.5 .5z" fill="#f8fcff"/>
<path d="M120.3 25.8l1.5 .5-1.5 .5z" fill="none" stroke="#000" stroke-width=".21"/>
<path d="M116.7 56.8h5.1" fill="none" stroke="#000" stroke-width=".25"/>
<path d="M120.3 56.3l1.5 .5-1.5 .5z" fill="#f8fcff"/>
<path d="M120.3 56.3l1.5 .5-1.5 .5z" fill="none" stroke="#000" stroke-width=".21"/>
<path d="M116.7 72h5.1" fill="none" stroke="#000" stroke-width=".25"/>
<path d="M120.3 71.5l1.5 .5-1.5 .5z" fill="#f8fcff"/>
<path d="M120.3 71.5l1.5 .5-1.5 .5z" fill="none" stroke="#000" stroke-width=".21"/>
<path d="M116.7 39h5.1" fill="none" stroke="#000" stroke-width=".25"/>
<path d="M120.3 38.5l1.5 .5-1.5 .5z" fill="#f8fcff"/>
<path d="M120.3 38.5l1.5 .5-1.5 .5z" fill="none" stroke="#000" stroke-width=".21"/>
<path d="M116.7 31.4h5.1" fill="none" stroke="#000" stroke-width=".25"/>
<path d="M120.3 30.9l1.5 .5-1.5 .5z" fill="#f8fcff"/>
<path d="M120.3 30.9l1.5 .5-1.5 .5z" fill="none" stroke="#000" stroke-width=".21"/>
<path d="M116.7 28.8h5.1" fill="none" stroke="#000" stroke-width=".25"/>
<path d="M120.3 28.3l1.5 .5-1.5 .5z" fill="#f8fcff"/>
<path d="M120.3 28.3l1.5 .5-1.5 .5z" fill="none" stroke="#000" stroke-width=".21"/>
<path d="M116.7 36.4h5.1" fill="none" stroke="#000" stroke-width=".25"/>
<path d="M120.3 35.9l1.5 .5-1.5 .6z" fill="#f8fcff"/>
<path d="M120.3 35.9l1.5 .5-1.5 .6z" fill="none" stroke="#000" stroke-width=".21"/>
<path d="M116.7 44.1h5.1" fill="none" stroke="#000" stroke-width=".25"/>
<path d="M120.3 43.6l1.5 .5-1.5 .5z" fill="#f8fcff"/>
<path d="M120.3 43.6l1.5 .5-1.5 .5z" fill="none" stroke="#000" stroke-width=".21"/>
<path d="M116.7 49.1h5.1" fill="none" stroke="#000" stroke-width=".25"/>
<path d="M120.3 48.6l1.5 .5-1.5 .6z" fill="#f8fcff"/>
<path d="M120.3 48.6l1.5 .5-1.5 .6z" fill="none" stroke="#000" stroke-width=".21"/>
<path d="M116.7 54.2h5.1" fill="none" stroke="#000" stroke-width=".25"/>
<path d="M120.3 53.7l1.5 .5-1.5 .5z" fill="#f8fcff"/>
<path d="M120.3 53.7l1.5 .5-1.5 .5z" fill="none" stroke="#000" stroke-width=".21"/>
<path d="M116.7 41.5h5.1" fill="none" stroke="#000" stroke-width=".25"/>
<path d="M120.3 41l1.5 .5-1.5 .5z" fill="#f8fcff"/>
<path d="M120.3 41l1.5 .5-1.5 .5z" fill="none" stroke="#000" stroke-width=".21"/>
<path d="M142.1 102.5h5.1" fill="none" stroke="#000" stroke-width=".25"/>
<path d="M142.1 102.5l1.5-.5v1z" fill="#f8fcff"/>
<path d="M142.1 102.5l1.5-.5v1z" fill="none" stroke="#000" stroke-width=".21"/>
<path d="M116.7 46.6h5.1" fill="none" stroke="#000" stroke-width=".25"/>
<path d="M120.3 46.1l1.5 .5-1.5 .5z" fill="#f8fcff"/>
<path d="M120.3 46.1l1.5 .5-1.5 .5z" fill="none" stroke="#000" stroke-width=".21"/>
<circle cx="251.3" cy="112.7" r=".51" fill="#000080"/>
<circle cx="251.3" cy="112.7" r=".51" fill="none" stroke="#000080" stroke-width=".21"/>
<circle cx="251.3" cy="115.2" r=".51" fill="#000080"/>
<circle cx="251.3" cy="115.2" r=".51" fill="none" stroke="#000080" stroke-width=".21"/>
<circle cx="281.8" cy="135.5" r=".51" fill="#000080"/>
<circle cx="281.8" cy="135.5" r=".51" fill="none" stroke="#000080" stroke-width=".21"/>
<circle cx="251.3" cy="143.1" r=".51" fill="#000080"/>
<circle cx="251.3" cy="143.1" r=".51" fill="none" stroke="#000080" stroke-width=".21"/>
<circle cx="281.8" cy="138.1" r=".51" fill="#000080"/>
<circle cx="281.8" cy="138.1" r=".51" fill="none" stroke="#000080" stroke-width=".21"/>
<circle cx="281.8" cy="115.2" r=".51" fill="#000080"/>
<circle cx="281.8" cy="115.2" r=".51" fill="none" stroke="#000080" stroke-width=".21"/>
<circle cx="251.3" cy="117.7" r=".51" fill="#000080"/>
<circle cx="251.3" cy="117.7" r=".51" fill="none" stroke="#000080" stroke-width=".21"/>
<circle cx="251.3" cy="120.3" r=".51" fill="#000080"/>
<circle cx="251.3" cy="120.3" r=".51" fill="none" stroke="#000080" stroke-width=".21"/>
<circle cx="281.8" cy="117.7" r=".51" fill="#000080"/>
<circle cx="281.8" cy="117.7" r=".51" fill="none" stroke="#000080" stroke-width=".21"/>
<circle cx="251.3" cy="122.8" r=".51" fill="#000080"/>
<circle cx="251.3" cy="122.8" r=".51" fill="none" stroke="#000080" stroke-width=".21"/>
<circle cx="281.8" cy="120.3" r=".51" fill="#000080"/>
<circle cx="281.8" cy="120.3" r=".51" fill="none" stroke="#000080" stroke-width=".21"/>
<circle cx="251.3" cy="145.7" r=".51" fill="#000080"/>
<circle cx="251.3" cy="145.7" r=".51" fill="none" stroke="#000080" stroke-width=".21"/>
<circle cx="281.8" cy="140.6" r=".51" fill="#000080"/>
<circle cx="281.8" cy="140.6" r=".51" fill="none" stroke="#000080" stroke-width=".21"/>
<circle cx="281.8" cy="122.8" r=".51" fill="#000080"/>
<circle cx="281.8" cy="122.8" r=".51" fill="none" stroke="#000080" stroke-width=".21"/>
<circle cx="281.8" cy="125.4" r=".51" fill="#000080"/>
<circle cx="281.8" cy="125.4" r=".51" fill="none" stroke="#000080" stroke-width=".21"/>
<circle cx="251.3" cy="127.9" r=".51" fill="#000080"/>
<circle cx="251.3" cy="127.9" r=".51" fill="none" stroke="#000080" stroke-width=".21"/>
<circle cx="251.3" cy="125.4" r=".51" fill="#000080"/>
<circle cx="251.3" cy="125.4" r=".51" fill="none" stroke="#000080" stroke-width=".21"/>
<circle cx="281.8" cy="127.9" r=".51" fill="#000080"/>
<circle cx="281.8" cy="127.9" r=".51" fill="none" stroke="#000080" stroke-width=".21"/>
<circle cx="281.8" cy="130.4" r=".51" fill="#000080"/>
<circle cx="281.8" cy="130.4" r=".51" fill="none" stroke="#000080" stroke-width=".21"/>
<circle cx="251.3" cy="148.2" r=".51" fill="#000080"/>
<circle cx="251.3" cy="148.2" r=".51" fill="none" stroke="#000080" stroke-width=".21"/>
<circle cx="281.8" cy="143.1" r=".51" fill="#000080"/>
<circle cx="281.8" cy="143.1" r=".51" fill="none" stroke="#000080" stroke-width=".21"/>
<circle cx="281.8" cy="133" r=".51" fill="#000080"/>
<circle cx="281.8" cy="133" r=".51" fill="none" stroke="#000080" stroke-width=".21"/>
<circle cx="251.3" cy="130.4" r=".51" fill="#000080"/>
<circle cx="251.3" cy="130.4" r=".51" fill="none" stroke="#000080" stroke-width=".21"/>
<circle cx="281.8" cy="145.7" r=".51" fill="#000080"/>
<circle cx="281.8" cy="145.7" r=".51" fill="none" stroke="#000080" stroke-width=".21"/>
<circle cx="281.8" cy="148.2" r=".51" fill="#000080"/>
<circle cx="281.8" cy="148.2" r=".51" fill="none" stroke="#000080" stroke-width=".21"/>
<circle cx="251.3" cy="150.8" r=".51" fill="#000080"/>
<circle cx="251.3" cy="150.8" r=".51" fill="none" stroke="#000080" stroke-width=".21"/>
<circle cx="251.3" cy="153.3" r=".51" fill="#000080"/>
<circle cx="251.3" cy="153.3" r=".51" fill="none" stroke="#000080" stroke-width=".21"/>
<circle cx="281.8" cy="150.8" r=".51" fill="#000080"/>
<circle cx="281.8" cy="150.8" r=".51" fill="none" stroke="#000080" stroke-width=".21"/>
<circle cx="281.8" cy="153.3" r=".51" fill="#000080"/>
<circle cx="281.8" cy="153.3" r=".51" fill="none" stroke="#000080" stroke-width=".21"/>
<circle cx="251.3" cy="155.8" r=".51" fill="#000080"/>
<circle cx="251.3" cy="155.8" r=".51" fill="none" stroke="#000080" stroke-width=".21"/>
<circle cx="251.3" cy="158.4" r=".51" fill="#000080"/>
<circle cx="251.3" cy="158.4" r=".51" fill="none" stroke="#000080" stroke-width=".21"/>
<circle cx="281.8" cy="155.8" r=".51" fill="#000080"/>
<circle cx="281.8" cy="155.8" r=".51" fill="none" stroke="#000080" stroke-width=".21"/>
<circle cx="281.8" cy="158.4" r=".51" fill="#000080"/>
<circle cx="281.8" cy="158.4" r=".51" fill="none" stroke="#000080" stroke-width=".21"/>
<circle cx="251.3" cy="160.9" r=".51" fill="#000080"/>
<circle cx="251.3" cy="160.9" r=".51" fill="none" stroke="#000080" stroke-width=".21"/>
<circle cx="281.8" cy="160.9" r=".51" fill="#000080"/>
<circle cx="281.8" cy="160.9" r=".51" fill="none" stroke="#000080" stroke-width=".21"/>
<circle cx="281.8" cy="163.5" r=".51" fill="#000080"/>
<circle cx="281.8" cy="163.5" r=".51" fill="none" stroke="#000080" stroke-width=".21"/>
<circle cx="251.3" cy="105" r=".51" fill="#000080"/>
<circle cx="251.3" cy="105" r=".51" fill="none" stroke="#000080" stroke-width=".21"/>
<path d="M256.4 102.5h20.3v63.5h-20.3z" fill-rule="evenodd" fill="#ffffb0"/>
<path d="M256.4 102.5h20.3v63.5h-20.3z" fill="none" stroke="#800000" stroke-width=".21"/>
<path d="M251.3 112.6h5.1" fill="none" stroke="#000" stroke-width=".25"/>
<circle cx="251.3" cy="112.7" r=".51" fill="#000080"/>
<circle cx="251.3" cy="112.7" r=".51" fill="none" stroke="#000080" stroke-width=".21"/>
<path d="M251.3 115.2h5.1" fill="none" stroke="#000" stroke-width=".25"/>
<circle cx="251.3" cy="115.2" r=".51" fill="#000080"/>
<circle cx="251.3" cy="115.2" r=".51" fill="none" stroke="#000080" stroke-width=".21"/>
<path d="M276.7 135.5h5.1" fill="none" stroke="#000" stroke-width=".25"/>
<circle cx="281.8" cy="135.5" r=".51" fill="#000080"/>
<circle cx="281.8" cy="135.5" r=".51" fill="none" stroke="#000080" stroke-width=".21"/>
<path d="M276.7 112.6h5.1M251.3 143.1h5.1" fill="none" stroke="#000" stroke-width=".25"/>
<circle cx="251.3" cy="143.1" r=".51" fill="#000080"/>
<circle cx="251.3" cy="143.1" r=".51" fill="none" stroke="#000080" stroke-width=".21"/>
<path d="M276.7 138h5.1" fill="none" stroke="#000" stroke-width=".25"/>
<circle cx="281.8" cy="138.1" r=".51" fill="#000080"/>
<circle cx="281.8" cy="138.1" r=".51" fill="none" stroke="#000080" stroke-width=".21"/>
<path d="M276.7 115.2h5.1" fill="none" stroke="#000" stroke-width=".25"/>
<circle cx="281.8" cy="115.2" r=".51" fill="#000080"/>
<circle cx="281.8" cy="115.2" r=".51" fill="none" stroke="#000080" stroke-width=".21"/>
<path d="M251.3 117.7h5.1" fill="none" stroke="#000" stroke-width=".25"/>
<circle cx="251.3" cy="117.7" r=".51" fill="#000080"/>
<circle cx="251.3" cy="117.7" r=".51" fill="none" stroke="#000080" stroke-width=".21"/>
<path d="M251.3 120.3h5.1" fill="none" stroke="#000" stroke-width=".25"/>
<circle cx="251.3" cy="120.3" r=".51" fill="#000080"/>
<circle cx="251.3" cy="120.3" r=".51" fill="none" stroke="#000080" stroke-width=".21"/>
<path d="M276.7 117.7h5.1" fill="none" stroke="#000" stroke-width=".25"/>
<circle cx="281.8" cy="117.7" r=".51" fill="#000080"/>
<circle cx="281.8" cy="117.7" r=".51" fill="none" stroke="#000080" stroke-width=".21"/>
<path d="M251.3 122.8h5.1" fill="none" stroke="#000" stroke-width=".25"/>
<circle cx="251.3" cy="122.8" r=".51" fill="#000080"/>
<circle cx="251.3" cy="122.8" r=".51" fill="none" stroke="#000080" stroke-width=".21"/>
<path d="M276.7 120.3h5.1" fill="none" stroke="#000" stroke-width=".25"/>
<circle cx="281.8" cy="120.3" r=".51" fill="#000080"/>
<circle cx="281.8" cy="120.3" r=".51" fill="none" stroke="#000080" stroke-width=".21"/>
<path d="M251.3 145.7h5.1" fill="none" stroke="#000" stroke-width=".25"/>
<circle cx="251.3" cy="145.7" r=".51" fill="#000080"/>
<circle cx="251.3" cy="145.7" r=".51" fill="none" stroke="#000080" stroke-width=".21"/>
<path d="M276.7 140.6h5.1" fill="none" stroke="#000" stroke-width=".25"/>
<circle cx="281.8" cy="140.6" r=".51" fill="#000080"/>
<circle cx="281.8" cy="140.6" r=".51" fill="none" stroke="#000080" stroke-width=".21"/>
<path d="M276.7 122.8h5.1" fill="none" stroke="#000" stroke-width=".25"/>
<circle cx="281.8" cy="122.8" r=".51" fill="#000080"/>
<circle cx="281.8" cy="122.8" r=".51" fill="none" stroke="#000080" stroke-width=".21"/>
<path d="M276.7 125.3h5.1" fill="none" stroke="#000" stroke-width=".25"/>
<circle cx="281.8" cy="125.4" r=".51" fill="#000080"/>
<circle cx="281.8" cy="125.4" r=".51" fill="none" stroke="#000080" stroke-width=".21"/>
<path d="M251.3 127.9h5.1" fill="none" stroke="#000" stroke-width=".25"/>
<circle cx="251.3" cy="127.9" r=".51" fill="#000080"/>
<circle cx="251.3" cy="127.9" r=".51" fill="none" stroke="#000080" stroke-width=".21"/>
<path d="M251.3 125.3h5.1" fill="none" stroke="#000" stroke-width=".25"/>
<circle cx="251.3" cy="125.4" r=".51" fill="#000080"/>
<circle cx="251.3" cy="125.4" r=".51" fill="none" stroke="#000080" stroke-width=".21"/>
<path d="M276.7 127.9h5.1" fill="none" stroke="#000" stroke-width=".25"/>
<circle cx="281.8" cy="127.9" r=".51" fill="#000080"/>
<circle cx="281.8" cy="127.9" r=".51" fill="none" stroke="#000080" stroke-width=".21"/>
<path d="M276.7 130.4h5.1" fill="none" stroke="#000" stroke-width=".25"/>
<circle cx="281.8" cy="130.4" r=".51" fill="#000080"/>
<circle cx="281.8" cy="130.4" r=".51" fill="none" stroke="#000080" stroke-width=".21"/>
<path d="M251.3 148.2h5.1" fill="none" stroke="#000" stroke-width=".25"/>
<circle cx="251.3" cy="148.2" r=".51" fill="#000080"/>
<circle cx="251.3" cy="148.2" r=".51" fill="none" stroke="#000080" stroke-width=".21"/>
<path d="M276.7 143.1h5.1" fill="none" stroke="#000" stroke-width=".25"/>
<circle cx="281.8" cy="143.1" r=".51" fill="#000080"/>
<circle cx="281.8" cy="143.1" r=".51" fill="none" stroke="#000080" stroke-width=".21"/>
<path d="M276.7 133h5.1" fill="none" stroke="#000" stroke-width=".25"/>
<circle cx="281.8" cy="133" r=".51" fill="#000080"/>
<circle cx="281.8" cy="133" r=".51" fill="none" stroke="#000080" stroke-width=".21"/>
<path d="M251.3 130.4h5.1" fill="none" stroke="#000" stroke-width=".25"/>
<circle cx="251.3" cy="130.4" r=".51" fill="#000080"/>
<circle cx="251.3" cy="130.4" r=".51" fill="none" stroke="#000080" stroke-width=".21"/>
<path d="M251.3 133h5.1M276.7 145.7h5.1" fill="none" stroke="#000" stroke-width=".25"/>
<circle cx="281.8" cy="145.7" r=".51" fill="#000080"/>
<circle cx="281.8" cy="145.7" r=".51" fill="none" stroke="#000080" stroke-width=".21"/>
<path d="M276.7 148.2h5.1" fill="none" stroke="#000" stroke-width=".25"/>
<circle cx="281.8" cy="148.2" r=".51" fill="#000080"/>
<circle cx="281.8" cy="148.2" r=".51" fill="none" stroke="#000080" stroke-width=".21"/>
<path d="M251.3 150.7h5.1" fill="none" stroke="#000" stroke-width=".25"/>
<circle cx="251.3" cy="150.8" r=".51" fill="#000080"/>
<circle cx="251.3" cy="150.8" r=".51" fill="none" stroke="#000080" stroke-width=".21"/>
<path d="M251.3 153.3h5.1" fill="none" stroke="#000" stroke-width=".25"/>
<circle cx="251.3" cy="153.3" r=".51" fill="#000080"/>
<circle cx="251.3" cy="153.3" r=".51" fill="none" stroke="#000080" stroke-width=".21"/>
<path d="M276.7 150.7h5.1" fill="none" stroke="#000" stroke-width=".25"/>
<circle cx="281.8" cy="150.8" r=".51" fill="#000080"/>
<circle cx="281.8" cy="150.8" r=".51" fill="none" stroke="#000080" stroke-width=".21"/>
<path d="M276.7 153.3h5.1" fill="none" stroke="#000" stroke-width=".25"/>
<circle cx="281.8" cy="153.3" r=".51" fill="#000080"/>
<circle cx="281.8" cy="153.3" r=".51" fill="none" stroke="#000080" stroke-width=".21"/>
<path d="M251.3 155.8h5.1" fill="none" stroke="#000" stroke-width=".25"/>
<circle cx="251.3" cy="155.8" r=".51" fill="#000080"/>
<circle cx="251.3" cy="155.8" r=".51" fill="none" stroke="#000080" stroke-width=".21"/>
<path d="M251.3 158.4h5.1" fill="none" stroke="#000" stroke-width=".25"/>
<circle cx="251.3" cy="158.4" r=".51" fill="#000080"/>
<circle cx="251.3" cy="158.4" r=".51" fill="none" stroke="#000080" stroke-width=".21"/>
<path d="M276.7 155.8h5.1" fill="none" stroke="#000" stroke-width=".25"/>
<circle cx="281.8" cy="155.8" r=".51" fill="#000080"/>
<circle cx="281.8" cy="155.8" r=".51" fill="none" stroke="#000080" stroke-width=".21"/>
<path d="M276.7 158.4h5.1" fill="none" stroke="#000" stroke-width=".25"/>
<circle cx="281.8" cy="158.4" r=".51" fill="#000080"/>
<circle cx="281.8" cy="158.4" r=".51" fill="none" stroke="#000080" stroke-width=".21"/>
<path d="M251.3 160.9h5.1" fill="none" stroke="#000" stroke-width=".25"/>
<circle cx="251.3" cy="160.9" r=".51" fill="#000080"/>
<circle cx="251.3" cy="160.9" r=".51" fill="none" stroke="#000080" stroke-width=".21"/>
<path d="M251.3 163.4h5.1M276.7 160.9h5.1" fill="none" stroke="#000" stroke-width=".25"/>
<circle cx="281.8" cy="160.9" r=".51" fill="#000080"/>
<circle cx="281.8" cy="160.9" r=".51" fill="none" stroke="#000080" stroke-width=".21"/>
<path d="M276.7 163.4h5.1" fill="none" stroke="#000" stroke-width=".25"/>
<circle cx="281.8" cy="163.5" r=".51" fill="#000080"/>
<circle cx="281.8" cy="163.5" r=".51" fill="none" stroke="#000080" stroke-width=".21"/>
<path d="M251.3 107.6h5.1" fill="none" stroke="#000" stroke-width=".25"/>
<path d="M254.9 107.1l1.5 .5-1.5 .5z" fill="#f8fcff"/>
<path d="M254.9 107.1l1.5 .5-1.5 .5z" fill="none" stroke="#000" stroke-width=".21"/>
<path d="M251.3 105h5.1" fill="none" stroke="#000" stroke-width=".25"/>
<path d="M254.9 104.5l1.5 .5-1.5 .5z" fill="#f8fcff"/>
<path d="M254.9 104.5l1.5 .5-1.5 .5z" fill="none" stroke="#000" stroke-width=".21"/>
<circle cx="251.3" cy="105" r=".51" fill="#000080"/>
<circle cx="251.3" cy="105" r=".51" fill="none" stroke="#000080" stroke-width=".21"/>
<path d="M124.3 117.7h15.3v12.7h-15.3z" fill-rule="evenodd" fill="#ffffb0"/>
<path d="M124.3 117.7h15.3v12.7h-15.3z" fill="none" stroke="#800000" stroke-width=".21"/>
<g fill="none" stroke="#000" stroke-width=".25">
<path d="M231 99.9h2.6M238.6 99.9h2.6M68.5 107.6h2M76.6 107.6h2M152.3 107.6h2M160.4 107.6h2M167.5 102.5h2M175.7 102.5h2M43.1 138h2M51.2 138h2M119.3 120.3h5M119.3 122.8h5"/>
<path d="M119.3 125.3h5M119.3 127.9h5M139.6 120.3h5.1M139.6 122.8h5.1M139.6 125.3h5.1M43.1 140.6h2M43.1 143.1h2M43.1 145.7h2M43.1 148.2h2M43.1 150.7h2M43.1 153.3h2M43.1 155.8h2"/>
<path d="M43.1 158.4h2M51.2 140.6h2M51.2 143.1h2M51.2 145.7h2M51.2 148.2h2M51.2 150.7h2M51.2 153.3h2M51.2 155.8h2M51.2 158.4h2M175.1 158.4v2M43.1 160.9h2M43.1 163.4h2"/>
<path d="M43.1 166h2M43.1 168.5h2M43.1 171.1h2M43.1 173.6h2M43.1 176.1h2M43.1 178.7h2M51.2 160.9h2M51.2 163.4h2M51.2 166h2M51.2 168.5h2M51.2 171.1h2M51.2 173.6h2"/>
<path d="M51.2 176.1h2M51.2 178.7h2M175.1 166.5v2M43.1 181.2h2M43.1 183.8h2M43.1 186.3h2M43.1 188.8h2M43.1 191.4h2M51.2 181.2h2M51.2 183.8h2M51.2 186.3h2M51.2 188.8h2"/>
<path d="M51.2 191.4h2"/>
</g>
<g fill="none" stroke="#800000" stroke-width=".25">
<path d="M191.7 31.4h2.5M192.9 31.4v2.5M191.7 61.8h2.5M192.9 61.8v2.6M279.3 92.3h5.1M280 93.1h3.6M280.8 93.9h2M281.6 94.6h.5M281.8 89.8v2.5M81.2 112.6h5M81.9 113.4h3.6M82.7 114.2h2"/>
<path d="M83.4 114.9h.6M83.7 110.1v2.5M165 112.6h5.1M165.7 113.4h3.6M166.5 114.2h2M167.3 114.9h.5M167.5 110.1v2.5M177.7 112.6h5.1M178.4 113.4h3.6M179.2 114.2h2M180 114.9h.5M180.2 110.1v2.5"/>
<path d="M191.7 107.6h2.5M192.9 107.6v2.5M191.7 138h2.5M192.9 138v2.6M279.3 168.5h5.1M280 169.3h3.6M280.8 170.1h2M281.6 170.8h.5M281.8 166v2.5"/>
</g>
<g fill="none" stroke="#f00" stroke-width=".21">
<path d="M63.4 25v.8M63.4 26.3v.8M63.4 27.6v.7M63.4 28.8v.8M63.4 30.1v.8M63.4 31.4v.8M63.4 32.6v.8M63.4 33.9v.8M63.4 35.2v.8M63.4 36.4v.8M63.4 37.7v.8M63.4 39v.8"/>
<path d="M64.2 23.7h-.8v.8M64.6 23.7h.8M65.9 23.7h.8M67.2 23.7h.8M68.5 23.7h.7M69.7 23.7h.8M71 23.7h.8M72.3 23.7h.8M73.5 23.7h.8M74.8 23.7h.8M76.1 23.7h.8M77.3 23.7h.8"/>
<path d="M78.6 23.7h.8M79.9 23.7h.8M81.2 23.7v.8M81.2 25v.8M81.2 26.3v.8M81.2 27.6v.7M81.2 28.8v.8M81.2 30.1v.8M81.2 31.4v.8M81.2 32.6v.8M81.2 33.9v.8M81.2 35.2v.8"/>
<path d="M81.2 36.4v.8M81.2 37.7v.8M81.2 39v.8M147.2 25v.8M147.2 26.3v.8M147.2 27.6v.7M147.2 28.8v.8M147.2 30.1v.8M147.2 31.4v.8M147.2 32.6v.8M147.2 33.9v.8M147.2 35.2v.8"/>
<path d="M147.2 36.4v.8M147.2 37.7v.8M147.2 39v.8M148 23.7h-.8v.8M148.5 23.7h.8M149.7 23.7h.8M151 23.7h.8M152.3 23.7h.8M153.5 23.7h.8M154.8 23.7h.8M156.1 23.7h.8M157.4 23.7h.8"/>
<path d="M158.6 23.7h.8M159.9 23.7h.8M161.2 23.7h.8M162.4 23.7h.8M163.7 23.7h.8M165 23.7v.8M165 25v.8M165 26.3v.8M165 27.6v.7M165 28.8v.8M165 30.1v.8M165 31.4v.8"/>
<path d="M165 32.6v.8M165 33.9v.8M165 35.2v.8M165 36.4v.8M165 37.7v.8M165 39v.8M63.4 40.3v.7M63.4 41.5v.8M63.4 42.8v.8M63.4 47.1v.8M63.4 48.3v.8M63.4 49.6v.8"/>
<path d="M63.4 50.9v.8M63.4 52.2v.8M63.4 53.4v.8M63.4 54.7v.8M63.4 56v.8M63.4 57.2v.8M63.4 58.5v.8M63.4 59.8v.8M63.4 46.6h.8M63.9 44.1h.7M64.6 46.6h.8M65.1 44.1h.8"/>
<path d="M65.9 46.6h.8M66.4 44.1h.8M67.2 46.6h.8M67.7 44.1h.8M68.5 46.6h.7M68.9 44.1h.8M69.7 46.6h.8M70.2 44.1h.8M71 46.6h.8M71.5 44.1h.8M72.3 46.6h.8M72.7 44.1h.8"/>
<path d="M73.5 46.6h.8M74 44.1h.8M74.8 46.6h.8M75.3 44.1h.8M76.1 46.6h.8M76.6 44.1h.7M77.3 46.6h.8M77.8 44.1h.8M78.6 46.6h.8M79.1 44.1h.8M79.9 46.6h.8M80.4 44.1h.8"/>
<path d="M81.2 40.3v.7M81.2 41.5v.8M81.2 42.8v.8M81.2 46.6h.7M82.4 46.6h.8M83.7 47.1v.8M83.7 48.3v.8M83.7 49.6v.8M83.7 50.9v.8M83.7 52.2v.8M83.7 53.4v.8M83.7 54.7v.8"/>
<path d="M83.7 56v.8M83.7 57.2v.8M83.7 58.5v.8M83.7 59.8v.8M147.2 46.6h.8M147.2 40.3v.7M147.2 41.5v.8M147.2 42.8v.8M147.2 47.1v.8M147.2 48.3v.8M147.2 49.6v.8M147.2 50.9v.8"/>
<path d="M147.2 52.2v.8M147.2 53.4v.8M147.2 54.7v.8M147.2 56v.8M147.2 57.2v.8M147.2 58.5v.8M147.2 59.8v.8M147.7 44.1h.8M148.5 46.6h.8M148.9 44.1h.8M149.7 46.6h.8M150.2 44.1h.8"/>
<path d="M151 46.6h.8M151.5 44.1h.8M152.3 46.6h.8M152.8 44.1h.7M153.5 46.6h.8M154 44.1h.8M154.8 46.6h.8M155.3 44.1h.8M156.1 46.6h.8M156.6 44.1h.8M157.4 46.6h.8M157.8 44.1h.8"/>
<path d="M158.6 46.6h.8M159.1 44.1h.8M159.9 46.6h.8M160.4 44.1h.8M161.2 46.6h.8M161.6 44.1h.8M162.4 46.6h.8M162.9 44.1h.8M163.7 46.6h.8M164.2 44.1h.8M165 46.6h.8M165 40.3v.7"/>
<path d="M165 41.5v.8M165 42.8v.8M166.2 46.6h.8M167.5 47.1v.8M167.5 48.3v.8M167.5 49.6v.8M167.5 50.9v.8M167.5 52.2v.8M167.5 53.4v.8M167.5 54.7v.8M167.5 56v.8M167.5 57.2v.8"/>
<path d="M167.5 58.5v.8M167.5 59.8v.8M63.4 61.1v.7M63.4 62.3v.8M63.4 63.6v.8M63.9 64.4h.7M65.1 64.4h.8M66.4 64.4h.8M67.7 64.4h.8M68.9 64.4h.8M70.2 64.4h.8M71.5 64.4h.8"/>
<path d="M72.7 64.4h.8M74 64.4h.8M75.3 64.4h.8M76.6 64.4h.7M77.8 64.4h.8M79.1 64.4h.8M80.4 64.4h.8M81.6 64.4h.8M83.7 63.6v.8h-.8M83.7 61.1v.7M83.7 62.3v.8M147.2 61v.8"/>
<path d="M147.2 62.3v.8M147.2 63.6v.8M147.7 64.4h.8M148.9 64.4h.8M150.2 64.4h.8M151.5 64.4h.8M152.8 64.4h.7M154 64.4h.8M155.3 64.4h.8M156.6 64.4h.8M157.8 64.4h.8M159.1 64.4h.8"/>
<path d="M160.4 64.4h.8M161.6 64.4h.8M162.9 64.4h.8M164.2 64.4h.8M165.5 64.4h.7M167.5 63.6v.8h-.8M167.5 61v.8M167.5 62.3v.8M34.4 119.3l2.1 2M36.5 119.3l-2.1 2M59.8 119.3l2.1 2M61.9 119.3l-2.1 2"/>
<path d="M118.2 119.3l2.1 2M120.3 119.3l-2.1 2M143.6 119.3l2.1 2M145.7 119.3l-2.1 2M34.4 121.8l2.1 2M34.4 124.3l2.1 2.1M34.4 126.9l2.1 2M36.5 121.8l-2.1 2M36.5 124.3l-2.1 2.1M36.5 126.9l-2.1 2M59.8 121.8l2.1 2M59.8 124.3l2.1 2.1"/>
<path d="M61.9 121.8l-2.1 2M61.9 124.3l-2.1 2.1M118.2 121.8l2.1 2M118.2 124.3l2.1 2.1M118.2 126.9l2.1 2M120.3 121.8l-2.1 2M120.3 124.3l-2.1 2.1M120.3 126.9l-2.1 2M143.6 121.8l2.1 2M143.6 124.3l2.1 2.1M145.7 121.8l-2.1 2M145.7 124.3l-2.1 2.1"/>
</g>
<path d="M64.6 24.3l1.1 1.7h-2.1zM148.5 24.3l1 1.7h-2zM64.6 47.1l1.1 1.8h-2.1zM148.5 47.1l1 1.8h-2z" fill="none" stroke="#f33" stroke-width=".21"/>
<g fill="none" stroke="#f00" stroke-width=".25">
<path d="M81.2 22.2v1.5M165 22.2v1.5M83.7 45.1v1.5M167.5 45.1v1.5"/>
<circle cx="81.2" cy="20.7" r="1.52"/>
<circle cx="165" cy="20.7" r="1.52"/>
<circle cx="83.7" cy="43.6" r="1.52"/>
<circle cx="167.5" cy="43.6" r="1.52"/>
</g>
<g fill="none" stroke="#00f" stroke-width=".25">
<path d="M233.6 99.9h2M235.6 97.9v4M236.6 99.9h2M236.6 97.9v4M70.5 106.6h6v2h-6zM154.4 106.6h6v2h-6zM169.6 101.5h6v2h-6zM45.1 137.1h6v2h-6zM45.1 139.6h6v2h-6zM45.1 142.2h6v2h-6zM45.1 144.7h6v2h-6zM45.1 147.2h6v2.1h-6z"/>
<path d="M45.1 149.8h6v2h-6zM45.1 152.3h6v2h-6zM45.1 154.9h6v2h-6zM45.1 157.4h6v2h-6zM45.1 159.9h6v2.1h-6zM45.1 162.5h6v2h-6zM45.1 165h6v2h-6zM45.1 167.6h6v2h-6zM45.1 170.1h6v2h-6zM45.1 172.6h6v2.1h-6zM45.1 175.2h6v2h-6zM45.1 177.7h6v2h-6z"/>
<path d="M174.2 160.5h2v6h-2zM45.1 180.3h6v2h-6zM45.1 182.8h6v2h-6zM45.1 185.3h6v2.1h-6zM45.1 187.9h6v2h-6zM45.1 190.4h6v2h-6z"/>
</g>
<circle cx="243.7" cy="112.7" r=".51" fill="#000080"/>
<circle cx="243.7" cy="112.7" r=".51" fill="none" stroke="#000080" stroke-width=".21"/>
<path d="M243.7 102.5v2.5M243.7 110.1v2.5" fill="none" stroke="#000" stroke-width=".25"/>
<circle cx="243.7" cy="112.7" r=".51" fill="#000080"/>
<circle cx="243.7" cy="112.7" r=".51" fill="none" stroke="#000080" stroke-width=".21"/>
<path d="M233.6 23.7h2M235.6 21.7v4M236.6 23.7h2M236.6 21.7v4M241.7 107.1h4M241.7 108.1h4M243.7 105v2.1M243.7 108.1v2" fill="none" stroke="#00f" stroke-width=".25"/>
<path d="M250.1 94.9h2.5M251.3 94.9v2.5M225.9 105h5.1M226.7 105.8h3.6M227.5 106.6h2M228.2 107.3h.5M228.5 102.5v2.5" fill="none" stroke="#800000" stroke-width=".25"/>
<path d="M231 23.7h2.6M238.6 23.7h2.6" fill="none" stroke="#000" stroke-width=".25"/>
<circle cx="243.7" cy="36.5" r=".51" fill="#000080"/>
<circle cx="243.7" cy="36.5" r=".51" fill="none" stroke="#000080" stroke-width=".21"/>
<path d="M243.7 26.3v2.5M243.7 33.9v2.5" fill="none" stroke="#000" stroke-width=".25"/>
<circle cx="243.7" cy="36.5" r=".51" fill="#000080"/>
<circle cx="243.7" cy="36.5" r=".51" fill="none" stroke="#000080" stroke-width=".21"/>
<path d="M241.7 30.9h4M241.7 31.9h4M243.7 28.8v2.1M243.7 31.9v2M98 152.8h2v6h-2zM98 168.1h2v6h-2z" fill="none" stroke="#00f" stroke-width=".25"/>
<g fill="none" stroke="#800000" stroke-width=".25">
<path d="M250.1 18.7h2.5M251.3 18.7v2.5M225.9 28.8h5.1M226.7 29.6h3.6M227.5 30.4h2M228.2 31.1h.5M228.5 26.3v2.5M97.7 145.7h2.5M98.9 145.7v2.5M98.9 178.7v2.5M116.7 163.4h2.6M119.3 162.2v2.5"/>
<path d="M96.4 181.2h5.1M97.2 182h3.5M97.9 182.8h2.1M98.7 183.5h.5"/>
</g>
<path d="M98.9 150.7v2M98.9 158.9v2M98.9 166v2M98.9 174.1v2" fill="none" stroke="#000" stroke-width=".25"/>
<circle cx="208.2" cy="112.7" r=".51" fill="#000080"/>
<circle cx="208.2" cy="112.7" r=".51" fill="none" stroke="#000080" stroke-width=".21"/>
<path d="M208.2 112.6v2.6M208.2 120.3v2.5" fill="none" stroke="#000" stroke-width=".25"/>
<circle cx="208.2" cy="112.7" r=".51" fill="#000080"/>
<circle cx="208.2" cy="112.7" r=".51" fill="none" stroke="#000080" stroke-width=".21"/>
<path d="M206.2 118.2h4M206.2 117.2h4M208.2 115.2v2M208.2 118.2v2.1" fill="none" stroke="#00f" stroke-width=".25"/>
<circle cx="198" cy="112.7" r=".51" fill="#000080"/>
<circle cx="198" cy="112.7" r=".51" fill="none" stroke="#000080" stroke-width=".21"/>
<path d="M198 112.6v2.6M198 120.3v2.5" fill="none" stroke="#000" stroke-width=".25"/>
<circle cx="198" cy="112.7" r=".51" fill="#000080"/>
<circle cx="198" cy="112.7" r=".51" fill="none" stroke="#000080" stroke-width=".21"/>
<path d="M196 118.2h4M196 117.2h4M198 115.2v2M198 118.2v2.1" fill="none" stroke="#00f" stroke-width=".25"/>
<circle cx="218.3" cy="112.7" r=".51" fill="#000080"/>
<circle cx="218.3" cy="112.7" r=".51" fill="none" stroke="#000080" stroke-width=".21"/>
<path d="M218.3 112.6v2.6M218.3 120.3v2.5" fill="none" stroke="#000" stroke-width=".25"/>
<circle cx="218.3" cy="112.7" r=".51" fill="#000080"/>
<circle cx="218.3" cy="112.7" r=".51" fill="none" stroke="#000080" stroke-width=".21"/>
<path d="M216.3 118.2h4M216.3 117.2h4M218.3 115.2v2M218.3 118.2v2.1" fill="none" stroke="#00f" stroke-width=".25"/>
<circle cx="228.5" cy="112.7" r=".51" fill="#000080"/>
<circle cx="228.5" cy="112.7" r=".51" fill="none" stroke="#000080" stroke-width=".21"/>
<path d="M228.5 112.6v2.6M228.5 120.3v2.5" fill="none" stroke="#000" stroke-width=".25"/>
<circle cx="228.5" cy="112.7" r=".51" fill="#000080"/>
<circle cx="228.5" cy="112.7" r=".51" fill="none" stroke="#000080" stroke-width=".21"/>
<path d="M226.5 118.2h4M226.5 117.2h4M228.5 115.2v2M228.5 118.2v2.1" fill="none" stroke="#00f" stroke-width=".25"/>
<g fill="none" stroke="#800000" stroke-width=".25">
<path d="M195.5 125.3h5M196.2 126.1h3.6M197 126.9h2M197.7 127.6h.6M198 122.8v2.5M205.6 125.3h5.1M206.4 126.1h3.5M207.1 126.9h2.1M207.9 127.6h.5M208.2 122.8v2.5M215.8 125.3h5.1M216.5 126.1h3.6"/>
<path d="M217.3 126.9h2M218.1 127.6h.5M218.3 122.8v2.5M225.9 125.3h5.1M226.7 126.1h3.6M227.5 126.9h2M228.2 127.6h.5M228.5 122.8v2.5"/>
</g>
<circle cx="208.2" cy="143.1" r=".51" fill="#000080"/>
<circle cx="208.2" cy="143.1" r=".51" fill="none" stroke="#000080" stroke-width=".21"/>
<path d="M208.2 143.1v2.6M208.2 150.7v2.6" fill="none" stroke="#000" stroke-width=".25"/>
<circle cx="208.2" cy="143.1" r=".51" fill="#000080"/>
<circle cx="208.2" cy="143.1" r=".51" fill="none" stroke="#000080" stroke-width=".21"/>
<path d="M206.2 148.7h4M206.2 147.7h4M208.2 145.7v2M208.2 148.7v2" fill="none" stroke="#00f" stroke-width=".25"/>
<circle cx="198" cy="143.1" r=".51" fill="#000080"/>
<circle cx="198" cy="143.1" r=".51" fill="none" stroke="#000080" stroke-width=".21"/>
<path d="M198 143.1v2.6M198 150.7v2.6" fill="none" stroke="#000" stroke-width=".25"/>
<circle cx="198" cy="143.1" r=".51" fill="#000080"/>
<circle cx="198" cy="143.1" r=".51" fill="none" stroke="#000080" stroke-width=".21"/>
<path d="M196 148.7h4M196 147.7h4M198 145.7v2M198 148.7v2" fill="none" stroke="#00f" stroke-width=".25"/>
<circle cx="218.3" cy="143.1" r=".51" fill="#000080"/>
<circle cx="218.3" cy="143.1" r=".51" fill="none" stroke="#000080" stroke-width=".21"/>
<path d="M218.3 143.1v2.6M218.3 150.7v2.6" fill="none" stroke="#000" stroke-width=".25"/>
<circle cx="218.3" cy="143.1" r=".51" fill="#000080"/>
<circle cx="218.3" cy="143.1" r=".51" fill="none" stroke="#000080" stroke-width=".21"/>
<path d="M216.3 148.7h4M216.3 147.7h4M218.3 145.7v2M218.3 148.7v2" fill="none" stroke="#00f" stroke-width=".25"/>
<circle cx="228.5" cy="143.1" r=".51" fill="#000080"/>
<circle cx="228.5" cy="143.1" r=".51" fill="none" stroke="#000080" stroke-width=".21"/>
<path d="M228.5 143.1v2.6M228.5 150.7v2.6" fill="none" stroke="#000" stroke-width=".25"/>
<circle cx="228.5" cy="143.1" r=".51" fill="#000080"/>
<circle cx="228.5" cy="143.1" r=".51" fill="none" stroke="#000080" stroke-width=".21"/>
<path d="M226.5 148.7h4M226.5 147.7h4M228.5 145.7v2M228.5 148.7v2" fill="none" stroke="#00f" stroke-width=".25"/>
<g fill="none" stroke="#800000" stroke-width=".25">
<path d="M195.5 155.8h5M196.2 156.6h3.6M197 157.4h2M197.7 158.1h.6M198 153.3v2.5M205.6 155.8h5.1M206.4 156.6h3.5M207.1 157.4h2.1M207.9 158.1h.5M208.2 153.3v2.5M215.8 155.8h5.1M216.5 156.6h3.6"/>
<path d="M217.3 157.4h2M218.1 158.1h.5M218.3 153.3v2.5M225.9 155.8h5.1M226.7 156.6h3.6M227.5 157.4h2M228.2 158.1h.5M228.5 153.3v2.5"/>
</g>
<circle cx="208.2" cy="66.9" r=".51" fill="#000080"/>
<circle cx="208.2" cy="66.9" r=".51" fill="none" stroke="#000080" stroke-width=".21"/>
<path d="M208.2 66.9v2.6M208.2 74.5v2.6" fill="none" stroke="#000" stroke-width=".25"/>
<circle cx="208.2" cy="66.9" r=".51" fill="#000080"/>
<circle cx="208.2" cy="66.9" r=".51" fill="none" stroke="#000080" stroke-width=".21"/>
<path d="M206.2 72.5h4M206.2 71.5h4M208.2 69.5v2M208.2 72.5v2" fill="none" stroke="#00f" stroke-width=".25"/>
<circle cx="198" cy="66.9" r=".51" fill="#000080"/>
<circle cx="198" cy="66.9" r=".51" fill="none" stroke="#000080" stroke-width=".21"/>
<path d="M198 66.9v2.6M198 74.5v2.6" fill="none" stroke="#000" stroke-width=".25"/>
<circle cx="198" cy="66.9" r=".51" fill="#000080"/>
<circle cx="198" cy="66.9" r=".51" fill="none" stroke="#000080" stroke-width=".21"/>
<path d="M196 72.5h4M196 71.5h4M198 69.5v2M198 72.5v2" fill="none" stroke="#00f" stroke-width=".25"/>
<circle cx="218.3" cy="66.9" r=".51" fill="#000080"/>
<circle cx="218.3" cy="66.9" r=".51" fill="none" stroke="#000080" stroke-width=".21"/>
<path d="M218.3 66.9v2.6M218.3 74.5v2.6" fill="none" stroke="#000" stroke-width=".25"/>
<circle cx="218.3" cy="66.9" r=".51" fill="#000080"/>
<circle cx="218.3" cy="66.9" r=".51" fill="none" stroke="#000080" stroke-width=".21"/>
<path d="M216.3 72.5h4M216.3 71.5h4M218.3 69.5v2M218.3 72.5v2" fill="none" stroke="#00f" stroke-width=".25"/>
<circle cx="228.5" cy="66.9" r=".51" fill="#000080"/>
<circle cx="228.5" cy="66.9" r=".51" fill="none" stroke="#000080" stroke-width=".21"/>
<path d="M228.5 66.9v2.6M228.5 74.5v2.6" fill="none" stroke="#000" stroke-width=".25"/>
<circle cx="228.5" cy="66.9" r=".51" fill="#000080"/>
<circle cx="228.5" cy="66.9" r=".51" fill="none" stroke="#000080" stroke-width=".21"/>
<path d="M226.5 72.5h4M226.5 71.5h4M228.5 69.5v2M228.5 72.5v2" fill="none" stroke="#00f" stroke-width=".25"/>
<g fill="none" stroke="#800000" stroke-width=".25">
<path d="M195.5 79.6h5M198 77.1v2.5M205.6 79.6h5.1M208.2 77.1v2.5M215.8 79.6h5.1M218.3 77.1v2.5M225.9 79.6h5.1M228.5 77.1v2.5M196.2 80.4h3.6M197 81.2h2M197.7 81.9h.6M206.4 80.4h3.5"/>
<path d="M207.1 81.2h2.1M207.9 81.9h.5M216.5 80.4h3.6M217.3 81.2h2M218.1 81.9h.5M226.7 80.4h3.6M227.5 81.2h2M228.2 81.9h.5"/>
</g>
<circle cx="208.2" cy="36.5" r=".51" fill="#000080"/>
<circle cx="208.2" cy="36.5" r=".51" fill="none" stroke="#000080" stroke-width=".21"/>
<path d="M208.2 36.4v2.6M208.2 44.1v2.5" fill="none" stroke="#000" stroke-width=".25"/>
<circle cx="208.2" cy="36.5" r=".51" fill="#000080"/>
<circle cx="208.2" cy="36.5" r=".51" fill="none" stroke="#000080" stroke-width=".21"/>
<path d="M208.2 39v2M206.2 42h4M206.2 41h4M208.2 42v2.1" fill="none" stroke="#00f" stroke-width=".25"/>
<circle cx="198" cy="36.5" r=".51" fill="#000080"/>
<circle cx="198" cy="36.5" r=".51" fill="none" stroke="#000080" stroke-width=".21"/>
<path d="M198 36.4v2.6M198 44.1v2.5" fill="none" stroke="#000" stroke-width=".25"/>
<circle cx="198" cy="36.5" r=".51" fill="#000080"/>
<circle cx="198" cy="36.5" r=".51" fill="none" stroke="#000080" stroke-width=".21"/>
<path d="M198 39v2M196 42h4M196 41h4M198 42v2.1" fill="none" stroke="#00f" stroke-width=".25"/>
<circle cx="218.3" cy="36.5" r=".51" fill="#000080"/>
<circle cx="218.3" cy="36.5" r=".51" fill="none" stroke="#000080" stroke-width=".21"/>
<path d="M218.3 36.4v2.6M218.3 44.1v2.5" fill="none" stroke="#000" stroke-width=".25"/>
<circle cx="218.3" cy="36.5" r=".51" fill="#000080"/>
<circle cx="218.3" cy="36.5" r=".51" fill="none" stroke="#000080" stroke-width=".21"/>
<path d="M218.3 39v2M216.3 42h4M216.3 41h4M218.3 42v2.1" fill="none" stroke="#00f" stroke-width=".25"/>
<circle cx="228.5" cy="36.5" r=".51" fill="#000080"/>
<circle cx="228.5" cy="36.5" r=".51" fill="none" stroke="#000080" stroke-width=".21"/>
<path d="M228.5 36.4v2.6M228.5 44.1v2.5" fill="none" stroke="#000" stroke-width=".25"/>
<circle cx="228.5" cy="36.5" r=".51" fill="#000080"/>
<circle cx="228.5" cy="36.5" r=".51" fill="none" stroke="#000080" stroke-width=".21"/>
<path d="M228.5 39v2M226.5 42h4M226.5 41h4M228.5 42v2.1M107.1 171.6h4M107.1 170.6h4M109.1 168.5v2.1M109.1 171.6v2" fill="none" stroke="#00f" stroke-width=".25"/>
<g fill="none" stroke="#800000" stroke-width=".25">
<path d="M195.5 49.1h5M196.2 49.9h3.6M197 50.7h2M197.7 51.4h.6M198 46.6v2.5M205.6 49.1h5.1M206.4 49.9h3.5M207.1 50.7h2.1M207.9 51.4h.5M208.2 46.6v2.5M215.8 49.1h5.1M216.5 49.9h3.6"/>
<path d="M217.3 50.7h2M218.1 51.4h.5M218.3 46.6v2.5M225.9 49.1h5.1M226.7 49.9h3.6M227.5 50.7h2M228.2 51.4h.5M228.5 46.6v2.5M109.1 178.7v2.5M106.6 181.2h5M107.3 182h3.6M108.1 182.8h2"/>
<path d="M108.8 183.5h.6"/>
</g>
<path d="M109.1 166v2.5M109.1 173.6v2.5" fill="none" stroke="#000" stroke-width=".25"/>
<circle cx="238.6" cy="143.1" r=".51" fill="#000080"/>
<circle cx="238.6" cy="143.1" r=".51" fill="none" stroke="#000080" stroke-width=".21"/>
<path d="M238.6 143.1v2.6M238.6 150.7v2.6" fill="none" stroke="#000" stroke-width=".25"/>
<circle cx="238.6" cy="143.1" r=".51" fill="#000080"/>
<circle cx="238.6" cy="143.1" r=".51" fill="none" stroke="#000080" stroke-width=".21"/>
<path d="M236.6 148.7h4M236.6 147.7h4M238.6 145.7v2M238.6 148.7v2" fill="none" stroke="#00f" stroke-width=".25"/>
<path d="M236.1 155.8h5.1M236.9 156.6h3.5M237.6 157.4h2.1M238.4 158.1h.5M238.6 153.3v2.5" fill="none" stroke="#800000" stroke-width=".25"/>
<circle cx="238.6" cy="112.7" r=".51" fill="#000080"/>
<circle cx="238.6" cy="112.7" r=".51" fill="none" stroke="#000080" stroke-width=".21"/>
<path d="M238.6 112.6v2.6M238.6 120.3v2.5" fill="none" stroke="#000" stroke-width=".25"/>
<circle cx="238.6" cy="112.7" r=".51" fill="#000080"/>
<circle cx="238.6" cy="112.7" r=".51" fill="none" stroke="#000080" stroke-width=".21"/>
<path d="M236.6 118.2h4M236.6 117.2h4M238.6 115.2v2M238.6 118.2v2.1" fill="none" stroke="#00f" stroke-width=".25"/>
<path d="M236.1 125.3h5.1M236.9 126.1h3.5M237.6 126.9h2.1M238.4 127.6h.5M238.6 122.8v2.5" fill="none" stroke="#800000" stroke-width=".25"/>
<circle cx="238.6" cy="66.9" r=".51" fill="#000080"/>
<circle cx="238.6" cy="66.9" r=".51" fill="none" stroke="#000080" stroke-width=".21"/>
<path d="M238.6 66.9v2.6M238.6 74.5v2.6" fill="none" stroke="#000" stroke-width=".25"/>
<circle cx="238.6" cy="66.9" r=".51" fill="#000080"/>
<circle cx="238.6" cy="66.9" r=".51" fill="none" stroke="#000080" stroke-width=".21"/>
<path d="M236.6 72.5h4M236.6 71.5h4M238.6 69.5v2M238.6 72.5v2" fill="none" stroke="#00f" stroke-width=".25"/>
<path d="M236.1 79.6h5.1M238.6 77.1v2.5M236.9 80.4h3.5M237.6 81.2h2.1M238.4 81.9h.5" fill="none" stroke="#800000" stroke-width=".25"/>
<circle cx="238.6" cy="36.5" r=".51" fill="#000080"/>
<circle cx="238.6" cy="36.5" r=".51" fill="none" stroke="#000080" stroke-width=".21"/>
<path d="M238.6 36.4v2.6M238.6 44.1v2.5" fill="none" stroke="#000" stroke-width=".25"/>
<circle cx="238.6" cy="36.5" r=".51" fill="#000080"/>
<circle cx="238.6" cy="36.5" r=".51" fill="none" stroke="#000080" stroke-width=".21"/>
<path d="M238.6 39v2M236.6 42h4M236.6 41h4M238.6 42v2.1" fill="none" stroke="#00f" stroke-width=".25"/>
<path d="M236.1 49.1h5.1M236.9 49.9h3.5M237.6 50.7h2.1M238.4 51.4h.5M238.6 46.6v2.5" fill="none" stroke="#800000" stroke-width=".25"/>
<g fill="none" stroke="#f00" stroke-width=".25">
<path d="M85 67.6h1l.5-.5h1l.5 .5h1M85 68.2h1l.5 .5h1l.5-.5h1M85 70.1h1l.5-.5h1l.5 .5h1M85 70.7h1l.5 .5h1l.5-.5h1M85 75.2h1l.5-.5h1l.5 .5h1M85 75.8h1l.5 .5h1l.5-.5h1M85 77.7h1l.5-.5h1l.5 .5h1M85 78.4h1l.5 .5h1l.5-.5h1M92.6 77.7h1l.5-.5h1l.5 .5h1.1M92.6 78.4h1l.5 .5h1l.5-.5h1.1M168.8 67.6h1l.5-.5h1l.5 .5h1.1M168.8 68.2h1l.5 .5h1l.5-.5h1.1"/>
<path d="M168.8 70.1h1l.5-.5h1l.5 .5h1.1M168.8 70.7h1l.5 .5h1l.5-.5h1.1M168.8 75.2h1l.5-.5h1l.5 .5h1.1M168.8 75.8h1l.5 .5h1l.5-.5h1.1M168.8 77.7h1l.5-.5h1l.5 .5h1.1M168.8 78.4h1l.5 .5h1l.5-.5h1.1M81.2 84.7h1.5M81.2 87.2v1.6M92.6 80.3h1l.5-.5h1l.5 .5h1.1M92.6 80.9h1l.5 .5h1l.5-.5h1.1M165 84.7h1.5M165 87.2v1.6"/>
<circle cx="81.2" cy="90.3" r="1.52"/>
<circle cx="84.2" cy="84.7" r="1.52"/>
<circle cx="165" cy="90.3" r="1.52"/>
<circle cx="168" cy="84.7" r="1.52"/>
</g>
<g fill="none" stroke="#d0a19e" stroke-width=".25">
<path d="M85.2 67.8h1l.5-.5h1.1l.5 .5h1M85.2 68.5h1l.5 .5h1.1l.5-.5h1M85.2 70.4h1l.5-.6h1.1l.5 .6h1M85.2 71h1l.5 .5h1.1l.5-.5h1M85.2 75.4h1l.5-.5h1.1l.5 .5h1M85.2 76.1h1l.5 .5h1.1l.5-.5h1M85.2 78h1l.5-.5h1.1l.5 .5h1M85.2 78.6h1l.5 .5h1.1l.5-.5h1M92.8 78h1.1l.5-.5h1l.5 .5h1M92.8 78.6h1.1l.5 .5h1l.5-.5h1M169 67.8h1.1l.5-.5h1l.5 .5h1M169 68.5h1.1l.5 .5h1l.5-.5h1"/>
<path d="M169 70.4h1.1l.5-.6h1l.5 .6h1M169 71h1.1l.5 .5h1l.5-.5h1M169 75.4h1.1l.5-.5h1l.5 .5h1M169 76.1h1.1l.5 .5h1l.5-.5h1M169 78h1.1l.5-.5h1l.5 .5h1M169 78.6h1.1l.5 .5h1l.5-.5h1M92.8 80.5h1.1l.5-.5h1l.5 .5h1M92.8 81.2h1.1l.5 .5h1l.5-.5h1"/>
</g>
<path d="M85.2 68.5l-1.5 1M85.2 71l-1.5 1M85.2 76.1l-1.5 1M85.2 78.6l-1.5 1M92.8 78.6l-1.5 1M169 68.5l-1.5 1M169 71l-1.5 1M169 76.1l-1.5 1M169 78.6l-1.5 1M92.8 81.2l-1.5 1" fill="none" stroke="#d0a19e" stroke-width=".21"/>
<path d="M85 68.2l-1.3 1.3M85 70.7l-1.3 1.3M85 75.8l-1.3 1.3M85 78.4l-1.3 1.2M92.6 78.4l-1.3 1.2M168.8 68.2l-1.3 1.3M168.8 70.7l-1.3 1.3M168.8 75.8l-1.3 1.3M168.8 78.4l-1.3 1.2M92.6 80.9l-1.3 1.3" fill="none" stroke="#f00" stroke-width=".21"/>
<path d="M281.8 36.4v53.4" fill="none" stroke="#000080" stroke-width=".25"/>
<circle cx="281.8" cy="39" r=".51" fill="#000080"/>
<circle cx="281.8" cy="39" r=".51" fill="none" stroke="#000080" stroke-width=".21"/>
<circle cx="281.8" cy="41.5" r=".51" fill="#000080"/>
<circle cx="281.8" cy="41.5" r=".51" fill="none" stroke="#000080" stroke-width=".21"/>
<circle cx="281.8" cy="44.1" r=".51" fill="#000080"/>
<circle cx="281.8" cy="44.1" r=".51" fill="none" stroke="#000080" stroke-width=".21"/>
<circle cx="281.8" cy="46.6" r=".51" fill="#000080"/>
<circle cx="281.8" cy="46.6" r=".51" fill="none" stroke="#000080" stroke-width=".21"/>
<circle cx="281.8" cy="49.2" r=".51" fill="#000080"/>
<circle cx="281.8" cy="49.2" r=".51" fill="none" stroke="#000080" stroke-width=".21"/>
<circle cx="281.8" cy="51.7" r=".51" fill="#000080"/>
<circle cx="281.8" cy="51.7" r=".51" fill="none" stroke="#000080" stroke-width=".21"/>
<circle cx="281.8" cy="54.2" r=".51" fill="#000080"/>
<circle cx="281.8" cy="54.2" r=".51" fill="none" stroke="#000080" stroke-width=".21"/>
<circle cx="281.8" cy="56.8" r=".51" fill="#000080"/>
<circle cx="281.8" cy="56.8" r=".51" fill="none" stroke="#000080" stroke-width=".21"/>
<circle cx="281.8" cy="59.3" r=".51" fill="#000080"/>
<circle cx="281.8" cy="59.3" r=".51" fill="none" stroke="#000080" stroke-width=".21"/>
<circle cx="281.8" cy="61.9" r=".51" fill="#000080"/>
<circle cx="281.8" cy="61.9" r=".51" fill="none" stroke="#000080" stroke-width=".21"/>
<circle cx="281.8" cy="64.4" r=".51" fill="#000080"/>
<circle cx="281.8" cy="64.4" r=".51" fill="none" stroke="#000080" stroke-width=".21"/>
<circle cx="281.8" cy="66.9" r=".51" fill="#000080"/>
<circle cx="281.8" cy="66.9" r=".51" fill="none" stroke="#000080" stroke-width=".21"/>
<circle cx="281.8" cy="69.5" r=".51" fill="#000080"/>
<circle cx="281.8" cy="69.5" r=".51" fill="none" stroke="#000080" stroke-width=".21"/>
<circle cx="281.8" cy="72" r=".51" fill="#000080"/>
<circle cx="281.8" cy="72" r=".51" fill="none" stroke="#000080" stroke-width=".21"/>
<circle cx="281.8" cy="74.6" r=".51" fill="#000080"/>
<circle cx="281.8" cy="74.6" r=".51" fill="none" stroke="#000080" stroke-width=".21"/>
<circle cx="281.8" cy="77.1" r=".51" fill="#000080"/>
<circle cx="281.8" cy="77.1" r=".51" fill="none" stroke="#000080" stroke-width=".21"/>
<circle cx="281.8" cy="79.6" r=".51" fill="#000080"/>
<circle cx="281.8" cy="79.6" r=".51" fill="none" stroke="#000080" stroke-width=".21"/>
<circle cx="281.8" cy="82.2" r=".51" fill="#000080"/>
<circle cx="281.8" cy="82.2" r=".51" fill="none" stroke="#000080" stroke-width=".21"/>
<circle cx="281.8" cy="84.7" r=".51" fill="#000080"/>
<circle cx="281.8" cy="84.7" r=".51" fill="none" stroke="#000080" stroke-width=".21"/>
<circle cx="281.8" cy="87.3" r=".51" fill="#000080"/>
<circle cx="281.8" cy="87.3" r=".51" fill="none" stroke="#000080" stroke-width=".21"/>
<path d="M281.8 112.6v53.4" fill="none" stroke="#000080" stroke-width=".25"/>
<circle cx="281.8" cy="115.2" r=".51" fill="#000080"/>
<circle cx="281.8" cy="115.2" r=".51" fill="none" stroke="#000080" stroke-width=".21"/>
<circle cx="281.8" cy="117.7" r=".51" fill="#000080"/>
<circle cx="281.8" cy="117.7" r=".51" fill="none" stroke="#000080" stroke-width=".21"/>
<circle cx="281.8" cy="120.3" r=".51" fill="#000080"/>
<circle cx="281.8" cy="120.3" r=".51" fill="none" stroke="#000080" stroke-width=".21"/>
<circle cx="281.8" cy="122.8" r=".51" fill="#000080"/>
<circle cx="281.8" cy="122.8" r=".51" fill="none" stroke="#000080" stroke-width=".21"/>
<circle cx="281.8" cy="125.4" r=".51" fill="#000080"/>
<circle cx="281.8" cy="125.4" r=".51" fill="none" stroke="#000080" stroke-width=".21"/>
<circle cx="281.8" cy="127.9" r=".51" fill="#000080"/>
<circle cx="281.8" cy="127.9" r=".51" fill="none" stroke="#000080" stroke-width=".21"/>
<circle cx="281.8" cy="130.4" r=".51" fill="#000080"/>
<circle cx="281.8" cy="130.4" r=".51" fill="none" stroke="#000080" stroke-width=".21"/>
<circle cx="281.8" cy="133" r=".51" fill="#000080"/>
<circle cx="281.8" cy="133" r=".51" fill="none" stroke="#000080" stroke-width=".21"/>
<circle cx="281.8" cy="135.5" r=".51" fill="#000080"/>
<circle cx="281.8" cy="135.5" r=".51" fill="none" stroke="#000080" stroke-width=".21"/>
<circle cx="281.8" cy="138.1" r=".51" fill="#000080"/>
<circle cx="281.8" cy="138.1" r=".51" fill="none" stroke="#000080" stroke-width=".21"/>
<circle cx="281.8" cy="140.6" r=".51" fill="#000080"/>
<circle cx="281.8" cy="140.6" r=".51" fill="none" stroke="#000080" stroke-width=".21"/>
<circle cx="281.8" cy="143.1" r=".51" fill="#000080"/>
<circle cx="281.8" cy="143.1" r=".51" fill="none" stroke="#000080" stroke-width=".21"/>
<circle cx="281.8" cy="145.7" r=".51" fill="#000080"/>
<circle cx="281.8" cy="145.7" r=".51" fill="none" stroke="#000080" stroke-width=".21"/>
<circle cx="281.8" cy="148.2" r=".51" fill="#000080"/>
<circle cx="281.8" cy="148.2" r=".51" fill="none" stroke="#000080" stroke-width=".21"/>
<circle cx="281.8" cy="150.8" r=".51" fill="#000080"/>
<circle cx="281.8" cy="150.8" r=".51" fill="none" stroke="#000080" stroke-width=".21"/>
<circle cx="281.8" cy="153.3" r=".51" fill="#000080"/>
<circle cx="281.8" cy="153.3" r=".51" fill="none" stroke="#000080" stroke-width=".21"/>
<circle cx="281.8" cy="155.8" r=".51" fill="#000080"/>
<circle cx="281.8" cy="155.8" r=".51" fill="none" stroke="#000080" stroke-width=".21"/>
<circle cx="281.8" cy="158.4" r=".51" fill="#000080"/>
<circle cx="281.8" cy="158.4" r=".51" fill="none" stroke="#000080" stroke-width=".21"/>
<circle cx="281.8" cy="160.9" r=".51" fill="#000080"/>
<circle cx="281.8" cy="160.9" r=".51" fill="none" stroke="#000080" stroke-width=".21"/>
<circle cx="281.8" cy="163.5" r=".51" fill="#000080"/>
<circle cx="281.8" cy="163.5" r=".51" fill="none" stroke="#000080" stroke-width=".21"/>
<g fill="none" stroke="#000080" stroke-width=".25">
<path d="M15.1 26.3h17.8M15.1 28.8h17.8M15.1 31.4h17.8M15.1 33.9h17.8M15.1 36.4h17.8M15.1 39h17.8M63.4 26.3h17.8M63.4 28.8h17.8M63.4 31.4h17.8M63.4 33.9h17.8M63.4 36.4h17.8M63.4 39h17.8"/>
<path d="M98.9 26.3h17.8M98.9 28.8h17.8M98.9 31.4h17.8M98.9 33.9h17.8M98.9 36.4h17.8M98.9 39h17.8M147.2 26.3h17.8M147.2 28.8h17.8M147.2 31.4h17.8M147.2 33.9h17.8M147.2 36.4h17.8M147.2 39h17.8"/>
<path d="M15.1 41.5h17.8M15.1 44.1h17.8M15.1 46.6h17.8M15.1 49.1h17.8M15.1 51.7h17.8M15.1 54.2h17.8M15.1 56.8h17.8M63.4 41.5h17.8M63.4 44.1h17.8M63.4 46.6h17.8M63.4 49.1h17.8M63.4 51.7h17.8"/>
<path d="M63.4 54.2h17.8M63.4 56.8h17.8M63.4 59.3h17.8M98.9 41.5h17.8M98.9 44.1h17.8M98.9 46.6h17.8M98.9 49.1h17.8M98.9 51.7h17.8M98.9 54.2h17.8M98.9 56.8h17.8M147.2 41.5h17.8M147.2 44.1h17.8"/>
<path d="M147.2 46.6h17.8M147.2 49.1h17.8M147.2 51.7h17.8M147.2 54.2h17.8M147.2 56.8h17.8M147.2 59.3h17.8M15.1 69.5h17.8M15.1 72h17.8M15.1 79.6h17.8M15.1 74.5h17.8M63.4 61.8h17.8M63.4 64.4h17.8"/>
<path d="M63.4 69.5h25.4M63.4 72h25.4M63.4 77.1h25.4M63.4 79.6h25.4M91.3 79.6h25.4M98.9 69.5h17.8M98.9 72h17.8M98.9 74.5h17.8M147.2 61.8h17.8M147.2 64.4h17.8M147.2 69.5h25.4M147.2 72h25.4"/>
<path d="M147.2 77.1h25.4M147.2 79.6h25.4M15.1 84.7h17.8M15.1 82.2h17.8M63.4 84.7h17.8M63.4 87.2h17.8M91.3 82.2h25.4M98.9 84.7h17.8M147.2 84.7h17.8M147.2 87.2h17.8M192.9 110.1v2.5h58.4v20.4"/>
</g>
<circle cx="198" cy="112.7" r=".51" fill="#000080"/>
<circle cx="198" cy="112.7" r=".51" fill="none" stroke="#000080" stroke-width=".21"/>
<circle cx="208.2" cy="112.7" r=".51" fill="#000080"/>
<circle cx="208.2" cy="112.7" r=".51" fill="none" stroke="#000080" stroke-width=".21"/>
<circle cx="218.3" cy="112.7" r=".51" fill="#000080"/>
<circle cx="218.3" cy="112.7" r=".51" fill="none" stroke="#000080" stroke-width=".21"/>
<circle cx="228.5" cy="112.7" r=".51" fill="#000080"/>
<circle cx="228.5" cy="112.7" r=".51" fill="none" stroke="#000080" stroke-width=".21"/>
<circle cx="238.6" cy="112.7" r=".51" fill="#000080"/>
<circle cx="238.6" cy="112.7" r=".51" fill="none" stroke="#000080" stroke-width=".21"/>
<circle cx="243.7" cy="112.7" r=".51" fill="#000080"/>
<circle cx="243.7" cy="112.7" r=".51" fill="none" stroke="#000080" stroke-width=".21"/>
<circle cx="251.3" cy="112.7" r=".51" fill="#000080"/>
<circle cx="251.3" cy="112.7" r=".51" fill="none" stroke="#000080" stroke-width=".21"/>
<circle cx="251.3" cy="115.2" r=".51" fill="#000080"/>
<circle cx="251.3" cy="115.2" r=".51" fill="none" stroke="#000080" stroke-width=".21"/>
<circle cx="251.3" cy="117.7" r=".51" fill="#000080"/>
<circle cx="251.3" cy="117.7" r=".51" fill="none" stroke="#000080" stroke-width=".21"/>
<circle cx="251.3" cy="120.3" r=".51" fill="#000080"/>
<circle cx="251.3" cy="120.3" r=".51" fill="none" stroke="#000080" stroke-width=".21"/>
<circle cx="251.3" cy="122.8" r=".51" fill="#000080"/>
<circle cx="251.3" cy="122.8" r=".51" fill="none" stroke="#000080" stroke-width=".21"/>
<circle cx="251.3" cy="125.4" r=".51" fill="#000080"/>
<circle cx="251.3" cy="125.4" r=".51" fill="none" stroke="#000080" stroke-width=".21"/>
<circle cx="251.3" cy="127.9" r=".51" fill="#000080"/>
<circle cx="251.3" cy="127.9" r=".51" fill="none" stroke="#000080" stroke-width=".21"/>
<circle cx="251.3" cy="130.4" r=".51" fill="#000080"/>
<circle cx="251.3" cy="130.4" r=".51" fill="none" stroke="#000080" stroke-width=".21"/>
<path d="M192.9 140.6v2.5h58.4v20.3" fill="none" stroke="#000080" stroke-width=".25"/>
<circle cx="198" cy="143.1" r=".51" fill="#000080"/>
<circle cx="198" cy="143.1" r=".51" fill="none" stroke="#000080" stroke-width=".21"/>
<circle cx="208.2" cy="143.1" r=".51" fill="#000080"/>
<circle cx="208.2" cy="143.1" r=".51" fill="none" stroke="#000080" stroke-width=".21"/>
<circle cx="218.3" cy="143.1" r=".51" fill="#000080"/>
<circle cx="218.3" cy="143.1" r=".51" fill="none" stroke="#000080" stroke-width=".21"/>
<circle cx="228.5" cy="143.1" r=".51" fill="#000080"/>
<circle cx="228.5" cy="143.1" r=".51" fill="none" stroke="#000080" stroke-width=".21"/>
<circle cx="238.6" cy="143.1" r=".51" fill="#000080"/>
<circle cx="238.6" cy="143.1" r=".51" fill="none" stroke="#000080" stroke-width=".21"/>
<circle cx="251.3" cy="143.1" r=".51" fill="#000080"/>
<circle cx="251.3" cy="143.1" r=".51" fill="none" stroke="#000080" stroke-width=".21"/>
<circle cx="251.3" cy="145.7" r=".51" fill="#000080"/>
<circle cx="251.3" cy="145.7" r=".51" fill="none" stroke="#000080" stroke-width=".21"/>
<circle cx="251.3" cy="148.2" r=".51" fill="#000080"/>
<circle cx="251.3" cy="148.2" r=".51" fill="none" stroke="#000080" stroke-width=".21"/>
<circle cx="251.3" cy="150.8" r=".51" fill="#000080"/>
<circle cx="251.3" cy="150.8" r=".51" fill="none" stroke="#000080" stroke-width=".21"/>
<circle cx="251.3" cy="153.3" r=".51" fill="#000080"/>
<circle cx="251.3" cy="153.3" r=".51" fill="none" stroke="#000080" stroke-width=".21"/>
<circle cx="251.3" cy="155.8" r=".51" fill="#000080"/>
<circle cx="251.3" cy="155.8" r=".51" fill="none" stroke="#000080" stroke-width=".21"/>
<circle cx="251.3" cy="158.4" r=".51" fill="#000080"/>
<circle cx="251.3" cy="158.4" r=".51" fill="none" stroke="#000080" stroke-width=".21"/>
<circle cx="251.3" cy="160.9" r=".51" fill="#000080"/>
<circle cx="251.3" cy="160.9" r=".51" fill="none" stroke="#000080" stroke-width=".21"/>
<path d="M192.9 33.9v2.5h58.4v20.4" fill="none" stroke="#000080" stroke-width=".25"/>
<circle cx="198" cy="36.5" r=".51" fill="#000080"/>
<circle cx="198" cy="36.5" r=".51" fill="none" stroke="#000080" stroke-width=".21"/>
<circle cx="208.2" cy="36.5" r=".51" fill="#000080"/>
<circle cx="208.2" cy="36.5" r=".51" fill="none" stroke="#000080" stroke-width=".21"/>
<circle cx="218.3" cy="36.5" r=".51" fill="#000080"/>
<circle cx="218.3" cy="36.5" r=".51" fill="none" stroke="#000080" stroke-width=".21"/>
<circle cx="228.5" cy="36.5" r=".51" fill="#000080"/>
<circle cx="228.5" cy="36.5" r=".51" fill="none" stroke="#000080" stroke-width=".21"/>
<circle cx="238.6" cy="36.5" r=".51" fill="#000080"/>
<circle cx="238.6" cy="36.5" r=".51" fill="none" stroke="#000080" stroke-width=".21"/>
<circle cx="243.7" cy="36.5" r=".51" fill="#000080"/>
<circle cx="243.7" cy="36.5" r=".51" fill="none" stroke="#000080" stroke-width=".21"/>
<circle cx="251.3" cy="36.5" r=".51" fill="#000080"/>
<circle cx="251.3" cy="36.5" r=".51" fill="none" stroke="#000080" stroke-width=".21"/>
<circle cx="251.3" cy="39" r=".51" fill="#000080"/>
<circle cx="251.3" cy="39" r=".51" fill="none" stroke="#000080" stroke-width=".21"/>
<circle cx="251.3" cy="41.5" r=".51" fill="#000080"/>
<circle cx="251.3" cy="41.5" r=".51" fill="none" stroke="#000080" stroke-width=".21"/>
<circle cx="251.3" cy="44.1" r=".51" fill="#000080"/>
<circle cx="251.3" cy="44.1" r=".51" fill="none" stroke="#000080" stroke-width=".21"/>
<circle cx="251.3" cy="46.6" r=".51" fill="#000080"/>
<circle cx="251.3" cy="46.6" r=".51" fill="none" stroke="#000080" stroke-width=".21"/>
<circle cx="251.3" cy="49.2" r=".51" fill="#000080"/>
<circle cx="251.3" cy="49.2" r=".51" fill="none" stroke="#000080" stroke-width=".21"/>
<circle cx="251.3" cy="51.7" r=".51" fill="#000080"/>
<circle cx="251.3" cy="51.7" r=".51" fill="none" stroke="#000080" stroke-width=".21"/>
<circle cx="251.3" cy="54.2" r=".51" fill="#000080"/>
<circle cx="251.3" cy="54.2" r=".51" fill="none" stroke="#000080" stroke-width=".21"/>
<path d="M192.9 64.4v2.5h58.4v20.3" fill="none" stroke="#000080" stroke-width=".25"/>
<circle cx="198" cy="66.9" r=".51" fill="#000080"/>
<circle cx="198" cy="66.9" r=".51" fill="none" stroke="#000080" stroke-width=".21"/>
<circle cx="208.2" cy="66.9" r=".51" fill="#000080"/>
<circle cx="208.2" cy="66.9" r=".51" fill="none" stroke="#000080" stroke-width=".21"/>
<circle cx="218.3" cy="66.9" r=".51" fill="#000080"/>
<circle cx="218.3" cy="66.9" r=".51" fill="none" stroke="#000080" stroke-width=".21"/>
<circle cx="228.5" cy="66.9" r=".51" fill="#000080"/>
<circle cx="228.5" cy="66.9" r=".51" fill="none" stroke="#000080" stroke-width=".21"/>
<circle cx="238.6" cy="66.9" r=".51" fill="#000080"/>
<circle cx="238.6" cy="66.9" r=".51" fill="none" stroke="#000080" stroke-width=".21"/>
<circle cx="251.3" cy="66.9" r=".51" fill="#000080"/>
<circle cx="251.3" cy="66.9" r=".51" fill="none" stroke="#000080" stroke-width=".21"/>
<circle cx="251.3" cy="69.5" r=".51" fill="#000080"/>
<circle cx="251.3" cy="69.5" r=".51" fill="none" stroke="#000080" stroke-width=".21"/>
<circle cx="251.3" cy="72" r=".51" fill="#000080"/>
<circle cx="251.3" cy="72" r=".51" fill="none" stroke="#000080" stroke-width=".21"/>
<circle cx="251.3" cy="74.6" r=".51" fill="#000080"/>
<circle cx="251.3" cy="74.6" r=".51" fill="none" stroke="#000080" stroke-width=".21"/>
<circle cx="251.3" cy="77.1" r=".51" fill="#000080"/>
<circle cx="251.3" cy="77.1" r=".51" fill="none" stroke="#000080" stroke-width=".21"/>
<circle cx="251.3" cy="79.6" r=".51" fill="#000080"/>
<circle cx="251.3" cy="79.6" r=".51" fill="none" stroke="#000080" stroke-width=".21"/>
<circle cx="251.3" cy="82.2" r=".51" fill="#000080"/>
<circle cx="251.3" cy="82.2" r=".51" fill="none" stroke="#000080" stroke-width=".21"/>
<circle cx="251.3" cy="84.7" r=".51" fill="#000080"/>
<circle cx="251.3" cy="84.7" r=".51" fill="none" stroke="#000080" stroke-width=".21"/>
<g fill="none" stroke="#000080" stroke-width=".25">
<path d="M15.1 99.9h17.8M15.1 97.4h17.8M15.1 94.9h17.8M15.1 92.3h17.8M98.9 99.9h17.8M98.9 97.4h17.8M98.9 94.9h17.8M98.9 92.3h17.8M251.3 97.4v10.2M15.1 107.6h17.8M63.4 107.6h5.1M63.4 102.5h17.8"/>
<path d="M78.6 107.6h5.1v2.5M98.9 107.6h17.8M147.2 107.6h5.1M147.2 102.5h20.3M162.4 107.6h5.1v2.5M177.7 102.5h2.5v7.6M25.3 138h17.8M53.2 138h17.8M25.3 158.4h17.8M25.3 155.8h17.8M25.3 153.3h17.8M25.3 150.7h17.8"/>
<path d="M25.3 148.2h17.8M25.3 145.7h17.8M25.3 143.1h17.8M25.3 140.6h17.8M53.2 158.4h17.8M53.2 155.8h17.8M53.2 153.3h17.8M53.2 150.7h17.8M53.2 148.2h17.8M53.2 145.7h17.8M53.2 143.1h17.8M53.2 140.6h17.8"/>
<path d="M157.4 158.4h17.7M25.3 168.5h17.8M25.3 166h17.8M25.3 163.4h17.8M25.3 160.9h17.8M25.3 171.1h17.8M25.3 176.1h17.8M25.3 173.6h17.8M25.3 178.7h17.8M53.2 168.5h17.8M53.2 166h17.8M53.2 163.4h17.8"/>
<path d="M53.2 160.9h17.8M53.2 171.1h17.8M53.2 176.1h17.8M53.2 173.6h17.8M53.2 178.7h17.8M157.4 168.5h17.7M25.3 188.8h17.8M25.3 186.3h17.8M25.3 183.8h17.8M25.3 181.2h17.8M25.3 191.4h17.8M53.2 188.8h17.8"/>
<path d="M53.2 186.3h17.8M53.2 183.8h17.8M53.2 181.2h17.8M53.2 191.4h17.8"/>
</g>
<circle cx="251.3" cy="105" r=".51" fill="#000080"/>
<circle cx="251.3" cy="105" r=".51" fill="none" stroke="#000080" stroke-width=".21"/>
<circle cx="251.3" cy="100" r=".51" fill="#000080"/>
<circle cx="251.3" cy="100" r=".51" fill="none" stroke="#000080" stroke-width=".21"/>
<path d="M241.2 99.9h10.1" fill="none" stroke="#000080" stroke-width=".25"/>
<circle cx="243.7" cy="100" r=".51" fill="#000080"/>
<circle cx="243.7" cy="100" r=".51" fill="none" stroke="#000080" stroke-width=".21"/>
<circle cx="251.3" cy="100" r=".51" fill="#000080"/>
<circle cx="251.3" cy="100" r=".51" fill="none" stroke="#000080" stroke-width=".21"/>
<path d="M243.7 99.9v2.6" fill="none" stroke="#000080" stroke-width=".25"/>
<circle cx="243.7" cy="100" r=".51" fill="#000080"/>
<circle cx="243.7" cy="100" r=".51" fill="none" stroke="#000080" stroke-width=".21"/>
<path d="M251.3 21.2v10.2" fill="none" stroke="#000080" stroke-width=".25"/>
<circle cx="251.3" cy="28.8" r=".51" fill="#000080"/>
<circle cx="251.3" cy="28.8" r=".51" fill="none" stroke="#000080" stroke-width=".21"/>
<circle cx="251.3" cy="23.8" r=".51" fill="#000080"/>
<circle cx="251.3" cy="23.8" r=".51" fill="none" stroke="#000080" stroke-width=".21"/>
<path d="M241.2 23.7h10.1" fill="none" stroke="#000080" stroke-width=".25"/>
<circle cx="243.7" cy="23.8" r=".51" fill="#000080"/>
<circle cx="243.7" cy="23.8" r=".51" fill="none" stroke="#000080" stroke-width=".21"/>
<circle cx="251.3" cy="23.8" r=".51" fill="#000080"/>
<circle cx="251.3" cy="23.8" r=".51" fill="none" stroke="#000080" stroke-width=".21"/>
<path d="M243.7 23.7v2.6" fill="none" stroke="#000080" stroke-width=".25"/>
<circle cx="243.7" cy="23.8" r=".51" fill="#000080"/>
<circle cx="243.7" cy="23.8" r=".51" fill="none" stroke="#000080" stroke-width=".21"/>
<path d="M231 23.7h-2.5v2.6M231 99.9h-2.5v2.6M98.9 148.2v2.5M98.9 160.9v5.1M98.9 176.1v2.6" fill="none" stroke="#000080" stroke-width=".25"/>
<circle cx="98.9" cy="163.5" r=".51" fill="#000080"/>
<circle cx="98.9" cy="163.5" r=".51" fill="none" stroke="#000080" stroke-width=".21"/>
<path d="M98.9 163.4h17.8" fill="none" stroke="#000080" stroke-width=".25"/>
<circle cx="98.9" cy="163.5" r=".51" fill="#000080"/>
<circle cx="98.9" cy="163.5" r=".51" fill="none" stroke="#000080" stroke-width=".21"/>
<circle cx="109.1" cy="163.5" r=".51" fill="#000080"/>
<circle cx="109.1" cy="163.5" r=".51" fill="none" stroke="#000080" stroke-width=".21"/>
<path d="M109.1 163.4v2.6M109.1 176.1v2.6" fill="none" stroke="#000080" stroke-width=".25"/>
<circle cx="109.1" cy="163.5" r=".51" fill="#000080"/>
<circle cx="109.1" cy="163.5" r=".51" fill="none" stroke="#000080" stroke-width=".21"/>
<g fill="none" stroke="#f00" stroke-width=".21">
<path d="M55.8 134.2v.8M55.8 135.5v.8M55.8 136.8v.8M55.8 138v.8M55.8 139.3v.8M56.6 133h-.8v.8M57 133h.8M58.3 133h.8M59.6 133h.8M60.8 133h.8M62.1 133h.8M63.4 133h.8"/>
<path d="M64.6 133h.8M65.9 133h.8M67.2 133h.8M68.5 133h.8M69.7 133h.8M71 133h.8M72.3 133h.8M73.5 133v.8M73.5 134.2v.8M73.5 135.5v.8M73.5 136.8v.8M73.5 138v.8"/>
<path d="M73.5 139.3v.8M55.8 140.6v.8M55.8 141.9v.8M55.8 143.1v.8M55.8 144.4v.8M55.8 145.7v.8M55.8 146.9v.8M55.8 148.2v.8M55.8 149.5v.8M55.8 150.7v.8M55.8 152v.8M55.8 153.3v.8"/>
<path d="M55.8 154.6v.8M55.8 155.8v.8M55.8 157.1v.8M55.8 158.4v.8M55.8 159.6v.8M73.5 140.6v.8M73.5 141.9v.8M73.5 143.1v.8M73.5 144.4v.8M73.5 145.7v.8M73.5 146.9v.8M73.5 148.2v.8"/>
<path d="M73.5 149.5v.8M73.5 150.7v.8M73.5 152v.8M73.5 153.3v.8M73.5 154.6v.8M73.5 155.8v.8M73.5 157.1v.8M73.5 158.4v.8M73.5 159.6v.8M55.8 160.9v.8M55.8 162.2v.8M55.8 163.4v.8"/>
<path d="M55.8 164.7v.8M55.8 166v.8M55.8 167.3v.8M55.8 168.5v.8M55.8 169.8v.8M55.8 171.1v.8M55.8 172.3v.8M55.8 173.6v.8M55.8 174.9v.8M55.8 176.1v.8M55.8 177.4v.8M55.8 178.7v.8"/>
<path d="M55.8 180v.8M73.5 160.9v.8M73.5 162.2v.8M73.5 163.4v.8M73.5 164.7v.8M73.5 166v.8M73.5 167.3v.8M73.5 168.5v.8M73.5 169.8v.8M73.5 171.1v.8M73.5 172.3v.8M73.5 173.6v.8"/>
<path d="M73.5 174.9v.8M73.5 176.1v.8M73.5 177.4v.8M73.5 178.7v.8M73.5 180v.8M55.8 181.2v.8M55.8 182.5v.8M55.8 183.8v.8M55.8 185v.8M55.8 186.3v.8M55.8 187.6v.8M55.8 188.8v.8"/>
<path d="M55.8 190.1v.8M55.8 191.4v.8M55.8 192.7v.8M56.2 193.9h.8M57.5 193.9h.8M58.8 193.9h.8M60 193.9h.8M61.3 193.9h.8M62.6 193.9h.8M63.9 193.9h.8M65.1 193.9h.8M66.4 193.9h.8"/>
<path d="M67.7 193.9h.8M68.9 193.9h.8M70.2 193.9h.8M71.5 193.9h.8M72.7 193.9h.8M73.5 181.2v.8M73.5 182.5v.8M73.5 183.8v.8M73.5 185v.8M73.5 186.3v.8M73.5 187.6v.8M73.5 188.8v.8"/>
<path d="M73.5 190.1v.8M73.5 191.4v.8M73.5 192.7v.8"/>
</g>
<path d="M57 133.5l1 1.8h-2z" fill="none" stroke="#f33" stroke-width=".21"/>
<g fill="none" stroke="#f00" stroke-width=".25">
<path d="M73.5 131.4v1.6"/>
<circle cx="73.5" cy="129.9" r="1.52"/>
</g>
<use href="#words"/>
</svg>
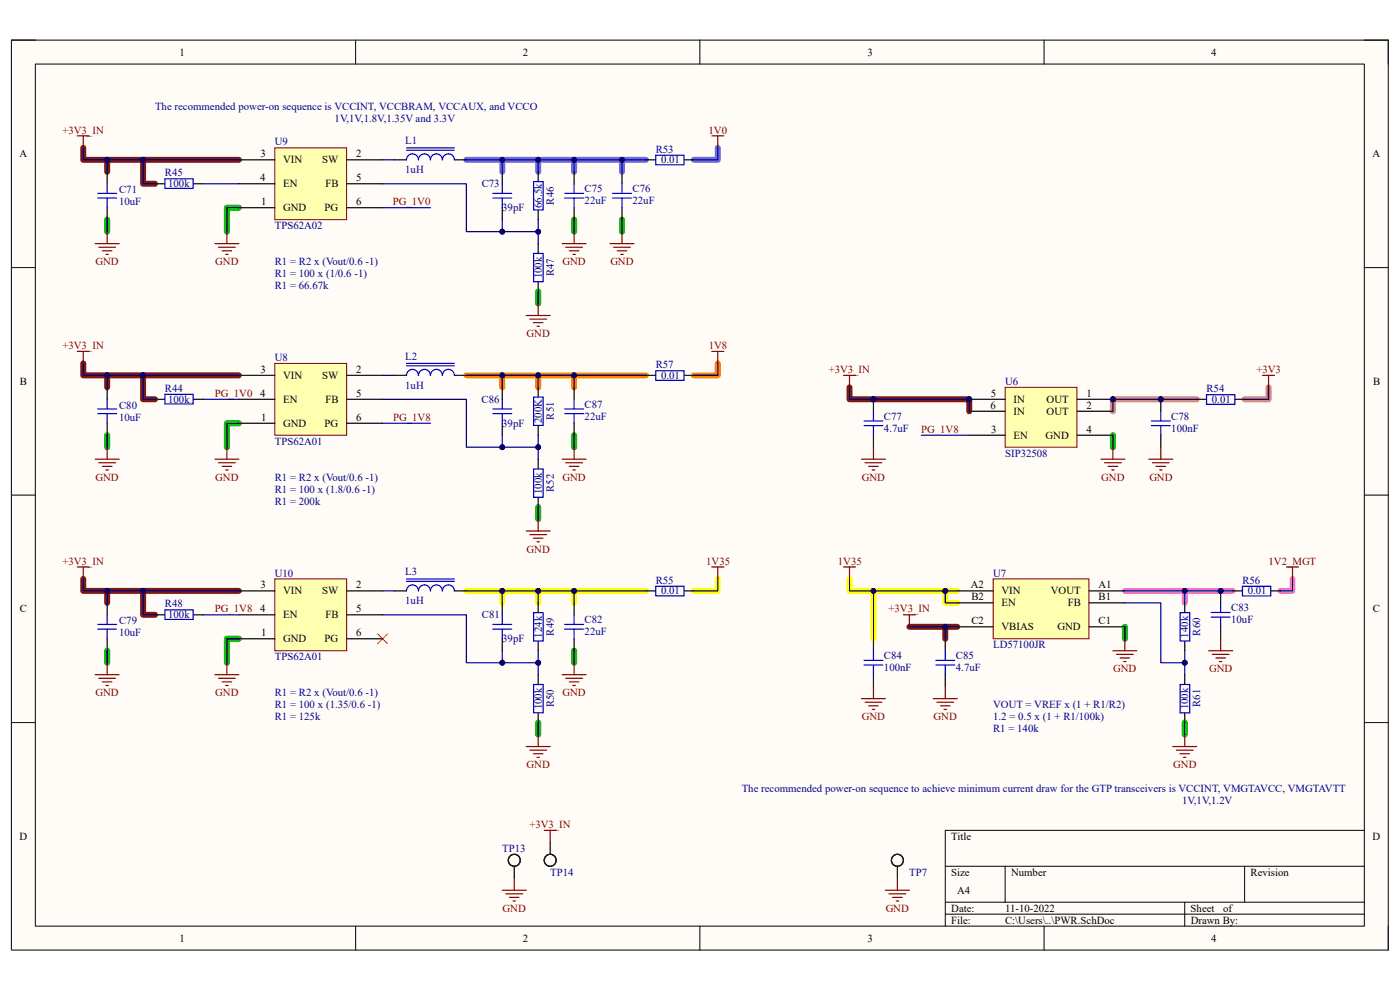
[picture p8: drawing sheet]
<svg xmlns="http://www.w3.org/2000/svg" width="297mm" height="210mm" viewBox="0 0 297 210" stroke-linecap="round" stroke-linejoin="round" font-family="sans-serif">
<defs><g id="words">
<g font-size="2.3">
<text x="38.1" y="11.8">1</text>
<text x="110.9" y="11.8">2</text>
<text x="184" y="11.8">3</text>
<text x="256.9" y="11.8">4</text>
<text x="4.1" y="33.4">A</text>
<text x="55.3" y="33.4">3</text>
<text x="60.1" y="34.7">VIN</text>
<text x="68.3" y="34.7">SW</text>
<text x="75.6" y="33.4">2</text>
<text x="291.2" y="33.4">A</text>
<text x="55.2" y="38.5">4</text>
<text x="60.1" y="39.8">EN</text>
<text x="69.1" y="39.8">FB</text>
<text x="75.6" y="38.5">5</text>
<text x="55.4" y="43.6">1</text>
<text x="60.1" y="44.8">GND</text>
<text x="68.9" y="44.8">PG</text>
<text x="75.6" y="43.6">6</text>
<text x="4.2" y="81.7">B</text>
<text x="55.3" y="79.1">3</text>
<text x="60.1" y="80.4">VIN</text>
<text x="68.3" y="80.4">SW</text>
<text x="75.6" y="79.1">2</text>
<text x="291.3" y="81.7">B</text>
<text x="55.2" y="84.2">4</text>
<text x="55.4" y="89.3">1</text>
<text x="60.1" y="85.5">EN</text>
<text x="69.1" y="85.5">FB</text>
<text x="75.6" y="84.2">5</text>
<text x="75.6" y="89.3">6</text>
<text x="210.1" y="86.7">6</text>
<text x="210.2" y="84.2">5</text>
<text x="215" y="85.5">IN</text>
<text x="215" y="88">IN</text>
<text x="222" y="85.5">OUT</text>
<text x="222" y="88">OUT</text>
<text x="230.5" y="84.2">1</text>
<text x="230.5" y="86.7">2</text>
<text x="60.1" y="90.6">GND</text>
<text x="68.9" y="90.6">PG</text>
<text x="210.3" y="91.8">3</text>
<text x="215" y="93.1">EN</text>
<text x="221.8" y="93.1">GND</text>
<text x="230.5" y="91.8">4</text>
<text x="55.3" y="124.8">3</text>
<text x="75.6" y="124.8">2</text>
<text x="206" y="124.8">A2</text>
<text x="233" y="124.8">A1</text>
<text x="4.2" y="129.9">C</text>
<text x="55.2" y="129.9">4</text>
<text x="60.1" y="126.1">VIN</text>
<text x="60.1" y="131.2">EN</text>
<text x="68.3" y="126.1">SW</text>
<text x="69.1" y="131.2">FB</text>
<text x="75.6" y="129.9">5</text>
<text x="206.1" y="127.4">B2</text>
<text x="212.5" y="126.1">VIN</text>
<text x="212.5" y="128.7">EN</text>
<text x="222.9" y="126.1">VOUT</text>
<text x="226.6" y="128.7">FB</text>
<text x="233" y="127.4">B1</text>
<text x="291.3" y="129.9">C</text>
<text x="55.4" y="135">1</text>
<text x="60.1" y="136.3">GND</text>
<text x="68.9" y="136.3">PG</text>
<text x="75.6" y="135">6</text>
<text x="206.1" y="132.5">C2</text>
<text x="212.5" y="133.7">VBIAS</text>
<text x="224.4" y="133.7">GND</text>
<text x="233" y="132.5">C1</text>
<text x="4.1" y="178.2">D</text>
<text x="201.8" y="178.2">Title</text>
<text x="291.2" y="178.2">D</text>
<text x="201.8" y="185.8">Size</text>
<text x="214.5" y="185.8">Number</text>
<text x="265.3" y="185.8">Revision</text>
<text x="203.1" y="189.6">A4</text>
<text x="201.8" y="193.4">Date:</text>
<text x="201.8" y="196">File:</text>
<text x="213.2" y="196">C:\Users\..\PWR.SchDoc</text>
<text x="213.2" y="193.4">11-10-2022</text>
<text x="252.6" y="193.4">Sheet</text>
<text x="252.6" y="196">Drawn By:</text>
<text x="259.5" y="193.4">of</text>
<text x="38.1" y="199.8">1</text>
<text x="110.9" y="199.8">2</text>
<text x="184" y="199.8">3</text>
<text x="256.9" y="199.8">4</text>
</g>
<g font-size="2.3" fill="#000080">
<text x="32.9" y="23.2">The recommended power-on sequence is VCCINT, VCCBRAM, VCCAUX, and VCCO</text>
<text x="71" y="25.8">1V,1V,1.8V,1.35V and 3.3V</text>
<text x="58.3" y="30.9">U9</text>
<text x="86" y="30.6">L1</text>
<text x="139.1" y="32.4">R53</text>
<text x="140.3" y="34.7">0.01</text>
<text x="25.3" y="41">C71</text>
<text x="35" y="37.4">R45</text>
<text x="35.7" y="39.8">100k</text>
<text x="86" y="36.7">1uH</text>
<text x="102.2" y="39.8">C73</text>
<text x="124" y="40.8">C75</text>
<text x="134.2" y="40.8">C76</text>
<text x="25.3" y="43.6">10uF</text>
<text x="106.6" y="44.8">39pF</text>
<text x="114.9" y="44.1" transform="rotate(-90 114.9 44.1)">66.5k</text>
<text x="117.5" y="43.4" transform="rotate(-90 117.5 43.4)">R46</text>
<text x="124" y="43.3">22uF</text>
<text x="134.2" y="43.3">22uF</text>
<text x="58.3" y="48.6">TPS62A02</text>
<text x="58.3" y="56.3">R1 = R2 x (Vout/0.6 -1)</text>
<text x="58.3" y="58.8">R1 = 100 x (1/0.6 -1)</text>
<text x="114.9" y="59.1" transform="rotate(-90 114.9 59.1)">100k</text>
<text x="117.5" y="58.6" transform="rotate(-90 117.5 58.6)">R47</text>
<text x="58.3" y="61.3">R1 = 66.67k</text>
<text x="58.3" y="76.6">U8</text>
<text x="86" y="76.3">L2</text>
<text x="35" y="83.1">R44</text>
<text x="86" y="82.4">1uH</text>
<text x="139.1" y="78.1">R57</text>
<text x="140.3" y="80.4">0.01</text>
<text x="213.2" y="81.7">U6</text>
<text x="255.9" y="83.2">R54</text>
<text x="25.3" y="86.7">C80</text>
<text x="25.3" y="89.3">10uF</text>
<text x="35.7" y="85.5">100k</text>
<text x="102.2" y="85.5">C86</text>
<text x="114.9" y="89.8" transform="rotate(-90 114.9 89.8)">200K</text>
<text x="117.5" y="89" transform="rotate(-90 117.5 89)">R51</text>
<text x="124" y="86.5">C87</text>
<text x="124" y="89">22uF</text>
<text x="187.5" y="89">C77</text>
<text x="248.5" y="89">C78</text>
<text x="257.1" y="85.5">0.01</text>
<text x="58.3" y="94.4">TPS62A01</text>
<text x="106.6" y="90.6">39pF</text>
<text x="187.5" y="91.6">4.7uF</text>
<text x="248.5" y="91.6">100nF</text>
<text x="58.3" y="102">R1 = R2 x (Vout/0.6 -1)</text>
<text x="213.2" y="96.9">SIP32508</text>
<text x="58.3" y="104.5">R1 = 100 x (1.8/0.6 -1)</text>
<text x="58.3" y="107.1">R1 = 200k</text>
<text x="114.9" y="104.8" transform="rotate(-90 114.9 104.8)">100k</text>
<text x="117.5" y="104.4" transform="rotate(-90 117.5 104.4)">R52</text>
<text x="58.3" y="122.3">U10</text>
<text x="86" y="122">L3</text>
<text x="139.1" y="123.9">R55</text>
<text x="210.7" y="122.3">U7</text>
<text x="263.6" y="123.9">R56</text>
<text x="35" y="128.9">R48</text>
<text x="35.7" y="131.2">100k</text>
<text x="86" y="128.1">1uH</text>
<text x="102.2" y="131.2">C81</text>
<text x="140.3" y="126.1">0.01</text>
<text x="261.2" y="129.7">C83</text>
<text x="264.7" y="126.1">0.01</text>
<text x="25.3" y="132.5">C79</text>
<text x="25.3" y="135">10uF</text>
<text x="106.6" y="136.3">39pF</text>
<text x="114.9" y="135.3" transform="rotate(-90 114.9 135.3)">124k</text>
<text x="117.5" y="134.8" transform="rotate(-90 117.5 134.8)">R49</text>
<text x="124" y="132.2">C82</text>
<text x="124" y="134.7">22uF</text>
<text x="210.7" y="137.5">LD57100JR</text>
<text x="252.1" y="135.3" transform="rotate(-90 252.1 135.3)">140k</text>
<text x="254.6" y="134.8" transform="rotate(-90 254.6 134.8)">R60</text>
<text x="261.2" y="132.2">10uF</text>
<text x="58.3" y="140.1">TPS62A01</text>
<text x="187.5" y="139.8">C84</text>
<text x="187.5" y="142.4">100nF</text>
<text x="202.8" y="139.8">C85</text>
<text x="202.8" y="142.4">4.7uF</text>
<text x="58.3" y="147.7">R1 = R2 x (Vout/0.6 -1)</text>
<text x="254.6" y="150" transform="rotate(-90 254.6 150)">R61</text>
<text x="58.3" y="150.2">R1 = 100 x (1.35/0.6 -1)</text>
<text x="58.3" y="152.8">R1 = 125k</text>
<text x="114.9" y="150.5" transform="rotate(-90 114.9 150.5)">100k</text>
<text x="117.5" y="150.1" transform="rotate(-90 117.5 150.1)">R50</text>
<text x="210.7" y="150.2">VOUT = VREF x (1 + R1/R2)</text>
<text x="210.7" y="152.8">1.2 = 0.5 x (1 + R1/100k)</text>
<text x="210.7" y="155.3">R1 = 140k</text>
<text x="252.1" y="150.5" transform="rotate(-90 252.1 150.5)">100k</text>
<text x="157.4" y="168">The recommended power-on sequence to achieve minimum current draw for the GTP transceivers is VCCINT, VMGTAVCC, VMGTAVTT</text>
<text x="250.8" y="170.6">1V,1V,1.2V</text>
<text x="106.6" y="180.7">TP13</text>
<text x="116.7" y="185.8">TP14</text>
<text x="192.9" y="185.8">TP7</text>
</g>
<g font-size="2.3" fill="#800000">
<text x="13.3" y="28.3">+3V3_IN</text>
<text x="150.3" y="28.3">1V0</text>
<text x="83.4" y="43.6">PG_1V0</text>
<text x="20.3" y="56.3">GND</text>
<text x="45.7" y="56.3">GND</text>
<text x="119.3" y="56.3">GND</text>
<text x="129.5" y="56.3">GND</text>
<text x="111.7" y="71.5">GND</text>
<text x="13.3" y="74">+3V3_IN</text>
<text x="150.4" y="74">1V8</text>
<text x="175.8" y="79.1">+3V3_IN</text>
<text x="266.6" y="79.1">+3V3</text>
<text x="45.6" y="84.2">PG_1V0</text>
<text x="83.4" y="89.3">PG_1V8</text>
<text x="195.5" y="91.8">PG_1V8</text>
<text x="20.3" y="102">GND</text>
<text x="45.7" y="102">GND</text>
<text x="119.3" y="102">GND</text>
<text x="182.8" y="102">GND</text>
<text x="233.6" y="102">GND</text>
<text x="243.8" y="102">GND</text>
<text x="13.3" y="119.8">+3V3_IN</text>
<text x="111.7" y="117.2">GND</text>
<text x="149.8" y="119.8">1V35</text>
<text x="177.8" y="119.8">1V35</text>
<text x="269.1" y="119.8">1V2_MGT</text>
<text x="45.6" y="129.9">PG_1V8</text>
<text x="188.5" y="129.9">+3V3_IN</text>
<text x="236.2" y="142.6">GND</text>
<text x="256.5" y="142.6">GND</text>
<text x="20.3" y="147.7">GND</text>
<text x="45.7" y="147.7">GND</text>
<text x="119.3" y="147.7">GND</text>
<text x="182.8" y="152.8">GND</text>
<text x="198.1" y="152.8">GND</text>
<text x="111.7" y="162.9">GND</text>
<text x="248.9" y="162.9">GND</text>
<text x="112.3" y="175.6">+3V3_IN</text>
<text x="106.6" y="193.4">GND</text>
<text x="187.9" y="193.4">GND</text>
</g>
</g></defs>
<path d="M2.4 8.5h292.1v193h-292.1z" fill-rule="evenodd" fill="#fffcf8"/>
<path d="M2.4 8.5h292.1v193h-292.1z" fill="none" stroke="#000" stroke-width=".21"/>
<path d="M7.5 13.6h281.9v182.9h-281.9z" fill-rule="evenodd" fill="#fffcf8"/>
<g fill="none" stroke="#000" stroke-width=".21">
<path d="M2.4 8.5h5.1M7.5 13.6h281.9v182.9h-281.9zM75.4 8.5v5.1M148.5 8.5v5.1M221.5 8.5v5.1M289.4 8.5h5.1v5.1M2.4 56.8h5.1M289.4 56.8h5.1M2.4 105h5.1M289.4 105h5.1M2.4 153.3h5.1M289.4 153.3h5.1"/>
<path d="M289.4 176.1h-88.9v20.4M75.4 196.5v5M148.5 196.5v5M200.5 183.8h88.9M200.5 191.4h88.9M200.5 193.9h88.9M213.2 183.8v7.6M221.5 196.5v5M251.3 191.4v5.1M264 183.8v7.6M294.5 196.5v5"/>
</g>
<path d="M17.7 31.4v2.5h5M30.4 33.9v5.1h2.5M50.7 33.9h-28v2.5M17.7 77.1v2.5h5M30.4 79.6v5.1h2.5M50.7 79.6h-28v2.6M180.2 82.2v2.5h25.4v2.5M17.7 122.8v2.5h5M30.4 125.3v5.1h2.5M50.7 125.3h-28v2.6M192.9 133h7.6M203.1 133h-2.6v2.5" fill="none" stroke="#781915" stroke-width="1.3"/>
<g fill="none" stroke="#00be00" stroke-width="1.3">
<path d="M22.7 46.6v2.5M50.7 44.1h-2.6v5M121.8 46.6v2.5M132 46.6v2.5M114.2 61.8v2.6M22.7 92.3v2.6M50.7 89.8h-2.6v5.1M121.8 92.3v2.6M236.1 92.3v2.6M114.2 107.6v2.5M22.7 138v2.6M50.7 135.5h-2.6v5.1"/>
<path d="M121.8 138v2.6M238.6 133v2.5M114.2 153.3v2.5M251.3 153.3v2.5"/>
</g>
<path d="M238.6 125.3h22.9M251.3 125.3v2.6M274.2 122.8v2.5h-2.5" fill="none" stroke="#ff6eff" stroke-width="1.3"/>
<path d="M253.9 84.7h-17.8v2.5M269.1 82.2v2.5h-5.1" fill="none" stroke="#ff6e6e" stroke-width="1.3"/>
<path d="M98.9 33.9h22.9v2.5M106.6 33.9v2.5M114.2 33.9v2.5M121.8 33.9h15.2M132 33.9v2.5M152.3 31.4v2.5h-5.1" fill="none" stroke="#6e6eff" stroke-width="1.3"/>
<path d="M98.9 125.3h22.9v2.6M106.6 125.3v2.6M114.2 125.3v2.6M121.8 125.3h15.2M152.3 122.8v2.5h-5.1M180.2 122.8v2.5h22.9M185.3 125.3v10.2M200.5 125.3v2.6h2.6" fill="none" stroke="#ff0" stroke-width="1.3"/>
<path d="M98.9 79.6h22.9v2.6M106.6 79.6v2.6M114.2 79.6v2.6M121.8 79.6h15.2M152.3 77.1v2.5h-5.1" fill="none" stroke="#fd8300" stroke-width="1.3"/>
<circle cx="236.1" cy="84.7" r=".51" fill="#000080"/>
<circle cx="236.1" cy="84.7" r=".51" fill="none" stroke="#000080" stroke-width=".21"/>
<circle cx="205.6" cy="84.7" r=".51" fill="#000080"/>
<circle cx="205.6" cy="84.7" r=".51" fill="none" stroke="#000080" stroke-width=".21"/>
<path d="M213.2 82.2h15.3v12.7h-15.3z" fill-rule="evenodd" fill="#ffffb0"/>
<path d="M213.2 82.2h15.3v12.7h-15.3z" fill="none" stroke="#800000" stroke-width=".21"/>
<path d="M228.5 84.7h7.6" fill="none" stroke="#000" stroke-width=".25"/>
<circle cx="236.1" cy="84.7" r=".51" fill="#000080"/>
<circle cx="236.1" cy="84.7" r=".51" fill="none" stroke="#000080" stroke-width=".21"/>
<path d="M205.6 92.3h7.6M205.6 84.7h7.6M228.5 87.2h7.6M228.5 92.3h7.6" fill="none" stroke="#000" stroke-width=".25"/>
<circle cx="205.6" cy="84.7" r=".51" fill="#000080"/>
<circle cx="205.6" cy="84.7" r=".51" fill="none" stroke="#000080" stroke-width=".21"/>
<path d="M205.6 87.2h7.6" fill="none" stroke="#000" stroke-width=".25"/>
<path d="M267.9 79.6h2.5M269.1 79.6v2.6M272.9 120.3h2.6M274.2 120.3v2.5" fill="none" stroke="#800000" stroke-width=".25"/>
<path d="M210.7 122.8h20.3v12.7h-20.3z" fill-rule="evenodd" fill="#ffffb0"/>
<path d="M210.7 122.8h20.3v12.7h-20.3z" fill="none" stroke="#800000" stroke-width=".21"/>
<path d="M203.1 125.3h7.6M203.1 127.9h7.6M203.1 133h7.6M231 125.3h7.6M231 127.9h7.6M231 133h7.6" fill="none" stroke="#000" stroke-width=".25"/>
<g fill="none" stroke="#800000" stroke-width=".25">
<path d="M179 79.6h2.5M180.2 79.6v2.6M233.6 97.4h5M234.3 98.2h3.6M235.1 98.9h2M235.8 99.7h.6M236.1 94.9v2.5M179 120.3h2.5M180.2 120.3v2.5M236.1 138h5.1M236.9 138.8h3.5M237.6 139.6h2.1"/>
<path d="M238.6 135.5v2.5M238.4 140.3h.5"/>
</g>
<circle cx="185.3" cy="84.7" r=".51" fill="#000080"/>
<circle cx="185.3" cy="84.7" r=".51" fill="none" stroke="#000080" stroke-width=".21"/>
<path d="M185.3 84.7v2.5M185.3 92.3v2.6" fill="none" stroke="#000" stroke-width=".25"/>
<circle cx="185.3" cy="84.7" r=".51" fill="#000080"/>
<circle cx="185.3" cy="84.7" r=".51" fill="none" stroke="#000080" stroke-width=".21"/>
<path d="M183.3 90.3h4M183.3 89.3h4M185.3 87.2v2.1M185.3 90.3v2" fill="none" stroke="#00f" stroke-width=".25"/>
<path d="M182.8 97.4h5M183.5 98.2h3.6M184.3 98.9h2M185 99.7h.6M185.3 94.9v2.5" fill="none" stroke="#800000" stroke-width=".25"/>
<circle cx="246.3" cy="84.7" r=".51" fill="#000080"/>
<circle cx="246.3" cy="84.7" r=".51" fill="none" stroke="#000080" stroke-width=".21"/>
<path d="M246.3 84.7v2.5M246.3 92.3v2.6" fill="none" stroke="#000" stroke-width=".25"/>
<circle cx="246.3" cy="84.7" r=".51" fill="#000080"/>
<circle cx="246.3" cy="84.7" r=".51" fill="none" stroke="#000080" stroke-width=".21"/>
<path d="M244.3 90.3h4M244.3 89.3h4M246.3 87.2v2.1M246.3 90.3v2M200.5 138v2.1M198.5 141.1h4M198.5 140.1h4M200.5 141.1v2" fill="none" stroke="#00f" stroke-width=".25"/>
<path d="M243.7 97.4h5.1M244.5 98.2h3.5M245.2 98.9h2.1M246 99.7h.5M246.3 94.9v2.5M198 148.2h5.1M198.8 149h3.5M199.5 149.7h2.1M200.3 150.5h.5M200.5 145.7v2.5" fill="none" stroke="#800000" stroke-width=".25"/>
<path d="M200.5 135.5v2.5M200.5 143.1v2.6" fill="none" stroke="#000" stroke-width=".25"/>
<circle cx="259" cy="125.4" r=".51" fill="#000080"/>
<circle cx="259" cy="125.4" r=".51" fill="none" stroke="#000080" stroke-width=".21"/>
<path d="M259 125.3v2.6M259 133v2.5" fill="none" stroke="#000" stroke-width=".25"/>
<circle cx="259" cy="125.4" r=".51" fill="#000080"/>
<circle cx="259" cy="125.4" r=".51" fill="none" stroke="#000080" stroke-width=".21"/>
<path d="M256 83.7h6v2.1h-6zM185.3 138v2.1M250.4 130h2v6h-2zM257 130.9h4M257 129.9h4M259 127.9v2M259 130.9v2.1M263.6 124.4h6v2h-6zM183.3 141.1h4M183.3 140.1h4M185.3 141.1v2M250.4 145.2h2v6h-2z" fill="none" stroke="#00f" stroke-width=".25"/>
<g fill="none" stroke="#800000" stroke-width=".25">
<path d="M256.4 138h5.1M257.2 138.8h3.5M257.9 139.6h2.1M259 135.5v2.5M182.8 148.2h5M183.5 149h3.6M184.3 149.7h2M185 150.5h.6M185.3 145.7v2.5M248.8 158.4h5.1M249.6 159.1h3.5M250.3 159.9h2.1"/>
<path d="M251.3 155.8v2.6M258.7 140.3h.5M251.1 160.7h.5"/>
</g>
<path d="M253.9 84.7h2M262 84.7h2M185.3 135.5v2.5M251.3 127.9v2M251.3 136v2M261.5 125.3h2M269.7 125.3h2M185.3 143.1v2.6M251.3 143.1v2M251.3 151.3v2" fill="none" stroke="#000" stroke-width=".25"/>
<path d="M58.3 31.4h15.2v15.2h-15.2z" fill-rule="evenodd" fill="#ffffb0"/>
<path d="M58.3 31.4h15.2v15.2h-15.2z" fill="none" stroke="#800000" stroke-width=".21"/>
<g fill="none" stroke="#000" stroke-width=".25">
<path d="M22.7 36.4v2.6M32.9 39h2M41.1 39h2M50.7 33.9h7.6M50.7 39h7.6M73.5 33.9h7.7M73.5 39h7.7M83.7 33.9h2.5M96.4 33.9h2.5M106.6 36.4v2.6M114.2 36.4v2M121.8 36.4v2.6"/>
<path d="M132 36.4v2.6M137 33.9h2M145.2 33.9h2M22.7 44.1v2.5M50.7 44.1h7.6M73.5 44.1h7.7M106.6 44.1v2.5M114.2 44.6v2M114.2 51.7v2M114.2 59.8v2M121.8 44.1v2.5M132 44.1v2.5"/>
</g>
<g fill="none" stroke="#800000" stroke-width=".25">
<path d="M16.4 28.8h2.5M17.7 28.8v2.6M151 28.8h2.5M152.3 28.8v2.6M20.2 51.7h5.1M21 52.4h3.5M21.7 53.2h2.1M22.5 54h.5M22.7 49.1v2.6M45.6 51.7h5.1M46.4 52.4h3.5M47.1 53.2h2.1"/>
<path d="M47.9 54h.5M48.1 49.1v2.6M119.3 51.7h5M120 52.4h3.6M120.8 53.2h2M121.5 54h.6M121.8 49.1v2.6M129.4 51.7h5.1M130.2 52.4h3.5M130.9 53.2h2.1M131.7 54h.5M132 49.1v2.6"/>
<path d="M111.6 66.9h5.1M112.4 67.7h3.6M113.2 68.5h2M113.9 69.2h.5M114.2 64.4v2.5"/>
</g>
<g fill="none" stroke="#00f" stroke-width=".25">
<path d="M22.7 39v2M35 37.9h6v2.1h-6zM86.2 33.9a1.27 1.27 0 0 1 1.3-1.3 1.27 1.27 0 0 1 1.3 1.3 1.27 1.27 0 0 1 1.2-1.3 1.27 1.27 0 0 1 1.3 1.3 1.27 1.27 0 0 1 1.3-1.3 1.27 1.27 0 0 1 1.3 1.3 1.27 1.27 0 0 1 1.2-1.3 1.27 1.27 0 0 1 1.3 1.3M86.2 31.9h10.2M86.2 31.4h10.2M106.6 39v2M113.2 38.5h2v6h-2zM121.8 39v2M132 39v2M139.1 32.9h6v2.1h-6zM20.7 42h4M20.7 41h4"/>
<path d="M22.7 42v2.1M104.6 42h4M104.6 41h4M106.6 42v2.1M113.2 53.8h2v6h-2zM119.8 42h4M119.8 41h4M121.8 42v2.1M130 42h4M130 41h4M132 42v2.1"/>
</g>
<path d="M58.3 122.8h15.2v15.2h-15.2z" fill-rule="evenodd" fill="#ffffb0"/>
<path d="M58.3 122.8h15.2v15.2h-15.2z" fill="none" stroke="#800000" stroke-width=".21"/>
<g fill="none" stroke="#000" stroke-width=".25">
<path d="M22.7 127.9v2.5M22.7 135.5v2.5M32.9 130.4h2M41.1 130.4h2M50.7 125.3h7.6M50.7 135.5h7.6M50.7 130.4h7.6M73.5 125.3h7.7M73.5 135.5h7.7M73.5 130.4h7.7M83.7 125.3h2.5M96.4 125.3h2.5"/>
<path d="M106.6 127.9v2.5M106.6 135.5v2.5M114.2 127.9v2M114.2 136v2M121.8 127.9v2.5M121.8 135.5v2.5M137 125.3h2M145.2 125.3h2M114.2 143.1v2M114.2 151.3v2"/>
</g>
<g fill="none" stroke="#800000" stroke-width=".25">
<path d="M16.4 120.3h2.5M17.7 120.3v2.5M151 120.3h2.5M152.3 120.3v2.5M20.2 143.1h5.1M21 143.9h3.5M21.7 144.7h2.1M22.5 145.4h.5M22.7 140.6v2.5M45.6 143.1h5.1M46.4 143.9h3.5M47.1 144.7h2.1"/>
<path d="M47.9 145.4h.5M48.1 140.6v2.5M111.6 158.4h5.1M112.4 159.1h3.6M113.2 159.9h2M114.2 155.8v2.6M119.3 143.1h5M120 143.9h3.6M120.8 144.7h2M121.5 145.4h.6M121.8 140.6v2.5M113.9 160.7h.5"/>
</g>
<g fill="none" stroke="#00f" stroke-width=".25">
<path d="M20.7 133.5h4M20.7 132.5h4M22.7 130.4v2.1M22.7 133.5v2M35 129.4h6v2h-6zM86.2 125.3a1.27 1.27 0 0 1 1.3-1.2 1.27 1.27 0 0 1 1.3 1.2 1.27 1.27 0 0 1 1.2-1.2 1.27 1.27 0 0 1 1.3 1.2 1.27 1.27 0 0 1 1.3-1.2 1.27 1.27 0 0 1 1.3 1.2 1.27 1.27 0 0 1 1.2-1.2 1.27 1.27 0 0 1 1.3 1.2M86.2 123.3h10.2M86.2 122.8h10.2M104.6 133.5h4M104.6 132.5h4M106.6 130.4v2.1M106.6 133.5v2"/>
<path d="M113.2 130h2v6h-2zM119.8 133.5h4M119.8 132.5h4M121.8 130.4v2.1M121.8 133.5v2M139.1 124.4h6v2h-6zM113.2 145.2h2v6h-2z"/>
</g>
<path d="M58.3 77.1h15.2v15.2h-15.2z" fill-rule="evenodd" fill="#ffffb0"/>
<path d="M58.3 77.1h15.2v15.2h-15.2z" fill="none" stroke="#800000" stroke-width=".21"/>
<g fill="none" stroke="#000" stroke-width=".25">
<path d="M50.7 79.6h7.6M73.5 79.6h7.7M83.7 79.6h2.5M96.4 79.6h2.5M137 79.6h2M145.2 79.6h2M22.7 82.2v2.5M22.7 89.8v2.5M32.9 84.7h2M41.1 84.7h2M50.7 84.7h7.6M50.7 89.8h7.6"/>
<path d="M73.5 84.7h7.7M73.5 89.8h7.7M106.6 82.2v2.5M106.6 89.8v2.5M114.2 82.2v2M114.2 90.3v2M114.2 97.4v2M121.8 82.2v2.5M121.8 89.8v2.5M114.2 105.6v2"/>
</g>
<g fill="none" stroke="#800000" stroke-width=".25">
<path d="M16.4 74.5h2.5M17.7 74.5v2.6M151 74.5h2.5M152.3 74.5v2.6M20.2 97.4h5.1M21 98.2h3.5M21.7 98.9h2.1M22.5 99.7h.5M22.7 94.9v2.5M45.6 97.4h5.1M46.4 98.2h3.5M47.1 98.9h2.1"/>
<path d="M47.9 99.7h.5M48.1 94.9v2.5M119.3 97.4h5M120 98.2h3.6M120.8 98.9h2M121.5 99.7h.6M121.8 94.9v2.5M111.6 112.6h5.1M112.4 113.4h3.6M113.2 114.2h2M113.9 114.9h.5M114.2 110.1v2.5"/>
<path d="M191.7 130.4h2.5M192.9 130.4v2.6"/>
</g>
<g fill="none" stroke="#00f" stroke-width=".25">
<path d="M86.2 79.6a1.27 1.27 0 0 1 1.3-1.2 1.27 1.27 0 0 1 1.3 1.2 1.27 1.27 0 0 1 1.2-1.2 1.27 1.27 0 0 1 1.3 1.2 1.27 1.27 0 0 1 1.3-1.2 1.27 1.27 0 0 1 1.3 1.2 1.27 1.27 0 0 1 1.2-1.2 1.27 1.27 0 0 1 1.3 1.2M86.2 77.6h10.2M86.2 77.1h10.2M139.1 78.7h6v2h-6zM20.7 87.7h4M20.7 86.7h4M22.7 84.7v2M22.7 87.7v2.1M35 83.7h6v2h-6zM104.6 87.7h4M104.6 86.7h4M106.6 84.7v2"/>
<path d="M106.6 87.7v2.1M113.2 99.5h2v6h-2zM113.2 84.2h2v6h-2zM119.8 87.7h4M119.8 86.7h4M121.8 84.7v2M121.8 87.7v2.1"/>
</g>
<path d="M80.1 134.5l2.1 2M82.2 134.5l-2.1 2" fill="none" stroke="#f00" stroke-width=".21"/>
<path d="M180.2 82.2v2.5h25.4v2.5" fill="none" stroke="#000080" stroke-width=".25"/>
<circle cx="205.6" cy="84.7" r=".51" fill="#000080"/>
<circle cx="205.6" cy="84.7" r=".51" fill="none" stroke="#000080" stroke-width=".21"/>
<circle cx="185.3" cy="84.7" r=".51" fill="#000080"/>
<circle cx="185.3" cy="84.7" r=".51" fill="none" stroke="#000080" stroke-width=".21"/>
<path d="M195.5 92.3h10.1M236.1 92.3v2.6M238.6 125.3h22.9M238.6 133v2.5" fill="none" stroke="#000080" stroke-width=".25"/>
<circle cx="251.3" cy="125.4" r=".51" fill="#000080"/>
<circle cx="251.3" cy="125.4" r=".51" fill="none" stroke="#000080" stroke-width=".21"/>
<circle cx="259" cy="125.4" r=".51" fill="#000080"/>
<circle cx="259" cy="125.4" r=".51" fill="none" stroke="#000080" stroke-width=".21"/>
<path d="M253.9 84.7h-17.8v2.5M274.2 122.8v2.5h-2.5" fill="none" stroke="#000080" stroke-width=".25"/>
<circle cx="236.1" cy="84.7" r=".51" fill="#000080"/>
<circle cx="236.1" cy="84.7" r=".51" fill="none" stroke="#000080" stroke-width=".21"/>
<circle cx="246.3" cy="84.7" r=".51" fill="#000080"/>
<circle cx="246.3" cy="84.7" r=".51" fill="none" stroke="#000080" stroke-width=".21"/>
<path d="M269.1 82.2v2.5h-5.1M203.1 133h-2.6v2.5" fill="none" stroke="#000080" stroke-width=".25"/>
<circle cx="200.5" cy="133" r=".51" fill="#000080"/>
<circle cx="200.5" cy="133" r=".51" fill="none" stroke="#000080" stroke-width=".21"/>
<path d="M251.3 138v2.6M251.3 153.3v2.5" fill="none" stroke="#000080" stroke-width=".25"/>
<circle cx="251.3" cy="140.6" r=".51" fill="#000080"/>
<circle cx="251.3" cy="140.6" r=".51" fill="none" stroke="#000080" stroke-width=".21"/>
<path d="M251.3 125.3v2.6" fill="none" stroke="#000080" stroke-width=".25"/>
<circle cx="251.3" cy="125.4" r=".51" fill="#000080"/>
<circle cx="251.3" cy="125.4" r=".51" fill="none" stroke="#000080" stroke-width=".21"/>
<path d="M238.6 127.9h7.7v12.7h5v2.5" fill="none" stroke="#000080" stroke-width=".25"/>
<circle cx="251.3" cy="140.6" r=".51" fill="#000080"/>
<circle cx="251.3" cy="140.6" r=".51" fill="none" stroke="#000080" stroke-width=".21"/>
<path d="M81.2 33.9h2.5M114.2 33.9v2.5M22.7 46.6v2.5M50.7 44.1h-2.6v5M121.8 46.6v2.5" fill="none" stroke="#000080" stroke-width=".25"/>
<circle cx="114.2" cy="33.9" r=".51" fill="#000080"/>
<circle cx="114.2" cy="33.9" r=".51" fill="none" stroke="#000080" stroke-width=".21"/>
<path d="M106.6 33.9v2.5" fill="none" stroke="#000080" stroke-width=".25"/>
<circle cx="106.6" cy="33.9" r=".51" fill="#000080"/>
<circle cx="106.6" cy="33.9" r=".51" fill="none" stroke="#000080" stroke-width=".21"/>
<path d="M106.6 46.6v2.5M114.2 61.8v2.6" fill="none" stroke="#000080" stroke-width=".25"/>
<circle cx="106.6" cy="49.1" r=".51" fill="#000080"/>
<circle cx="106.6" cy="49.1" r=".51" fill="none" stroke="#000080" stroke-width=".21"/>
<path d="M132 33.9v2.5M132 46.6v2.5" fill="none" stroke="#000080" stroke-width=".25"/>
<circle cx="132" cy="33.9" r=".51" fill="#000080"/>
<circle cx="132" cy="33.9" r=".51" fill="none" stroke="#000080" stroke-width=".21"/>
<path d="M17.7 31.4v2.5h5M152.3 31.4v2.5h-5.1M81.2 44.1h10.1" fill="none" stroke="#000080" stroke-width=".25"/>
<circle cx="22.7" cy="33.9" r=".51" fill="#000080"/>
<circle cx="22.7" cy="33.9" r=".51" fill="none" stroke="#000080" stroke-width=".21"/>
<path d="M43.1 39h7.6M22.7 138v2.6M50.7 135.5h-2.6v5.1M81.2 125.3h2.5M114.2 125.3v2.6M121.8 138v2.6" fill="none" stroke="#000080" stroke-width=".25"/>
<circle cx="114.2" cy="125.4" r=".51" fill="#000080"/>
<circle cx="114.2" cy="125.4" r=".51" fill="none" stroke="#000080" stroke-width=".21"/>
<path d="M106.6 125.3v2.6" fill="none" stroke="#000080" stroke-width=".25"/>
<circle cx="106.6" cy="125.4" r=".51" fill="#000080"/>
<circle cx="106.6" cy="125.4" r=".51" fill="none" stroke="#000080" stroke-width=".21"/>
<path d="M106.6 138v2.6M114.2 153.3v2.5" fill="none" stroke="#000080" stroke-width=".25"/>
<circle cx="106.6" cy="140.6" r=".51" fill="#000080"/>
<circle cx="106.6" cy="140.6" r=".51" fill="none" stroke="#000080" stroke-width=".21"/>
<path d="M17.7 122.8v2.5h5M152.3 122.8v2.5h-5.1" fill="none" stroke="#000080" stroke-width=".25"/>
<circle cx="22.7" cy="125.4" r=".51" fill="#000080"/>
<circle cx="22.7" cy="125.4" r=".51" fill="none" stroke="#000080" stroke-width=".21"/>
<path d="M30.4 33.9v5.1h2.5" fill="none" stroke="#000080" stroke-width=".25"/>
<circle cx="30.4" cy="33.9" r=".51" fill="#000080"/>
<circle cx="30.4" cy="33.9" r=".51" fill="none" stroke="#000080" stroke-width=".21"/>
<path d="M30.4 125.3v5.1h2.5M43.1 130.4h7.6" fill="none" stroke="#000080" stroke-width=".25"/>
<circle cx="30.4" cy="125.4" r=".51" fill="#000080"/>
<circle cx="30.4" cy="125.4" r=".51" fill="none" stroke="#000080" stroke-width=".21"/>
<path d="M50.7 33.9h-28v2.5" fill="none" stroke="#000080" stroke-width=".25"/>
<circle cx="30.4" cy="33.9" r=".51" fill="#000080"/>
<circle cx="30.4" cy="33.9" r=".51" fill="none" stroke="#000080" stroke-width=".21"/>
<circle cx="22.7" cy="33.9" r=".51" fill="#000080"/>
<circle cx="22.7" cy="33.9" r=".51" fill="none" stroke="#000080" stroke-width=".21"/>
<path d="M81.2 39h17.7v10.1h15.3" fill="none" stroke="#000080" stroke-width=".25"/>
<circle cx="114.2" cy="49.1" r=".51" fill="#000080"/>
<circle cx="114.2" cy="49.1" r=".51" fill="none" stroke="#000080" stroke-width=".21"/>
<circle cx="106.6" cy="49.1" r=".51" fill="#000080"/>
<circle cx="106.6" cy="49.1" r=".51" fill="none" stroke="#000080" stroke-width=".21"/>
<path d="M98.9 33.9h22.9v2.5" fill="none" stroke="#000080" stroke-width=".25"/>
<circle cx="121.8" cy="33.9" r=".51" fill="#000080"/>
<circle cx="121.8" cy="33.9" r=".51" fill="none" stroke="#000080" stroke-width=".21"/>
<circle cx="114.2" cy="33.9" r=".51" fill="#000080"/>
<circle cx="114.2" cy="33.9" r=".51" fill="none" stroke="#000080" stroke-width=".21"/>
<circle cx="106.6" cy="33.9" r=".51" fill="#000080"/>
<circle cx="106.6" cy="33.9" r=".51" fill="none" stroke="#000080" stroke-width=".21"/>
<path d="M121.8 125.3h15.2" fill="none" stroke="#000080" stroke-width=".25"/>
<circle cx="121.8" cy="125.4" r=".51" fill="#000080"/>
<circle cx="121.8" cy="125.4" r=".51" fill="none" stroke="#000080" stroke-width=".21"/>
<path d="M121.8 33.9h15.2" fill="none" stroke="#000080" stroke-width=".25"/>
<circle cx="121.8" cy="33.9" r=".51" fill="#000080"/>
<circle cx="121.8" cy="33.9" r=".51" fill="none" stroke="#000080" stroke-width=".21"/>
<circle cx="132" cy="33.9" r=".51" fill="#000080"/>
<circle cx="132" cy="33.9" r=".51" fill="none" stroke="#000080" stroke-width=".21"/>
<path d="M114.2 46.6v5.1" fill="none" stroke="#000080" stroke-width=".25"/>
<circle cx="114.2" cy="49.1" r=".51" fill="#000080"/>
<circle cx="114.2" cy="49.1" r=".51" fill="none" stroke="#000080" stroke-width=".21"/>
<path d="M50.7 125.3h-28v2.6" fill="none" stroke="#000080" stroke-width=".25"/>
<circle cx="30.4" cy="125.4" r=".51" fill="#000080"/>
<circle cx="30.4" cy="125.4" r=".51" fill="none" stroke="#000080" stroke-width=".21"/>
<circle cx="22.7" cy="125.4" r=".51" fill="#000080"/>
<circle cx="22.7" cy="125.4" r=".51" fill="none" stroke="#000080" stroke-width=".21"/>
<path d="M81.2 130.4h17.7v10.2h15.3" fill="none" stroke="#000080" stroke-width=".25"/>
<circle cx="114.2" cy="140.6" r=".51" fill="#000080"/>
<circle cx="114.2" cy="140.6" r=".51" fill="none" stroke="#000080" stroke-width=".21"/>
<circle cx="106.6" cy="140.6" r=".51" fill="#000080"/>
<circle cx="106.6" cy="140.6" r=".51" fill="none" stroke="#000080" stroke-width=".21"/>
<path d="M98.9 125.3h22.9v2.6" fill="none" stroke="#000080" stroke-width=".25"/>
<circle cx="121.8" cy="125.4" r=".51" fill="#000080"/>
<circle cx="121.8" cy="125.4" r=".51" fill="none" stroke="#000080" stroke-width=".21"/>
<circle cx="114.2" cy="125.4" r=".51" fill="#000080"/>
<circle cx="114.2" cy="125.4" r=".51" fill="none" stroke="#000080" stroke-width=".21"/>
<circle cx="106.6" cy="125.4" r=".51" fill="#000080"/>
<circle cx="106.6" cy="125.4" r=".51" fill="none" stroke="#000080" stroke-width=".21"/>
<path d="M114.2 138v5.1" fill="none" stroke="#000080" stroke-width=".25"/>
<circle cx="114.2" cy="140.6" r=".51" fill="#000080"/>
<circle cx="114.2" cy="140.6" r=".51" fill="none" stroke="#000080" stroke-width=".21"/>
<path d="M81.2 79.6h2.5M114.2 79.6v2.6M22.7 92.3v2.6M50.7 89.8h-2.6v5.1M121.8 92.3v2.6" fill="none" stroke="#000080" stroke-width=".25"/>
<circle cx="114.2" cy="79.6" r=".51" fill="#000080"/>
<circle cx="114.2" cy="79.6" r=".51" fill="none" stroke="#000080" stroke-width=".21"/>
<path d="M106.6 79.6v2.6" fill="none" stroke="#000080" stroke-width=".25"/>
<circle cx="106.6" cy="79.6" r=".51" fill="#000080"/>
<circle cx="106.6" cy="79.6" r=".51" fill="none" stroke="#000080" stroke-width=".21"/>
<path d="M106.6 92.3v2.6M114.2 107.6v2.5" fill="none" stroke="#000080" stroke-width=".25"/>
<circle cx="106.6" cy="94.9" r=".51" fill="#000080"/>
<circle cx="106.6" cy="94.9" r=".51" fill="none" stroke="#000080" stroke-width=".21"/>
<path d="M17.7 77.1v2.5h5M152.3 77.1v2.5h-5.1M81.2 89.8h10.1" fill="none" stroke="#000080" stroke-width=".25"/>
<circle cx="22.7" cy="79.6" r=".51" fill="#000080"/>
<circle cx="22.7" cy="79.6" r=".51" fill="none" stroke="#000080" stroke-width=".21"/>
<path d="M30.4 79.6v5.1h2.5M43.1 84.7h7.6" fill="none" stroke="#000080" stroke-width=".25"/>
<circle cx="30.4" cy="79.6" r=".51" fill="#000080"/>
<circle cx="30.4" cy="79.6" r=".51" fill="none" stroke="#000080" stroke-width=".21"/>
<path d="M121.8 79.6h15.2" fill="none" stroke="#000080" stroke-width=".25"/>
<circle cx="121.8" cy="79.6" r=".51" fill="#000080"/>
<circle cx="121.8" cy="79.6" r=".51" fill="none" stroke="#000080" stroke-width=".21"/>
<path d="M50.7 79.6h-28v2.6" fill="none" stroke="#000080" stroke-width=".25"/>
<circle cx="30.4" cy="79.6" r=".51" fill="#000080"/>
<circle cx="30.4" cy="79.6" r=".51" fill="none" stroke="#000080" stroke-width=".21"/>
<circle cx="22.7" cy="79.6" r=".51" fill="#000080"/>
<circle cx="22.7" cy="79.6" r=".51" fill="none" stroke="#000080" stroke-width=".21"/>
<path d="M81.2 84.7h17.7v10.2h15.3" fill="none" stroke="#000080" stroke-width=".25"/>
<circle cx="114.2" cy="94.9" r=".51" fill="#000080"/>
<circle cx="114.2" cy="94.9" r=".51" fill="none" stroke="#000080" stroke-width=".21"/>
<circle cx="106.6" cy="94.9" r=".51" fill="#000080"/>
<circle cx="106.6" cy="94.9" r=".51" fill="none" stroke="#000080" stroke-width=".21"/>
<path d="M98.9 79.6h22.9v2.6" fill="none" stroke="#000080" stroke-width=".25"/>
<circle cx="121.8" cy="79.6" r=".51" fill="#000080"/>
<circle cx="121.8" cy="79.6" r=".51" fill="none" stroke="#000080" stroke-width=".21"/>
<circle cx="114.2" cy="79.6" r=".51" fill="#000080"/>
<circle cx="114.2" cy="79.6" r=".51" fill="none" stroke="#000080" stroke-width=".21"/>
<circle cx="106.6" cy="79.6" r=".51" fill="#000080"/>
<circle cx="106.6" cy="79.6" r=".51" fill="none" stroke="#000080" stroke-width=".21"/>
<path d="M114.2 92.3v5.1" fill="none" stroke="#000080" stroke-width=".25"/>
<circle cx="114.2" cy="94.9" r=".51" fill="#000080"/>
<circle cx="114.2" cy="94.9" r=".51" fill="none" stroke="#000080" stroke-width=".21"/>
<path d="M200.5 125.3v2.6h2.6" fill="none" stroke="#000080" stroke-width=".25"/>
<circle cx="200.5" cy="125.4" r=".51" fill="#000080"/>
<circle cx="200.5" cy="125.4" r=".51" fill="none" stroke="#000080" stroke-width=".21"/>
<path d="M192.9 133h7.6" fill="none" stroke="#000080" stroke-width=".25"/>
<circle cx="200.5" cy="133" r=".51" fill="#000080"/>
<circle cx="200.5" cy="133" r=".51" fill="none" stroke="#000080" stroke-width=".21"/>
<path d="M180.2 122.8v2.5h22.9" fill="none" stroke="#000080" stroke-width=".25"/>
<circle cx="185.3" cy="125.4" r=".51" fill="#000080"/>
<circle cx="185.3" cy="125.4" r=".51" fill="none" stroke="#000080" stroke-width=".21"/>
<circle cx="200.5" cy="125.4" r=".51" fill="#000080"/>
<circle cx="200.5" cy="125.4" r=".51" fill="none" stroke="#000080" stroke-width=".21"/>
<path d="M185.3 125.3v10.2" fill="none" stroke="#000080" stroke-width=".25"/>
<circle cx="185.3" cy="125.4" r=".51" fill="#000080"/>
<circle cx="185.3" cy="125.4" r=".51" fill="none" stroke="#000080" stroke-width=".21"/>
<g fill="none" stroke="#000" stroke-width=".25">
<path d="M116.7 178.7v2.5M109.1 183.8v2.5M190.4 183.8v2.5"/>
<circle cx="109.1" cy="182.5" r="1.27"/>
<circle cx="116.7" cy="182.5" r="1.27"/>
<circle cx="190.4" cy="182.5" r="1.27"/>
</g>
<path d="M115.5 176.1h2.5M116.7 176.1v2.6M106.6 188.8h5M107.3 189.6h3.6M108.1 190.4h2M108.8 191.1h.6M109.1 186.3v2.5M187.8 188.8h5.1M188.6 189.6h3.6M189.4 190.4h2M190.1 191.1h.5M190.4 186.3v2.5" fill="none" stroke="#800000" stroke-width=".25"/>
<use href="#words"/>
</svg>
